VERSION 5.8 ;
BUSBITCHARS "[]" ;
DIVIDERCHAR "/" ;
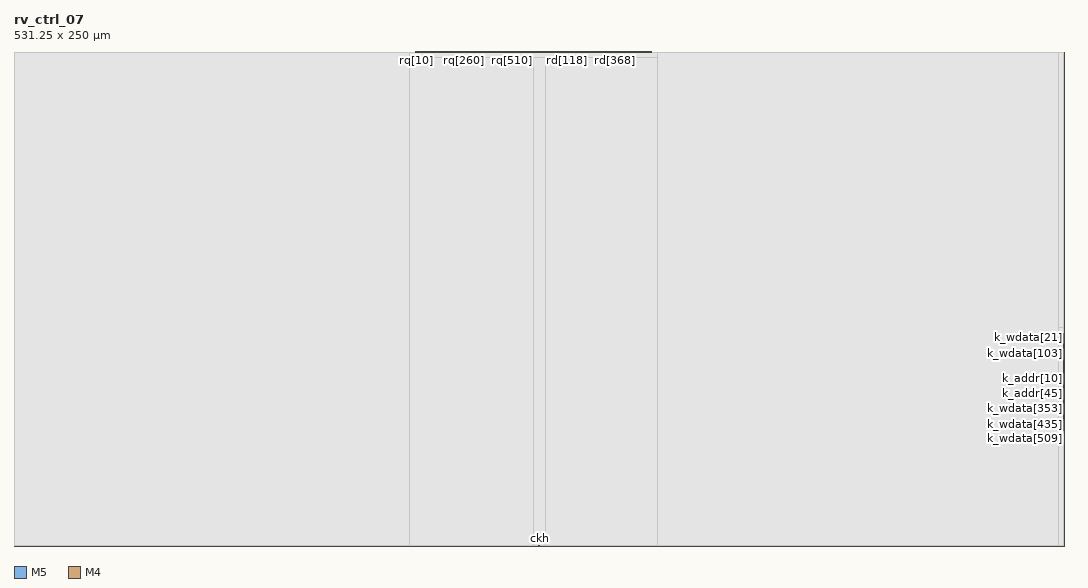
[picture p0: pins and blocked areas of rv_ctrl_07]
MACRO rv_ctrl_07
  CLASS BLOCK ;
  ORIGIN 0 0 ;
  SIZE 531.250 BY 250.000 ;
  SYMMETRY X Y ;
  PIN clk
    DIRECTION INPUT ;
    USE SIGNAL ;
    PORT
      LAYER M5 ;
        RECT 265.901 0.000 265.925 0.100 ;
    END
  END clk
  PIN ckh
    DIRECTION INPUT ;
    USE SIGNAL ;
    PORT
      LAYER M5 ;
        RECT 265.997 0.000 266.021 0.100 ;
    END
  END ckh
  PIN k_v[1]
    DIRECTION OUTPUT ;
    USE SIGNAL ;
    PORT
      LAYER M4 ;
        RECT 531.150 82.745 531.250 82.769 ;
    END
  END k_v[1]
  PIN k_v[0]
    DIRECTION OUTPUT ;
    USE SIGNAL ;
    PORT
      LAYER M4 ;
        RECT 531.150 82.841 531.250 82.865 ;
    END
  END k_v[0]
  PIN k_rdy[1]
    DIRECTION INPUT ;
    USE SIGNAL ;
    PORT
      LAYER M4 ;
        RECT 531.150 82.745 531.250 82.769 ;
    END
  END k_rdy[1]
  PIN k_rdy[0]
    DIRECTION INPUT ;
    USE SIGNAL ;
    PORT
      LAYER M4 ;
        RECT 531.150 82.841 531.250 82.865 ;
    END
  END k_rdy[0]
  PIN k_addr[59]
    DIRECTION OUTPUT ;
    USE SIGNAL ;
    PORT
      LAYER M4 ;
        RECT 531.150 79.961 531.250 79.985 ;
    END
  END k_addr[59]
  PIN k_addr[58]
    DIRECTION OUTPUT ;
    USE SIGNAL ;
    PORT
      LAYER M4 ;
        RECT 531.150 80.057 531.250 80.081 ;
    END
  END k_addr[58]
  PIN k_addr[57]
    DIRECTION OUTPUT ;
    USE SIGNAL ;
    PORT
      LAYER M4 ;
        RECT 531.150 80.153 531.250 80.177 ;
    END
  END k_addr[57]
  PIN k_addr[56]
    DIRECTION OUTPUT ;
    USE SIGNAL ;
    PORT
      LAYER M4 ;
        RECT 531.150 80.249 531.250 80.273 ;
    END
  END k_addr[56]
  PIN k_addr[55]
    DIRECTION OUTPUT ;
    USE SIGNAL ;
    PORT
      LAYER M4 ;
        RECT 531.150 80.345 531.250 80.369 ;
    END
  END k_addr[55]
  PIN k_addr[54]
    DIRECTION OUTPUT ;
    USE SIGNAL ;
    PORT
      LAYER M4 ;
        RECT 531.150 80.441 531.250 80.465 ;
    END
  END k_addr[54]
  PIN k_addr[53]
    DIRECTION OUTPUT ;
    USE SIGNAL ;
    PORT
      LAYER M4 ;
        RECT 531.150 80.537 531.250 80.561 ;
    END
  END k_addr[53]
  PIN k_addr[52]
    DIRECTION OUTPUT ;
    USE SIGNAL ;
    PORT
      LAYER M4 ;
        RECT 531.150 80.633 531.250 80.657 ;
    END
  END k_addr[52]
  PIN k_addr[51]
    DIRECTION OUTPUT ;
    USE SIGNAL ;
    PORT
      LAYER M4 ;
        RECT 531.150 80.729 531.250 80.753 ;
    END
  END k_addr[51]
  PIN k_addr[50]
    DIRECTION OUTPUT ;
    USE SIGNAL ;
    PORT
      LAYER M4 ;
        RECT 531.150 80.825 531.250 80.849 ;
    END
  END k_addr[50]
  PIN k_addr[49]
    DIRECTION OUTPUT ;
    USE SIGNAL ;
    PORT
      LAYER M4 ;
        RECT 531.150 80.921 531.250 80.945 ;
    END
  END k_addr[49]
  PIN k_addr[48]
    DIRECTION OUTPUT ;
    USE SIGNAL ;
    PORT
      LAYER M4 ;
        RECT 531.150 81.017 531.250 81.041 ;
    END
  END k_addr[48]
  PIN k_addr[47]
    DIRECTION OUTPUT ;
    USE SIGNAL ;
    PORT
      LAYER M4 ;
        RECT 531.150 81.113 531.250 81.137 ;
    END
  END k_addr[47]
  PIN k_addr[46]
    DIRECTION OUTPUT ;
    USE SIGNAL ;
    PORT
      LAYER M4 ;
        RECT 531.150 81.209 531.250 81.233 ;
    END
  END k_addr[46]
  PIN k_addr[45]
    DIRECTION OUTPUT ;
    USE SIGNAL ;
    PORT
      LAYER M4 ;
        RECT 531.150 81.305 531.250 81.329 ;
    END
  END k_addr[45]
  PIN k_addr[44]
    DIRECTION OUTPUT ;
    USE SIGNAL ;
    PORT
      LAYER M4 ;
        RECT 531.150 81.401 531.250 81.425 ;
    END
  END k_addr[44]
  PIN k_addr[43]
    DIRECTION OUTPUT ;
    USE SIGNAL ;
    PORT
      LAYER M4 ;
        RECT 531.150 81.497 531.250 81.521 ;
    END
  END k_addr[43]
  PIN k_addr[42]
    DIRECTION OUTPUT ;
    USE SIGNAL ;
    PORT
      LAYER M4 ;
        RECT 531.150 81.593 531.250 81.617 ;
    END
  END k_addr[42]
  PIN k_addr[41]
    DIRECTION OUTPUT ;
    USE SIGNAL ;
    PORT
      LAYER M4 ;
        RECT 531.150 81.689 531.250 81.713 ;
    END
  END k_addr[41]
  PIN k_addr[40]
    DIRECTION OUTPUT ;
    USE SIGNAL ;
    PORT
      LAYER M4 ;
        RECT 531.150 81.785 531.250 81.809 ;
    END
  END k_addr[40]
  PIN k_addr[39]
    DIRECTION OUTPUT ;
    USE SIGNAL ;
    PORT
      LAYER M4 ;
        RECT 531.150 81.881 531.250 81.905 ;
    END
  END k_addr[39]
  PIN k_addr[38]
    DIRECTION OUTPUT ;
    USE SIGNAL ;
    PORT
      LAYER M4 ;
        RECT 531.150 81.977 531.250 82.001 ;
    END
  END k_addr[38]
  PIN k_addr[37]
    DIRECTION OUTPUT ;
    USE SIGNAL ;
    PORT
      LAYER M4 ;
        RECT 531.150 82.073 531.250 82.097 ;
    END
  END k_addr[37]
  PIN k_addr[36]
    DIRECTION OUTPUT ;
    USE SIGNAL ;
    PORT
      LAYER M4 ;
        RECT 531.150 82.169 531.250 82.193 ;
    END
  END k_addr[36]
  PIN k_addr[35]
    DIRECTION OUTPUT ;
    USE SIGNAL ;
    PORT
      LAYER M4 ;
        RECT 531.150 82.265 531.250 82.289 ;
    END
  END k_addr[35]
  PIN k_addr[34]
    DIRECTION OUTPUT ;
    USE SIGNAL ;
    PORT
      LAYER M4 ;
        RECT 531.150 82.361 531.250 82.385 ;
    END
  END k_addr[34]
  PIN k_addr[33]
    DIRECTION OUTPUT ;
    USE SIGNAL ;
    PORT
      LAYER M4 ;
        RECT 531.150 82.457 531.250 82.481 ;
    END
  END k_addr[33]
  PIN k_addr[32]
    DIRECTION OUTPUT ;
    USE SIGNAL ;
    PORT
      LAYER M4 ;
        RECT 531.150 82.553 531.250 82.577 ;
    END
  END k_addr[32]
  PIN k_addr[31]
    DIRECTION OUTPUT ;
    USE SIGNAL ;
    PORT
      LAYER M4 ;
        RECT 531.150 82.649 531.250 82.673 ;
    END
  END k_addr[31]
  PIN k_addr[30]
    DIRECTION OUTPUT ;
    USE SIGNAL ;
    PORT
      LAYER M4 ;
        RECT 531.150 82.745 531.250 82.769 ;
    END
  END k_addr[30]
  PIN k_addr[29]
    DIRECTION OUTPUT ;
    USE SIGNAL ;
    PORT
      LAYER M4 ;
        RECT 531.150 82.841 531.250 82.865 ;
    END
  END k_addr[29]
  PIN k_addr[28]
    DIRECTION OUTPUT ;
    USE SIGNAL ;
    PORT
      LAYER M4 ;
        RECT 531.150 82.937 531.250 82.961 ;
    END
  END k_addr[28]
  PIN k_addr[27]
    DIRECTION OUTPUT ;
    USE SIGNAL ;
    PORT
      LAYER M4 ;
        RECT 531.150 83.033 531.250 83.057 ;
    END
  END k_addr[27]
  PIN k_addr[26]
    DIRECTION OUTPUT ;
    USE SIGNAL ;
    PORT
      LAYER M4 ;
        RECT 531.150 83.129 531.250 83.153 ;
    END
  END k_addr[26]
  PIN k_addr[25]
    DIRECTION OUTPUT ;
    USE SIGNAL ;
    PORT
      LAYER M4 ;
        RECT 531.150 83.225 531.250 83.249 ;
    END
  END k_addr[25]
  PIN k_addr[24]
    DIRECTION OUTPUT ;
    USE SIGNAL ;
    PORT
      LAYER M4 ;
        RECT 531.150 83.321 531.250 83.345 ;
    END
  END k_addr[24]
  PIN k_addr[23]
    DIRECTION OUTPUT ;
    USE SIGNAL ;
    PORT
      LAYER M4 ;
        RECT 531.150 83.417 531.250 83.441 ;
    END
  END k_addr[23]
  PIN k_addr[22]
    DIRECTION OUTPUT ;
    USE SIGNAL ;
    PORT
      LAYER M4 ;
        RECT 531.150 83.513 531.250 83.537 ;
    END
  END k_addr[22]
  PIN k_addr[21]
    DIRECTION OUTPUT ;
    USE SIGNAL ;
    PORT
      LAYER M4 ;
        RECT 531.150 83.609 531.250 83.633 ;
    END
  END k_addr[21]
  PIN k_addr[20]
    DIRECTION OUTPUT ;
    USE SIGNAL ;
    PORT
      LAYER M4 ;
        RECT 531.150 83.705 531.250 83.729 ;
    END
  END k_addr[20]
  PIN k_addr[19]
    DIRECTION OUTPUT ;
    USE SIGNAL ;
    PORT
      LAYER M4 ;
        RECT 531.150 83.801 531.250 83.825 ;
    END
  END k_addr[19]
  PIN k_addr[18]
    DIRECTION OUTPUT ;
    USE SIGNAL ;
    PORT
      LAYER M4 ;
        RECT 531.150 83.897 531.250 83.921 ;
    END
  END k_addr[18]
  PIN k_addr[17]
    DIRECTION OUTPUT ;
    USE SIGNAL ;
    PORT
      LAYER M4 ;
        RECT 531.150 83.993 531.250 84.017 ;
    END
  END k_addr[17]
  PIN k_addr[16]
    DIRECTION OUTPUT ;
    USE SIGNAL ;
    PORT
      LAYER M4 ;
        RECT 531.150 84.089 531.250 84.113 ;
    END
  END k_addr[16]
  PIN k_addr[15]
    DIRECTION OUTPUT ;
    USE SIGNAL ;
    PORT
      LAYER M4 ;
        RECT 531.150 84.185 531.250 84.209 ;
    END
  END k_addr[15]
  PIN k_addr[14]
    DIRECTION OUTPUT ;
    USE SIGNAL ;
    PORT
      LAYER M4 ;
        RECT 531.150 84.281 531.250 84.305 ;
    END
  END k_addr[14]
  PIN k_addr[13]
    DIRECTION OUTPUT ;
    USE SIGNAL ;
    PORT
      LAYER M4 ;
        RECT 531.150 84.377 531.250 84.401 ;
    END
  END k_addr[13]
  PIN k_addr[12]
    DIRECTION OUTPUT ;
    USE SIGNAL ;
    PORT
      LAYER M4 ;
        RECT 531.150 84.473 531.250 84.497 ;
    END
  END k_addr[12]
  PIN k_addr[11]
    DIRECTION OUTPUT ;
    USE SIGNAL ;
    PORT
      LAYER M4 ;
        RECT 531.150 84.569 531.250 84.593 ;
    END
  END k_addr[11]
  PIN k_addr[10]
    DIRECTION OUTPUT ;
    USE SIGNAL ;
    PORT
      LAYER M4 ;
        RECT 531.150 84.665 531.250 84.689 ;
    END
  END k_addr[10]
  PIN k_addr[9]
    DIRECTION OUTPUT ;
    USE SIGNAL ;
    PORT
      LAYER M4 ;
        RECT 531.150 84.761 531.250 84.785 ;
    END
  END k_addr[9]
  PIN k_addr[8]
    DIRECTION OUTPUT ;
    USE SIGNAL ;
    PORT
      LAYER M4 ;
        RECT 531.150 84.857 531.250 84.881 ;
    END
  END k_addr[8]
  PIN k_addr[7]
    DIRECTION OUTPUT ;
    USE SIGNAL ;
    PORT
      LAYER M4 ;
        RECT 531.150 84.953 531.250 84.977 ;
    END
  END k_addr[7]
  PIN k_addr[6]
    DIRECTION OUTPUT ;
    USE SIGNAL ;
    PORT
      LAYER M4 ;
        RECT 531.150 85.049 531.250 85.073 ;
    END
  END k_addr[6]
  PIN k_addr[5]
    DIRECTION OUTPUT ;
    USE SIGNAL ;
    PORT
      LAYER M4 ;
        RECT 531.150 85.145 531.250 85.169 ;
    END
  END k_addr[5]
  PIN k_addr[4]
    DIRECTION OUTPUT ;
    USE SIGNAL ;
    PORT
      LAYER M4 ;
        RECT 531.150 85.241 531.250 85.265 ;
    END
  END k_addr[4]
  PIN k_addr[3]
    DIRECTION OUTPUT ;
    USE SIGNAL ;
    PORT
      LAYER M4 ;
        RECT 531.150 85.337 531.250 85.361 ;
    END
  END k_addr[3]
  PIN k_addr[2]
    DIRECTION OUTPUT ;
    USE SIGNAL ;
    PORT
      LAYER M4 ;
        RECT 531.150 85.433 531.250 85.457 ;
    END
  END k_addr[2]
  PIN k_addr[1]
    DIRECTION OUTPUT ;
    USE SIGNAL ;
    PORT
      LAYER M4 ;
        RECT 531.150 85.529 531.250 85.553 ;
    END
  END k_addr[1]
  PIN k_addr[0]
    DIRECTION OUTPUT ;
    USE SIGNAL ;
    PORT
      LAYER M4 ;
        RECT 531.150 85.625 531.250 85.649 ;
    END
  END k_addr[0]
  PIN k_len[7]
    DIRECTION OUTPUT ;
    USE SIGNAL ;
    PORT
      LAYER M4 ;
        RECT 531.150 82.457 531.250 82.481 ;
    END
  END k_len[7]
  PIN k_len[6]
    DIRECTION OUTPUT ;
    USE SIGNAL ;
    PORT
      LAYER M4 ;
        RECT 531.150 82.553 531.250 82.577 ;
    END
  END k_len[6]
  PIN k_len[5]
    DIRECTION OUTPUT ;
    USE SIGNAL ;
    PORT
      LAYER M4 ;
        RECT 531.150 82.649 531.250 82.673 ;
    END
  END k_len[5]
  PIN k_len[4]
    DIRECTION OUTPUT ;
    USE SIGNAL ;
    PORT
      LAYER M4 ;
        RECT 531.150 82.745 531.250 82.769 ;
    END
  END k_len[4]
  PIN k_len[3]
    DIRECTION OUTPUT ;
    USE SIGNAL ;
    PORT
      LAYER M4 ;
        RECT 531.150 82.841 531.250 82.865 ;
    END
  END k_len[3]
  PIN k_len[2]
    DIRECTION OUTPUT ;
    USE SIGNAL ;
    PORT
      LAYER M4 ;
        RECT 531.150 82.937 531.250 82.961 ;
    END
  END k_len[2]
  PIN k_len[1]
    DIRECTION OUTPUT ;
    USE SIGNAL ;
    PORT
      LAYER M4 ;
        RECT 531.150 83.033 531.250 83.057 ;
    END
  END k_len[1]
  PIN k_len[0]
    DIRECTION OUTPUT ;
    USE SIGNAL ;
    PORT
      LAYER M4 ;
        RECT 531.150 83.129 531.250 83.153 ;
    END
  END k_len[0]
  PIN k_tag[33]
    DIRECTION OUTPUT ;
    USE SIGNAL ;
    PORT
      LAYER M4 ;
        RECT 531.150 81.209 531.250 81.233 ;
    END
  END k_tag[33]
  PIN k_tag[32]
    DIRECTION OUTPUT ;
    USE SIGNAL ;
    PORT
      LAYER M4 ;
        RECT 531.150 81.305 531.250 81.329 ;
    END
  END k_tag[32]
  PIN k_tag[31]
    DIRECTION OUTPUT ;
    USE SIGNAL ;
    PORT
      LAYER M4 ;
        RECT 531.150 81.401 531.250 81.425 ;
    END
  END k_tag[31]
  PIN k_tag[30]
    DIRECTION OUTPUT ;
    USE SIGNAL ;
    PORT
      LAYER M4 ;
        RECT 531.150 81.497 531.250 81.521 ;
    END
  END k_tag[30]
  PIN k_tag[29]
    DIRECTION OUTPUT ;
    USE SIGNAL ;
    PORT
      LAYER M4 ;
        RECT 531.150 81.593 531.250 81.617 ;
    END
  END k_tag[29]
  PIN k_tag[28]
    DIRECTION OUTPUT ;
    USE SIGNAL ;
    PORT
      LAYER M4 ;
        RECT 531.150 81.689 531.250 81.713 ;
    END
  END k_tag[28]
  PIN k_tag[27]
    DIRECTION OUTPUT ;
    USE SIGNAL ;
    PORT
      LAYER M4 ;
        RECT 531.150 81.785 531.250 81.809 ;
    END
  END k_tag[27]
  PIN k_tag[26]
    DIRECTION OUTPUT ;
    USE SIGNAL ;
    PORT
      LAYER M4 ;
        RECT 531.150 81.881 531.250 81.905 ;
    END
  END k_tag[26]
  PIN k_tag[25]
    DIRECTION OUTPUT ;
    USE SIGNAL ;
    PORT
      LAYER M4 ;
        RECT 531.150 81.977 531.250 82.001 ;
    END
  END k_tag[25]
  PIN k_tag[24]
    DIRECTION OUTPUT ;
    USE SIGNAL ;
    PORT
      LAYER M4 ;
        RECT 531.150 82.073 531.250 82.097 ;
    END
  END k_tag[24]
  PIN k_tag[23]
    DIRECTION OUTPUT ;
    USE SIGNAL ;
    PORT
      LAYER M4 ;
        RECT 531.150 82.169 531.250 82.193 ;
    END
  END k_tag[23]
  PIN k_tag[22]
    DIRECTION OUTPUT ;
    USE SIGNAL ;
    PORT
      LAYER M4 ;
        RECT 531.150 82.265 531.250 82.289 ;
    END
  END k_tag[22]
  PIN k_tag[21]
    DIRECTION OUTPUT ;
    USE SIGNAL ;
    PORT
      LAYER M4 ;
        RECT 531.150 82.361 531.250 82.385 ;
    END
  END k_tag[21]
  PIN k_tag[20]
    DIRECTION OUTPUT ;
    USE SIGNAL ;
    PORT
      LAYER M4 ;
        RECT 531.150 82.457 531.250 82.481 ;
    END
  END k_tag[20]
  PIN k_tag[19]
    DIRECTION OUTPUT ;
    USE SIGNAL ;
    PORT
      LAYER M4 ;
        RECT 531.150 82.553 531.250 82.577 ;
    END
  END k_tag[19]
  PIN k_tag[18]
    DIRECTION OUTPUT ;
    USE SIGNAL ;
    PORT
      LAYER M4 ;
        RECT 531.150 82.649 531.250 82.673 ;
    END
  END k_tag[18]
  PIN k_tag[17]
    DIRECTION OUTPUT ;
    USE SIGNAL ;
    PORT
      LAYER M4 ;
        RECT 531.150 82.745 531.250 82.769 ;
    END
  END k_tag[17]
  PIN k_tag[16]
    DIRECTION OUTPUT ;
    USE SIGNAL ;
    PORT
      LAYER M4 ;
        RECT 531.150 82.841 531.250 82.865 ;
    END
  END k_tag[16]
  PIN k_tag[15]
    DIRECTION OUTPUT ;
    USE SIGNAL ;
    PORT
      LAYER M4 ;
        RECT 531.150 82.937 531.250 82.961 ;
    END
  END k_tag[15]
  PIN k_tag[14]
    DIRECTION OUTPUT ;
    USE SIGNAL ;
    PORT
      LAYER M4 ;
        RECT 531.150 83.033 531.250 83.057 ;
    END
  END k_tag[14]
  PIN k_tag[13]
    DIRECTION OUTPUT ;
    USE SIGNAL ;
    PORT
      LAYER M4 ;
        RECT 531.150 83.129 531.250 83.153 ;
    END
  END k_tag[13]
  PIN k_tag[12]
    DIRECTION OUTPUT ;
    USE SIGNAL ;
    PORT
      LAYER M4 ;
        RECT 531.150 83.225 531.250 83.249 ;
    END
  END k_tag[12]
  PIN k_tag[11]
    DIRECTION OUTPUT ;
    USE SIGNAL ;
    PORT
      LAYER M4 ;
        RECT 531.150 83.321 531.250 83.345 ;
    END
  END k_tag[11]
  PIN k_tag[10]
    DIRECTION OUTPUT ;
    USE SIGNAL ;
    PORT
      LAYER M4 ;
        RECT 531.150 83.417 531.250 83.441 ;
    END
  END k_tag[10]
  PIN k_tag[9]
    DIRECTION OUTPUT ;
    USE SIGNAL ;
    PORT
      LAYER M4 ;
        RECT 531.150 83.513 531.250 83.537 ;
    END
  END k_tag[9]
  PIN k_tag[8]
    DIRECTION OUTPUT ;
    USE SIGNAL ;
    PORT
      LAYER M4 ;
        RECT 531.150 83.609 531.250 83.633 ;
    END
  END k_tag[8]
  PIN k_tag[7]
    DIRECTION OUTPUT ;
    USE SIGNAL ;
    PORT
      LAYER M4 ;
        RECT 531.150 83.705 531.250 83.729 ;
    END
  END k_tag[7]
  PIN k_tag[6]
    DIRECTION OUTPUT ;
    USE SIGNAL ;
    PORT
      LAYER M4 ;
        RECT 531.150 83.801 531.250 83.825 ;
    END
  END k_tag[6]
  PIN k_tag[5]
    DIRECTION OUTPUT ;
    USE SIGNAL ;
    PORT
      LAYER M4 ;
        RECT 531.150 83.897 531.250 83.921 ;
    END
  END k_tag[5]
  PIN k_tag[4]
    DIRECTION OUTPUT ;
    USE SIGNAL ;
    PORT
      LAYER M4 ;
        RECT 531.150 83.993 531.250 84.017 ;
    END
  END k_tag[4]
  PIN k_tag[3]
    DIRECTION OUTPUT ;
    USE SIGNAL ;
    PORT
      LAYER M4 ;
        RECT 531.150 84.089 531.250 84.113 ;
    END
  END k_tag[3]
  PIN k_tag[2]
    DIRECTION OUTPUT ;
    USE SIGNAL ;
    PORT
      LAYER M4 ;
        RECT 531.150 84.185 531.250 84.209 ;
    END
  END k_tag[2]
  PIN k_tag[1]
    DIRECTION OUTPUT ;
    USE SIGNAL ;
    PORT
      LAYER M4 ;
        RECT 531.150 84.281 531.250 84.305 ;
    END
  END k_tag[1]
  PIN k_tag[0]
    DIRECTION OUTPUT ;
    USE SIGNAL ;
    PORT
      LAYER M4 ;
        RECT 531.150 84.377 531.250 84.401 ;
    END
  END k_tag[0]
  PIN k_we[1]
    DIRECTION OUTPUT ;
    USE SIGNAL ;
    PORT
      LAYER M4 ;
        RECT 531.150 82.745 531.250 82.769 ;
    END
  END k_we[1]
  PIN k_we[0]
    DIRECTION OUTPUT ;
    USE SIGNAL ;
    PORT
      LAYER M4 ;
        RECT 531.150 82.841 531.250 82.865 ;
    END
  END k_we[0]
  PIN k_wdata[511]
    DIRECTION OUTPUT ;
    USE SIGNAL ;
    PORT
      LAYER M4 ;
        RECT 531.150 58.265 531.250 58.289 ;
    END
  END k_wdata[511]
  PIN k_wdata[510]
    DIRECTION OUTPUT ;
    USE SIGNAL ;
    PORT
      LAYER M4 ;
        RECT 531.150 58.361 531.250 58.385 ;
    END
  END k_wdata[510]
  PIN k_wdata[509]
    DIRECTION OUTPUT ;
    USE SIGNAL ;
    PORT
      LAYER M4 ;
        RECT 531.150 58.457 531.250 58.481 ;
    END
  END k_wdata[509]
  PIN k_wdata[508]
    DIRECTION OUTPUT ;
    USE SIGNAL ;
    PORT
      LAYER M4 ;
        RECT 531.150 58.553 531.250 58.577 ;
    END
  END k_wdata[508]
  PIN k_wdata[507]
    DIRECTION OUTPUT ;
    USE SIGNAL ;
    PORT
      LAYER M4 ;
        RECT 531.150 58.649 531.250 58.673 ;
    END
  END k_wdata[507]
  PIN k_wdata[506]
    DIRECTION OUTPUT ;
    USE SIGNAL ;
    PORT
      LAYER M4 ;
        RECT 531.150 58.745 531.250 58.769 ;
    END
  END k_wdata[506]
  PIN k_wdata[505]
    DIRECTION OUTPUT ;
    USE SIGNAL ;
    PORT
      LAYER M4 ;
        RECT 531.150 58.841 531.250 58.865 ;
    END
  END k_wdata[505]
  PIN k_wdata[504]
    DIRECTION OUTPUT ;
    USE SIGNAL ;
    PORT
      LAYER M4 ;
        RECT 531.150 58.937 531.250 58.961 ;
    END
  END k_wdata[504]
  PIN k_wdata[503]
    DIRECTION OUTPUT ;
    USE SIGNAL ;
    PORT
      LAYER M4 ;
        RECT 531.150 59.033 531.250 59.057 ;
    END
  END k_wdata[503]
  PIN k_wdata[502]
    DIRECTION OUTPUT ;
    USE SIGNAL ;
    PORT
      LAYER M4 ;
        RECT 531.150 59.129 531.250 59.153 ;
    END
  END k_wdata[502]
  PIN k_wdata[501]
    DIRECTION OUTPUT ;
    USE SIGNAL ;
    PORT
      LAYER M4 ;
        RECT 531.150 59.225 531.250 59.249 ;
    END
  END k_wdata[501]
  PIN k_wdata[500]
    DIRECTION OUTPUT ;
    USE SIGNAL ;
    PORT
      LAYER M4 ;
        RECT 531.150 59.321 531.250 59.345 ;
    END
  END k_wdata[500]
  PIN k_wdata[499]
    DIRECTION OUTPUT ;
    USE SIGNAL ;
    PORT
      LAYER M4 ;
        RECT 531.150 59.417 531.250 59.441 ;
    END
  END k_wdata[499]
  PIN k_wdata[498]
    DIRECTION OUTPUT ;
    USE SIGNAL ;
    PORT
      LAYER M4 ;
        RECT 531.150 59.513 531.250 59.537 ;
    END
  END k_wdata[498]
  PIN k_wdata[497]
    DIRECTION OUTPUT ;
    USE SIGNAL ;
    PORT
      LAYER M4 ;
        RECT 531.150 59.609 531.250 59.633 ;
    END
  END k_wdata[497]
  PIN k_wdata[496]
    DIRECTION OUTPUT ;
    USE SIGNAL ;
    PORT
      LAYER M4 ;
        RECT 531.150 59.705 531.250 59.729 ;
    END
  END k_wdata[496]
  PIN k_wdata[495]
    DIRECTION OUTPUT ;
    USE SIGNAL ;
    PORT
      LAYER M4 ;
        RECT 531.150 59.801 531.250 59.825 ;
    END
  END k_wdata[495]
  PIN k_wdata[494]
    DIRECTION OUTPUT ;
    USE SIGNAL ;
    PORT
      LAYER M4 ;
        RECT 531.150 59.897 531.250 59.921 ;
    END
  END k_wdata[494]
  PIN k_wdata[493]
    DIRECTION OUTPUT ;
    USE SIGNAL ;
    PORT
      LAYER M4 ;
        RECT 531.150 59.993 531.250 60.017 ;
    END
  END k_wdata[493]
  PIN k_wdata[492]
    DIRECTION OUTPUT ;
    USE SIGNAL ;
    PORT
      LAYER M4 ;
        RECT 531.150 60.089 531.250 60.113 ;
    END
  END k_wdata[492]
  PIN k_wdata[491]
    DIRECTION OUTPUT ;
    USE SIGNAL ;
    PORT
      LAYER M4 ;
        RECT 531.150 60.185 531.250 60.209 ;
    END
  END k_wdata[491]
  PIN k_wdata[490]
    DIRECTION OUTPUT ;
    USE SIGNAL ;
    PORT
      LAYER M4 ;
        RECT 531.150 60.281 531.250 60.305 ;
    END
  END k_wdata[490]
  PIN k_wdata[489]
    DIRECTION OUTPUT ;
    USE SIGNAL ;
    PORT
      LAYER M4 ;
        RECT 531.150 60.377 531.250 60.401 ;
    END
  END k_wdata[489]
  PIN k_wdata[488]
    DIRECTION OUTPUT ;
    USE SIGNAL ;
    PORT
      LAYER M4 ;
        RECT 531.150 60.473 531.250 60.497 ;
    END
  END k_wdata[488]
  PIN k_wdata[487]
    DIRECTION OUTPUT ;
    USE SIGNAL ;
    PORT
      LAYER M4 ;
        RECT 531.150 60.569 531.250 60.593 ;
    END
  END k_wdata[487]
  PIN k_wdata[486]
    DIRECTION OUTPUT ;
    USE SIGNAL ;
    PORT
      LAYER M4 ;
        RECT 531.150 60.665 531.250 60.689 ;
    END
  END k_wdata[486]
  PIN k_wdata[485]
    DIRECTION OUTPUT ;
    USE SIGNAL ;
    PORT
      LAYER M4 ;
        RECT 531.150 60.761 531.250 60.785 ;
    END
  END k_wdata[485]
  PIN k_wdata[484]
    DIRECTION OUTPUT ;
    USE SIGNAL ;
    PORT
      LAYER M4 ;
        RECT 531.150 60.857 531.250 60.881 ;
    END
  END k_wdata[484]
  PIN k_wdata[483]
    DIRECTION OUTPUT ;
    USE SIGNAL ;
    PORT
      LAYER M4 ;
        RECT 531.150 60.953 531.250 60.977 ;
    END
  END k_wdata[483]
  PIN k_wdata[482]
    DIRECTION OUTPUT ;
    USE SIGNAL ;
    PORT
      LAYER M4 ;
        RECT 531.150 61.049 531.250 61.073 ;
    END
  END k_wdata[482]
  PIN k_wdata[481]
    DIRECTION OUTPUT ;
    USE SIGNAL ;
    PORT
      LAYER M4 ;
        RECT 531.150 61.145 531.250 61.169 ;
    END
  END k_wdata[481]
  PIN k_wdata[480]
    DIRECTION OUTPUT ;
    USE SIGNAL ;
    PORT
      LAYER M4 ;
        RECT 531.150 61.241 531.250 61.265 ;
    END
  END k_wdata[480]
  PIN k_wdata[479]
    DIRECTION OUTPUT ;
    USE SIGNAL ;
    PORT
      LAYER M4 ;
        RECT 531.150 61.337 531.250 61.361 ;
    END
  END k_wdata[479]
  PIN k_wdata[478]
    DIRECTION OUTPUT ;
    USE SIGNAL ;
    PORT
      LAYER M4 ;
        RECT 531.150 61.433 531.250 61.457 ;
    END
  END k_wdata[478]
  PIN k_wdata[477]
    DIRECTION OUTPUT ;
    USE SIGNAL ;
    PORT
      LAYER M4 ;
        RECT 531.150 61.529 531.250 61.553 ;
    END
  END k_wdata[477]
  PIN k_wdata[476]
    DIRECTION OUTPUT ;
    USE SIGNAL ;
    PORT
      LAYER M4 ;
        RECT 531.150 61.625 531.250 61.649 ;
    END
  END k_wdata[476]
  PIN k_wdata[475]
    DIRECTION OUTPUT ;
    USE SIGNAL ;
    PORT
      LAYER M4 ;
        RECT 531.150 61.721 531.250 61.745 ;
    END
  END k_wdata[475]
  PIN k_wdata[474]
    DIRECTION OUTPUT ;
    USE SIGNAL ;
    PORT
      LAYER M4 ;
        RECT 531.150 61.817 531.250 61.841 ;
    END
  END k_wdata[474]
  PIN k_wdata[473]
    DIRECTION OUTPUT ;
    USE SIGNAL ;
    PORT
      LAYER M4 ;
        RECT 531.150 61.913 531.250 61.937 ;
    END
  END k_wdata[473]
  PIN k_wdata[472]
    DIRECTION OUTPUT ;
    USE SIGNAL ;
    PORT
      LAYER M4 ;
        RECT 531.150 62.009 531.250 62.033 ;
    END
  END k_wdata[472]
  PIN k_wdata[471]
    DIRECTION OUTPUT ;
    USE SIGNAL ;
    PORT
      LAYER M4 ;
        RECT 531.150 62.105 531.250 62.129 ;
    END
  END k_wdata[471]
  PIN k_wdata[470]
    DIRECTION OUTPUT ;
    USE SIGNAL ;
    PORT
      LAYER M4 ;
        RECT 531.150 62.201 531.250 62.225 ;
    END
  END k_wdata[470]
  PIN k_wdata[469]
    DIRECTION OUTPUT ;
    USE SIGNAL ;
    PORT
      LAYER M4 ;
        RECT 531.150 62.297 531.250 62.321 ;
    END
  END k_wdata[469]
  PIN k_wdata[468]
    DIRECTION OUTPUT ;
    USE SIGNAL ;
    PORT
      LAYER M4 ;
        RECT 531.150 62.393 531.250 62.417 ;
    END
  END k_wdata[468]
  PIN k_wdata[467]
    DIRECTION OUTPUT ;
    USE SIGNAL ;
    PORT
      LAYER M4 ;
        RECT 531.150 62.489 531.250 62.513 ;
    END
  END k_wdata[467]
  PIN k_wdata[466]
    DIRECTION OUTPUT ;
    USE SIGNAL ;
    PORT
      LAYER M4 ;
        RECT 531.150 62.585 531.250 62.609 ;
    END
  END k_wdata[466]
  PIN k_wdata[465]
    DIRECTION OUTPUT ;
    USE SIGNAL ;
    PORT
      LAYER M4 ;
        RECT 531.150 62.681 531.250 62.705 ;
    END
  END k_wdata[465]
  PIN k_wdata[464]
    DIRECTION OUTPUT ;
    USE SIGNAL ;
    PORT
      LAYER M4 ;
        RECT 531.150 62.777 531.250 62.801 ;
    END
  END k_wdata[464]
  PIN k_wdata[463]
    DIRECTION OUTPUT ;
    USE SIGNAL ;
    PORT
      LAYER M4 ;
        RECT 531.150 62.873 531.250 62.897 ;
    END
  END k_wdata[463]
  PIN k_wdata[462]
    DIRECTION OUTPUT ;
    USE SIGNAL ;
    PORT
      LAYER M4 ;
        RECT 531.150 62.969 531.250 62.993 ;
    END
  END k_wdata[462]
  PIN k_wdata[461]
    DIRECTION OUTPUT ;
    USE SIGNAL ;
    PORT
      LAYER M4 ;
        RECT 531.150 63.065 531.250 63.089 ;
    END
  END k_wdata[461]
  PIN k_wdata[460]
    DIRECTION OUTPUT ;
    USE SIGNAL ;
    PORT
      LAYER M4 ;
        RECT 531.150 63.161 531.250 63.185 ;
    END
  END k_wdata[460]
  PIN k_wdata[459]
    DIRECTION OUTPUT ;
    USE SIGNAL ;
    PORT
      LAYER M4 ;
        RECT 531.150 63.257 531.250 63.281 ;
    END
  END k_wdata[459]
  PIN k_wdata[458]
    DIRECTION OUTPUT ;
    USE SIGNAL ;
    PORT
      LAYER M4 ;
        RECT 531.150 63.353 531.250 63.377 ;
    END
  END k_wdata[458]
  PIN k_wdata[457]
    DIRECTION OUTPUT ;
    USE SIGNAL ;
    PORT
      LAYER M4 ;
        RECT 531.150 63.449 531.250 63.473 ;
    END
  END k_wdata[457]
  PIN k_wdata[456]
    DIRECTION OUTPUT ;
    USE SIGNAL ;
    PORT
      LAYER M4 ;
        RECT 531.150 63.545 531.250 63.569 ;
    END
  END k_wdata[456]
  PIN k_wdata[455]
    DIRECTION OUTPUT ;
    USE SIGNAL ;
    PORT
      LAYER M4 ;
        RECT 531.150 63.641 531.250 63.665 ;
    END
  END k_wdata[455]
  PIN k_wdata[454]
    DIRECTION OUTPUT ;
    USE SIGNAL ;
    PORT
      LAYER M4 ;
        RECT 531.150 63.737 531.250 63.761 ;
    END
  END k_wdata[454]
  PIN k_wdata[453]
    DIRECTION OUTPUT ;
    USE SIGNAL ;
    PORT
      LAYER M4 ;
        RECT 531.150 63.833 531.250 63.857 ;
    END
  END k_wdata[453]
  PIN k_wdata[452]
    DIRECTION OUTPUT ;
    USE SIGNAL ;
    PORT
      LAYER M4 ;
        RECT 531.150 63.929 531.250 63.953 ;
    END
  END k_wdata[452]
  PIN k_wdata[451]
    DIRECTION OUTPUT ;
    USE SIGNAL ;
    PORT
      LAYER M4 ;
        RECT 531.150 64.025 531.250 64.049 ;
    END
  END k_wdata[451]
  PIN k_wdata[450]
    DIRECTION OUTPUT ;
    USE SIGNAL ;
    PORT
      LAYER M4 ;
        RECT 531.150 64.121 531.250 64.145 ;
    END
  END k_wdata[450]
  PIN k_wdata[449]
    DIRECTION OUTPUT ;
    USE SIGNAL ;
    PORT
      LAYER M4 ;
        RECT 531.150 64.217 531.250 64.241 ;
    END
  END k_wdata[449]
  PIN k_wdata[448]
    DIRECTION OUTPUT ;
    USE SIGNAL ;
    PORT
      LAYER M4 ;
        RECT 531.150 64.313 531.250 64.337 ;
    END
  END k_wdata[448]
  PIN k_wdata[447]
    DIRECTION OUTPUT ;
    USE SIGNAL ;
    PORT
      LAYER M4 ;
        RECT 531.150 64.409 531.250 64.433 ;
    END
  END k_wdata[447]
  PIN k_wdata[446]
    DIRECTION OUTPUT ;
    USE SIGNAL ;
    PORT
      LAYER M4 ;
        RECT 531.150 64.505 531.250 64.529 ;
    END
  END k_wdata[446]
  PIN k_wdata[445]
    DIRECTION OUTPUT ;
    USE SIGNAL ;
    PORT
      LAYER M4 ;
        RECT 531.150 64.601 531.250 64.625 ;
    END
  END k_wdata[445]
  PIN k_wdata[444]
    DIRECTION OUTPUT ;
    USE SIGNAL ;
    PORT
      LAYER M4 ;
        RECT 531.150 64.697 531.250 64.721 ;
    END
  END k_wdata[444]
  PIN k_wdata[443]
    DIRECTION OUTPUT ;
    USE SIGNAL ;
    PORT
      LAYER M4 ;
        RECT 531.150 64.793 531.250 64.817 ;
    END
  END k_wdata[443]
  PIN k_wdata[442]
    DIRECTION OUTPUT ;
    USE SIGNAL ;
    PORT
      LAYER M4 ;
        RECT 531.150 64.889 531.250 64.913 ;
    END
  END k_wdata[442]
  PIN k_wdata[441]
    DIRECTION OUTPUT ;
    USE SIGNAL ;
    PORT
      LAYER M4 ;
        RECT 531.150 64.985 531.250 65.009 ;
    END
  END k_wdata[441]
  PIN k_wdata[440]
    DIRECTION OUTPUT ;
    USE SIGNAL ;
    PORT
      LAYER M4 ;
        RECT 531.150 65.081 531.250 65.105 ;
    END
  END k_wdata[440]
  PIN k_wdata[439]
    DIRECTION OUTPUT ;
    USE SIGNAL ;
    PORT
      LAYER M4 ;
        RECT 531.150 65.177 531.250 65.201 ;
    END
  END k_wdata[439]
  PIN k_wdata[438]
    DIRECTION OUTPUT ;
    USE SIGNAL ;
    PORT
      LAYER M4 ;
        RECT 531.150 65.273 531.250 65.297 ;
    END
  END k_wdata[438]
  PIN k_wdata[437]
    DIRECTION OUTPUT ;
    USE SIGNAL ;
    PORT
      LAYER M4 ;
        RECT 531.150 65.369 531.250 65.393 ;
    END
  END k_wdata[437]
  PIN k_wdata[436]
    DIRECTION OUTPUT ;
    USE SIGNAL ;
    PORT
      LAYER M4 ;
        RECT 531.150 65.465 531.250 65.489 ;
    END
  END k_wdata[436]
  PIN k_wdata[435]
    DIRECTION OUTPUT ;
    USE SIGNAL ;
    PORT
      LAYER M4 ;
        RECT 531.150 65.561 531.250 65.585 ;
    END
  END k_wdata[435]
  PIN k_wdata[434]
    DIRECTION OUTPUT ;
    USE SIGNAL ;
    PORT
      LAYER M4 ;
        RECT 531.150 65.657 531.250 65.681 ;
    END
  END k_wdata[434]
  PIN k_wdata[433]
    DIRECTION OUTPUT ;
    USE SIGNAL ;
    PORT
      LAYER M4 ;
        RECT 531.150 65.753 531.250 65.777 ;
    END
  END k_wdata[433]
  PIN k_wdata[432]
    DIRECTION OUTPUT ;
    USE SIGNAL ;
    PORT
      LAYER M4 ;
        RECT 531.150 65.849 531.250 65.873 ;
    END
  END k_wdata[432]
  PIN k_wdata[431]
    DIRECTION OUTPUT ;
    USE SIGNAL ;
    PORT
      LAYER M4 ;
        RECT 531.150 65.945 531.250 65.969 ;
    END
  END k_wdata[431]
  PIN k_wdata[430]
    DIRECTION OUTPUT ;
    USE SIGNAL ;
    PORT
      LAYER M4 ;
        RECT 531.150 66.041 531.250 66.065 ;
    END
  END k_wdata[430]
  PIN k_wdata[429]
    DIRECTION OUTPUT ;
    USE SIGNAL ;
    PORT
      LAYER M4 ;
        RECT 531.150 66.137 531.250 66.161 ;
    END
  END k_wdata[429]
  PIN k_wdata[428]
    DIRECTION OUTPUT ;
    USE SIGNAL ;
    PORT
      LAYER M4 ;
        RECT 531.150 66.233 531.250 66.257 ;
    END
  END k_wdata[428]
  PIN k_wdata[427]
    DIRECTION OUTPUT ;
    USE SIGNAL ;
    PORT
      LAYER M4 ;
        RECT 531.150 66.329 531.250 66.353 ;
    END
  END k_wdata[427]
  PIN k_wdata[426]
    DIRECTION OUTPUT ;
    USE SIGNAL ;
    PORT
      LAYER M4 ;
        RECT 531.150 66.425 531.250 66.449 ;
    END
  END k_wdata[426]
  PIN k_wdata[425]
    DIRECTION OUTPUT ;
    USE SIGNAL ;
    PORT
      LAYER M4 ;
        RECT 531.150 66.521 531.250 66.545 ;
    END
  END k_wdata[425]
  PIN k_wdata[424]
    DIRECTION OUTPUT ;
    USE SIGNAL ;
    PORT
      LAYER M4 ;
        RECT 531.150 66.617 531.250 66.641 ;
    END
  END k_wdata[424]
  PIN k_wdata[423]
    DIRECTION OUTPUT ;
    USE SIGNAL ;
    PORT
      LAYER M4 ;
        RECT 531.150 66.713 531.250 66.737 ;
    END
  END k_wdata[423]
  PIN k_wdata[422]
    DIRECTION OUTPUT ;
    USE SIGNAL ;
    PORT
      LAYER M4 ;
        RECT 531.150 66.809 531.250 66.833 ;
    END
  END k_wdata[422]
  PIN k_wdata[421]
    DIRECTION OUTPUT ;
    USE SIGNAL ;
    PORT
      LAYER M4 ;
        RECT 531.150 66.905 531.250 66.929 ;
    END
  END k_wdata[421]
  PIN k_wdata[420]
    DIRECTION OUTPUT ;
    USE SIGNAL ;
    PORT
      LAYER M4 ;
        RECT 531.150 67.001 531.250 67.025 ;
    END
  END k_wdata[420]
  PIN k_wdata[419]
    DIRECTION OUTPUT ;
    USE SIGNAL ;
    PORT
      LAYER M4 ;
        RECT 531.150 67.097 531.250 67.121 ;
    END
  END k_wdata[419]
  PIN k_wdata[418]
    DIRECTION OUTPUT ;
    USE SIGNAL ;
    PORT
      LAYER M4 ;
        RECT 531.150 67.193 531.250 67.217 ;
    END
  END k_wdata[418]
  PIN k_wdata[417]
    DIRECTION OUTPUT ;
    USE SIGNAL ;
    PORT
      LAYER M4 ;
        RECT 531.150 67.289 531.250 67.313 ;
    END
  END k_wdata[417]
  PIN k_wdata[416]
    DIRECTION OUTPUT ;
    USE SIGNAL ;
    PORT
      LAYER M4 ;
        RECT 531.150 67.385 531.250 67.409 ;
    END
  END k_wdata[416]
  PIN k_wdata[415]
    DIRECTION OUTPUT ;
    USE SIGNAL ;
    PORT
      LAYER M4 ;
        RECT 531.150 67.481 531.250 67.505 ;
    END
  END k_wdata[415]
  PIN k_wdata[414]
    DIRECTION OUTPUT ;
    USE SIGNAL ;
    PORT
      LAYER M4 ;
        RECT 531.150 67.577 531.250 67.601 ;
    END
  END k_wdata[414]
  PIN k_wdata[413]
    DIRECTION OUTPUT ;
    USE SIGNAL ;
    PORT
      LAYER M4 ;
        RECT 531.150 67.673 531.250 67.697 ;
    END
  END k_wdata[413]
  PIN k_wdata[412]
    DIRECTION OUTPUT ;
    USE SIGNAL ;
    PORT
      LAYER M4 ;
        RECT 531.150 67.769 531.250 67.793 ;
    END
  END k_wdata[412]
  PIN k_wdata[411]
    DIRECTION OUTPUT ;
    USE SIGNAL ;
    PORT
      LAYER M4 ;
        RECT 531.150 67.865 531.250 67.889 ;
    END
  END k_wdata[411]
  PIN k_wdata[410]
    DIRECTION OUTPUT ;
    USE SIGNAL ;
    PORT
      LAYER M4 ;
        RECT 531.150 67.961 531.250 67.985 ;
    END
  END k_wdata[410]
  PIN k_wdata[409]
    DIRECTION OUTPUT ;
    USE SIGNAL ;
    PORT
      LAYER M4 ;
        RECT 531.150 68.057 531.250 68.081 ;
    END
  END k_wdata[409]
  PIN k_wdata[408]
    DIRECTION OUTPUT ;
    USE SIGNAL ;
    PORT
      LAYER M4 ;
        RECT 531.150 68.153 531.250 68.177 ;
    END
  END k_wdata[408]
  PIN k_wdata[407]
    DIRECTION OUTPUT ;
    USE SIGNAL ;
    PORT
      LAYER M4 ;
        RECT 531.150 68.249 531.250 68.273 ;
    END
  END k_wdata[407]
  PIN k_wdata[406]
    DIRECTION OUTPUT ;
    USE SIGNAL ;
    PORT
      LAYER M4 ;
        RECT 531.150 68.345 531.250 68.369 ;
    END
  END k_wdata[406]
  PIN k_wdata[405]
    DIRECTION OUTPUT ;
    USE SIGNAL ;
    PORT
      LAYER M4 ;
        RECT 531.150 68.441 531.250 68.465 ;
    END
  END k_wdata[405]
  PIN k_wdata[404]
    DIRECTION OUTPUT ;
    USE SIGNAL ;
    PORT
      LAYER M4 ;
        RECT 531.150 68.537 531.250 68.561 ;
    END
  END k_wdata[404]
  PIN k_wdata[403]
    DIRECTION OUTPUT ;
    USE SIGNAL ;
    PORT
      LAYER M4 ;
        RECT 531.150 68.633 531.250 68.657 ;
    END
  END k_wdata[403]
  PIN k_wdata[402]
    DIRECTION OUTPUT ;
    USE SIGNAL ;
    PORT
      LAYER M4 ;
        RECT 531.150 68.729 531.250 68.753 ;
    END
  END k_wdata[402]
  PIN k_wdata[401]
    DIRECTION OUTPUT ;
    USE SIGNAL ;
    PORT
      LAYER M4 ;
        RECT 531.150 68.825 531.250 68.849 ;
    END
  END k_wdata[401]
  PIN k_wdata[400]
    DIRECTION OUTPUT ;
    USE SIGNAL ;
    PORT
      LAYER M4 ;
        RECT 531.150 68.921 531.250 68.945 ;
    END
  END k_wdata[400]
  PIN k_wdata[399]
    DIRECTION OUTPUT ;
    USE SIGNAL ;
    PORT
      LAYER M4 ;
        RECT 531.150 69.017 531.250 69.041 ;
    END
  END k_wdata[399]
  PIN k_wdata[398]
    DIRECTION OUTPUT ;
    USE SIGNAL ;
    PORT
      LAYER M4 ;
        RECT 531.150 69.113 531.250 69.137 ;
    END
  END k_wdata[398]
  PIN k_wdata[397]
    DIRECTION OUTPUT ;
    USE SIGNAL ;
    PORT
      LAYER M4 ;
        RECT 531.150 69.209 531.250 69.233 ;
    END
  END k_wdata[397]
  PIN k_wdata[396]
    DIRECTION OUTPUT ;
    USE SIGNAL ;
    PORT
      LAYER M4 ;
        RECT 531.150 69.305 531.250 69.329 ;
    END
  END k_wdata[396]
  PIN k_wdata[395]
    DIRECTION OUTPUT ;
    USE SIGNAL ;
    PORT
      LAYER M4 ;
        RECT 531.150 69.401 531.250 69.425 ;
    END
  END k_wdata[395]
  PIN k_wdata[394]
    DIRECTION OUTPUT ;
    USE SIGNAL ;
    PORT
      LAYER M4 ;
        RECT 531.150 69.497 531.250 69.521 ;
    END
  END k_wdata[394]
  PIN k_wdata[393]
    DIRECTION OUTPUT ;
    USE SIGNAL ;
    PORT
      LAYER M4 ;
        RECT 531.150 69.593 531.250 69.617 ;
    END
  END k_wdata[393]
  PIN k_wdata[392]
    DIRECTION OUTPUT ;
    USE SIGNAL ;
    PORT
      LAYER M4 ;
        RECT 531.150 69.689 531.250 69.713 ;
    END
  END k_wdata[392]
  PIN k_wdata[391]
    DIRECTION OUTPUT ;
    USE SIGNAL ;
    PORT
      LAYER M4 ;
        RECT 531.150 69.785 531.250 69.809 ;
    END
  END k_wdata[391]
  PIN k_wdata[390]
    DIRECTION OUTPUT ;
    USE SIGNAL ;
    PORT
      LAYER M4 ;
        RECT 531.150 69.881 531.250 69.905 ;
    END
  END k_wdata[390]
  PIN k_wdata[389]
    DIRECTION OUTPUT ;
    USE SIGNAL ;
    PORT
      LAYER M4 ;
        RECT 531.150 69.977 531.250 70.001 ;
    END
  END k_wdata[389]
  PIN k_wdata[388]
    DIRECTION OUTPUT ;
    USE SIGNAL ;
    PORT
      LAYER M4 ;
        RECT 531.150 70.073 531.250 70.097 ;
    END
  END k_wdata[388]
  PIN k_wdata[387]
    DIRECTION OUTPUT ;
    USE SIGNAL ;
    PORT
      LAYER M4 ;
        RECT 531.150 70.169 531.250 70.193 ;
    END
  END k_wdata[387]
  PIN k_wdata[386]
    DIRECTION OUTPUT ;
    USE SIGNAL ;
    PORT
      LAYER M4 ;
        RECT 531.150 70.265 531.250 70.289 ;
    END
  END k_wdata[386]
  PIN k_wdata[385]
    DIRECTION OUTPUT ;
    USE SIGNAL ;
    PORT
      LAYER M4 ;
        RECT 531.150 70.361 531.250 70.385 ;
    END
  END k_wdata[385]
  PIN k_wdata[384]
    DIRECTION OUTPUT ;
    USE SIGNAL ;
    PORT
      LAYER M4 ;
        RECT 531.150 70.457 531.250 70.481 ;
    END
  END k_wdata[384]
  PIN k_wdata[383]
    DIRECTION OUTPUT ;
    USE SIGNAL ;
    PORT
      LAYER M4 ;
        RECT 531.150 70.553 531.250 70.577 ;
    END
  END k_wdata[383]
  PIN k_wdata[382]
    DIRECTION OUTPUT ;
    USE SIGNAL ;
    PORT
      LAYER M4 ;
        RECT 531.150 70.649 531.250 70.673 ;
    END
  END k_wdata[382]
  PIN k_wdata[381]
    DIRECTION OUTPUT ;
    USE SIGNAL ;
    PORT
      LAYER M4 ;
        RECT 531.150 70.745 531.250 70.769 ;
    END
  END k_wdata[381]
  PIN k_wdata[380]
    DIRECTION OUTPUT ;
    USE SIGNAL ;
    PORT
      LAYER M4 ;
        RECT 531.150 70.841 531.250 70.865 ;
    END
  END k_wdata[380]
  PIN k_wdata[379]
    DIRECTION OUTPUT ;
    USE SIGNAL ;
    PORT
      LAYER M4 ;
        RECT 531.150 70.937 531.250 70.961 ;
    END
  END k_wdata[379]
  PIN k_wdata[378]
    DIRECTION OUTPUT ;
    USE SIGNAL ;
    PORT
      LAYER M4 ;
        RECT 531.150 71.033 531.250 71.057 ;
    END
  END k_wdata[378]
  PIN k_wdata[377]
    DIRECTION OUTPUT ;
    USE SIGNAL ;
    PORT
      LAYER M4 ;
        RECT 531.150 71.129 531.250 71.153 ;
    END
  END k_wdata[377]
  PIN k_wdata[376]
    DIRECTION OUTPUT ;
    USE SIGNAL ;
    PORT
      LAYER M4 ;
        RECT 531.150 71.225 531.250 71.249 ;
    END
  END k_wdata[376]
  PIN k_wdata[375]
    DIRECTION OUTPUT ;
    USE SIGNAL ;
    PORT
      LAYER M4 ;
        RECT 531.150 71.321 531.250 71.345 ;
    END
  END k_wdata[375]
  PIN k_wdata[374]
    DIRECTION OUTPUT ;
    USE SIGNAL ;
    PORT
      LAYER M4 ;
        RECT 531.150 71.417 531.250 71.441 ;
    END
  END k_wdata[374]
  PIN k_wdata[373]
    DIRECTION OUTPUT ;
    USE SIGNAL ;
    PORT
      LAYER M4 ;
        RECT 531.150 71.513 531.250 71.537 ;
    END
  END k_wdata[373]
  PIN k_wdata[372]
    DIRECTION OUTPUT ;
    USE SIGNAL ;
    PORT
      LAYER M4 ;
        RECT 531.150 71.609 531.250 71.633 ;
    END
  END k_wdata[372]
  PIN k_wdata[371]
    DIRECTION OUTPUT ;
    USE SIGNAL ;
    PORT
      LAYER M4 ;
        RECT 531.150 71.705 531.250 71.729 ;
    END
  END k_wdata[371]
  PIN k_wdata[370]
    DIRECTION OUTPUT ;
    USE SIGNAL ;
    PORT
      LAYER M4 ;
        RECT 531.150 71.801 531.250 71.825 ;
    END
  END k_wdata[370]
  PIN k_wdata[369]
    DIRECTION OUTPUT ;
    USE SIGNAL ;
    PORT
      LAYER M4 ;
        RECT 531.150 71.897 531.250 71.921 ;
    END
  END k_wdata[369]
  PIN k_wdata[368]
    DIRECTION OUTPUT ;
    USE SIGNAL ;
    PORT
      LAYER M4 ;
        RECT 531.150 71.993 531.250 72.017 ;
    END
  END k_wdata[368]
  PIN k_wdata[367]
    DIRECTION OUTPUT ;
    USE SIGNAL ;
    PORT
      LAYER M4 ;
        RECT 531.150 72.089 531.250 72.113 ;
    END
  END k_wdata[367]
  PIN k_wdata[366]
    DIRECTION OUTPUT ;
    USE SIGNAL ;
    PORT
      LAYER M4 ;
        RECT 531.150 72.185 531.250 72.209 ;
    END
  END k_wdata[366]
  PIN k_wdata[365]
    DIRECTION OUTPUT ;
    USE SIGNAL ;
    PORT
      LAYER M4 ;
        RECT 531.150 72.281 531.250 72.305 ;
    END
  END k_wdata[365]
  PIN k_wdata[364]
    DIRECTION OUTPUT ;
    USE SIGNAL ;
    PORT
      LAYER M4 ;
        RECT 531.150 72.377 531.250 72.401 ;
    END
  END k_wdata[364]
  PIN k_wdata[363]
    DIRECTION OUTPUT ;
    USE SIGNAL ;
    PORT
      LAYER M4 ;
        RECT 531.150 72.473 531.250 72.497 ;
    END
  END k_wdata[363]
  PIN k_wdata[362]
    DIRECTION OUTPUT ;
    USE SIGNAL ;
    PORT
      LAYER M4 ;
        RECT 531.150 72.569 531.250 72.593 ;
    END
  END k_wdata[362]
  PIN k_wdata[361]
    DIRECTION OUTPUT ;
    USE SIGNAL ;
    PORT
      LAYER M4 ;
        RECT 531.150 72.665 531.250 72.689 ;
    END
  END k_wdata[361]
  PIN k_wdata[360]
    DIRECTION OUTPUT ;
    USE SIGNAL ;
    PORT
      LAYER M4 ;
        RECT 531.150 72.761 531.250 72.785 ;
    END
  END k_wdata[360]
  PIN k_wdata[359]
    DIRECTION OUTPUT ;
    USE SIGNAL ;
    PORT
      LAYER M4 ;
        RECT 531.150 72.857 531.250 72.881 ;
    END
  END k_wdata[359]
  PIN k_wdata[358]
    DIRECTION OUTPUT ;
    USE SIGNAL ;
    PORT
      LAYER M4 ;
        RECT 531.150 72.953 531.250 72.977 ;
    END
  END k_wdata[358]
  PIN k_wdata[357]
    DIRECTION OUTPUT ;
    USE SIGNAL ;
    PORT
      LAYER M4 ;
        RECT 531.150 73.049 531.250 73.073 ;
    END
  END k_wdata[357]
  PIN k_wdata[356]
    DIRECTION OUTPUT ;
    USE SIGNAL ;
    PORT
      LAYER M4 ;
        RECT 531.150 73.145 531.250 73.169 ;
    END
  END k_wdata[356]
  PIN k_wdata[355]
    DIRECTION OUTPUT ;
    USE SIGNAL ;
    PORT
      LAYER M4 ;
        RECT 531.150 73.241 531.250 73.265 ;
    END
  END k_wdata[355]
  PIN k_wdata[354]
    DIRECTION OUTPUT ;
    USE SIGNAL ;
    PORT
      LAYER M4 ;
        RECT 531.150 73.337 531.250 73.361 ;
    END
  END k_wdata[354]
  PIN k_wdata[353]
    DIRECTION OUTPUT ;
    USE SIGNAL ;
    PORT
      LAYER M4 ;
        RECT 531.150 73.433 531.250 73.457 ;
    END
  END k_wdata[353]
  PIN k_wdata[352]
    DIRECTION OUTPUT ;
    USE SIGNAL ;
    PORT
      LAYER M4 ;
        RECT 531.150 73.529 531.250 73.553 ;
    END
  END k_wdata[352]
  PIN k_wdata[351]
    DIRECTION OUTPUT ;
    USE SIGNAL ;
    PORT
      LAYER M4 ;
        RECT 531.150 73.625 531.250 73.649 ;
    END
  END k_wdata[351]
  PIN k_wdata[350]
    DIRECTION OUTPUT ;
    USE SIGNAL ;
    PORT
      LAYER M4 ;
        RECT 531.150 73.721 531.250 73.745 ;
    END
  END k_wdata[350]
  PIN k_wdata[349]
    DIRECTION OUTPUT ;
    USE SIGNAL ;
    PORT
      LAYER M4 ;
        RECT 531.150 73.817 531.250 73.841 ;
    END
  END k_wdata[349]
  PIN k_wdata[348]
    DIRECTION OUTPUT ;
    USE SIGNAL ;
    PORT
      LAYER M4 ;
        RECT 531.150 73.913 531.250 73.937 ;
    END
  END k_wdata[348]
  PIN k_wdata[347]
    DIRECTION OUTPUT ;
    USE SIGNAL ;
    PORT
      LAYER M4 ;
        RECT 531.150 74.009 531.250 74.033 ;
    END
  END k_wdata[347]
  PIN k_wdata[346]
    DIRECTION OUTPUT ;
    USE SIGNAL ;
    PORT
      LAYER M4 ;
        RECT 531.150 74.105 531.250 74.129 ;
    END
  END k_wdata[346]
  PIN k_wdata[345]
    DIRECTION OUTPUT ;
    USE SIGNAL ;
    PORT
      LAYER M4 ;
        RECT 531.150 74.201 531.250 74.225 ;
    END
  END k_wdata[345]
  PIN k_wdata[344]
    DIRECTION OUTPUT ;
    USE SIGNAL ;
    PORT
      LAYER M4 ;
        RECT 531.150 74.297 531.250 74.321 ;
    END
  END k_wdata[344]
  PIN k_wdata[343]
    DIRECTION OUTPUT ;
    USE SIGNAL ;
    PORT
      LAYER M4 ;
        RECT 531.150 74.393 531.250 74.417 ;
    END
  END k_wdata[343]
  PIN k_wdata[342]
    DIRECTION OUTPUT ;
    USE SIGNAL ;
    PORT
      LAYER M4 ;
        RECT 531.150 74.489 531.250 74.513 ;
    END
  END k_wdata[342]
  PIN k_wdata[341]
    DIRECTION OUTPUT ;
    USE SIGNAL ;
    PORT
      LAYER M4 ;
        RECT 531.150 74.585 531.250 74.609 ;
    END
  END k_wdata[341]
  PIN k_wdata[340]
    DIRECTION OUTPUT ;
    USE SIGNAL ;
    PORT
      LAYER M4 ;
        RECT 531.150 74.681 531.250 74.705 ;
    END
  END k_wdata[340]
  PIN k_wdata[339]
    DIRECTION OUTPUT ;
    USE SIGNAL ;
    PORT
      LAYER M4 ;
        RECT 531.150 74.777 531.250 74.801 ;
    END
  END k_wdata[339]
  PIN k_wdata[338]
    DIRECTION OUTPUT ;
    USE SIGNAL ;
    PORT
      LAYER M4 ;
        RECT 531.150 74.873 531.250 74.897 ;
    END
  END k_wdata[338]
  PIN k_wdata[337]
    DIRECTION OUTPUT ;
    USE SIGNAL ;
    PORT
      LAYER M4 ;
        RECT 531.150 74.969 531.250 74.993 ;
    END
  END k_wdata[337]
  PIN k_wdata[336]
    DIRECTION OUTPUT ;
    USE SIGNAL ;
    PORT
      LAYER M4 ;
        RECT 531.150 75.065 531.250 75.089 ;
    END
  END k_wdata[336]
  PIN k_wdata[335]
    DIRECTION OUTPUT ;
    USE SIGNAL ;
    PORT
      LAYER M4 ;
        RECT 531.150 75.161 531.250 75.185 ;
    END
  END k_wdata[335]
  PIN k_wdata[334]
    DIRECTION OUTPUT ;
    USE SIGNAL ;
    PORT
      LAYER M4 ;
        RECT 531.150 75.257 531.250 75.281 ;
    END
  END k_wdata[334]
  PIN k_wdata[333]
    DIRECTION OUTPUT ;
    USE SIGNAL ;
    PORT
      LAYER M4 ;
        RECT 531.150 75.353 531.250 75.377 ;
    END
  END k_wdata[333]
  PIN k_wdata[332]
    DIRECTION OUTPUT ;
    USE SIGNAL ;
    PORT
      LAYER M4 ;
        RECT 531.150 75.449 531.250 75.473 ;
    END
  END k_wdata[332]
  PIN k_wdata[331]
    DIRECTION OUTPUT ;
    USE SIGNAL ;
    PORT
      LAYER M4 ;
        RECT 531.150 75.545 531.250 75.569 ;
    END
  END k_wdata[331]
  PIN k_wdata[330]
    DIRECTION OUTPUT ;
    USE SIGNAL ;
    PORT
      LAYER M4 ;
        RECT 531.150 75.641 531.250 75.665 ;
    END
  END k_wdata[330]
  PIN k_wdata[329]
    DIRECTION OUTPUT ;
    USE SIGNAL ;
    PORT
      LAYER M4 ;
        RECT 531.150 75.737 531.250 75.761 ;
    END
  END k_wdata[329]
  PIN k_wdata[328]
    DIRECTION OUTPUT ;
    USE SIGNAL ;
    PORT
      LAYER M4 ;
        RECT 531.150 75.833 531.250 75.857 ;
    END
  END k_wdata[328]
  PIN k_wdata[327]
    DIRECTION OUTPUT ;
    USE SIGNAL ;
    PORT
      LAYER M4 ;
        RECT 531.150 75.929 531.250 75.953 ;
    END
  END k_wdata[327]
  PIN k_wdata[326]
    DIRECTION OUTPUT ;
    USE SIGNAL ;
    PORT
      LAYER M4 ;
        RECT 531.150 76.025 531.250 76.049 ;
    END
  END k_wdata[326]
  PIN k_wdata[325]
    DIRECTION OUTPUT ;
    USE SIGNAL ;
    PORT
      LAYER M4 ;
        RECT 531.150 76.121 531.250 76.145 ;
    END
  END k_wdata[325]
  PIN k_wdata[324]
    DIRECTION OUTPUT ;
    USE SIGNAL ;
    PORT
      LAYER M4 ;
        RECT 531.150 76.217 531.250 76.241 ;
    END
  END k_wdata[324]
  PIN k_wdata[323]
    DIRECTION OUTPUT ;
    USE SIGNAL ;
    PORT
      LAYER M4 ;
        RECT 531.150 76.313 531.250 76.337 ;
    END
  END k_wdata[323]
  PIN k_wdata[322]
    DIRECTION OUTPUT ;
    USE SIGNAL ;
    PORT
      LAYER M4 ;
        RECT 531.150 76.409 531.250 76.433 ;
    END
  END k_wdata[322]
  PIN k_wdata[321]
    DIRECTION OUTPUT ;
    USE SIGNAL ;
    PORT
      LAYER M4 ;
        RECT 531.150 76.505 531.250 76.529 ;
    END
  END k_wdata[321]
  PIN k_wdata[320]
    DIRECTION OUTPUT ;
    USE SIGNAL ;
    PORT
      LAYER M4 ;
        RECT 531.150 76.601 531.250 76.625 ;
    END
  END k_wdata[320]
  PIN k_wdata[319]
    DIRECTION OUTPUT ;
    USE SIGNAL ;
    PORT
      LAYER M4 ;
        RECT 531.150 76.697 531.250 76.721 ;
    END
  END k_wdata[319]
  PIN k_wdata[318]
    DIRECTION OUTPUT ;
    USE SIGNAL ;
    PORT
      LAYER M4 ;
        RECT 531.150 76.793 531.250 76.817 ;
    END
  END k_wdata[318]
  PIN k_wdata[317]
    DIRECTION OUTPUT ;
    USE SIGNAL ;
    PORT
      LAYER M4 ;
        RECT 531.150 76.889 531.250 76.913 ;
    END
  END k_wdata[317]
  PIN k_wdata[316]
    DIRECTION OUTPUT ;
    USE SIGNAL ;
    PORT
      LAYER M4 ;
        RECT 531.150 76.985 531.250 77.009 ;
    END
  END k_wdata[316]
  PIN k_wdata[315]
    DIRECTION OUTPUT ;
    USE SIGNAL ;
    PORT
      LAYER M4 ;
        RECT 531.150 77.081 531.250 77.105 ;
    END
  END k_wdata[315]
  PIN k_wdata[314]
    DIRECTION OUTPUT ;
    USE SIGNAL ;
    PORT
      LAYER M4 ;
        RECT 531.150 77.177 531.250 77.201 ;
    END
  END k_wdata[314]
  PIN k_wdata[313]
    DIRECTION OUTPUT ;
    USE SIGNAL ;
    PORT
      LAYER M4 ;
        RECT 531.150 77.273 531.250 77.297 ;
    END
  END k_wdata[313]
  PIN k_wdata[312]
    DIRECTION OUTPUT ;
    USE SIGNAL ;
    PORT
      LAYER M4 ;
        RECT 531.150 77.369 531.250 77.393 ;
    END
  END k_wdata[312]
  PIN k_wdata[311]
    DIRECTION OUTPUT ;
    USE SIGNAL ;
    PORT
      LAYER M4 ;
        RECT 531.150 77.465 531.250 77.489 ;
    END
  END k_wdata[311]
  PIN k_wdata[310]
    DIRECTION OUTPUT ;
    USE SIGNAL ;
    PORT
      LAYER M4 ;
        RECT 531.150 77.561 531.250 77.585 ;
    END
  END k_wdata[310]
  PIN k_wdata[309]
    DIRECTION OUTPUT ;
    USE SIGNAL ;
    PORT
      LAYER M4 ;
        RECT 531.150 77.657 531.250 77.681 ;
    END
  END k_wdata[309]
  PIN k_wdata[308]
    DIRECTION OUTPUT ;
    USE SIGNAL ;
    PORT
      LAYER M4 ;
        RECT 531.150 77.753 531.250 77.777 ;
    END
  END k_wdata[308]
  PIN k_wdata[307]
    DIRECTION OUTPUT ;
    USE SIGNAL ;
    PORT
      LAYER M4 ;
        RECT 531.150 77.849 531.250 77.873 ;
    END
  END k_wdata[307]
  PIN k_wdata[306]
    DIRECTION OUTPUT ;
    USE SIGNAL ;
    PORT
      LAYER M4 ;
        RECT 531.150 77.945 531.250 77.969 ;
    END
  END k_wdata[306]
  PIN k_wdata[305]
    DIRECTION OUTPUT ;
    USE SIGNAL ;
    PORT
      LAYER M4 ;
        RECT 531.150 78.041 531.250 78.065 ;
    END
  END k_wdata[305]
  PIN k_wdata[304]
    DIRECTION OUTPUT ;
    USE SIGNAL ;
    PORT
      LAYER M4 ;
        RECT 531.150 78.137 531.250 78.161 ;
    END
  END k_wdata[304]
  PIN k_wdata[303]
    DIRECTION OUTPUT ;
    USE SIGNAL ;
    PORT
      LAYER M4 ;
        RECT 531.150 78.233 531.250 78.257 ;
    END
  END k_wdata[303]
  PIN k_wdata[302]
    DIRECTION OUTPUT ;
    USE SIGNAL ;
    PORT
      LAYER M4 ;
        RECT 531.150 78.329 531.250 78.353 ;
    END
  END k_wdata[302]
  PIN k_wdata[301]
    DIRECTION OUTPUT ;
    USE SIGNAL ;
    PORT
      LAYER M4 ;
        RECT 531.150 78.425 531.250 78.449 ;
    END
  END k_wdata[301]
  PIN k_wdata[300]
    DIRECTION OUTPUT ;
    USE SIGNAL ;
    PORT
      LAYER M4 ;
        RECT 531.150 78.521 531.250 78.545 ;
    END
  END k_wdata[300]
  PIN k_wdata[299]
    DIRECTION OUTPUT ;
    USE SIGNAL ;
    PORT
      LAYER M4 ;
        RECT 531.150 78.617 531.250 78.641 ;
    END
  END k_wdata[299]
  PIN k_wdata[298]
    DIRECTION OUTPUT ;
    USE SIGNAL ;
    PORT
      LAYER M4 ;
        RECT 531.150 78.713 531.250 78.737 ;
    END
  END k_wdata[298]
  PIN k_wdata[297]
    DIRECTION OUTPUT ;
    USE SIGNAL ;
    PORT
      LAYER M4 ;
        RECT 531.150 78.809 531.250 78.833 ;
    END
  END k_wdata[297]
  PIN k_wdata[296]
    DIRECTION OUTPUT ;
    USE SIGNAL ;
    PORT
      LAYER M4 ;
        RECT 531.150 78.905 531.250 78.929 ;
    END
  END k_wdata[296]
  PIN k_wdata[295]
    DIRECTION OUTPUT ;
    USE SIGNAL ;
    PORT
      LAYER M4 ;
        RECT 531.150 79.001 531.250 79.025 ;
    END
  END k_wdata[295]
  PIN k_wdata[294]
    DIRECTION OUTPUT ;
    USE SIGNAL ;
    PORT
      LAYER M4 ;
        RECT 531.150 79.097 531.250 79.121 ;
    END
  END k_wdata[294]
  PIN k_wdata[293]
    DIRECTION OUTPUT ;
    USE SIGNAL ;
    PORT
      LAYER M4 ;
        RECT 531.150 79.193 531.250 79.217 ;
    END
  END k_wdata[293]
  PIN k_wdata[292]
    DIRECTION OUTPUT ;
    USE SIGNAL ;
    PORT
      LAYER M4 ;
        RECT 531.150 79.289 531.250 79.313 ;
    END
  END k_wdata[292]
  PIN k_wdata[291]
    DIRECTION OUTPUT ;
    USE SIGNAL ;
    PORT
      LAYER M4 ;
        RECT 531.150 79.385 531.250 79.409 ;
    END
  END k_wdata[291]
  PIN k_wdata[290]
    DIRECTION OUTPUT ;
    USE SIGNAL ;
    PORT
      LAYER M4 ;
        RECT 531.150 79.481 531.250 79.505 ;
    END
  END k_wdata[290]
  PIN k_wdata[289]
    DIRECTION OUTPUT ;
    USE SIGNAL ;
    PORT
      LAYER M4 ;
        RECT 531.150 79.577 531.250 79.601 ;
    END
  END k_wdata[289]
  PIN k_wdata[288]
    DIRECTION OUTPUT ;
    USE SIGNAL ;
    PORT
      LAYER M4 ;
        RECT 531.150 79.673 531.250 79.697 ;
    END
  END k_wdata[288]
  PIN k_wdata[287]
    DIRECTION OUTPUT ;
    USE SIGNAL ;
    PORT
      LAYER M4 ;
        RECT 531.150 79.769 531.250 79.793 ;
    END
  END k_wdata[287]
  PIN k_wdata[286]
    DIRECTION OUTPUT ;
    USE SIGNAL ;
    PORT
      LAYER M4 ;
        RECT 531.150 79.865 531.250 79.889 ;
    END
  END k_wdata[286]
  PIN k_wdata[285]
    DIRECTION OUTPUT ;
    USE SIGNAL ;
    PORT
      LAYER M4 ;
        RECT 531.150 79.961 531.250 79.985 ;
    END
  END k_wdata[285]
  PIN k_wdata[284]
    DIRECTION OUTPUT ;
    USE SIGNAL ;
    PORT
      LAYER M4 ;
        RECT 531.150 80.057 531.250 80.081 ;
    END
  END k_wdata[284]
  PIN k_wdata[283]
    DIRECTION OUTPUT ;
    USE SIGNAL ;
    PORT
      LAYER M4 ;
        RECT 531.150 80.153 531.250 80.177 ;
    END
  END k_wdata[283]
  PIN k_wdata[282]
    DIRECTION OUTPUT ;
    USE SIGNAL ;
    PORT
      LAYER M4 ;
        RECT 531.150 80.249 531.250 80.273 ;
    END
  END k_wdata[282]
  PIN k_wdata[281]
    DIRECTION OUTPUT ;
    USE SIGNAL ;
    PORT
      LAYER M4 ;
        RECT 531.150 80.345 531.250 80.369 ;
    END
  END k_wdata[281]
  PIN k_wdata[280]
    DIRECTION OUTPUT ;
    USE SIGNAL ;
    PORT
      LAYER M4 ;
        RECT 531.150 80.441 531.250 80.465 ;
    END
  END k_wdata[280]
  PIN k_wdata[279]
    DIRECTION OUTPUT ;
    USE SIGNAL ;
    PORT
      LAYER M4 ;
        RECT 531.150 80.537 531.250 80.561 ;
    END
  END k_wdata[279]
  PIN k_wdata[278]
    DIRECTION OUTPUT ;
    USE SIGNAL ;
    PORT
      LAYER M4 ;
        RECT 531.150 80.633 531.250 80.657 ;
    END
  END k_wdata[278]
  PIN k_wdata[277]
    DIRECTION OUTPUT ;
    USE SIGNAL ;
    PORT
      LAYER M4 ;
        RECT 531.150 80.729 531.250 80.753 ;
    END
  END k_wdata[277]
  PIN k_wdata[276]
    DIRECTION OUTPUT ;
    USE SIGNAL ;
    PORT
      LAYER M4 ;
        RECT 531.150 80.825 531.250 80.849 ;
    END
  END k_wdata[276]
  PIN k_wdata[275]
    DIRECTION OUTPUT ;
    USE SIGNAL ;
    PORT
      LAYER M4 ;
        RECT 531.150 80.921 531.250 80.945 ;
    END
  END k_wdata[275]
  PIN k_wdata[274]
    DIRECTION OUTPUT ;
    USE SIGNAL ;
    PORT
      LAYER M4 ;
        RECT 531.150 81.017 531.250 81.041 ;
    END
  END k_wdata[274]
  PIN k_wdata[273]
    DIRECTION OUTPUT ;
    USE SIGNAL ;
    PORT
      LAYER M4 ;
        RECT 531.150 81.113 531.250 81.137 ;
    END
  END k_wdata[273]
  PIN k_wdata[272]
    DIRECTION OUTPUT ;
    USE SIGNAL ;
    PORT
      LAYER M4 ;
        RECT 531.150 81.209 531.250 81.233 ;
    END
  END k_wdata[272]
  PIN k_wdata[271]
    DIRECTION OUTPUT ;
    USE SIGNAL ;
    PORT
      LAYER M4 ;
        RECT 531.150 81.305 531.250 81.329 ;
    END
  END k_wdata[271]
  PIN k_wdata[270]
    DIRECTION OUTPUT ;
    USE SIGNAL ;
    PORT
      LAYER M4 ;
        RECT 531.150 81.401 531.250 81.425 ;
    END
  END k_wdata[270]
  PIN k_wdata[269]
    DIRECTION OUTPUT ;
    USE SIGNAL ;
    PORT
      LAYER M4 ;
        RECT 531.150 81.497 531.250 81.521 ;
    END
  END k_wdata[269]
  PIN k_wdata[268]
    DIRECTION OUTPUT ;
    USE SIGNAL ;
    PORT
      LAYER M4 ;
        RECT 531.150 81.593 531.250 81.617 ;
    END
  END k_wdata[268]
  PIN k_wdata[267]
    DIRECTION OUTPUT ;
    USE SIGNAL ;
    PORT
      LAYER M4 ;
        RECT 531.150 81.689 531.250 81.713 ;
    END
  END k_wdata[267]
  PIN k_wdata[266]
    DIRECTION OUTPUT ;
    USE SIGNAL ;
    PORT
      LAYER M4 ;
        RECT 531.150 81.785 531.250 81.809 ;
    END
  END k_wdata[266]
  PIN k_wdata[265]
    DIRECTION OUTPUT ;
    USE SIGNAL ;
    PORT
      LAYER M4 ;
        RECT 531.150 81.881 531.250 81.905 ;
    END
  END k_wdata[265]
  PIN k_wdata[264]
    DIRECTION OUTPUT ;
    USE SIGNAL ;
    PORT
      LAYER M4 ;
        RECT 531.150 81.977 531.250 82.001 ;
    END
  END k_wdata[264]
  PIN k_wdata[263]
    DIRECTION OUTPUT ;
    USE SIGNAL ;
    PORT
      LAYER M4 ;
        RECT 531.150 82.073 531.250 82.097 ;
    END
  END k_wdata[263]
  PIN k_wdata[262]
    DIRECTION OUTPUT ;
    USE SIGNAL ;
    PORT
      LAYER M4 ;
        RECT 531.150 82.169 531.250 82.193 ;
    END
  END k_wdata[262]
  PIN k_wdata[261]
    DIRECTION OUTPUT ;
    USE SIGNAL ;
    PORT
      LAYER M4 ;
        RECT 531.150 82.265 531.250 82.289 ;
    END
  END k_wdata[261]
  PIN k_wdata[260]
    DIRECTION OUTPUT ;
    USE SIGNAL ;
    PORT
      LAYER M4 ;
        RECT 531.150 82.361 531.250 82.385 ;
    END
  END k_wdata[260]
  PIN k_wdata[259]
    DIRECTION OUTPUT ;
    USE SIGNAL ;
    PORT
      LAYER M4 ;
        RECT 531.150 82.457 531.250 82.481 ;
    END
  END k_wdata[259]
  PIN k_wdata[258]
    DIRECTION OUTPUT ;
    USE SIGNAL ;
    PORT
      LAYER M4 ;
        RECT 531.150 82.553 531.250 82.577 ;
    END
  END k_wdata[258]
  PIN k_wdata[257]
    DIRECTION OUTPUT ;
    USE SIGNAL ;
    PORT
      LAYER M4 ;
        RECT 531.150 82.649 531.250 82.673 ;
    END
  END k_wdata[257]
  PIN k_wdata[256]
    DIRECTION OUTPUT ;
    USE SIGNAL ;
    PORT
      LAYER M4 ;
        RECT 531.150 82.745 531.250 82.769 ;
    END
  END k_wdata[256]
  PIN k_wdata[255]
    DIRECTION OUTPUT ;
    USE SIGNAL ;
    PORT
      LAYER M4 ;
        RECT 531.150 82.841 531.250 82.865 ;
    END
  END k_wdata[255]
  PIN k_wdata[254]
    DIRECTION OUTPUT ;
    USE SIGNAL ;
    PORT
      LAYER M4 ;
        RECT 531.150 82.937 531.250 82.961 ;
    END
  END k_wdata[254]
  PIN k_wdata[253]
    DIRECTION OUTPUT ;
    USE SIGNAL ;
    PORT
      LAYER M4 ;
        RECT 531.150 83.033 531.250 83.057 ;
    END
  END k_wdata[253]
  PIN k_wdata[252]
    DIRECTION OUTPUT ;
    USE SIGNAL ;
    PORT
      LAYER M4 ;
        RECT 531.150 83.129 531.250 83.153 ;
    END
  END k_wdata[252]
  PIN k_wdata[251]
    DIRECTION OUTPUT ;
    USE SIGNAL ;
    PORT
      LAYER M4 ;
        RECT 531.150 83.225 531.250 83.249 ;
    END
  END k_wdata[251]
  PIN k_wdata[250]
    DIRECTION OUTPUT ;
    USE SIGNAL ;
    PORT
      LAYER M4 ;
        RECT 531.150 83.321 531.250 83.345 ;
    END
  END k_wdata[250]
  PIN k_wdata[249]
    DIRECTION OUTPUT ;
    USE SIGNAL ;
    PORT
      LAYER M4 ;
        RECT 531.150 83.417 531.250 83.441 ;
    END
  END k_wdata[249]
  PIN k_wdata[248]
    DIRECTION OUTPUT ;
    USE SIGNAL ;
    PORT
      LAYER M4 ;
        RECT 531.150 83.513 531.250 83.537 ;
    END
  END k_wdata[248]
  PIN k_wdata[247]
    DIRECTION OUTPUT ;
    USE SIGNAL ;
    PORT
      LAYER M4 ;
        RECT 531.150 83.609 531.250 83.633 ;
    END
  END k_wdata[247]
  PIN k_wdata[246]
    DIRECTION OUTPUT ;
    USE SIGNAL ;
    PORT
      LAYER M4 ;
        RECT 531.150 83.705 531.250 83.729 ;
    END
  END k_wdata[246]
  PIN k_wdata[245]
    DIRECTION OUTPUT ;
    USE SIGNAL ;
    PORT
      LAYER M4 ;
        RECT 531.150 83.801 531.250 83.825 ;
    END
  END k_wdata[245]
  PIN k_wdata[244]
    DIRECTION OUTPUT ;
    USE SIGNAL ;
    PORT
      LAYER M4 ;
        RECT 531.150 83.897 531.250 83.921 ;
    END
  END k_wdata[244]
  PIN k_wdata[243]
    DIRECTION OUTPUT ;
    USE SIGNAL ;
    PORT
      LAYER M4 ;
        RECT 531.150 83.993 531.250 84.017 ;
    END
  END k_wdata[243]
  PIN k_wdata[242]
    DIRECTION OUTPUT ;
    USE SIGNAL ;
    PORT
      LAYER M4 ;
        RECT 531.150 84.089 531.250 84.113 ;
    END
  END k_wdata[242]
  PIN k_wdata[241]
    DIRECTION OUTPUT ;
    USE SIGNAL ;
    PORT
      LAYER M4 ;
        RECT 531.150 84.185 531.250 84.209 ;
    END
  END k_wdata[241]
  PIN k_wdata[240]
    DIRECTION OUTPUT ;
    USE SIGNAL ;
    PORT
      LAYER M4 ;
        RECT 531.150 84.281 531.250 84.305 ;
    END
  END k_wdata[240]
  PIN k_wdata[239]
    DIRECTION OUTPUT ;
    USE SIGNAL ;
    PORT
      LAYER M4 ;
        RECT 531.150 84.377 531.250 84.401 ;
    END
  END k_wdata[239]
  PIN k_wdata[238]
    DIRECTION OUTPUT ;
    USE SIGNAL ;
    PORT
      LAYER M4 ;
        RECT 531.150 84.473 531.250 84.497 ;
    END
  END k_wdata[238]
  PIN k_wdata[237]
    DIRECTION OUTPUT ;
    USE SIGNAL ;
    PORT
      LAYER M4 ;
        RECT 531.150 84.569 531.250 84.593 ;
    END
  END k_wdata[237]
  PIN k_wdata[236]
    DIRECTION OUTPUT ;
    USE SIGNAL ;
    PORT
      LAYER M4 ;
        RECT 531.150 84.665 531.250 84.689 ;
    END
  END k_wdata[236]
  PIN k_wdata[235]
    DIRECTION OUTPUT ;
    USE SIGNAL ;
    PORT
      LAYER M4 ;
        RECT 531.150 84.761 531.250 84.785 ;
    END
  END k_wdata[235]
  PIN k_wdata[234]
    DIRECTION OUTPUT ;
    USE SIGNAL ;
    PORT
      LAYER M4 ;
        RECT 531.150 84.857 531.250 84.881 ;
    END
  END k_wdata[234]
  PIN k_wdata[233]
    DIRECTION OUTPUT ;
    USE SIGNAL ;
    PORT
      LAYER M4 ;
        RECT 531.150 84.953 531.250 84.977 ;
    END
  END k_wdata[233]
  PIN k_wdata[232]
    DIRECTION OUTPUT ;
    USE SIGNAL ;
    PORT
      LAYER M4 ;
        RECT 531.150 85.049 531.250 85.073 ;
    END
  END k_wdata[232]
  PIN k_wdata[231]
    DIRECTION OUTPUT ;
    USE SIGNAL ;
    PORT
      LAYER M4 ;
        RECT 531.150 85.145 531.250 85.169 ;
    END
  END k_wdata[231]
  PIN k_wdata[230]
    DIRECTION OUTPUT ;
    USE SIGNAL ;
    PORT
      LAYER M4 ;
        RECT 531.150 85.241 531.250 85.265 ;
    END
  END k_wdata[230]
  PIN k_wdata[229]
    DIRECTION OUTPUT ;
    USE SIGNAL ;
    PORT
      LAYER M4 ;
        RECT 531.150 85.337 531.250 85.361 ;
    END
  END k_wdata[229]
  PIN k_wdata[228]
    DIRECTION OUTPUT ;
    USE SIGNAL ;
    PORT
      LAYER M4 ;
        RECT 531.150 85.433 531.250 85.457 ;
    END
  END k_wdata[228]
  PIN k_wdata[227]
    DIRECTION OUTPUT ;
    USE SIGNAL ;
    PORT
      LAYER M4 ;
        RECT 531.150 85.529 531.250 85.553 ;
    END
  END k_wdata[227]
  PIN k_wdata[226]
    DIRECTION OUTPUT ;
    USE SIGNAL ;
    PORT
      LAYER M4 ;
        RECT 531.150 85.625 531.250 85.649 ;
    END
  END k_wdata[226]
  PIN k_wdata[225]
    DIRECTION OUTPUT ;
    USE SIGNAL ;
    PORT
      LAYER M4 ;
        RECT 531.150 85.721 531.250 85.745 ;
    END
  END k_wdata[225]
  PIN k_wdata[224]
    DIRECTION OUTPUT ;
    USE SIGNAL ;
    PORT
      LAYER M4 ;
        RECT 531.150 85.817 531.250 85.841 ;
    END
  END k_wdata[224]
  PIN k_wdata[223]
    DIRECTION OUTPUT ;
    USE SIGNAL ;
    PORT
      LAYER M4 ;
        RECT 531.150 85.913 531.250 85.937 ;
    END
  END k_wdata[223]
  PIN k_wdata[222]
    DIRECTION OUTPUT ;
    USE SIGNAL ;
    PORT
      LAYER M4 ;
        RECT 531.150 86.009 531.250 86.033 ;
    END
  END k_wdata[222]
  PIN k_wdata[221]
    DIRECTION OUTPUT ;
    USE SIGNAL ;
    PORT
      LAYER M4 ;
        RECT 531.150 86.105 531.250 86.129 ;
    END
  END k_wdata[221]
  PIN k_wdata[220]
    DIRECTION OUTPUT ;
    USE SIGNAL ;
    PORT
      LAYER M4 ;
        RECT 531.150 86.201 531.250 86.225 ;
    END
  END k_wdata[220]
  PIN k_wdata[219]
    DIRECTION OUTPUT ;
    USE SIGNAL ;
    PORT
      LAYER M4 ;
        RECT 531.150 86.297 531.250 86.321 ;
    END
  END k_wdata[219]
  PIN k_wdata[218]
    DIRECTION OUTPUT ;
    USE SIGNAL ;
    PORT
      LAYER M4 ;
        RECT 531.150 86.393 531.250 86.417 ;
    END
  END k_wdata[218]
  PIN k_wdata[217]
    DIRECTION OUTPUT ;
    USE SIGNAL ;
    PORT
      LAYER M4 ;
        RECT 531.150 86.489 531.250 86.513 ;
    END
  END k_wdata[217]
  PIN k_wdata[216]
    DIRECTION OUTPUT ;
    USE SIGNAL ;
    PORT
      LAYER M4 ;
        RECT 531.150 86.585 531.250 86.609 ;
    END
  END k_wdata[216]
  PIN k_wdata[215]
    DIRECTION OUTPUT ;
    USE SIGNAL ;
    PORT
      LAYER M4 ;
        RECT 531.150 86.681 531.250 86.705 ;
    END
  END k_wdata[215]
  PIN k_wdata[214]
    DIRECTION OUTPUT ;
    USE SIGNAL ;
    PORT
      LAYER M4 ;
        RECT 531.150 86.777 531.250 86.801 ;
    END
  END k_wdata[214]
  PIN k_wdata[213]
    DIRECTION OUTPUT ;
    USE SIGNAL ;
    PORT
      LAYER M4 ;
        RECT 531.150 86.873 531.250 86.897 ;
    END
  END k_wdata[213]
  PIN k_wdata[212]
    DIRECTION OUTPUT ;
    USE SIGNAL ;
    PORT
      LAYER M4 ;
        RECT 531.150 86.969 531.250 86.993 ;
    END
  END k_wdata[212]
  PIN k_wdata[211]
    DIRECTION OUTPUT ;
    USE SIGNAL ;
    PORT
      LAYER M4 ;
        RECT 531.150 87.065 531.250 87.089 ;
    END
  END k_wdata[211]
  PIN k_wdata[210]
    DIRECTION OUTPUT ;
    USE SIGNAL ;
    PORT
      LAYER M4 ;
        RECT 531.150 87.161 531.250 87.185 ;
    END
  END k_wdata[210]
  PIN k_wdata[209]
    DIRECTION OUTPUT ;
    USE SIGNAL ;
    PORT
      LAYER M4 ;
        RECT 531.150 87.257 531.250 87.281 ;
    END
  END k_wdata[209]
  PIN k_wdata[208]
    DIRECTION OUTPUT ;
    USE SIGNAL ;
    PORT
      LAYER M4 ;
        RECT 531.150 87.353 531.250 87.377 ;
    END
  END k_wdata[208]
  PIN k_wdata[207]
    DIRECTION OUTPUT ;
    USE SIGNAL ;
    PORT
      LAYER M4 ;
        RECT 531.150 87.449 531.250 87.473 ;
    END
  END k_wdata[207]
  PIN k_wdata[206]
    DIRECTION OUTPUT ;
    USE SIGNAL ;
    PORT
      LAYER M4 ;
        RECT 531.150 87.545 531.250 87.569 ;
    END
  END k_wdata[206]
  PIN k_wdata[205]
    DIRECTION OUTPUT ;
    USE SIGNAL ;
    PORT
      LAYER M4 ;
        RECT 531.150 87.641 531.250 87.665 ;
    END
  END k_wdata[205]
  PIN k_wdata[204]
    DIRECTION OUTPUT ;
    USE SIGNAL ;
    PORT
      LAYER M4 ;
        RECT 531.150 87.737 531.250 87.761 ;
    END
  END k_wdata[204]
  PIN k_wdata[203]
    DIRECTION OUTPUT ;
    USE SIGNAL ;
    PORT
      LAYER M4 ;
        RECT 531.150 87.833 531.250 87.857 ;
    END
  END k_wdata[203]
  PIN k_wdata[202]
    DIRECTION OUTPUT ;
    USE SIGNAL ;
    PORT
      LAYER M4 ;
        RECT 531.150 87.929 531.250 87.953 ;
    END
  END k_wdata[202]
  PIN k_wdata[201]
    DIRECTION OUTPUT ;
    USE SIGNAL ;
    PORT
      LAYER M4 ;
        RECT 531.150 88.025 531.250 88.049 ;
    END
  END k_wdata[201]
  PIN k_wdata[200]
    DIRECTION OUTPUT ;
    USE SIGNAL ;
    PORT
      LAYER M4 ;
        RECT 531.150 88.121 531.250 88.145 ;
    END
  END k_wdata[200]
  PIN k_wdata[199]
    DIRECTION OUTPUT ;
    USE SIGNAL ;
    PORT
      LAYER M4 ;
        RECT 531.150 88.217 531.250 88.241 ;
    END
  END k_wdata[199]
  PIN k_wdata[198]
    DIRECTION OUTPUT ;
    USE SIGNAL ;
    PORT
      LAYER M4 ;
        RECT 531.150 88.313 531.250 88.337 ;
    END
  END k_wdata[198]
  PIN k_wdata[197]
    DIRECTION OUTPUT ;
    USE SIGNAL ;
    PORT
      LAYER M4 ;
        RECT 531.150 88.409 531.250 88.433 ;
    END
  END k_wdata[197]
  PIN k_wdata[196]
    DIRECTION OUTPUT ;
    USE SIGNAL ;
    PORT
      LAYER M4 ;
        RECT 531.150 88.505 531.250 88.529 ;
    END
  END k_wdata[196]
  PIN k_wdata[195]
    DIRECTION OUTPUT ;
    USE SIGNAL ;
    PORT
      LAYER M4 ;
        RECT 531.150 88.601 531.250 88.625 ;
    END
  END k_wdata[195]
  PIN k_wdata[194]
    DIRECTION OUTPUT ;
    USE SIGNAL ;
    PORT
      LAYER M4 ;
        RECT 531.150 88.697 531.250 88.721 ;
    END
  END k_wdata[194]
  PIN k_wdata[193]
    DIRECTION OUTPUT ;
    USE SIGNAL ;
    PORT
      LAYER M4 ;
        RECT 531.150 88.793 531.250 88.817 ;
    END
  END k_wdata[193]
  PIN k_wdata[192]
    DIRECTION OUTPUT ;
    USE SIGNAL ;
    PORT
      LAYER M4 ;
        RECT 531.150 88.889 531.250 88.913 ;
    END
  END k_wdata[192]
  PIN k_wdata[191]
    DIRECTION OUTPUT ;
    USE SIGNAL ;
    PORT
      LAYER M4 ;
        RECT 531.150 88.985 531.250 89.009 ;
    END
  END k_wdata[191]
  PIN k_wdata[190]
    DIRECTION OUTPUT ;
    USE SIGNAL ;
    PORT
      LAYER M4 ;
        RECT 531.150 89.081 531.250 89.105 ;
    END
  END k_wdata[190]
  PIN k_wdata[189]
    DIRECTION OUTPUT ;
    USE SIGNAL ;
    PORT
      LAYER M4 ;
        RECT 531.150 89.177 531.250 89.201 ;
    END
  END k_wdata[189]
  PIN k_wdata[188]
    DIRECTION OUTPUT ;
    USE SIGNAL ;
    PORT
      LAYER M4 ;
        RECT 531.150 89.273 531.250 89.297 ;
    END
  END k_wdata[188]
  PIN k_wdata[187]
    DIRECTION OUTPUT ;
    USE SIGNAL ;
    PORT
      LAYER M4 ;
        RECT 531.150 89.369 531.250 89.393 ;
    END
  END k_wdata[187]
  PIN k_wdata[186]
    DIRECTION OUTPUT ;
    USE SIGNAL ;
    PORT
      LAYER M4 ;
        RECT 531.150 89.465 531.250 89.489 ;
    END
  END k_wdata[186]
  PIN k_wdata[185]
    DIRECTION OUTPUT ;
    USE SIGNAL ;
    PORT
      LAYER M4 ;
        RECT 531.150 89.561 531.250 89.585 ;
    END
  END k_wdata[185]
  PIN k_wdata[184]
    DIRECTION OUTPUT ;
    USE SIGNAL ;
    PORT
      LAYER M4 ;
        RECT 531.150 89.657 531.250 89.681 ;
    END
  END k_wdata[184]
  PIN k_wdata[183]
    DIRECTION OUTPUT ;
    USE SIGNAL ;
    PORT
      LAYER M4 ;
        RECT 531.150 89.753 531.250 89.777 ;
    END
  END k_wdata[183]
  PIN k_wdata[182]
    DIRECTION OUTPUT ;
    USE SIGNAL ;
    PORT
      LAYER M4 ;
        RECT 531.150 89.849 531.250 89.873 ;
    END
  END k_wdata[182]
  PIN k_wdata[181]
    DIRECTION OUTPUT ;
    USE SIGNAL ;
    PORT
      LAYER M4 ;
        RECT 531.150 89.945 531.250 89.969 ;
    END
  END k_wdata[181]
  PIN k_wdata[180]
    DIRECTION OUTPUT ;
    USE SIGNAL ;
    PORT
      LAYER M4 ;
        RECT 531.150 90.041 531.250 90.065 ;
    END
  END k_wdata[180]
  PIN k_wdata[179]
    DIRECTION OUTPUT ;
    USE SIGNAL ;
    PORT
      LAYER M4 ;
        RECT 531.150 90.137 531.250 90.161 ;
    END
  END k_wdata[179]
  PIN k_wdata[178]
    DIRECTION OUTPUT ;
    USE SIGNAL ;
    PORT
      LAYER M4 ;
        RECT 531.150 90.233 531.250 90.257 ;
    END
  END k_wdata[178]
  PIN k_wdata[177]
    DIRECTION OUTPUT ;
    USE SIGNAL ;
    PORT
      LAYER M4 ;
        RECT 531.150 90.329 531.250 90.353 ;
    END
  END k_wdata[177]
  PIN k_wdata[176]
    DIRECTION OUTPUT ;
    USE SIGNAL ;
    PORT
      LAYER M4 ;
        RECT 531.150 90.425 531.250 90.449 ;
    END
  END k_wdata[176]
  PIN k_wdata[175]
    DIRECTION OUTPUT ;
    USE SIGNAL ;
    PORT
      LAYER M4 ;
        RECT 531.150 90.521 531.250 90.545 ;
    END
  END k_wdata[175]
  PIN k_wdata[174]
    DIRECTION OUTPUT ;
    USE SIGNAL ;
    PORT
      LAYER M4 ;
        RECT 531.150 90.617 531.250 90.641 ;
    END
  END k_wdata[174]
  PIN k_wdata[173]
    DIRECTION OUTPUT ;
    USE SIGNAL ;
    PORT
      LAYER M4 ;
        RECT 531.150 90.713 531.250 90.737 ;
    END
  END k_wdata[173]
  PIN k_wdata[172]
    DIRECTION OUTPUT ;
    USE SIGNAL ;
    PORT
      LAYER M4 ;
        RECT 531.150 90.809 531.250 90.833 ;
    END
  END k_wdata[172]
  PIN k_wdata[171]
    DIRECTION OUTPUT ;
    USE SIGNAL ;
    PORT
      LAYER M4 ;
        RECT 531.150 90.905 531.250 90.929 ;
    END
  END k_wdata[171]
  PIN k_wdata[170]
    DIRECTION OUTPUT ;
    USE SIGNAL ;
    PORT
      LAYER M4 ;
        RECT 531.150 91.001 531.250 91.025 ;
    END
  END k_wdata[170]
  PIN k_wdata[169]
    DIRECTION OUTPUT ;
    USE SIGNAL ;
    PORT
      LAYER M4 ;
        RECT 531.150 91.097 531.250 91.121 ;
    END
  END k_wdata[169]
  PIN k_wdata[168]
    DIRECTION OUTPUT ;
    USE SIGNAL ;
    PORT
      LAYER M4 ;
        RECT 531.150 91.193 531.250 91.217 ;
    END
  END k_wdata[168]
  PIN k_wdata[167]
    DIRECTION OUTPUT ;
    USE SIGNAL ;
    PORT
      LAYER M4 ;
        RECT 531.150 91.289 531.250 91.313 ;
    END
  END k_wdata[167]
  PIN k_wdata[166]
    DIRECTION OUTPUT ;
    USE SIGNAL ;
    PORT
      LAYER M4 ;
        RECT 531.150 91.385 531.250 91.409 ;
    END
  END k_wdata[166]
  PIN k_wdata[165]
    DIRECTION OUTPUT ;
    USE SIGNAL ;
    PORT
      LAYER M4 ;
        RECT 531.150 91.481 531.250 91.505 ;
    END
  END k_wdata[165]
  PIN k_wdata[164]
    DIRECTION OUTPUT ;
    USE SIGNAL ;
    PORT
      LAYER M4 ;
        RECT 531.150 91.577 531.250 91.601 ;
    END
  END k_wdata[164]
  PIN k_wdata[163]
    DIRECTION OUTPUT ;
    USE SIGNAL ;
    PORT
      LAYER M4 ;
        RECT 531.150 91.673 531.250 91.697 ;
    END
  END k_wdata[163]
  PIN k_wdata[162]
    DIRECTION OUTPUT ;
    USE SIGNAL ;
    PORT
      LAYER M4 ;
        RECT 531.150 91.769 531.250 91.793 ;
    END
  END k_wdata[162]
  PIN k_wdata[161]
    DIRECTION OUTPUT ;
    USE SIGNAL ;
    PORT
      LAYER M4 ;
        RECT 531.150 91.865 531.250 91.889 ;
    END
  END k_wdata[161]
  PIN k_wdata[160]
    DIRECTION OUTPUT ;
    USE SIGNAL ;
    PORT
      LAYER M4 ;
        RECT 531.150 91.961 531.250 91.985 ;
    END
  END k_wdata[160]
  PIN k_wdata[159]
    DIRECTION OUTPUT ;
    USE SIGNAL ;
    PORT
      LAYER M4 ;
        RECT 531.150 92.057 531.250 92.081 ;
    END
  END k_wdata[159]
  PIN k_wdata[158]
    DIRECTION OUTPUT ;
    USE SIGNAL ;
    PORT
      LAYER M4 ;
        RECT 531.150 92.153 531.250 92.177 ;
    END
  END k_wdata[158]
  PIN k_wdata[157]
    DIRECTION OUTPUT ;
    USE SIGNAL ;
    PORT
      LAYER M4 ;
        RECT 531.150 92.249 531.250 92.273 ;
    END
  END k_wdata[157]
  PIN k_wdata[156]
    DIRECTION OUTPUT ;
    USE SIGNAL ;
    PORT
      LAYER M4 ;
        RECT 531.150 92.345 531.250 92.369 ;
    END
  END k_wdata[156]
  PIN k_wdata[155]
    DIRECTION OUTPUT ;
    USE SIGNAL ;
    PORT
      LAYER M4 ;
        RECT 531.150 92.441 531.250 92.465 ;
    END
  END k_wdata[155]
  PIN k_wdata[154]
    DIRECTION OUTPUT ;
    USE SIGNAL ;
    PORT
      LAYER M4 ;
        RECT 531.150 92.537 531.250 92.561 ;
    END
  END k_wdata[154]
  PIN k_wdata[153]
    DIRECTION OUTPUT ;
    USE SIGNAL ;
    PORT
      LAYER M4 ;
        RECT 531.150 92.633 531.250 92.657 ;
    END
  END k_wdata[153]
  PIN k_wdata[152]
    DIRECTION OUTPUT ;
    USE SIGNAL ;
    PORT
      LAYER M4 ;
        RECT 531.150 92.729 531.250 92.753 ;
    END
  END k_wdata[152]
  PIN k_wdata[151]
    DIRECTION OUTPUT ;
    USE SIGNAL ;
    PORT
      LAYER M4 ;
        RECT 531.150 92.825 531.250 92.849 ;
    END
  END k_wdata[151]
  PIN k_wdata[150]
    DIRECTION OUTPUT ;
    USE SIGNAL ;
    PORT
      LAYER M4 ;
        RECT 531.150 92.921 531.250 92.945 ;
    END
  END k_wdata[150]
  PIN k_wdata[149]
    DIRECTION OUTPUT ;
    USE SIGNAL ;
    PORT
      LAYER M4 ;
        RECT 531.150 93.017 531.250 93.041 ;
    END
  END k_wdata[149]
  PIN k_wdata[148]
    DIRECTION OUTPUT ;
    USE SIGNAL ;
    PORT
      LAYER M4 ;
        RECT 531.150 93.113 531.250 93.137 ;
    END
  END k_wdata[148]
  PIN k_wdata[147]
    DIRECTION OUTPUT ;
    USE SIGNAL ;
    PORT
      LAYER M4 ;
        RECT 531.150 93.209 531.250 93.233 ;
    END
  END k_wdata[147]
  PIN k_wdata[146]
    DIRECTION OUTPUT ;
    USE SIGNAL ;
    PORT
      LAYER M4 ;
        RECT 531.150 93.305 531.250 93.329 ;
    END
  END k_wdata[146]
  PIN k_wdata[145]
    DIRECTION OUTPUT ;
    USE SIGNAL ;
    PORT
      LAYER M4 ;
        RECT 531.150 93.401 531.250 93.425 ;
    END
  END k_wdata[145]
  PIN k_wdata[144]
    DIRECTION OUTPUT ;
    USE SIGNAL ;
    PORT
      LAYER M4 ;
        RECT 531.150 93.497 531.250 93.521 ;
    END
  END k_wdata[144]
  PIN k_wdata[143]
    DIRECTION OUTPUT ;
    USE SIGNAL ;
    PORT
      LAYER M4 ;
        RECT 531.150 93.593 531.250 93.617 ;
    END
  END k_wdata[143]
  PIN k_wdata[142]
    DIRECTION OUTPUT ;
    USE SIGNAL ;
    PORT
      LAYER M4 ;
        RECT 531.150 93.689 531.250 93.713 ;
    END
  END k_wdata[142]
  PIN k_wdata[141]
    DIRECTION OUTPUT ;
    USE SIGNAL ;
    PORT
      LAYER M4 ;
        RECT 531.150 93.785 531.250 93.809 ;
    END
  END k_wdata[141]
  PIN k_wdata[140]
    DIRECTION OUTPUT ;
    USE SIGNAL ;
    PORT
      LAYER M4 ;
        RECT 531.150 93.881 531.250 93.905 ;
    END
  END k_wdata[140]
  PIN k_wdata[139]
    DIRECTION OUTPUT ;
    USE SIGNAL ;
    PORT
      LAYER M4 ;
        RECT 531.150 93.977 531.250 94.001 ;
    END
  END k_wdata[139]
  PIN k_wdata[138]
    DIRECTION OUTPUT ;
    USE SIGNAL ;
    PORT
      LAYER M4 ;
        RECT 531.150 94.073 531.250 94.097 ;
    END
  END k_wdata[138]
  PIN k_wdata[137]
    DIRECTION OUTPUT ;
    USE SIGNAL ;
    PORT
      LAYER M4 ;
        RECT 531.150 94.169 531.250 94.193 ;
    END
  END k_wdata[137]
  PIN k_wdata[136]
    DIRECTION OUTPUT ;
    USE SIGNAL ;
    PORT
      LAYER M4 ;
        RECT 531.150 94.265 531.250 94.289 ;
    END
  END k_wdata[136]
  PIN k_wdata[135]
    DIRECTION OUTPUT ;
    USE SIGNAL ;
    PORT
      LAYER M4 ;
        RECT 531.150 94.361 531.250 94.385 ;
    END
  END k_wdata[135]
  PIN k_wdata[134]
    DIRECTION OUTPUT ;
    USE SIGNAL ;
    PORT
      LAYER M4 ;
        RECT 531.150 94.457 531.250 94.481 ;
    END
  END k_wdata[134]
  PIN k_wdata[133]
    DIRECTION OUTPUT ;
    USE SIGNAL ;
    PORT
      LAYER M4 ;
        RECT 531.150 94.553 531.250 94.577 ;
    END
  END k_wdata[133]
  PIN k_wdata[132]
    DIRECTION OUTPUT ;
    USE SIGNAL ;
    PORT
      LAYER M4 ;
        RECT 531.150 94.649 531.250 94.673 ;
    END
  END k_wdata[132]
  PIN k_wdata[131]
    DIRECTION OUTPUT ;
    USE SIGNAL ;
    PORT
      LAYER M4 ;
        RECT 531.150 94.745 531.250 94.769 ;
    END
  END k_wdata[131]
  PIN k_wdata[130]
    DIRECTION OUTPUT ;
    USE SIGNAL ;
    PORT
      LAYER M4 ;
        RECT 531.150 94.841 531.250 94.865 ;
    END
  END k_wdata[130]
  PIN k_wdata[129]
    DIRECTION OUTPUT ;
    USE SIGNAL ;
    PORT
      LAYER M4 ;
        RECT 531.150 94.937 531.250 94.961 ;
    END
  END k_wdata[129]
  PIN k_wdata[128]
    DIRECTION OUTPUT ;
    USE SIGNAL ;
    PORT
      LAYER M4 ;
        RECT 531.150 95.033 531.250 95.057 ;
    END
  END k_wdata[128]
  PIN k_wdata[127]
    DIRECTION OUTPUT ;
    USE SIGNAL ;
    PORT
      LAYER M4 ;
        RECT 531.150 95.129 531.250 95.153 ;
    END
  END k_wdata[127]
  PIN k_wdata[126]
    DIRECTION OUTPUT ;
    USE SIGNAL ;
    PORT
      LAYER M4 ;
        RECT 531.150 95.225 531.250 95.249 ;
    END
  END k_wdata[126]
  PIN k_wdata[125]
    DIRECTION OUTPUT ;
    USE SIGNAL ;
    PORT
      LAYER M4 ;
        RECT 531.150 95.321 531.250 95.345 ;
    END
  END k_wdata[125]
  PIN k_wdata[124]
    DIRECTION OUTPUT ;
    USE SIGNAL ;
    PORT
      LAYER M4 ;
        RECT 531.150 95.417 531.250 95.441 ;
    END
  END k_wdata[124]
  PIN k_wdata[123]
    DIRECTION OUTPUT ;
    USE SIGNAL ;
    PORT
      LAYER M4 ;
        RECT 531.150 95.513 531.250 95.537 ;
    END
  END k_wdata[123]
  PIN k_wdata[122]
    DIRECTION OUTPUT ;
    USE SIGNAL ;
    PORT
      LAYER M4 ;
        RECT 531.150 95.609 531.250 95.633 ;
    END
  END k_wdata[122]
  PIN k_wdata[121]
    DIRECTION OUTPUT ;
    USE SIGNAL ;
    PORT
      LAYER M4 ;
        RECT 531.150 95.705 531.250 95.729 ;
    END
  END k_wdata[121]
  PIN k_wdata[120]
    DIRECTION OUTPUT ;
    USE SIGNAL ;
    PORT
      LAYER M4 ;
        RECT 531.150 95.801 531.250 95.825 ;
    END
  END k_wdata[120]
  PIN k_wdata[119]
    DIRECTION OUTPUT ;
    USE SIGNAL ;
    PORT
      LAYER M4 ;
        RECT 531.150 95.897 531.250 95.921 ;
    END
  END k_wdata[119]
  PIN k_wdata[118]
    DIRECTION OUTPUT ;
    USE SIGNAL ;
    PORT
      LAYER M4 ;
        RECT 531.150 95.993 531.250 96.017 ;
    END
  END k_wdata[118]
  PIN k_wdata[117]
    DIRECTION OUTPUT ;
    USE SIGNAL ;
    PORT
      LAYER M4 ;
        RECT 531.150 96.089 531.250 96.113 ;
    END
  END k_wdata[117]
  PIN k_wdata[116]
    DIRECTION OUTPUT ;
    USE SIGNAL ;
    PORT
      LAYER M4 ;
        RECT 531.150 96.185 531.250 96.209 ;
    END
  END k_wdata[116]
  PIN k_wdata[115]
    DIRECTION OUTPUT ;
    USE SIGNAL ;
    PORT
      LAYER M4 ;
        RECT 531.150 96.281 531.250 96.305 ;
    END
  END k_wdata[115]
  PIN k_wdata[114]
    DIRECTION OUTPUT ;
    USE SIGNAL ;
    PORT
      LAYER M4 ;
        RECT 531.150 96.377 531.250 96.401 ;
    END
  END k_wdata[114]
  PIN k_wdata[113]
    DIRECTION OUTPUT ;
    USE SIGNAL ;
    PORT
      LAYER M4 ;
        RECT 531.150 96.473 531.250 96.497 ;
    END
  END k_wdata[113]
  PIN k_wdata[112]
    DIRECTION OUTPUT ;
    USE SIGNAL ;
    PORT
      LAYER M4 ;
        RECT 531.150 96.569 531.250 96.593 ;
    END
  END k_wdata[112]
  PIN k_wdata[111]
    DIRECTION OUTPUT ;
    USE SIGNAL ;
    PORT
      LAYER M4 ;
        RECT 531.150 96.665 531.250 96.689 ;
    END
  END k_wdata[111]
  PIN k_wdata[110]
    DIRECTION OUTPUT ;
    USE SIGNAL ;
    PORT
      LAYER M4 ;
        RECT 531.150 96.761 531.250 96.785 ;
    END
  END k_wdata[110]
  PIN k_wdata[109]
    DIRECTION OUTPUT ;
    USE SIGNAL ;
    PORT
      LAYER M4 ;
        RECT 531.150 96.857 531.250 96.881 ;
    END
  END k_wdata[109]
  PIN k_wdata[108]
    DIRECTION OUTPUT ;
    USE SIGNAL ;
    PORT
      LAYER M4 ;
        RECT 531.150 96.953 531.250 96.977 ;
    END
  END k_wdata[108]
  PIN k_wdata[107]
    DIRECTION OUTPUT ;
    USE SIGNAL ;
    PORT
      LAYER M4 ;
        RECT 531.150 97.049 531.250 97.073 ;
    END
  END k_wdata[107]
  PIN k_wdata[106]
    DIRECTION OUTPUT ;
    USE SIGNAL ;
    PORT
      LAYER M4 ;
        RECT 531.150 97.145 531.250 97.169 ;
    END
  END k_wdata[106]
  PIN k_wdata[105]
    DIRECTION OUTPUT ;
    USE SIGNAL ;
    PORT
      LAYER M4 ;
        RECT 531.150 97.241 531.250 97.265 ;
    END
  END k_wdata[105]
  PIN k_wdata[104]
    DIRECTION OUTPUT ;
    USE SIGNAL ;
    PORT
      LAYER M4 ;
        RECT 531.150 97.337 531.250 97.361 ;
    END
  END k_wdata[104]
  PIN k_wdata[103]
    DIRECTION OUTPUT ;
    USE SIGNAL ;
    PORT
      LAYER M4 ;
        RECT 531.150 97.433 531.250 97.457 ;
    END
  END k_wdata[103]
  PIN k_wdata[102]
    DIRECTION OUTPUT ;
    USE SIGNAL ;
    PORT
      LAYER M4 ;
        RECT 531.150 97.529 531.250 97.553 ;
    END
  END k_wdata[102]
  PIN k_wdata[101]
    DIRECTION OUTPUT ;
    USE SIGNAL ;
    PORT
      LAYER M4 ;
        RECT 531.150 97.625 531.250 97.649 ;
    END
  END k_wdata[101]
  PIN k_wdata[100]
    DIRECTION OUTPUT ;
    USE SIGNAL ;
    PORT
      LAYER M4 ;
        RECT 531.150 97.721 531.250 97.745 ;
    END
  END k_wdata[100]
  PIN k_wdata[99]
    DIRECTION OUTPUT ;
    USE SIGNAL ;
    PORT
      LAYER M4 ;
        RECT 531.150 97.817 531.250 97.841 ;
    END
  END k_wdata[99]
  PIN k_wdata[98]
    DIRECTION OUTPUT ;
    USE SIGNAL ;
    PORT
      LAYER M4 ;
        RECT 531.150 97.913 531.250 97.937 ;
    END
  END k_wdata[98]
  PIN k_wdata[97]
    DIRECTION OUTPUT ;
    USE SIGNAL ;
    PORT
      LAYER M4 ;
        RECT 531.150 98.009 531.250 98.033 ;
    END
  END k_wdata[97]
  PIN k_wdata[96]
    DIRECTION OUTPUT ;
    USE SIGNAL ;
    PORT
      LAYER M4 ;
        RECT 531.150 98.105 531.250 98.129 ;
    END
  END k_wdata[96]
  PIN k_wdata[95]
    DIRECTION OUTPUT ;
    USE SIGNAL ;
    PORT
      LAYER M4 ;
        RECT 531.150 98.201 531.250 98.225 ;
    END
  END k_wdata[95]
  PIN k_wdata[94]
    DIRECTION OUTPUT ;
    USE SIGNAL ;
    PORT
      LAYER M4 ;
        RECT 531.150 98.297 531.250 98.321 ;
    END
  END k_wdata[94]
  PIN k_wdata[93]
    DIRECTION OUTPUT ;
    USE SIGNAL ;
    PORT
      LAYER M4 ;
        RECT 531.150 98.393 531.250 98.417 ;
    END
  END k_wdata[93]
  PIN k_wdata[92]
    DIRECTION OUTPUT ;
    USE SIGNAL ;
    PORT
      LAYER M4 ;
        RECT 531.150 98.489 531.250 98.513 ;
    END
  END k_wdata[92]
  PIN k_wdata[91]
    DIRECTION OUTPUT ;
    USE SIGNAL ;
    PORT
      LAYER M4 ;
        RECT 531.150 98.585 531.250 98.609 ;
    END
  END k_wdata[91]
  PIN k_wdata[90]
    DIRECTION OUTPUT ;
    USE SIGNAL ;
    PORT
      LAYER M4 ;
        RECT 531.150 98.681 531.250 98.705 ;
    END
  END k_wdata[90]
  PIN k_wdata[89]
    DIRECTION OUTPUT ;
    USE SIGNAL ;
    PORT
      LAYER M4 ;
        RECT 531.150 98.777 531.250 98.801 ;
    END
  END k_wdata[89]
  PIN k_wdata[88]
    DIRECTION OUTPUT ;
    USE SIGNAL ;
    PORT
      LAYER M4 ;
        RECT 531.150 98.873 531.250 98.897 ;
    END
  END k_wdata[88]
  PIN k_wdata[87]
    DIRECTION OUTPUT ;
    USE SIGNAL ;
    PORT
      LAYER M4 ;
        RECT 531.150 98.969 531.250 98.993 ;
    END
  END k_wdata[87]
  PIN k_wdata[86]
    DIRECTION OUTPUT ;
    USE SIGNAL ;
    PORT
      LAYER M4 ;
        RECT 531.150 99.065 531.250 99.089 ;
    END
  END k_wdata[86]
  PIN k_wdata[85]
    DIRECTION OUTPUT ;
    USE SIGNAL ;
    PORT
      LAYER M4 ;
        RECT 531.150 99.161 531.250 99.185 ;
    END
  END k_wdata[85]
  PIN k_wdata[84]
    DIRECTION OUTPUT ;
    USE SIGNAL ;
    PORT
      LAYER M4 ;
        RECT 531.150 99.257 531.250 99.281 ;
    END
  END k_wdata[84]
  PIN k_wdata[83]
    DIRECTION OUTPUT ;
    USE SIGNAL ;
    PORT
      LAYER M4 ;
        RECT 531.150 99.353 531.250 99.377 ;
    END
  END k_wdata[83]
  PIN k_wdata[82]
    DIRECTION OUTPUT ;
    USE SIGNAL ;
    PORT
      LAYER M4 ;
        RECT 531.150 99.449 531.250 99.473 ;
    END
  END k_wdata[82]
  PIN k_wdata[81]
    DIRECTION OUTPUT ;
    USE SIGNAL ;
    PORT
      LAYER M4 ;
        RECT 531.150 99.545 531.250 99.569 ;
    END
  END k_wdata[81]
  PIN k_wdata[80]
    DIRECTION OUTPUT ;
    USE SIGNAL ;
    PORT
      LAYER M4 ;
        RECT 531.150 99.641 531.250 99.665 ;
    END
  END k_wdata[80]
  PIN k_wdata[79]
    DIRECTION OUTPUT ;
    USE SIGNAL ;
    PORT
      LAYER M4 ;
        RECT 531.150 99.737 531.250 99.761 ;
    END
  END k_wdata[79]
  PIN k_wdata[78]
    DIRECTION OUTPUT ;
    USE SIGNAL ;
    PORT
      LAYER M4 ;
        RECT 531.150 99.833 531.250 99.857 ;
    END
  END k_wdata[78]
  PIN k_wdata[77]
    DIRECTION OUTPUT ;
    USE SIGNAL ;
    PORT
      LAYER M4 ;
        RECT 531.150 99.929 531.250 99.953 ;
    END
  END k_wdata[77]
  PIN k_wdata[76]
    DIRECTION OUTPUT ;
    USE SIGNAL ;
    PORT
      LAYER M4 ;
        RECT 531.150 100.025 531.250 100.049 ;
    END
  END k_wdata[76]
  PIN k_wdata[75]
    DIRECTION OUTPUT ;
    USE SIGNAL ;
    PORT
      LAYER M4 ;
        RECT 531.150 100.121 531.250 100.145 ;
    END
  END k_wdata[75]
  PIN k_wdata[74]
    DIRECTION OUTPUT ;
    USE SIGNAL ;
    PORT
      LAYER M4 ;
        RECT 531.150 100.217 531.250 100.241 ;
    END
  END k_wdata[74]
  PIN k_wdata[73]
    DIRECTION OUTPUT ;
    USE SIGNAL ;
    PORT
      LAYER M4 ;
        RECT 531.150 100.313 531.250 100.337 ;
    END
  END k_wdata[73]
  PIN k_wdata[72]
    DIRECTION OUTPUT ;
    USE SIGNAL ;
    PORT
      LAYER M4 ;
        RECT 531.150 100.409 531.250 100.433 ;
    END
  END k_wdata[72]
  PIN k_wdata[71]
    DIRECTION OUTPUT ;
    USE SIGNAL ;
    PORT
      LAYER M4 ;
        RECT 531.150 100.505 531.250 100.529 ;
    END
  END k_wdata[71]
  PIN k_wdata[70]
    DIRECTION OUTPUT ;
    USE SIGNAL ;
    PORT
      LAYER M4 ;
        RECT 531.150 100.601 531.250 100.625 ;
    END
  END k_wdata[70]
  PIN k_wdata[69]
    DIRECTION OUTPUT ;
    USE SIGNAL ;
    PORT
      LAYER M4 ;
        RECT 531.150 100.697 531.250 100.721 ;
    END
  END k_wdata[69]
  PIN k_wdata[68]
    DIRECTION OUTPUT ;
    USE SIGNAL ;
    PORT
      LAYER M4 ;
        RECT 531.150 100.793 531.250 100.817 ;
    END
  END k_wdata[68]
  PIN k_wdata[67]
    DIRECTION OUTPUT ;
    USE SIGNAL ;
    PORT
      LAYER M4 ;
        RECT 531.150 100.889 531.250 100.913 ;
    END
  END k_wdata[67]
  PIN k_wdata[66]
    DIRECTION OUTPUT ;
    USE SIGNAL ;
    PORT
      LAYER M4 ;
        RECT 531.150 100.985 531.250 101.009 ;
    END
  END k_wdata[66]
  PIN k_wdata[65]
    DIRECTION OUTPUT ;
    USE SIGNAL ;
    PORT
      LAYER M4 ;
        RECT 531.150 101.081 531.250 101.105 ;
    END
  END k_wdata[65]
  PIN k_wdata[64]
    DIRECTION OUTPUT ;
    USE SIGNAL ;
    PORT
      LAYER M4 ;
        RECT 531.150 101.177 531.250 101.201 ;
    END
  END k_wdata[64]
  PIN k_wdata[63]
    DIRECTION OUTPUT ;
    USE SIGNAL ;
    PORT
      LAYER M4 ;
        RECT 531.150 101.273 531.250 101.297 ;
    END
  END k_wdata[63]
  PIN k_wdata[62]
    DIRECTION OUTPUT ;
    USE SIGNAL ;
    PORT
      LAYER M4 ;
        RECT 531.150 101.369 531.250 101.393 ;
    END
  END k_wdata[62]
  PIN k_wdata[61]
    DIRECTION OUTPUT ;
    USE SIGNAL ;
    PORT
      LAYER M4 ;
        RECT 531.150 101.465 531.250 101.489 ;
    END
  END k_wdata[61]
  PIN k_wdata[60]
    DIRECTION OUTPUT ;
    USE SIGNAL ;
    PORT
      LAYER M4 ;
        RECT 531.150 101.561 531.250 101.585 ;
    END
  END k_wdata[60]
  PIN k_wdata[59]
    DIRECTION OUTPUT ;
    USE SIGNAL ;
    PORT
      LAYER M4 ;
        RECT 531.150 101.657 531.250 101.681 ;
    END
  END k_wdata[59]
  PIN k_wdata[58]
    DIRECTION OUTPUT ;
    USE SIGNAL ;
    PORT
      LAYER M4 ;
        RECT 531.150 101.753 531.250 101.777 ;
    END
  END k_wdata[58]
  PIN k_wdata[57]
    DIRECTION OUTPUT ;
    USE SIGNAL ;
    PORT
      LAYER M4 ;
        RECT 531.150 101.849 531.250 101.873 ;
    END
  END k_wdata[57]
  PIN k_wdata[56]
    DIRECTION OUTPUT ;
    USE SIGNAL ;
    PORT
      LAYER M4 ;
        RECT 531.150 101.945 531.250 101.969 ;
    END
  END k_wdata[56]
  PIN k_wdata[55]
    DIRECTION OUTPUT ;
    USE SIGNAL ;
    PORT
      LAYER M4 ;
        RECT 531.150 102.041 531.250 102.065 ;
    END
  END k_wdata[55]
  PIN k_wdata[54]
    DIRECTION OUTPUT ;
    USE SIGNAL ;
    PORT
      LAYER M4 ;
        RECT 531.150 102.137 531.250 102.161 ;
    END
  END k_wdata[54]
  PIN k_wdata[53]
    DIRECTION OUTPUT ;
    USE SIGNAL ;
    PORT
      LAYER M4 ;
        RECT 531.150 102.233 531.250 102.257 ;
    END
  END k_wdata[53]
  PIN k_wdata[52]
    DIRECTION OUTPUT ;
    USE SIGNAL ;
    PORT
      LAYER M4 ;
        RECT 531.150 102.329 531.250 102.353 ;
    END
  END k_wdata[52]
  PIN k_wdata[51]
    DIRECTION OUTPUT ;
    USE SIGNAL ;
    PORT
      LAYER M4 ;
        RECT 531.150 102.425 531.250 102.449 ;
    END
  END k_wdata[51]
  PIN k_wdata[50]
    DIRECTION OUTPUT ;
    USE SIGNAL ;
    PORT
      LAYER M4 ;
        RECT 531.150 102.521 531.250 102.545 ;
    END
  END k_wdata[50]
  PIN k_wdata[49]
    DIRECTION OUTPUT ;
    USE SIGNAL ;
    PORT
      LAYER M4 ;
        RECT 531.150 102.617 531.250 102.641 ;
    END
  END k_wdata[49]
  PIN k_wdata[48]
    DIRECTION OUTPUT ;
    USE SIGNAL ;
    PORT
      LAYER M4 ;
        RECT 531.150 102.713 531.250 102.737 ;
    END
  END k_wdata[48]
  PIN k_wdata[47]
    DIRECTION OUTPUT ;
    USE SIGNAL ;
    PORT
      LAYER M4 ;
        RECT 531.150 102.809 531.250 102.833 ;
    END
  END k_wdata[47]
  PIN k_wdata[46]
    DIRECTION OUTPUT ;
    USE SIGNAL ;
    PORT
      LAYER M4 ;
        RECT 531.150 102.905 531.250 102.929 ;
    END
  END k_wdata[46]
  PIN k_wdata[45]
    DIRECTION OUTPUT ;
    USE SIGNAL ;
    PORT
      LAYER M4 ;
        RECT 531.150 103.001 531.250 103.025 ;
    END
  END k_wdata[45]
  PIN k_wdata[44]
    DIRECTION OUTPUT ;
    USE SIGNAL ;
    PORT
      LAYER M4 ;
        RECT 531.150 103.097 531.250 103.121 ;
    END
  END k_wdata[44]
  PIN k_wdata[43]
    DIRECTION OUTPUT ;
    USE SIGNAL ;
    PORT
      LAYER M4 ;
        RECT 531.150 103.193 531.250 103.217 ;
    END
  END k_wdata[43]
  PIN k_wdata[42]
    DIRECTION OUTPUT ;
    USE SIGNAL ;
    PORT
      LAYER M4 ;
        RECT 531.150 103.289 531.250 103.313 ;
    END
  END k_wdata[42]
  PIN k_wdata[41]
    DIRECTION OUTPUT ;
    USE SIGNAL ;
    PORT
      LAYER M4 ;
        RECT 531.150 103.385 531.250 103.409 ;
    END
  END k_wdata[41]
  PIN k_wdata[40]
    DIRECTION OUTPUT ;
    USE SIGNAL ;
    PORT
      LAYER M4 ;
        RECT 531.150 103.481 531.250 103.505 ;
    END
  END k_wdata[40]
  PIN k_wdata[39]
    DIRECTION OUTPUT ;
    USE SIGNAL ;
    PORT
      LAYER M4 ;
        RECT 531.150 103.577 531.250 103.601 ;
    END
  END k_wdata[39]
  PIN k_wdata[38]
    DIRECTION OUTPUT ;
    USE SIGNAL ;
    PORT
      LAYER M4 ;
        RECT 531.150 103.673 531.250 103.697 ;
    END
  END k_wdata[38]
  PIN k_wdata[37]
    DIRECTION OUTPUT ;
    USE SIGNAL ;
    PORT
      LAYER M4 ;
        RECT 531.150 103.769 531.250 103.793 ;
    END
  END k_wdata[37]
  PIN k_wdata[36]
    DIRECTION OUTPUT ;
    USE SIGNAL ;
    PORT
      LAYER M4 ;
        RECT 531.150 103.865 531.250 103.889 ;
    END
  END k_wdata[36]
  PIN k_wdata[35]
    DIRECTION OUTPUT ;
    USE SIGNAL ;
    PORT
      LAYER M4 ;
        RECT 531.150 103.961 531.250 103.985 ;
    END
  END k_wdata[35]
  PIN k_wdata[34]
    DIRECTION OUTPUT ;
    USE SIGNAL ;
    PORT
      LAYER M4 ;
        RECT 531.150 104.057 531.250 104.081 ;
    END
  END k_wdata[34]
  PIN k_wdata[33]
    DIRECTION OUTPUT ;
    USE SIGNAL ;
    PORT
      LAYER M4 ;
        RECT 531.150 104.153 531.250 104.177 ;
    END
  END k_wdata[33]
  PIN k_wdata[32]
    DIRECTION OUTPUT ;
    USE SIGNAL ;
    PORT
      LAYER M4 ;
        RECT 531.150 104.249 531.250 104.273 ;
    END
  END k_wdata[32]
  PIN k_wdata[31]
    DIRECTION OUTPUT ;
    USE SIGNAL ;
    PORT
      LAYER M4 ;
        RECT 531.150 104.345 531.250 104.369 ;
    END
  END k_wdata[31]
  PIN k_wdata[30]
    DIRECTION OUTPUT ;
    USE SIGNAL ;
    PORT
      LAYER M4 ;
        RECT 531.150 104.441 531.250 104.465 ;
    END
  END k_wdata[30]
  PIN k_wdata[29]
    DIRECTION OUTPUT ;
    USE SIGNAL ;
    PORT
      LAYER M4 ;
        RECT 531.150 104.537 531.250 104.561 ;
    END
  END k_wdata[29]
  PIN k_wdata[28]
    DIRECTION OUTPUT ;
    USE SIGNAL ;
    PORT
      LAYER M4 ;
        RECT 531.150 104.633 531.250 104.657 ;
    END
  END k_wdata[28]
  PIN k_wdata[27]
    DIRECTION OUTPUT ;
    USE SIGNAL ;
    PORT
      LAYER M4 ;
        RECT 531.150 104.729 531.250 104.753 ;
    END
  END k_wdata[27]
  PIN k_wdata[26]
    DIRECTION OUTPUT ;
    USE SIGNAL ;
    PORT
      LAYER M4 ;
        RECT 531.150 104.825 531.250 104.849 ;
    END
  END k_wdata[26]
  PIN k_wdata[25]
    DIRECTION OUTPUT ;
    USE SIGNAL ;
    PORT
      LAYER M4 ;
        RECT 531.150 104.921 531.250 104.945 ;
    END
  END k_wdata[25]
  PIN k_wdata[24]
    DIRECTION OUTPUT ;
    USE SIGNAL ;
    PORT
      LAYER M4 ;
        RECT 531.150 105.017 531.250 105.041 ;
    END
  END k_wdata[24]
  PIN k_wdata[23]
    DIRECTION OUTPUT ;
    USE SIGNAL ;
    PORT
      LAYER M4 ;
        RECT 531.150 105.113 531.250 105.137 ;
    END
  END k_wdata[23]
  PIN k_wdata[22]
    DIRECTION OUTPUT ;
    USE SIGNAL ;
    PORT
      LAYER M4 ;
        RECT 531.150 105.209 531.250 105.233 ;
    END
  END k_wdata[22]
  PIN k_wdata[21]
    DIRECTION OUTPUT ;
    USE SIGNAL ;
    PORT
      LAYER M4 ;
        RECT 531.150 105.305 531.250 105.329 ;
    END
  END k_wdata[21]
  PIN k_wdata[20]
    DIRECTION OUTPUT ;
    USE SIGNAL ;
    PORT
      LAYER M4 ;
        RECT 531.150 105.401 531.250 105.425 ;
    END
  END k_wdata[20]
  PIN k_wdata[19]
    DIRECTION OUTPUT ;
    USE SIGNAL ;
    PORT
      LAYER M4 ;
        RECT 531.150 105.497 531.250 105.521 ;
    END
  END k_wdata[19]
  PIN k_wdata[18]
    DIRECTION OUTPUT ;
    USE SIGNAL ;
    PORT
      LAYER M4 ;
        RECT 531.150 105.593 531.250 105.617 ;
    END
  END k_wdata[18]
  PIN k_wdata[17]
    DIRECTION OUTPUT ;
    USE SIGNAL ;
    PORT
      LAYER M4 ;
        RECT 531.150 105.689 531.250 105.713 ;
    END
  END k_wdata[17]
  PIN k_wdata[16]
    DIRECTION OUTPUT ;
    USE SIGNAL ;
    PORT
      LAYER M4 ;
        RECT 531.150 105.785 531.250 105.809 ;
    END
  END k_wdata[16]
  PIN k_wdata[15]
    DIRECTION OUTPUT ;
    USE SIGNAL ;
    PORT
      LAYER M4 ;
        RECT 531.150 105.881 531.250 105.905 ;
    END
  END k_wdata[15]
  PIN k_wdata[14]
    DIRECTION OUTPUT ;
    USE SIGNAL ;
    PORT
      LAYER M4 ;
        RECT 531.150 105.977 531.250 106.001 ;
    END
  END k_wdata[14]
  PIN k_wdata[13]
    DIRECTION OUTPUT ;
    USE SIGNAL ;
    PORT
      LAYER M4 ;
        RECT 531.150 106.073 531.250 106.097 ;
    END
  END k_wdata[13]
  PIN k_wdata[12]
    DIRECTION OUTPUT ;
    USE SIGNAL ;
    PORT
      LAYER M4 ;
        RECT 531.150 106.169 531.250 106.193 ;
    END
  END k_wdata[12]
  PIN k_wdata[11]
    DIRECTION OUTPUT ;
    USE SIGNAL ;
    PORT
      LAYER M4 ;
        RECT 531.150 106.265 531.250 106.289 ;
    END
  END k_wdata[11]
  PIN k_wdata[10]
    DIRECTION OUTPUT ;
    USE SIGNAL ;
    PORT
      LAYER M4 ;
        RECT 531.150 106.361 531.250 106.385 ;
    END
  END k_wdata[10]
  PIN k_wdata[9]
    DIRECTION OUTPUT ;
    USE SIGNAL ;
    PORT
      LAYER M4 ;
        RECT 531.150 106.457 531.250 106.481 ;
    END
  END k_wdata[9]
  PIN k_wdata[8]
    DIRECTION OUTPUT ;
    USE SIGNAL ;
    PORT
      LAYER M4 ;
        RECT 531.150 106.553 531.250 106.577 ;
    END
  END k_wdata[8]
  PIN k_wdata[7]
    DIRECTION OUTPUT ;
    USE SIGNAL ;
    PORT
      LAYER M4 ;
        RECT 531.150 106.649 531.250 106.673 ;
    END
  END k_wdata[7]
  PIN k_wdata[6]
    DIRECTION OUTPUT ;
    USE SIGNAL ;
    PORT
      LAYER M4 ;
        RECT 531.150 106.745 531.250 106.769 ;
    END
  END k_wdata[6]
  PIN k_wdata[5]
    DIRECTION OUTPUT ;
    USE SIGNAL ;
    PORT
      LAYER M4 ;
        RECT 531.150 106.841 531.250 106.865 ;
    END
  END k_wdata[5]
  PIN k_wdata[4]
    DIRECTION OUTPUT ;
    USE SIGNAL ;
    PORT
      LAYER M4 ;
        RECT 531.150 106.937 531.250 106.961 ;
    END
  END k_wdata[4]
  PIN k_wdata[3]
    DIRECTION OUTPUT ;
    USE SIGNAL ;
    PORT
      LAYER M4 ;
        RECT 531.150 107.033 531.250 107.057 ;
    END
  END k_wdata[3]
  PIN k_wdata[2]
    DIRECTION OUTPUT ;
    USE SIGNAL ;
    PORT
      LAYER M4 ;
        RECT 531.150 107.129 531.250 107.153 ;
    END
  END k_wdata[2]
  PIN k_wdata[1]
    DIRECTION OUTPUT ;
    USE SIGNAL ;
    PORT
      LAYER M4 ;
        RECT 531.150 107.225 531.250 107.249 ;
    END
  END k_wdata[1]
  PIN k_wdata[0]
    DIRECTION OUTPUT ;
    USE SIGNAL ;
    PORT
      LAYER M4 ;
        RECT 531.150 107.321 531.250 107.345 ;
    END
  END k_wdata[0]
  PIN k_wstrb[63]
    DIRECTION OUTPUT ;
    USE SIGNAL ;
    PORT
      LAYER M4 ;
        RECT 531.150 79.769 531.250 79.793 ;
    END
  END k_wstrb[63]
  PIN k_wstrb[62]
    DIRECTION OUTPUT ;
    USE SIGNAL ;
    PORT
      LAYER M4 ;
        RECT 531.150 79.865 531.250 79.889 ;
    END
  END k_wstrb[62]
  PIN k_wstrb[61]
    DIRECTION OUTPUT ;
    USE SIGNAL ;
    PORT
      LAYER M4 ;
        RECT 531.150 79.961 531.250 79.985 ;
    END
  END k_wstrb[61]
  PIN k_wstrb[60]
    DIRECTION OUTPUT ;
    USE SIGNAL ;
    PORT
      LAYER M4 ;
        RECT 531.150 80.057 531.250 80.081 ;
    END
  END k_wstrb[60]
  PIN k_wstrb[59]
    DIRECTION OUTPUT ;
    USE SIGNAL ;
    PORT
      LAYER M4 ;
        RECT 531.150 80.153 531.250 80.177 ;
    END
  END k_wstrb[59]
  PIN k_wstrb[58]
    DIRECTION OUTPUT ;
    USE SIGNAL ;
    PORT
      LAYER M4 ;
        RECT 531.150 80.249 531.250 80.273 ;
    END
  END k_wstrb[58]
  PIN k_wstrb[57]
    DIRECTION OUTPUT ;
    USE SIGNAL ;
    PORT
      LAYER M4 ;
        RECT 531.150 80.345 531.250 80.369 ;
    END
  END k_wstrb[57]
  PIN k_wstrb[56]
    DIRECTION OUTPUT ;
    USE SIGNAL ;
    PORT
      LAYER M4 ;
        RECT 531.150 80.441 531.250 80.465 ;
    END
  END k_wstrb[56]
  PIN k_wstrb[55]
    DIRECTION OUTPUT ;
    USE SIGNAL ;
    PORT
      LAYER M4 ;
        RECT 531.150 80.537 531.250 80.561 ;
    END
  END k_wstrb[55]
  PIN k_wstrb[54]
    DIRECTION OUTPUT ;
    USE SIGNAL ;
    PORT
      LAYER M4 ;
        RECT 531.150 80.633 531.250 80.657 ;
    END
  END k_wstrb[54]
  PIN k_wstrb[53]
    DIRECTION OUTPUT ;
    USE SIGNAL ;
    PORT
      LAYER M4 ;
        RECT 531.150 80.729 531.250 80.753 ;
    END
  END k_wstrb[53]
  PIN k_wstrb[52]
    DIRECTION OUTPUT ;
    USE SIGNAL ;
    PORT
      LAYER M4 ;
        RECT 531.150 80.825 531.250 80.849 ;
    END
  END k_wstrb[52]
  PIN k_wstrb[51]
    DIRECTION OUTPUT ;
    USE SIGNAL ;
    PORT
      LAYER M4 ;
        RECT 531.150 80.921 531.250 80.945 ;
    END
  END k_wstrb[51]
  PIN k_wstrb[50]
    DIRECTION OUTPUT ;
    USE SIGNAL ;
    PORT
      LAYER M4 ;
        RECT 531.150 81.017 531.250 81.041 ;
    END
  END k_wstrb[50]
  PIN k_wstrb[49]
    DIRECTION OUTPUT ;
    USE SIGNAL ;
    PORT
      LAYER M4 ;
        RECT 531.150 81.113 531.250 81.137 ;
    END
  END k_wstrb[49]
  PIN k_wstrb[48]
    DIRECTION OUTPUT ;
    USE SIGNAL ;
    PORT
      LAYER M4 ;
        RECT 531.150 81.209 531.250 81.233 ;
    END
  END k_wstrb[48]
  PIN k_wstrb[47]
    DIRECTION OUTPUT ;
    USE SIGNAL ;
    PORT
      LAYER M4 ;
        RECT 531.150 81.305 531.250 81.329 ;
    END
  END k_wstrb[47]
  PIN k_wstrb[46]
    DIRECTION OUTPUT ;
    USE SIGNAL ;
    PORT
      LAYER M4 ;
        RECT 531.150 81.401 531.250 81.425 ;
    END
  END k_wstrb[46]
  PIN k_wstrb[45]
    DIRECTION OUTPUT ;
    USE SIGNAL ;
    PORT
      LAYER M4 ;
        RECT 531.150 81.497 531.250 81.521 ;
    END
  END k_wstrb[45]
  PIN k_wstrb[44]
    DIRECTION OUTPUT ;
    USE SIGNAL ;
    PORT
      LAYER M4 ;
        RECT 531.150 81.593 531.250 81.617 ;
    END
  END k_wstrb[44]
  PIN k_wstrb[43]
    DIRECTION OUTPUT ;
    USE SIGNAL ;
    PORT
      LAYER M4 ;
        RECT 531.150 81.689 531.250 81.713 ;
    END
  END k_wstrb[43]
  PIN k_wstrb[42]
    DIRECTION OUTPUT ;
    USE SIGNAL ;
    PORT
      LAYER M4 ;
        RECT 531.150 81.785 531.250 81.809 ;
    END
  END k_wstrb[42]
  PIN k_wstrb[41]
    DIRECTION OUTPUT ;
    USE SIGNAL ;
    PORT
      LAYER M4 ;
        RECT 531.150 81.881 531.250 81.905 ;
    END
  END k_wstrb[41]
  PIN k_wstrb[40]
    DIRECTION OUTPUT ;
    USE SIGNAL ;
    PORT
      LAYER M4 ;
        RECT 531.150 81.977 531.250 82.001 ;
    END
  END k_wstrb[40]
  PIN k_wstrb[39]
    DIRECTION OUTPUT ;
    USE SIGNAL ;
    PORT
      LAYER M4 ;
        RECT 531.150 82.073 531.250 82.097 ;
    END
  END k_wstrb[39]
  PIN k_wstrb[38]
    DIRECTION OUTPUT ;
    USE SIGNAL ;
    PORT
      LAYER M4 ;
        RECT 531.150 82.169 531.250 82.193 ;
    END
  END k_wstrb[38]
  PIN k_wstrb[37]
    DIRECTION OUTPUT ;
    USE SIGNAL ;
    PORT
      LAYER M4 ;
        RECT 531.150 82.265 531.250 82.289 ;
    END
  END k_wstrb[37]
  PIN k_wstrb[36]
    DIRECTION OUTPUT ;
    USE SIGNAL ;
    PORT
      LAYER M4 ;
        RECT 531.150 82.361 531.250 82.385 ;
    END
  END k_wstrb[36]
  PIN k_wstrb[35]
    DIRECTION OUTPUT ;
    USE SIGNAL ;
    PORT
      LAYER M4 ;
        RECT 531.150 82.457 531.250 82.481 ;
    END
  END k_wstrb[35]
  PIN k_wstrb[34]
    DIRECTION OUTPUT ;
    USE SIGNAL ;
    PORT
      LAYER M4 ;
        RECT 531.150 82.553 531.250 82.577 ;
    END
  END k_wstrb[34]
  PIN k_wstrb[33]
    DIRECTION OUTPUT ;
    USE SIGNAL ;
    PORT
      LAYER M4 ;
        RECT 531.150 82.649 531.250 82.673 ;
    END
  END k_wstrb[33]
  PIN k_wstrb[32]
    DIRECTION OUTPUT ;
    USE SIGNAL ;
    PORT
      LAYER M4 ;
        RECT 531.150 82.745 531.250 82.769 ;
    END
  END k_wstrb[32]
  PIN k_wstrb[31]
    DIRECTION OUTPUT ;
    USE SIGNAL ;
    PORT
      LAYER M4 ;
        RECT 531.150 82.841 531.250 82.865 ;
    END
  END k_wstrb[31]
  PIN k_wstrb[30]
    DIRECTION OUTPUT ;
    USE SIGNAL ;
    PORT
      LAYER M4 ;
        RECT 531.150 82.937 531.250 82.961 ;
    END
  END k_wstrb[30]
  PIN k_wstrb[29]
    DIRECTION OUTPUT ;
    USE SIGNAL ;
    PORT
      LAYER M4 ;
        RECT 531.150 83.033 531.250 83.057 ;
    END
  END k_wstrb[29]
  PIN k_wstrb[28]
    DIRECTION OUTPUT ;
    USE SIGNAL ;
    PORT
      LAYER M4 ;
        RECT 531.150 83.129 531.250 83.153 ;
    END
  END k_wstrb[28]
  PIN k_wstrb[27]
    DIRECTION OUTPUT ;
    USE SIGNAL ;
    PORT
      LAYER M4 ;
        RECT 531.150 83.225 531.250 83.249 ;
    END
  END k_wstrb[27]
  PIN k_wstrb[26]
    DIRECTION OUTPUT ;
    USE SIGNAL ;
    PORT
      LAYER M4 ;
        RECT 531.150 83.321 531.250 83.345 ;
    END
  END k_wstrb[26]
  PIN k_wstrb[25]
    DIRECTION OUTPUT ;
    USE SIGNAL ;
    PORT
      LAYER M4 ;
        RECT 531.150 83.417 531.250 83.441 ;
    END
  END k_wstrb[25]
  PIN k_wstrb[24]
    DIRECTION OUTPUT ;
    USE SIGNAL ;
    PORT
      LAYER M4 ;
        RECT 531.150 83.513 531.250 83.537 ;
    END
  END k_wstrb[24]
  PIN k_wstrb[23]
    DIRECTION OUTPUT ;
    USE SIGNAL ;
    PORT
      LAYER M4 ;
        RECT 531.150 83.609 531.250 83.633 ;
    END
  END k_wstrb[23]
  PIN k_wstrb[22]
    DIRECTION OUTPUT ;
    USE SIGNAL ;
    PORT
      LAYER M4 ;
        RECT 531.150 83.705 531.250 83.729 ;
    END
  END k_wstrb[22]
  PIN k_wstrb[21]
    DIRECTION OUTPUT ;
    USE SIGNAL ;
    PORT
      LAYER M4 ;
        RECT 531.150 83.801 531.250 83.825 ;
    END
  END k_wstrb[21]
  PIN k_wstrb[20]
    DIRECTION OUTPUT ;
    USE SIGNAL ;
    PORT
      LAYER M4 ;
        RECT 531.150 83.897 531.250 83.921 ;
    END
  END k_wstrb[20]
  PIN k_wstrb[19]
    DIRECTION OUTPUT ;
    USE SIGNAL ;
    PORT
      LAYER M4 ;
        RECT 531.150 83.993 531.250 84.017 ;
    END
  END k_wstrb[19]
  PIN k_wstrb[18]
    DIRECTION OUTPUT ;
    USE SIGNAL ;
    PORT
      LAYER M4 ;
        RECT 531.150 84.089 531.250 84.113 ;
    END
  END k_wstrb[18]
  PIN k_wstrb[17]
    DIRECTION OUTPUT ;
    USE SIGNAL ;
    PORT
      LAYER M4 ;
        RECT 531.150 84.185 531.250 84.209 ;
    END
  END k_wstrb[17]
  PIN k_wstrb[16]
    DIRECTION OUTPUT ;
    USE SIGNAL ;
    PORT
      LAYER M4 ;
        RECT 531.150 84.281 531.250 84.305 ;
    END
  END k_wstrb[16]
  PIN k_wstrb[15]
    DIRECTION OUTPUT ;
    USE SIGNAL ;
    PORT
      LAYER M4 ;
        RECT 531.150 84.377 531.250 84.401 ;
    END
  END k_wstrb[15]
  PIN k_wstrb[14]
    DIRECTION OUTPUT ;
    USE SIGNAL ;
    PORT
      LAYER M4 ;
        RECT 531.150 84.473 531.250 84.497 ;
    END
  END k_wstrb[14]
  PIN k_wstrb[13]
    DIRECTION OUTPUT ;
    USE SIGNAL ;
    PORT
      LAYER M4 ;
        RECT 531.150 84.569 531.250 84.593 ;
    END
  END k_wstrb[13]
  PIN k_wstrb[12]
    DIRECTION OUTPUT ;
    USE SIGNAL ;
    PORT
      LAYER M4 ;
        RECT 531.150 84.665 531.250 84.689 ;
    END
  END k_wstrb[12]
  PIN k_wstrb[11]
    DIRECTION OUTPUT ;
    USE SIGNAL ;
    PORT
      LAYER M4 ;
        RECT 531.150 84.761 531.250 84.785 ;
    END
  END k_wstrb[11]
  PIN k_wstrb[10]
    DIRECTION OUTPUT ;
    USE SIGNAL ;
    PORT
      LAYER M4 ;
        RECT 531.150 84.857 531.250 84.881 ;
    END
  END k_wstrb[10]
  PIN k_wstrb[9]
    DIRECTION OUTPUT ;
    USE SIGNAL ;
    PORT
      LAYER M4 ;
        RECT 531.150 84.953 531.250 84.977 ;
    END
  END k_wstrb[9]
  PIN k_wstrb[8]
    DIRECTION OUTPUT ;
    USE SIGNAL ;
    PORT
      LAYER M4 ;
        RECT 531.150 85.049 531.250 85.073 ;
    END
  END k_wstrb[8]
  PIN k_wstrb[7]
    DIRECTION OUTPUT ;
    USE SIGNAL ;
    PORT
      LAYER M4 ;
        RECT 531.150 85.145 531.250 85.169 ;
    END
  END k_wstrb[7]
  PIN k_wstrb[6]
    DIRECTION OUTPUT ;
    USE SIGNAL ;
    PORT
      LAYER M4 ;
        RECT 531.150 85.241 531.250 85.265 ;
    END
  END k_wstrb[6]
  PIN k_wstrb[5]
    DIRECTION OUTPUT ;
    USE SIGNAL ;
    PORT
      LAYER M4 ;
        RECT 531.150 85.337 531.250 85.361 ;
    END
  END k_wstrb[5]
  PIN k_wstrb[4]
    DIRECTION OUTPUT ;
    USE SIGNAL ;
    PORT
      LAYER M4 ;
        RECT 531.150 85.433 531.250 85.457 ;
    END
  END k_wstrb[4]
  PIN k_wstrb[3]
    DIRECTION OUTPUT ;
    USE SIGNAL ;
    PORT
      LAYER M4 ;
        RECT 531.150 85.529 531.250 85.553 ;
    END
  END k_wstrb[3]
  PIN k_wstrb[2]
    DIRECTION OUTPUT ;
    USE SIGNAL ;
    PORT
      LAYER M4 ;
        RECT 531.150 85.625 531.250 85.649 ;
    END
  END k_wstrb[2]
  PIN k_wstrb[1]
    DIRECTION OUTPUT ;
    USE SIGNAL ;
    PORT
      LAYER M4 ;
        RECT 531.150 85.721 531.250 85.745 ;
    END
  END k_wstrb[1]
  PIN k_wstrb[0]
    DIRECTION OUTPUT ;
    USE SIGNAL ;
    PORT
      LAYER M4 ;
        RECT 531.150 85.817 531.250 85.841 ;
    END
  END k_wstrb[0]
  PIN k_wr_done[1]
    DIRECTION INPUT ;
    USE SIGNAL ;
    PORT
      LAYER M4 ;
        RECT 531.150 82.745 531.250 82.769 ;
    END
  END k_wr_done[1]
  PIN k_wr_done[0]
    DIRECTION INPUT ;
    USE SIGNAL ;
    PORT
      LAYER M4 ;
        RECT 531.150 82.841 531.250 82.865 ;
    END
  END k_wr_done[0]
  PIN kr_v[1]
    DIRECTION INPUT ;
    USE SIGNAL ;
    PORT
      LAYER M4 ;
        RECT 531.150 82.745 531.250 82.769 ;
    END
  END kr_v[1]
  PIN kr_v[0]
    DIRECTION INPUT ;
    USE SIGNAL ;
    PORT
      LAYER M4 ;
        RECT 531.150 82.841 531.250 82.865 ;
    END
  END kr_v[0]
  PIN kr_rdy[1]
    DIRECTION OUTPUT ;
    USE SIGNAL ;
    PORT
      LAYER M4 ;
        RECT 531.150 82.745 531.250 82.769 ;
    END
  END kr_rdy[1]
  PIN kr_rdy[0]
    DIRECTION OUTPUT ;
    USE SIGNAL ;
    PORT
      LAYER M4 ;
        RECT 531.150 82.841 531.250 82.865 ;
    END
  END kr_rdy[0]
  PIN kr_tag[33]
    DIRECTION INPUT ;
    USE SIGNAL ;
    PORT
      LAYER M4 ;
        RECT 531.150 81.209 531.250 81.233 ;
    END
  END kr_tag[33]
  PIN kr_tag[32]
    DIRECTION INPUT ;
    USE SIGNAL ;
    PORT
      LAYER M4 ;
        RECT 531.150 81.305 531.250 81.329 ;
    END
  END kr_tag[32]
  PIN kr_tag[31]
    DIRECTION INPUT ;
    USE SIGNAL ;
    PORT
      LAYER M4 ;
        RECT 531.150 81.401 531.250 81.425 ;
    END
  END kr_tag[31]
  PIN kr_tag[30]
    DIRECTION INPUT ;
    USE SIGNAL ;
    PORT
      LAYER M4 ;
        RECT 531.150 81.497 531.250 81.521 ;
    END
  END kr_tag[30]
  PIN kr_tag[29]
    DIRECTION INPUT ;
    USE SIGNAL ;
    PORT
      LAYER M4 ;
        RECT 531.150 81.593 531.250 81.617 ;
    END
  END kr_tag[29]
  PIN kr_tag[28]
    DIRECTION INPUT ;
    USE SIGNAL ;
    PORT
      LAYER M4 ;
        RECT 531.150 81.689 531.250 81.713 ;
    END
  END kr_tag[28]
  PIN kr_tag[27]
    DIRECTION INPUT ;
    USE SIGNAL ;
    PORT
      LAYER M4 ;
        RECT 531.150 81.785 531.250 81.809 ;
    END
  END kr_tag[27]
  PIN kr_tag[26]
    DIRECTION INPUT ;
    USE SIGNAL ;
    PORT
      LAYER M4 ;
        RECT 531.150 81.881 531.250 81.905 ;
    END
  END kr_tag[26]
  PIN kr_tag[25]
    DIRECTION INPUT ;
    USE SIGNAL ;
    PORT
      LAYER M4 ;
        RECT 531.150 81.977 531.250 82.001 ;
    END
  END kr_tag[25]
  PIN kr_tag[24]
    DIRECTION INPUT ;
    USE SIGNAL ;
    PORT
      LAYER M4 ;
        RECT 531.150 82.073 531.250 82.097 ;
    END
  END kr_tag[24]
  PIN kr_tag[23]
    DIRECTION INPUT ;
    USE SIGNAL ;
    PORT
      LAYER M4 ;
        RECT 531.150 82.169 531.250 82.193 ;
    END
  END kr_tag[23]
  PIN kr_tag[22]
    DIRECTION INPUT ;
    USE SIGNAL ;
    PORT
      LAYER M4 ;
        RECT 531.150 82.265 531.250 82.289 ;
    END
  END kr_tag[22]
  PIN kr_tag[21]
    DIRECTION INPUT ;
    USE SIGNAL ;
    PORT
      LAYER M4 ;
        RECT 531.150 82.361 531.250 82.385 ;
    END
  END kr_tag[21]
  PIN kr_tag[20]
    DIRECTION INPUT ;
    USE SIGNAL ;
    PORT
      LAYER M4 ;
        RECT 531.150 82.457 531.250 82.481 ;
    END
  END kr_tag[20]
  PIN kr_tag[19]
    DIRECTION INPUT ;
    USE SIGNAL ;
    PORT
      LAYER M4 ;
        RECT 531.150 82.553 531.250 82.577 ;
    END
  END kr_tag[19]
  PIN kr_tag[18]
    DIRECTION INPUT ;
    USE SIGNAL ;
    PORT
      LAYER M4 ;
        RECT 531.150 82.649 531.250 82.673 ;
    END
  END kr_tag[18]
  PIN kr_tag[17]
    DIRECTION INPUT ;
    USE SIGNAL ;
    PORT
      LAYER M4 ;
        RECT 531.150 82.745 531.250 82.769 ;
    END
  END kr_tag[17]
  PIN kr_tag[16]
    DIRECTION INPUT ;
    USE SIGNAL ;
    PORT
      LAYER M4 ;
        RECT 531.150 82.841 531.250 82.865 ;
    END
  END kr_tag[16]
  PIN kr_tag[15]
    DIRECTION INPUT ;
    USE SIGNAL ;
    PORT
      LAYER M4 ;
        RECT 531.150 82.937 531.250 82.961 ;
    END
  END kr_tag[15]
  PIN kr_tag[14]
    DIRECTION INPUT ;
    USE SIGNAL ;
    PORT
      LAYER M4 ;
        RECT 531.150 83.033 531.250 83.057 ;
    END
  END kr_tag[14]
  PIN kr_tag[13]
    DIRECTION INPUT ;
    USE SIGNAL ;
    PORT
      LAYER M4 ;
        RECT 531.150 83.129 531.250 83.153 ;
    END
  END kr_tag[13]
  PIN kr_tag[12]
    DIRECTION INPUT ;
    USE SIGNAL ;
    PORT
      LAYER M4 ;
        RECT 531.150 83.225 531.250 83.249 ;
    END
  END kr_tag[12]
  PIN kr_tag[11]
    DIRECTION INPUT ;
    USE SIGNAL ;
    PORT
      LAYER M4 ;
        RECT 531.150 83.321 531.250 83.345 ;
    END
  END kr_tag[11]
  PIN kr_tag[10]
    DIRECTION INPUT ;
    USE SIGNAL ;
    PORT
      LAYER M4 ;
        RECT 531.150 83.417 531.250 83.441 ;
    END
  END kr_tag[10]
  PIN kr_tag[9]
    DIRECTION INPUT ;
    USE SIGNAL ;
    PORT
      LAYER M4 ;
        RECT 531.150 83.513 531.250 83.537 ;
    END
  END kr_tag[9]
  PIN kr_tag[8]
    DIRECTION INPUT ;
    USE SIGNAL ;
    PORT
      LAYER M4 ;
        RECT 531.150 83.609 531.250 83.633 ;
    END
  END kr_tag[8]
  PIN kr_tag[7]
    DIRECTION INPUT ;
    USE SIGNAL ;
    PORT
      LAYER M4 ;
        RECT 531.150 83.705 531.250 83.729 ;
    END
  END kr_tag[7]
  PIN kr_tag[6]
    DIRECTION INPUT ;
    USE SIGNAL ;
    PORT
      LAYER M4 ;
        RECT 531.150 83.801 531.250 83.825 ;
    END
  END kr_tag[6]
  PIN kr_tag[5]
    DIRECTION INPUT ;
    USE SIGNAL ;
    PORT
      LAYER M4 ;
        RECT 531.150 83.897 531.250 83.921 ;
    END
  END kr_tag[5]
  PIN kr_tag[4]
    DIRECTION INPUT ;
    USE SIGNAL ;
    PORT
      LAYER M4 ;
        RECT 531.150 83.993 531.250 84.017 ;
    END
  END kr_tag[4]
  PIN kr_tag[3]
    DIRECTION INPUT ;
    USE SIGNAL ;
    PORT
      LAYER M4 ;
        RECT 531.150 84.089 531.250 84.113 ;
    END
  END kr_tag[3]
  PIN kr_tag[2]
    DIRECTION INPUT ;
    USE SIGNAL ;
    PORT
      LAYER M4 ;
        RECT 531.150 84.185 531.250 84.209 ;
    END
  END kr_tag[2]
  PIN kr_tag[1]
    DIRECTION INPUT ;
    USE SIGNAL ;
    PORT
      LAYER M4 ;
        RECT 531.150 84.281 531.250 84.305 ;
    END
  END kr_tag[1]
  PIN kr_tag[0]
    DIRECTION INPUT ;
    USE SIGNAL ;
    PORT
      LAYER M4 ;
        RECT 531.150 84.377 531.250 84.401 ;
    END
  END kr_tag[0]
  PIN kr_beat[7]
    DIRECTION INPUT ;
    USE SIGNAL ;
    PORT
      LAYER M4 ;
        RECT 531.150 82.457 531.250 82.481 ;
    END
  END kr_beat[7]
  PIN kr_beat[6]
    DIRECTION INPUT ;
    USE SIGNAL ;
    PORT
      LAYER M4 ;
        RECT 531.150 82.553 531.250 82.577 ;
    END
  END kr_beat[6]
  PIN kr_beat[5]
    DIRECTION INPUT ;
    USE SIGNAL ;
    PORT
      LAYER M4 ;
        RECT 531.150 82.649 531.250 82.673 ;
    END
  END kr_beat[5]
  PIN kr_beat[4]
    DIRECTION INPUT ;
    USE SIGNAL ;
    PORT
      LAYER M4 ;
        RECT 531.150 82.745 531.250 82.769 ;
    END
  END kr_beat[4]
  PIN kr_beat[3]
    DIRECTION INPUT ;
    USE SIGNAL ;
    PORT
      LAYER M4 ;
        RECT 531.150 82.841 531.250 82.865 ;
    END
  END kr_beat[3]
  PIN kr_beat[2]
    DIRECTION INPUT ;
    USE SIGNAL ;
    PORT
      LAYER M4 ;
        RECT 531.150 82.937 531.250 82.961 ;
    END
  END kr_beat[2]
  PIN kr_beat[1]
    DIRECTION INPUT ;
    USE SIGNAL ;
    PORT
      LAYER M4 ;
        RECT 531.150 83.033 531.250 83.057 ;
    END
  END kr_beat[1]
  PIN kr_beat[0]
    DIRECTION INPUT ;
    USE SIGNAL ;
    PORT
      LAYER M4 ;
        RECT 531.150 83.129 531.250 83.153 ;
    END
  END kr_beat[0]
  PIN kr_data[511]
    DIRECTION INPUT ;
    USE SIGNAL ;
    PORT
      LAYER M4 ;
        RECT 531.150 58.265 531.250 58.289 ;
    END
  END kr_data[511]
  PIN kr_data[510]
    DIRECTION INPUT ;
    USE SIGNAL ;
    PORT
      LAYER M4 ;
        RECT 531.150 58.361 531.250 58.385 ;
    END
  END kr_data[510]
  PIN kr_data[509]
    DIRECTION INPUT ;
    USE SIGNAL ;
    PORT
      LAYER M4 ;
        RECT 531.150 58.457 531.250 58.481 ;
    END
  END kr_data[509]
  PIN kr_data[508]
    DIRECTION INPUT ;
    USE SIGNAL ;
    PORT
      LAYER M4 ;
        RECT 531.150 58.553 531.250 58.577 ;
    END
  END kr_data[508]
  PIN kr_data[507]
    DIRECTION INPUT ;
    USE SIGNAL ;
    PORT
      LAYER M4 ;
        RECT 531.150 58.649 531.250 58.673 ;
    END
  END kr_data[507]
  PIN kr_data[506]
    DIRECTION INPUT ;
    USE SIGNAL ;
    PORT
      LAYER M4 ;
        RECT 531.150 58.745 531.250 58.769 ;
    END
  END kr_data[506]
  PIN kr_data[505]
    DIRECTION INPUT ;
    USE SIGNAL ;
    PORT
      LAYER M4 ;
        RECT 531.150 58.841 531.250 58.865 ;
    END
  END kr_data[505]
  PIN kr_data[504]
    DIRECTION INPUT ;
    USE SIGNAL ;
    PORT
      LAYER M4 ;
        RECT 531.150 58.937 531.250 58.961 ;
    END
  END kr_data[504]
  PIN kr_data[503]
    DIRECTION INPUT ;
    USE SIGNAL ;
    PORT
      LAYER M4 ;
        RECT 531.150 59.033 531.250 59.057 ;
    END
  END kr_data[503]
  PIN kr_data[502]
    DIRECTION INPUT ;
    USE SIGNAL ;
    PORT
      LAYER M4 ;
        RECT 531.150 59.129 531.250 59.153 ;
    END
  END kr_data[502]
  PIN kr_data[501]
    DIRECTION INPUT ;
    USE SIGNAL ;
    PORT
      LAYER M4 ;
        RECT 531.150 59.225 531.250 59.249 ;
    END
  END kr_data[501]
  PIN kr_data[500]
    DIRECTION INPUT ;
    USE SIGNAL ;
    PORT
      LAYER M4 ;
        RECT 531.150 59.321 531.250 59.345 ;
    END
  END kr_data[500]
  PIN kr_data[499]
    DIRECTION INPUT ;
    USE SIGNAL ;
    PORT
      LAYER M4 ;
        RECT 531.150 59.417 531.250 59.441 ;
    END
  END kr_data[499]
  PIN kr_data[498]
    DIRECTION INPUT ;
    USE SIGNAL ;
    PORT
      LAYER M4 ;
        RECT 531.150 59.513 531.250 59.537 ;
    END
  END kr_data[498]
  PIN kr_data[497]
    DIRECTION INPUT ;
    USE SIGNAL ;
    PORT
      LAYER M4 ;
        RECT 531.150 59.609 531.250 59.633 ;
    END
  END kr_data[497]
  PIN kr_data[496]
    DIRECTION INPUT ;
    USE SIGNAL ;
    PORT
      LAYER M4 ;
        RECT 531.150 59.705 531.250 59.729 ;
    END
  END kr_data[496]
  PIN kr_data[495]
    DIRECTION INPUT ;
    USE SIGNAL ;
    PORT
      LAYER M4 ;
        RECT 531.150 59.801 531.250 59.825 ;
    END
  END kr_data[495]
  PIN kr_data[494]
    DIRECTION INPUT ;
    USE SIGNAL ;
    PORT
      LAYER M4 ;
        RECT 531.150 59.897 531.250 59.921 ;
    END
  END kr_data[494]
  PIN kr_data[493]
    DIRECTION INPUT ;
    USE SIGNAL ;
    PORT
      LAYER M4 ;
        RECT 531.150 59.993 531.250 60.017 ;
    END
  END kr_data[493]
  PIN kr_data[492]
    DIRECTION INPUT ;
    USE SIGNAL ;
    PORT
      LAYER M4 ;
        RECT 531.150 60.089 531.250 60.113 ;
    END
  END kr_data[492]
  PIN kr_data[491]
    DIRECTION INPUT ;
    USE SIGNAL ;
    PORT
      LAYER M4 ;
        RECT 531.150 60.185 531.250 60.209 ;
    END
  END kr_data[491]
  PIN kr_data[490]
    DIRECTION INPUT ;
    USE SIGNAL ;
    PORT
      LAYER M4 ;
        RECT 531.150 60.281 531.250 60.305 ;
    END
  END kr_data[490]
  PIN kr_data[489]
    DIRECTION INPUT ;
    USE SIGNAL ;
    PORT
      LAYER M4 ;
        RECT 531.150 60.377 531.250 60.401 ;
    END
  END kr_data[489]
  PIN kr_data[488]
    DIRECTION INPUT ;
    USE SIGNAL ;
    PORT
      LAYER M4 ;
        RECT 531.150 60.473 531.250 60.497 ;
    END
  END kr_data[488]
  PIN kr_data[487]
    DIRECTION INPUT ;
    USE SIGNAL ;
    PORT
      LAYER M4 ;
        RECT 531.150 60.569 531.250 60.593 ;
    END
  END kr_data[487]
  PIN kr_data[486]
    DIRECTION INPUT ;
    USE SIGNAL ;
    PORT
      LAYER M4 ;
        RECT 531.150 60.665 531.250 60.689 ;
    END
  END kr_data[486]
  PIN kr_data[485]
    DIRECTION INPUT ;
    USE SIGNAL ;
    PORT
      LAYER M4 ;
        RECT 531.150 60.761 531.250 60.785 ;
    END
  END kr_data[485]
  PIN kr_data[484]
    DIRECTION INPUT ;
    USE SIGNAL ;
    PORT
      LAYER M4 ;
        RECT 531.150 60.857 531.250 60.881 ;
    END
  END kr_data[484]
  PIN kr_data[483]
    DIRECTION INPUT ;
    USE SIGNAL ;
    PORT
      LAYER M4 ;
        RECT 531.150 60.953 531.250 60.977 ;
    END
  END kr_data[483]
  PIN kr_data[482]
    DIRECTION INPUT ;
    USE SIGNAL ;
    PORT
      LAYER M4 ;
        RECT 531.150 61.049 531.250 61.073 ;
    END
  END kr_data[482]
  PIN kr_data[481]
    DIRECTION INPUT ;
    USE SIGNAL ;
    PORT
      LAYER M4 ;
        RECT 531.150 61.145 531.250 61.169 ;
    END
  END kr_data[481]
  PIN kr_data[480]
    DIRECTION INPUT ;
    USE SIGNAL ;
    PORT
      LAYER M4 ;
        RECT 531.150 61.241 531.250 61.265 ;
    END
  END kr_data[480]
  PIN kr_data[479]
    DIRECTION INPUT ;
    USE SIGNAL ;
    PORT
      LAYER M4 ;
        RECT 531.150 61.337 531.250 61.361 ;
    END
  END kr_data[479]
  PIN kr_data[478]
    DIRECTION INPUT ;
    USE SIGNAL ;
    PORT
      LAYER M4 ;
        RECT 531.150 61.433 531.250 61.457 ;
    END
  END kr_data[478]
  PIN kr_data[477]
    DIRECTION INPUT ;
    USE SIGNAL ;
    PORT
      LAYER M4 ;
        RECT 531.150 61.529 531.250 61.553 ;
    END
  END kr_data[477]
  PIN kr_data[476]
    DIRECTION INPUT ;
    USE SIGNAL ;
    PORT
      LAYER M4 ;
        RECT 531.150 61.625 531.250 61.649 ;
    END
  END kr_data[476]
  PIN kr_data[475]
    DIRECTION INPUT ;
    USE SIGNAL ;
    PORT
      LAYER M4 ;
        RECT 531.150 61.721 531.250 61.745 ;
    END
  END kr_data[475]
  PIN kr_data[474]
    DIRECTION INPUT ;
    USE SIGNAL ;
    PORT
      LAYER M4 ;
        RECT 531.150 61.817 531.250 61.841 ;
    END
  END kr_data[474]
  PIN kr_data[473]
    DIRECTION INPUT ;
    USE SIGNAL ;
    PORT
      LAYER M4 ;
        RECT 531.150 61.913 531.250 61.937 ;
    END
  END kr_data[473]
  PIN kr_data[472]
    DIRECTION INPUT ;
    USE SIGNAL ;
    PORT
      LAYER M4 ;
        RECT 531.150 62.009 531.250 62.033 ;
    END
  END kr_data[472]
  PIN kr_data[471]
    DIRECTION INPUT ;
    USE SIGNAL ;
    PORT
      LAYER M4 ;
        RECT 531.150 62.105 531.250 62.129 ;
    END
  END kr_data[471]
  PIN kr_data[470]
    DIRECTION INPUT ;
    USE SIGNAL ;
    PORT
      LAYER M4 ;
        RECT 531.150 62.201 531.250 62.225 ;
    END
  END kr_data[470]
  PIN kr_data[469]
    DIRECTION INPUT ;
    USE SIGNAL ;
    PORT
      LAYER M4 ;
        RECT 531.150 62.297 531.250 62.321 ;
    END
  END kr_data[469]
  PIN kr_data[468]
    DIRECTION INPUT ;
    USE SIGNAL ;
    PORT
      LAYER M4 ;
        RECT 531.150 62.393 531.250 62.417 ;
    END
  END kr_data[468]
  PIN kr_data[467]
    DIRECTION INPUT ;
    USE SIGNAL ;
    PORT
      LAYER M4 ;
        RECT 531.150 62.489 531.250 62.513 ;
    END
  END kr_data[467]
  PIN kr_data[466]
    DIRECTION INPUT ;
    USE SIGNAL ;
    PORT
      LAYER M4 ;
        RECT 531.150 62.585 531.250 62.609 ;
    END
  END kr_data[466]
  PIN kr_data[465]
    DIRECTION INPUT ;
    USE SIGNAL ;
    PORT
      LAYER M4 ;
        RECT 531.150 62.681 531.250 62.705 ;
    END
  END kr_data[465]
  PIN kr_data[464]
    DIRECTION INPUT ;
    USE SIGNAL ;
    PORT
      LAYER M4 ;
        RECT 531.150 62.777 531.250 62.801 ;
    END
  END kr_data[464]
  PIN kr_data[463]
    DIRECTION INPUT ;
    USE SIGNAL ;
    PORT
      LAYER M4 ;
        RECT 531.150 62.873 531.250 62.897 ;
    END
  END kr_data[463]
  PIN kr_data[462]
    DIRECTION INPUT ;
    USE SIGNAL ;
    PORT
      LAYER M4 ;
        RECT 531.150 62.969 531.250 62.993 ;
    END
  END kr_data[462]
  PIN kr_data[461]
    DIRECTION INPUT ;
    USE SIGNAL ;
    PORT
      LAYER M4 ;
        RECT 531.150 63.065 531.250 63.089 ;
    END
  END kr_data[461]
  PIN kr_data[460]
    DIRECTION INPUT ;
    USE SIGNAL ;
    PORT
      LAYER M4 ;
        RECT 531.150 63.161 531.250 63.185 ;
    END
  END kr_data[460]
  PIN kr_data[459]
    DIRECTION INPUT ;
    USE SIGNAL ;
    PORT
      LAYER M4 ;
        RECT 531.150 63.257 531.250 63.281 ;
    END
  END kr_data[459]
  PIN kr_data[458]
    DIRECTION INPUT ;
    USE SIGNAL ;
    PORT
      LAYER M4 ;
        RECT 531.150 63.353 531.250 63.377 ;
    END
  END kr_data[458]
  PIN kr_data[457]
    DIRECTION INPUT ;
    USE SIGNAL ;
    PORT
      LAYER M4 ;
        RECT 531.150 63.449 531.250 63.473 ;
    END
  END kr_data[457]
  PIN kr_data[456]
    DIRECTION INPUT ;
    USE SIGNAL ;
    PORT
      LAYER M4 ;
        RECT 531.150 63.545 531.250 63.569 ;
    END
  END kr_data[456]
  PIN kr_data[455]
    DIRECTION INPUT ;
    USE SIGNAL ;
    PORT
      LAYER M4 ;
        RECT 531.150 63.641 531.250 63.665 ;
    END
  END kr_data[455]
  PIN kr_data[454]
    DIRECTION INPUT ;
    USE SIGNAL ;
    PORT
      LAYER M4 ;
        RECT 531.150 63.737 531.250 63.761 ;
    END
  END kr_data[454]
  PIN kr_data[453]
    DIRECTION INPUT ;
    USE SIGNAL ;
    PORT
      LAYER M4 ;
        RECT 531.150 63.833 531.250 63.857 ;
    END
  END kr_data[453]
  PIN kr_data[452]
    DIRECTION INPUT ;
    USE SIGNAL ;
    PORT
      LAYER M4 ;
        RECT 531.150 63.929 531.250 63.953 ;
    END
  END kr_data[452]
  PIN kr_data[451]
    DIRECTION INPUT ;
    USE SIGNAL ;
    PORT
      LAYER M4 ;
        RECT 531.150 64.025 531.250 64.049 ;
    END
  END kr_data[451]
  PIN kr_data[450]
    DIRECTION INPUT ;
    USE SIGNAL ;
    PORT
      LAYER M4 ;
        RECT 531.150 64.121 531.250 64.145 ;
    END
  END kr_data[450]
  PIN kr_data[449]
    DIRECTION INPUT ;
    USE SIGNAL ;
    PORT
      LAYER M4 ;
        RECT 531.150 64.217 531.250 64.241 ;
    END
  END kr_data[449]
  PIN kr_data[448]
    DIRECTION INPUT ;
    USE SIGNAL ;
    PORT
      LAYER M4 ;
        RECT 531.150 64.313 531.250 64.337 ;
    END
  END kr_data[448]
  PIN kr_data[447]
    DIRECTION INPUT ;
    USE SIGNAL ;
    PORT
      LAYER M4 ;
        RECT 531.150 64.409 531.250 64.433 ;
    END
  END kr_data[447]
  PIN kr_data[446]
    DIRECTION INPUT ;
    USE SIGNAL ;
    PORT
      LAYER M4 ;
        RECT 531.150 64.505 531.250 64.529 ;
    END
  END kr_data[446]
  PIN kr_data[445]
    DIRECTION INPUT ;
    USE SIGNAL ;
    PORT
      LAYER M4 ;
        RECT 531.150 64.601 531.250 64.625 ;
    END
  END kr_data[445]
  PIN kr_data[444]
    DIRECTION INPUT ;
    USE SIGNAL ;
    PORT
      LAYER M4 ;
        RECT 531.150 64.697 531.250 64.721 ;
    END
  END kr_data[444]
  PIN kr_data[443]
    DIRECTION INPUT ;
    USE SIGNAL ;
    PORT
      LAYER M4 ;
        RECT 531.150 64.793 531.250 64.817 ;
    END
  END kr_data[443]
  PIN kr_data[442]
    DIRECTION INPUT ;
    USE SIGNAL ;
    PORT
      LAYER M4 ;
        RECT 531.150 64.889 531.250 64.913 ;
    END
  END kr_data[442]
  PIN kr_data[441]
    DIRECTION INPUT ;
    USE SIGNAL ;
    PORT
      LAYER M4 ;
        RECT 531.150 64.985 531.250 65.009 ;
    END
  END kr_data[441]
  PIN kr_data[440]
    DIRECTION INPUT ;
    USE SIGNAL ;
    PORT
      LAYER M4 ;
        RECT 531.150 65.081 531.250 65.105 ;
    END
  END kr_data[440]
  PIN kr_data[439]
    DIRECTION INPUT ;
    USE SIGNAL ;
    PORT
      LAYER M4 ;
        RECT 531.150 65.177 531.250 65.201 ;
    END
  END kr_data[439]
  PIN kr_data[438]
    DIRECTION INPUT ;
    USE SIGNAL ;
    PORT
      LAYER M4 ;
        RECT 531.150 65.273 531.250 65.297 ;
    END
  END kr_data[438]
  PIN kr_data[437]
    DIRECTION INPUT ;
    USE SIGNAL ;
    PORT
      LAYER M4 ;
        RECT 531.150 65.369 531.250 65.393 ;
    END
  END kr_data[437]
  PIN kr_data[436]
    DIRECTION INPUT ;
    USE SIGNAL ;
    PORT
      LAYER M4 ;
        RECT 531.150 65.465 531.250 65.489 ;
    END
  END kr_data[436]
  PIN kr_data[435]
    DIRECTION INPUT ;
    USE SIGNAL ;
    PORT
      LAYER M4 ;
        RECT 531.150 65.561 531.250 65.585 ;
    END
  END kr_data[435]
  PIN kr_data[434]
    DIRECTION INPUT ;
    USE SIGNAL ;
    PORT
      LAYER M4 ;
        RECT 531.150 65.657 531.250 65.681 ;
    END
  END kr_data[434]
  PIN kr_data[433]
    DIRECTION INPUT ;
    USE SIGNAL ;
    PORT
      LAYER M4 ;
        RECT 531.150 65.753 531.250 65.777 ;
    END
  END kr_data[433]
  PIN kr_data[432]
    DIRECTION INPUT ;
    USE SIGNAL ;
    PORT
      LAYER M4 ;
        RECT 531.150 65.849 531.250 65.873 ;
    END
  END kr_data[432]
  PIN kr_data[431]
    DIRECTION INPUT ;
    USE SIGNAL ;
    PORT
      LAYER M4 ;
        RECT 531.150 65.945 531.250 65.969 ;
    END
  END kr_data[431]
  PIN kr_data[430]
    DIRECTION INPUT ;
    USE SIGNAL ;
    PORT
      LAYER M4 ;
        RECT 531.150 66.041 531.250 66.065 ;
    END
  END kr_data[430]
  PIN kr_data[429]
    DIRECTION INPUT ;
    USE SIGNAL ;
    PORT
      LAYER M4 ;
        RECT 531.150 66.137 531.250 66.161 ;
    END
  END kr_data[429]
  PIN kr_data[428]
    DIRECTION INPUT ;
    USE SIGNAL ;
    PORT
      LAYER M4 ;
        RECT 531.150 66.233 531.250 66.257 ;
    END
  END kr_data[428]
  PIN kr_data[427]
    DIRECTION INPUT ;
    USE SIGNAL ;
    PORT
      LAYER M4 ;
        RECT 531.150 66.329 531.250 66.353 ;
    END
  END kr_data[427]
  PIN kr_data[426]
    DIRECTION INPUT ;
    USE SIGNAL ;
    PORT
      LAYER M4 ;
        RECT 531.150 66.425 531.250 66.449 ;
    END
  END kr_data[426]
  PIN kr_data[425]
    DIRECTION INPUT ;
    USE SIGNAL ;
    PORT
      LAYER M4 ;
        RECT 531.150 66.521 531.250 66.545 ;
    END
  END kr_data[425]
  PIN kr_data[424]
    DIRECTION INPUT ;
    USE SIGNAL ;
    PORT
      LAYER M4 ;
        RECT 531.150 66.617 531.250 66.641 ;
    END
  END kr_data[424]
  PIN kr_data[423]
    DIRECTION INPUT ;
    USE SIGNAL ;
    PORT
      LAYER M4 ;
        RECT 531.150 66.713 531.250 66.737 ;
    END
  END kr_data[423]
  PIN kr_data[422]
    DIRECTION INPUT ;
    USE SIGNAL ;
    PORT
      LAYER M4 ;
        RECT 531.150 66.809 531.250 66.833 ;
    END
  END kr_data[422]
  PIN kr_data[421]
    DIRECTION INPUT ;
    USE SIGNAL ;
    PORT
      LAYER M4 ;
        RECT 531.150 66.905 531.250 66.929 ;
    END
  END kr_data[421]
  PIN kr_data[420]
    DIRECTION INPUT ;
    USE SIGNAL ;
    PORT
      LAYER M4 ;
        RECT 531.150 67.001 531.250 67.025 ;
    END
  END kr_data[420]
  PIN kr_data[419]
    DIRECTION INPUT ;
    USE SIGNAL ;
    PORT
      LAYER M4 ;
        RECT 531.150 67.097 531.250 67.121 ;
    END
  END kr_data[419]
  PIN kr_data[418]
    DIRECTION INPUT ;
    USE SIGNAL ;
    PORT
      LAYER M4 ;
        RECT 531.150 67.193 531.250 67.217 ;
    END
  END kr_data[418]
  PIN kr_data[417]
    DIRECTION INPUT ;
    USE SIGNAL ;
    PORT
      LAYER M4 ;
        RECT 531.150 67.289 531.250 67.313 ;
    END
  END kr_data[417]
  PIN kr_data[416]
    DIRECTION INPUT ;
    USE SIGNAL ;
    PORT
      LAYER M4 ;
        RECT 531.150 67.385 531.250 67.409 ;
    END
  END kr_data[416]
  PIN kr_data[415]
    DIRECTION INPUT ;
    USE SIGNAL ;
    PORT
      LAYER M4 ;
        RECT 531.150 67.481 531.250 67.505 ;
    END
  END kr_data[415]
  PIN kr_data[414]
    DIRECTION INPUT ;
    USE SIGNAL ;
    PORT
      LAYER M4 ;
        RECT 531.150 67.577 531.250 67.601 ;
    END
  END kr_data[414]
  PIN kr_data[413]
    DIRECTION INPUT ;
    USE SIGNAL ;
    PORT
      LAYER M4 ;
        RECT 531.150 67.673 531.250 67.697 ;
    END
  END kr_data[413]
  PIN kr_data[412]
    DIRECTION INPUT ;
    USE SIGNAL ;
    PORT
      LAYER M4 ;
        RECT 531.150 67.769 531.250 67.793 ;
    END
  END kr_data[412]
  PIN kr_data[411]
    DIRECTION INPUT ;
    USE SIGNAL ;
    PORT
      LAYER M4 ;
        RECT 531.150 67.865 531.250 67.889 ;
    END
  END kr_data[411]
  PIN kr_data[410]
    DIRECTION INPUT ;
    USE SIGNAL ;
    PORT
      LAYER M4 ;
        RECT 531.150 67.961 531.250 67.985 ;
    END
  END kr_data[410]
  PIN kr_data[409]
    DIRECTION INPUT ;
    USE SIGNAL ;
    PORT
      LAYER M4 ;
        RECT 531.150 68.057 531.250 68.081 ;
    END
  END kr_data[409]
  PIN kr_data[408]
    DIRECTION INPUT ;
    USE SIGNAL ;
    PORT
      LAYER M4 ;
        RECT 531.150 68.153 531.250 68.177 ;
    END
  END kr_data[408]
  PIN kr_data[407]
    DIRECTION INPUT ;
    USE SIGNAL ;
    PORT
      LAYER M4 ;
        RECT 531.150 68.249 531.250 68.273 ;
    END
  END kr_data[407]
  PIN kr_data[406]
    DIRECTION INPUT ;
    USE SIGNAL ;
    PORT
      LAYER M4 ;
        RECT 531.150 68.345 531.250 68.369 ;
    END
  END kr_data[406]
  PIN kr_data[405]
    DIRECTION INPUT ;
    USE SIGNAL ;
    PORT
      LAYER M4 ;
        RECT 531.150 68.441 531.250 68.465 ;
    END
  END kr_data[405]
  PIN kr_data[404]
    DIRECTION INPUT ;
    USE SIGNAL ;
    PORT
      LAYER M4 ;
        RECT 531.150 68.537 531.250 68.561 ;
    END
  END kr_data[404]
  PIN kr_data[403]
    DIRECTION INPUT ;
    USE SIGNAL ;
    PORT
      LAYER M4 ;
        RECT 531.150 68.633 531.250 68.657 ;
    END
  END kr_data[403]
  PIN kr_data[402]
    DIRECTION INPUT ;
    USE SIGNAL ;
    PORT
      LAYER M4 ;
        RECT 531.150 68.729 531.250 68.753 ;
    END
  END kr_data[402]
  PIN kr_data[401]
    DIRECTION INPUT ;
    USE SIGNAL ;
    PORT
      LAYER M4 ;
        RECT 531.150 68.825 531.250 68.849 ;
    END
  END kr_data[401]
  PIN kr_data[400]
    DIRECTION INPUT ;
    USE SIGNAL ;
    PORT
      LAYER M4 ;
        RECT 531.150 68.921 531.250 68.945 ;
    END
  END kr_data[400]
  PIN kr_data[399]
    DIRECTION INPUT ;
    USE SIGNAL ;
    PORT
      LAYER M4 ;
        RECT 531.150 69.017 531.250 69.041 ;
    END
  END kr_data[399]
  PIN kr_data[398]
    DIRECTION INPUT ;
    USE SIGNAL ;
    PORT
      LAYER M4 ;
        RECT 531.150 69.113 531.250 69.137 ;
    END
  END kr_data[398]
  PIN kr_data[397]
    DIRECTION INPUT ;
    USE SIGNAL ;
    PORT
      LAYER M4 ;
        RECT 531.150 69.209 531.250 69.233 ;
    END
  END kr_data[397]
  PIN kr_data[396]
    DIRECTION INPUT ;
    USE SIGNAL ;
    PORT
      LAYER M4 ;
        RECT 531.150 69.305 531.250 69.329 ;
    END
  END kr_data[396]
  PIN kr_data[395]
    DIRECTION INPUT ;
    USE SIGNAL ;
    PORT
      LAYER M4 ;
        RECT 531.150 69.401 531.250 69.425 ;
    END
  END kr_data[395]
  PIN kr_data[394]
    DIRECTION INPUT ;
    USE SIGNAL ;
    PORT
      LAYER M4 ;
        RECT 531.150 69.497 531.250 69.521 ;
    END
  END kr_data[394]
  PIN kr_data[393]
    DIRECTION INPUT ;
    USE SIGNAL ;
    PORT
      LAYER M4 ;
        RECT 531.150 69.593 531.250 69.617 ;
    END
  END kr_data[393]
  PIN kr_data[392]
    DIRECTION INPUT ;
    USE SIGNAL ;
    PORT
      LAYER M4 ;
        RECT 531.150 69.689 531.250 69.713 ;
    END
  END kr_data[392]
  PIN kr_data[391]
    DIRECTION INPUT ;
    USE SIGNAL ;
    PORT
      LAYER M4 ;
        RECT 531.150 69.785 531.250 69.809 ;
    END
  END kr_data[391]
  PIN kr_data[390]
    DIRECTION INPUT ;
    USE SIGNAL ;
    PORT
      LAYER M4 ;
        RECT 531.150 69.881 531.250 69.905 ;
    END
  END kr_data[390]
  PIN kr_data[389]
    DIRECTION INPUT ;
    USE SIGNAL ;
    PORT
      LAYER M4 ;
        RECT 531.150 69.977 531.250 70.001 ;
    END
  END kr_data[389]
  PIN kr_data[388]
    DIRECTION INPUT ;
    USE SIGNAL ;
    PORT
      LAYER M4 ;
        RECT 531.150 70.073 531.250 70.097 ;
    END
  END kr_data[388]
  PIN kr_data[387]
    DIRECTION INPUT ;
    USE SIGNAL ;
    PORT
      LAYER M4 ;
        RECT 531.150 70.169 531.250 70.193 ;
    END
  END kr_data[387]
  PIN kr_data[386]
    DIRECTION INPUT ;
    USE SIGNAL ;
    PORT
      LAYER M4 ;
        RECT 531.150 70.265 531.250 70.289 ;
    END
  END kr_data[386]
  PIN kr_data[385]
    DIRECTION INPUT ;
    USE SIGNAL ;
    PORT
      LAYER M4 ;
        RECT 531.150 70.361 531.250 70.385 ;
    END
  END kr_data[385]
  PIN kr_data[384]
    DIRECTION INPUT ;
    USE SIGNAL ;
    PORT
      LAYER M4 ;
        RECT 531.150 70.457 531.250 70.481 ;
    END
  END kr_data[384]
  PIN kr_data[383]
    DIRECTION INPUT ;
    USE SIGNAL ;
    PORT
      LAYER M4 ;
        RECT 531.150 70.553 531.250 70.577 ;
    END
  END kr_data[383]
  PIN kr_data[382]
    DIRECTION INPUT ;
    USE SIGNAL ;
    PORT
      LAYER M4 ;
        RECT 531.150 70.649 531.250 70.673 ;
    END
  END kr_data[382]
  PIN kr_data[381]
    DIRECTION INPUT ;
    USE SIGNAL ;
    PORT
      LAYER M4 ;
        RECT 531.150 70.745 531.250 70.769 ;
    END
  END kr_data[381]
  PIN kr_data[380]
    DIRECTION INPUT ;
    USE SIGNAL ;
    PORT
      LAYER M4 ;
        RECT 531.150 70.841 531.250 70.865 ;
    END
  END kr_data[380]
  PIN kr_data[379]
    DIRECTION INPUT ;
    USE SIGNAL ;
    PORT
      LAYER M4 ;
        RECT 531.150 70.937 531.250 70.961 ;
    END
  END kr_data[379]
  PIN kr_data[378]
    DIRECTION INPUT ;
    USE SIGNAL ;
    PORT
      LAYER M4 ;
        RECT 531.150 71.033 531.250 71.057 ;
    END
  END kr_data[378]
  PIN kr_data[377]
    DIRECTION INPUT ;
    USE SIGNAL ;
    PORT
      LAYER M4 ;
        RECT 531.150 71.129 531.250 71.153 ;
    END
  END kr_data[377]
  PIN kr_data[376]
    DIRECTION INPUT ;
    USE SIGNAL ;
    PORT
      LAYER M4 ;
        RECT 531.150 71.225 531.250 71.249 ;
    END
  END kr_data[376]
  PIN kr_data[375]
    DIRECTION INPUT ;
    USE SIGNAL ;
    PORT
      LAYER M4 ;
        RECT 531.150 71.321 531.250 71.345 ;
    END
  END kr_data[375]
  PIN kr_data[374]
    DIRECTION INPUT ;
    USE SIGNAL ;
    PORT
      LAYER M4 ;
        RECT 531.150 71.417 531.250 71.441 ;
    END
  END kr_data[374]
  PIN kr_data[373]
    DIRECTION INPUT ;
    USE SIGNAL ;
    PORT
      LAYER M4 ;
        RECT 531.150 71.513 531.250 71.537 ;
    END
  END kr_data[373]
  PIN kr_data[372]
    DIRECTION INPUT ;
    USE SIGNAL ;
    PORT
      LAYER M4 ;
        RECT 531.150 71.609 531.250 71.633 ;
    END
  END kr_data[372]
  PIN kr_data[371]
    DIRECTION INPUT ;
    USE SIGNAL ;
    PORT
      LAYER M4 ;
        RECT 531.150 71.705 531.250 71.729 ;
    END
  END kr_data[371]
  PIN kr_data[370]
    DIRECTION INPUT ;
    USE SIGNAL ;
    PORT
      LAYER M4 ;
        RECT 531.150 71.801 531.250 71.825 ;
    END
  END kr_data[370]
  PIN kr_data[369]
    DIRECTION INPUT ;
    USE SIGNAL ;
    PORT
      LAYER M4 ;
        RECT 531.150 71.897 531.250 71.921 ;
    END
  END kr_data[369]
  PIN kr_data[368]
    DIRECTION INPUT ;
    USE SIGNAL ;
    PORT
      LAYER M4 ;
        RECT 531.150 71.993 531.250 72.017 ;
    END
  END kr_data[368]
  PIN kr_data[367]
    DIRECTION INPUT ;
    USE SIGNAL ;
    PORT
      LAYER M4 ;
        RECT 531.150 72.089 531.250 72.113 ;
    END
  END kr_data[367]
  PIN kr_data[366]
    DIRECTION INPUT ;
    USE SIGNAL ;
    PORT
      LAYER M4 ;
        RECT 531.150 72.185 531.250 72.209 ;
    END
  END kr_data[366]
  PIN kr_data[365]
    DIRECTION INPUT ;
    USE SIGNAL ;
    PORT
      LAYER M4 ;
        RECT 531.150 72.281 531.250 72.305 ;
    END
  END kr_data[365]
  PIN kr_data[364]
    DIRECTION INPUT ;
    USE SIGNAL ;
    PORT
      LAYER M4 ;
        RECT 531.150 72.377 531.250 72.401 ;
    END
  END kr_data[364]
  PIN kr_data[363]
    DIRECTION INPUT ;
    USE SIGNAL ;
    PORT
      LAYER M4 ;
        RECT 531.150 72.473 531.250 72.497 ;
    END
  END kr_data[363]
  PIN kr_data[362]
    DIRECTION INPUT ;
    USE SIGNAL ;
    PORT
      LAYER M4 ;
        RECT 531.150 72.569 531.250 72.593 ;
    END
  END kr_data[362]
  PIN kr_data[361]
    DIRECTION INPUT ;
    USE SIGNAL ;
    PORT
      LAYER M4 ;
        RECT 531.150 72.665 531.250 72.689 ;
    END
  END kr_data[361]
  PIN kr_data[360]
    DIRECTION INPUT ;
    USE SIGNAL ;
    PORT
      LAYER M4 ;
        RECT 531.150 72.761 531.250 72.785 ;
    END
  END kr_data[360]
  PIN kr_data[359]
    DIRECTION INPUT ;
    USE SIGNAL ;
    PORT
      LAYER M4 ;
        RECT 531.150 72.857 531.250 72.881 ;
    END
  END kr_data[359]
  PIN kr_data[358]
    DIRECTION INPUT ;
    USE SIGNAL ;
    PORT
      LAYER M4 ;
        RECT 531.150 72.953 531.250 72.977 ;
    END
  END kr_data[358]
  PIN kr_data[357]
    DIRECTION INPUT ;
    USE SIGNAL ;
    PORT
      LAYER M4 ;
        RECT 531.150 73.049 531.250 73.073 ;
    END
  END kr_data[357]
  PIN kr_data[356]
    DIRECTION INPUT ;
    USE SIGNAL ;
    PORT
      LAYER M4 ;
        RECT 531.150 73.145 531.250 73.169 ;
    END
  END kr_data[356]
  PIN kr_data[355]
    DIRECTION INPUT ;
    USE SIGNAL ;
    PORT
      LAYER M4 ;
        RECT 531.150 73.241 531.250 73.265 ;
    END
  END kr_data[355]
  PIN kr_data[354]
    DIRECTION INPUT ;
    USE SIGNAL ;
    PORT
      LAYER M4 ;
        RECT 531.150 73.337 531.250 73.361 ;
    END
  END kr_data[354]
  PIN kr_data[353]
    DIRECTION INPUT ;
    USE SIGNAL ;
    PORT
      LAYER M4 ;
        RECT 531.150 73.433 531.250 73.457 ;
    END
  END kr_data[353]
  PIN kr_data[352]
    DIRECTION INPUT ;
    USE SIGNAL ;
    PORT
      LAYER M4 ;
        RECT 531.150 73.529 531.250 73.553 ;
    END
  END kr_data[352]
  PIN kr_data[351]
    DIRECTION INPUT ;
    USE SIGNAL ;
    PORT
      LAYER M4 ;
        RECT 531.150 73.625 531.250 73.649 ;
    END
  END kr_data[351]
  PIN kr_data[350]
    DIRECTION INPUT ;
    USE SIGNAL ;
    PORT
      LAYER M4 ;
        RECT 531.150 73.721 531.250 73.745 ;
    END
  END kr_data[350]
  PIN kr_data[349]
    DIRECTION INPUT ;
    USE SIGNAL ;
    PORT
      LAYER M4 ;
        RECT 531.150 73.817 531.250 73.841 ;
    END
  END kr_data[349]
  PIN kr_data[348]
    DIRECTION INPUT ;
    USE SIGNAL ;
    PORT
      LAYER M4 ;
        RECT 531.150 73.913 531.250 73.937 ;
    END
  END kr_data[348]
  PIN kr_data[347]
    DIRECTION INPUT ;
    USE SIGNAL ;
    PORT
      LAYER M4 ;
        RECT 531.150 74.009 531.250 74.033 ;
    END
  END kr_data[347]
  PIN kr_data[346]
    DIRECTION INPUT ;
    USE SIGNAL ;
    PORT
      LAYER M4 ;
        RECT 531.150 74.105 531.250 74.129 ;
    END
  END kr_data[346]
  PIN kr_data[345]
    DIRECTION INPUT ;
    USE SIGNAL ;
    PORT
      LAYER M4 ;
        RECT 531.150 74.201 531.250 74.225 ;
    END
  END kr_data[345]
  PIN kr_data[344]
    DIRECTION INPUT ;
    USE SIGNAL ;
    PORT
      LAYER M4 ;
        RECT 531.150 74.297 531.250 74.321 ;
    END
  END kr_data[344]
  PIN kr_data[343]
    DIRECTION INPUT ;
    USE SIGNAL ;
    PORT
      LAYER M4 ;
        RECT 531.150 74.393 531.250 74.417 ;
    END
  END kr_data[343]
  PIN kr_data[342]
    DIRECTION INPUT ;
    USE SIGNAL ;
    PORT
      LAYER M4 ;
        RECT 531.150 74.489 531.250 74.513 ;
    END
  END kr_data[342]
  PIN kr_data[341]
    DIRECTION INPUT ;
    USE SIGNAL ;
    PORT
      LAYER M4 ;
        RECT 531.150 74.585 531.250 74.609 ;
    END
  END kr_data[341]
  PIN kr_data[340]
    DIRECTION INPUT ;
    USE SIGNAL ;
    PORT
      LAYER M4 ;
        RECT 531.150 74.681 531.250 74.705 ;
    END
  END kr_data[340]
  PIN kr_data[339]
    DIRECTION INPUT ;
    USE SIGNAL ;
    PORT
      LAYER M4 ;
        RECT 531.150 74.777 531.250 74.801 ;
    END
  END kr_data[339]
  PIN kr_data[338]
    DIRECTION INPUT ;
    USE SIGNAL ;
    PORT
      LAYER M4 ;
        RECT 531.150 74.873 531.250 74.897 ;
    END
  END kr_data[338]
  PIN kr_data[337]
    DIRECTION INPUT ;
    USE SIGNAL ;
    PORT
      LAYER M4 ;
        RECT 531.150 74.969 531.250 74.993 ;
    END
  END kr_data[337]
  PIN kr_data[336]
    DIRECTION INPUT ;
    USE SIGNAL ;
    PORT
      LAYER M4 ;
        RECT 531.150 75.065 531.250 75.089 ;
    END
  END kr_data[336]
  PIN kr_data[335]
    DIRECTION INPUT ;
    USE SIGNAL ;
    PORT
      LAYER M4 ;
        RECT 531.150 75.161 531.250 75.185 ;
    END
  END kr_data[335]
  PIN kr_data[334]
    DIRECTION INPUT ;
    USE SIGNAL ;
    PORT
      LAYER M4 ;
        RECT 531.150 75.257 531.250 75.281 ;
    END
  END kr_data[334]
  PIN kr_data[333]
    DIRECTION INPUT ;
    USE SIGNAL ;
    PORT
      LAYER M4 ;
        RECT 531.150 75.353 531.250 75.377 ;
    END
  END kr_data[333]
  PIN kr_data[332]
    DIRECTION INPUT ;
    USE SIGNAL ;
    PORT
      LAYER M4 ;
        RECT 531.150 75.449 531.250 75.473 ;
    END
  END kr_data[332]
  PIN kr_data[331]
    DIRECTION INPUT ;
    USE SIGNAL ;
    PORT
      LAYER M4 ;
        RECT 531.150 75.545 531.250 75.569 ;
    END
  END kr_data[331]
  PIN kr_data[330]
    DIRECTION INPUT ;
    USE SIGNAL ;
    PORT
      LAYER M4 ;
        RECT 531.150 75.641 531.250 75.665 ;
    END
  END kr_data[330]
  PIN kr_data[329]
    DIRECTION INPUT ;
    USE SIGNAL ;
    PORT
      LAYER M4 ;
        RECT 531.150 75.737 531.250 75.761 ;
    END
  END kr_data[329]
  PIN kr_data[328]
    DIRECTION INPUT ;
    USE SIGNAL ;
    PORT
      LAYER M4 ;
        RECT 531.150 75.833 531.250 75.857 ;
    END
  END kr_data[328]
  PIN kr_data[327]
    DIRECTION INPUT ;
    USE SIGNAL ;
    PORT
      LAYER M4 ;
        RECT 531.150 75.929 531.250 75.953 ;
    END
  END kr_data[327]
  PIN kr_data[326]
    DIRECTION INPUT ;
    USE SIGNAL ;
    PORT
      LAYER M4 ;
        RECT 531.150 76.025 531.250 76.049 ;
    END
  END kr_data[326]
  PIN kr_data[325]
    DIRECTION INPUT ;
    USE SIGNAL ;
    PORT
      LAYER M4 ;
        RECT 531.150 76.121 531.250 76.145 ;
    END
  END kr_data[325]
  PIN kr_data[324]
    DIRECTION INPUT ;
    USE SIGNAL ;
    PORT
      LAYER M4 ;
        RECT 531.150 76.217 531.250 76.241 ;
    END
  END kr_data[324]
  PIN kr_data[323]
    DIRECTION INPUT ;
    USE SIGNAL ;
    PORT
      LAYER M4 ;
        RECT 531.150 76.313 531.250 76.337 ;
    END
  END kr_data[323]
  PIN kr_data[322]
    DIRECTION INPUT ;
    USE SIGNAL ;
    PORT
      LAYER M4 ;
        RECT 531.150 76.409 531.250 76.433 ;
    END
  END kr_data[322]
  PIN kr_data[321]
    DIRECTION INPUT ;
    USE SIGNAL ;
    PORT
      LAYER M4 ;
        RECT 531.150 76.505 531.250 76.529 ;
    END
  END kr_data[321]
  PIN kr_data[320]
    DIRECTION INPUT ;
    USE SIGNAL ;
    PORT
      LAYER M4 ;
        RECT 531.150 76.601 531.250 76.625 ;
    END
  END kr_data[320]
  PIN kr_data[319]
    DIRECTION INPUT ;
    USE SIGNAL ;
    PORT
      LAYER M4 ;
        RECT 531.150 76.697 531.250 76.721 ;
    END
  END kr_data[319]
  PIN kr_data[318]
    DIRECTION INPUT ;
    USE SIGNAL ;
    PORT
      LAYER M4 ;
        RECT 531.150 76.793 531.250 76.817 ;
    END
  END kr_data[318]
  PIN kr_data[317]
    DIRECTION INPUT ;
    USE SIGNAL ;
    PORT
      LAYER M4 ;
        RECT 531.150 76.889 531.250 76.913 ;
    END
  END kr_data[317]
  PIN kr_data[316]
    DIRECTION INPUT ;
    USE SIGNAL ;
    PORT
      LAYER M4 ;
        RECT 531.150 76.985 531.250 77.009 ;
    END
  END kr_data[316]
  PIN kr_data[315]
    DIRECTION INPUT ;
    USE SIGNAL ;
    PORT
      LAYER M4 ;
        RECT 531.150 77.081 531.250 77.105 ;
    END
  END kr_data[315]
  PIN kr_data[314]
    DIRECTION INPUT ;
    USE SIGNAL ;
    PORT
      LAYER M4 ;
        RECT 531.150 77.177 531.250 77.201 ;
    END
  END kr_data[314]
  PIN kr_data[313]
    DIRECTION INPUT ;
    USE SIGNAL ;
    PORT
      LAYER M4 ;
        RECT 531.150 77.273 531.250 77.297 ;
    END
  END kr_data[313]
  PIN kr_data[312]
    DIRECTION INPUT ;
    USE SIGNAL ;
    PORT
      LAYER M4 ;
        RECT 531.150 77.369 531.250 77.393 ;
    END
  END kr_data[312]
  PIN kr_data[311]
    DIRECTION INPUT ;
    USE SIGNAL ;
    PORT
      LAYER M4 ;
        RECT 531.150 77.465 531.250 77.489 ;
    END
  END kr_data[311]
  PIN kr_data[310]
    DIRECTION INPUT ;
    USE SIGNAL ;
    PORT
      LAYER M4 ;
        RECT 531.150 77.561 531.250 77.585 ;
    END
  END kr_data[310]
  PIN kr_data[309]
    DIRECTION INPUT ;
    USE SIGNAL ;
    PORT
      LAYER M4 ;
        RECT 531.150 77.657 531.250 77.681 ;
    END
  END kr_data[309]
  PIN kr_data[308]
    DIRECTION INPUT ;
    USE SIGNAL ;
    PORT
      LAYER M4 ;
        RECT 531.150 77.753 531.250 77.777 ;
    END
  END kr_data[308]
  PIN kr_data[307]
    DIRECTION INPUT ;
    USE SIGNAL ;
    PORT
      LAYER M4 ;
        RECT 531.150 77.849 531.250 77.873 ;
    END
  END kr_data[307]
  PIN kr_data[306]
    DIRECTION INPUT ;
    USE SIGNAL ;
    PORT
      LAYER M4 ;
        RECT 531.150 77.945 531.250 77.969 ;
    END
  END kr_data[306]
  PIN kr_data[305]
    DIRECTION INPUT ;
    USE SIGNAL ;
    PORT
      LAYER M4 ;
        RECT 531.150 78.041 531.250 78.065 ;
    END
  END kr_data[305]
  PIN kr_data[304]
    DIRECTION INPUT ;
    USE SIGNAL ;
    PORT
      LAYER M4 ;
        RECT 531.150 78.137 531.250 78.161 ;
    END
  END kr_data[304]
  PIN kr_data[303]
    DIRECTION INPUT ;
    USE SIGNAL ;
    PORT
      LAYER M4 ;
        RECT 531.150 78.233 531.250 78.257 ;
    END
  END kr_data[303]
  PIN kr_data[302]
    DIRECTION INPUT ;
    USE SIGNAL ;
    PORT
      LAYER M4 ;
        RECT 531.150 78.329 531.250 78.353 ;
    END
  END kr_data[302]
  PIN kr_data[301]
    DIRECTION INPUT ;
    USE SIGNAL ;
    PORT
      LAYER M4 ;
        RECT 531.150 78.425 531.250 78.449 ;
    END
  END kr_data[301]
  PIN kr_data[300]
    DIRECTION INPUT ;
    USE SIGNAL ;
    PORT
      LAYER M4 ;
        RECT 531.150 78.521 531.250 78.545 ;
    END
  END kr_data[300]
  PIN kr_data[299]
    DIRECTION INPUT ;
    USE SIGNAL ;
    PORT
      LAYER M4 ;
        RECT 531.150 78.617 531.250 78.641 ;
    END
  END kr_data[299]
  PIN kr_data[298]
    DIRECTION INPUT ;
    USE SIGNAL ;
    PORT
      LAYER M4 ;
        RECT 531.150 78.713 531.250 78.737 ;
    END
  END kr_data[298]
  PIN kr_data[297]
    DIRECTION INPUT ;
    USE SIGNAL ;
    PORT
      LAYER M4 ;
        RECT 531.150 78.809 531.250 78.833 ;
    END
  END kr_data[297]
  PIN kr_data[296]
    DIRECTION INPUT ;
    USE SIGNAL ;
    PORT
      LAYER M4 ;
        RECT 531.150 78.905 531.250 78.929 ;
    END
  END kr_data[296]
  PIN kr_data[295]
    DIRECTION INPUT ;
    USE SIGNAL ;
    PORT
      LAYER M4 ;
        RECT 531.150 79.001 531.250 79.025 ;
    END
  END kr_data[295]
  PIN kr_data[294]
    DIRECTION INPUT ;
    USE SIGNAL ;
    PORT
      LAYER M4 ;
        RECT 531.150 79.097 531.250 79.121 ;
    END
  END kr_data[294]
  PIN kr_data[293]
    DIRECTION INPUT ;
    USE SIGNAL ;
    PORT
      LAYER M4 ;
        RECT 531.150 79.193 531.250 79.217 ;
    END
  END kr_data[293]
  PIN kr_data[292]
    DIRECTION INPUT ;
    USE SIGNAL ;
    PORT
      LAYER M4 ;
        RECT 531.150 79.289 531.250 79.313 ;
    END
  END kr_data[292]
  PIN kr_data[291]
    DIRECTION INPUT ;
    USE SIGNAL ;
    PORT
      LAYER M4 ;
        RECT 531.150 79.385 531.250 79.409 ;
    END
  END kr_data[291]
  PIN kr_data[290]
    DIRECTION INPUT ;
    USE SIGNAL ;
    PORT
      LAYER M4 ;
        RECT 531.150 79.481 531.250 79.505 ;
    END
  END kr_data[290]
  PIN kr_data[289]
    DIRECTION INPUT ;
    USE SIGNAL ;
    PORT
      LAYER M4 ;
        RECT 531.150 79.577 531.250 79.601 ;
    END
  END kr_data[289]
  PIN kr_data[288]
    DIRECTION INPUT ;
    USE SIGNAL ;
    PORT
      LAYER M4 ;
        RECT 531.150 79.673 531.250 79.697 ;
    END
  END kr_data[288]
  PIN kr_data[287]
    DIRECTION INPUT ;
    USE SIGNAL ;
    PORT
      LAYER M4 ;
        RECT 531.150 79.769 531.250 79.793 ;
    END
  END kr_data[287]
  PIN kr_data[286]
    DIRECTION INPUT ;
    USE SIGNAL ;
    PORT
      LAYER M4 ;
        RECT 531.150 79.865 531.250 79.889 ;
    END
  END kr_data[286]
  PIN kr_data[285]
    DIRECTION INPUT ;
    USE SIGNAL ;
    PORT
      LAYER M4 ;
        RECT 531.150 79.961 531.250 79.985 ;
    END
  END kr_data[285]
  PIN kr_data[284]
    DIRECTION INPUT ;
    USE SIGNAL ;
    PORT
      LAYER M4 ;
        RECT 531.150 80.057 531.250 80.081 ;
    END
  END kr_data[284]
  PIN kr_data[283]
    DIRECTION INPUT ;
    USE SIGNAL ;
    PORT
      LAYER M4 ;
        RECT 531.150 80.153 531.250 80.177 ;
    END
  END kr_data[283]
  PIN kr_data[282]
    DIRECTION INPUT ;
    USE SIGNAL ;
    PORT
      LAYER M4 ;
        RECT 531.150 80.249 531.250 80.273 ;
    END
  END kr_data[282]
  PIN kr_data[281]
    DIRECTION INPUT ;
    USE SIGNAL ;
    PORT
      LAYER M4 ;
        RECT 531.150 80.345 531.250 80.369 ;
    END
  END kr_data[281]
  PIN kr_data[280]
    DIRECTION INPUT ;
    USE SIGNAL ;
    PORT
      LAYER M4 ;
        RECT 531.150 80.441 531.250 80.465 ;
    END
  END kr_data[280]
  PIN kr_data[279]
    DIRECTION INPUT ;
    USE SIGNAL ;
    PORT
      LAYER M4 ;
        RECT 531.150 80.537 531.250 80.561 ;
    END
  END kr_data[279]
  PIN kr_data[278]
    DIRECTION INPUT ;
    USE SIGNAL ;
    PORT
      LAYER M4 ;
        RECT 531.150 80.633 531.250 80.657 ;
    END
  END kr_data[278]
  PIN kr_data[277]
    DIRECTION INPUT ;
    USE SIGNAL ;
    PORT
      LAYER M4 ;
        RECT 531.150 80.729 531.250 80.753 ;
    END
  END kr_data[277]
  PIN kr_data[276]
    DIRECTION INPUT ;
    USE SIGNAL ;
    PORT
      LAYER M4 ;
        RECT 531.150 80.825 531.250 80.849 ;
    END
  END kr_data[276]
  PIN kr_data[275]
    DIRECTION INPUT ;
    USE SIGNAL ;
    PORT
      LAYER M4 ;
        RECT 531.150 80.921 531.250 80.945 ;
    END
  END kr_data[275]
  PIN kr_data[274]
    DIRECTION INPUT ;
    USE SIGNAL ;
    PORT
      LAYER M4 ;
        RECT 531.150 81.017 531.250 81.041 ;
    END
  END kr_data[274]
  PIN kr_data[273]
    DIRECTION INPUT ;
    USE SIGNAL ;
    PORT
      LAYER M4 ;
        RECT 531.150 81.113 531.250 81.137 ;
    END
  END kr_data[273]
  PIN kr_data[272]
    DIRECTION INPUT ;
    USE SIGNAL ;
    PORT
      LAYER M4 ;
        RECT 531.150 81.209 531.250 81.233 ;
    END
  END kr_data[272]
  PIN kr_data[271]
    DIRECTION INPUT ;
    USE SIGNAL ;
    PORT
      LAYER M4 ;
        RECT 531.150 81.305 531.250 81.329 ;
    END
  END kr_data[271]
  PIN kr_data[270]
    DIRECTION INPUT ;
    USE SIGNAL ;
    PORT
      LAYER M4 ;
        RECT 531.150 81.401 531.250 81.425 ;
    END
  END kr_data[270]
  PIN kr_data[269]
    DIRECTION INPUT ;
    USE SIGNAL ;
    PORT
      LAYER M4 ;
        RECT 531.150 81.497 531.250 81.521 ;
    END
  END kr_data[269]
  PIN kr_data[268]
    DIRECTION INPUT ;
    USE SIGNAL ;
    PORT
      LAYER M4 ;
        RECT 531.150 81.593 531.250 81.617 ;
    END
  END kr_data[268]
  PIN kr_data[267]
    DIRECTION INPUT ;
    USE SIGNAL ;
    PORT
      LAYER M4 ;
        RECT 531.150 81.689 531.250 81.713 ;
    END
  END kr_data[267]
  PIN kr_data[266]
    DIRECTION INPUT ;
    USE SIGNAL ;
    PORT
      LAYER M4 ;
        RECT 531.150 81.785 531.250 81.809 ;
    END
  END kr_data[266]
  PIN kr_data[265]
    DIRECTION INPUT ;
    USE SIGNAL ;
    PORT
      LAYER M4 ;
        RECT 531.150 81.881 531.250 81.905 ;
    END
  END kr_data[265]
  PIN kr_data[264]
    DIRECTION INPUT ;
    USE SIGNAL ;
    PORT
      LAYER M4 ;
        RECT 531.150 81.977 531.250 82.001 ;
    END
  END kr_data[264]
  PIN kr_data[263]
    DIRECTION INPUT ;
    USE SIGNAL ;
    PORT
      LAYER M4 ;
        RECT 531.150 82.073 531.250 82.097 ;
    END
  END kr_data[263]
  PIN kr_data[262]
    DIRECTION INPUT ;
    USE SIGNAL ;
    PORT
      LAYER M4 ;
        RECT 531.150 82.169 531.250 82.193 ;
    END
  END kr_data[262]
  PIN kr_data[261]
    DIRECTION INPUT ;
    USE SIGNAL ;
    PORT
      LAYER M4 ;
        RECT 531.150 82.265 531.250 82.289 ;
    END
  END kr_data[261]
  PIN kr_data[260]
    DIRECTION INPUT ;
    USE SIGNAL ;
    PORT
      LAYER M4 ;
        RECT 531.150 82.361 531.250 82.385 ;
    END
  END kr_data[260]
  PIN kr_data[259]
    DIRECTION INPUT ;
    USE SIGNAL ;
    PORT
      LAYER M4 ;
        RECT 531.150 82.457 531.250 82.481 ;
    END
  END kr_data[259]
  PIN kr_data[258]
    DIRECTION INPUT ;
    USE SIGNAL ;
    PORT
      LAYER M4 ;
        RECT 531.150 82.553 531.250 82.577 ;
    END
  END kr_data[258]
  PIN kr_data[257]
    DIRECTION INPUT ;
    USE SIGNAL ;
    PORT
      LAYER M4 ;
        RECT 531.150 82.649 531.250 82.673 ;
    END
  END kr_data[257]
  PIN kr_data[256]
    DIRECTION INPUT ;
    USE SIGNAL ;
    PORT
      LAYER M4 ;
        RECT 531.150 82.745 531.250 82.769 ;
    END
  END kr_data[256]
  PIN kr_data[255]
    DIRECTION INPUT ;
    USE SIGNAL ;
    PORT
      LAYER M4 ;
        RECT 531.150 82.841 531.250 82.865 ;
    END
  END kr_data[255]
  PIN kr_data[254]
    DIRECTION INPUT ;
    USE SIGNAL ;
    PORT
      LAYER M4 ;
        RECT 531.150 82.937 531.250 82.961 ;
    END
  END kr_data[254]
  PIN kr_data[253]
    DIRECTION INPUT ;
    USE SIGNAL ;
    PORT
      LAYER M4 ;
        RECT 531.150 83.033 531.250 83.057 ;
    END
  END kr_data[253]
  PIN kr_data[252]
    DIRECTION INPUT ;
    USE SIGNAL ;
    PORT
      LAYER M4 ;
        RECT 531.150 83.129 531.250 83.153 ;
    END
  END kr_data[252]
  PIN kr_data[251]
    DIRECTION INPUT ;
    USE SIGNAL ;
    PORT
      LAYER M4 ;
        RECT 531.150 83.225 531.250 83.249 ;
    END
  END kr_data[251]
  PIN kr_data[250]
    DIRECTION INPUT ;
    USE SIGNAL ;
    PORT
      LAYER M4 ;
        RECT 531.150 83.321 531.250 83.345 ;
    END
  END kr_data[250]
  PIN kr_data[249]
    DIRECTION INPUT ;
    USE SIGNAL ;
    PORT
      LAYER M4 ;
        RECT 531.150 83.417 531.250 83.441 ;
    END
  END kr_data[249]
  PIN kr_data[248]
    DIRECTION INPUT ;
    USE SIGNAL ;
    PORT
      LAYER M4 ;
        RECT 531.150 83.513 531.250 83.537 ;
    END
  END kr_data[248]
  PIN kr_data[247]
    DIRECTION INPUT ;
    USE SIGNAL ;
    PORT
      LAYER M4 ;
        RECT 531.150 83.609 531.250 83.633 ;
    END
  END kr_data[247]
  PIN kr_data[246]
    DIRECTION INPUT ;
    USE SIGNAL ;
    PORT
      LAYER M4 ;
        RECT 531.150 83.705 531.250 83.729 ;
    END
  END kr_data[246]
  PIN kr_data[245]
    DIRECTION INPUT ;
    USE SIGNAL ;
    PORT
      LAYER M4 ;
        RECT 531.150 83.801 531.250 83.825 ;
    END
  END kr_data[245]
  PIN kr_data[244]
    DIRECTION INPUT ;
    USE SIGNAL ;
    PORT
      LAYER M4 ;
        RECT 531.150 83.897 531.250 83.921 ;
    END
  END kr_data[244]
  PIN kr_data[243]
    DIRECTION INPUT ;
    USE SIGNAL ;
    PORT
      LAYER M4 ;
        RECT 531.150 83.993 531.250 84.017 ;
    END
  END kr_data[243]
  PIN kr_data[242]
    DIRECTION INPUT ;
    USE SIGNAL ;
    PORT
      LAYER M4 ;
        RECT 531.150 84.089 531.250 84.113 ;
    END
  END kr_data[242]
  PIN kr_data[241]
    DIRECTION INPUT ;
    USE SIGNAL ;
    PORT
      LAYER M4 ;
        RECT 531.150 84.185 531.250 84.209 ;
    END
  END kr_data[241]
  PIN kr_data[240]
    DIRECTION INPUT ;
    USE SIGNAL ;
    PORT
      LAYER M4 ;
        RECT 531.150 84.281 531.250 84.305 ;
    END
  END kr_data[240]
  PIN kr_data[239]
    DIRECTION INPUT ;
    USE SIGNAL ;
    PORT
      LAYER M4 ;
        RECT 531.150 84.377 531.250 84.401 ;
    END
  END kr_data[239]
  PIN kr_data[238]
    DIRECTION INPUT ;
    USE SIGNAL ;
    PORT
      LAYER M4 ;
        RECT 531.150 84.473 531.250 84.497 ;
    END
  END kr_data[238]
  PIN kr_data[237]
    DIRECTION INPUT ;
    USE SIGNAL ;
    PORT
      LAYER M4 ;
        RECT 531.150 84.569 531.250 84.593 ;
    END
  END kr_data[237]
  PIN kr_data[236]
    DIRECTION INPUT ;
    USE SIGNAL ;
    PORT
      LAYER M4 ;
        RECT 531.150 84.665 531.250 84.689 ;
    END
  END kr_data[236]
  PIN kr_data[235]
    DIRECTION INPUT ;
    USE SIGNAL ;
    PORT
      LAYER M4 ;
        RECT 531.150 84.761 531.250 84.785 ;
    END
  END kr_data[235]
  PIN kr_data[234]
    DIRECTION INPUT ;
    USE SIGNAL ;
    PORT
      LAYER M4 ;
        RECT 531.150 84.857 531.250 84.881 ;
    END
  END kr_data[234]
  PIN kr_data[233]
    DIRECTION INPUT ;
    USE SIGNAL ;
    PORT
      LAYER M4 ;
        RECT 531.150 84.953 531.250 84.977 ;
    END
  END kr_data[233]
  PIN kr_data[232]
    DIRECTION INPUT ;
    USE SIGNAL ;
    PORT
      LAYER M4 ;
        RECT 531.150 85.049 531.250 85.073 ;
    END
  END kr_data[232]
  PIN kr_data[231]
    DIRECTION INPUT ;
    USE SIGNAL ;
    PORT
      LAYER M4 ;
        RECT 531.150 85.145 531.250 85.169 ;
    END
  END kr_data[231]
  PIN kr_data[230]
    DIRECTION INPUT ;
    USE SIGNAL ;
    PORT
      LAYER M4 ;
        RECT 531.150 85.241 531.250 85.265 ;
    END
  END kr_data[230]
  PIN kr_data[229]
    DIRECTION INPUT ;
    USE SIGNAL ;
    PORT
      LAYER M4 ;
        RECT 531.150 85.337 531.250 85.361 ;
    END
  END kr_data[229]
  PIN kr_data[228]
    DIRECTION INPUT ;
    USE SIGNAL ;
    PORT
      LAYER M4 ;
        RECT 531.150 85.433 531.250 85.457 ;
    END
  END kr_data[228]
  PIN kr_data[227]
    DIRECTION INPUT ;
    USE SIGNAL ;
    PORT
      LAYER M4 ;
        RECT 531.150 85.529 531.250 85.553 ;
    END
  END kr_data[227]
  PIN kr_data[226]
    DIRECTION INPUT ;
    USE SIGNAL ;
    PORT
      LAYER M4 ;
        RECT 531.150 85.625 531.250 85.649 ;
    END
  END kr_data[226]
  PIN kr_data[225]
    DIRECTION INPUT ;
    USE SIGNAL ;
    PORT
      LAYER M4 ;
        RECT 531.150 85.721 531.250 85.745 ;
    END
  END kr_data[225]
  PIN kr_data[224]
    DIRECTION INPUT ;
    USE SIGNAL ;
    PORT
      LAYER M4 ;
        RECT 531.150 85.817 531.250 85.841 ;
    END
  END kr_data[224]
  PIN kr_data[223]
    DIRECTION INPUT ;
    USE SIGNAL ;
    PORT
      LAYER M4 ;
        RECT 531.150 85.913 531.250 85.937 ;
    END
  END kr_data[223]
  PIN kr_data[222]
    DIRECTION INPUT ;
    USE SIGNAL ;
    PORT
      LAYER M4 ;
        RECT 531.150 86.009 531.250 86.033 ;
    END
  END kr_data[222]
  PIN kr_data[221]
    DIRECTION INPUT ;
    USE SIGNAL ;
    PORT
      LAYER M4 ;
        RECT 531.150 86.105 531.250 86.129 ;
    END
  END kr_data[221]
  PIN kr_data[220]
    DIRECTION INPUT ;
    USE SIGNAL ;
    PORT
      LAYER M4 ;
        RECT 531.150 86.201 531.250 86.225 ;
    END
  END kr_data[220]
  PIN kr_data[219]
    DIRECTION INPUT ;
    USE SIGNAL ;
    PORT
      LAYER M4 ;
        RECT 531.150 86.297 531.250 86.321 ;
    END
  END kr_data[219]
  PIN kr_data[218]
    DIRECTION INPUT ;
    USE SIGNAL ;
    PORT
      LAYER M4 ;
        RECT 531.150 86.393 531.250 86.417 ;
    END
  END kr_data[218]
  PIN kr_data[217]
    DIRECTION INPUT ;
    USE SIGNAL ;
    PORT
      LAYER M4 ;
        RECT 531.150 86.489 531.250 86.513 ;
    END
  END kr_data[217]
  PIN kr_data[216]
    DIRECTION INPUT ;
    USE SIGNAL ;
    PORT
      LAYER M4 ;
        RECT 531.150 86.585 531.250 86.609 ;
    END
  END kr_data[216]
  PIN kr_data[215]
    DIRECTION INPUT ;
    USE SIGNAL ;
    PORT
      LAYER M4 ;
        RECT 531.150 86.681 531.250 86.705 ;
    END
  END kr_data[215]
  PIN kr_data[214]
    DIRECTION INPUT ;
    USE SIGNAL ;
    PORT
      LAYER M4 ;
        RECT 531.150 86.777 531.250 86.801 ;
    END
  END kr_data[214]
  PIN kr_data[213]
    DIRECTION INPUT ;
    USE SIGNAL ;
    PORT
      LAYER M4 ;
        RECT 531.150 86.873 531.250 86.897 ;
    END
  END kr_data[213]
  PIN kr_data[212]
    DIRECTION INPUT ;
    USE SIGNAL ;
    PORT
      LAYER M4 ;
        RECT 531.150 86.969 531.250 86.993 ;
    END
  END kr_data[212]
  PIN kr_data[211]
    DIRECTION INPUT ;
    USE SIGNAL ;
    PORT
      LAYER M4 ;
        RECT 531.150 87.065 531.250 87.089 ;
    END
  END kr_data[211]
  PIN kr_data[210]
    DIRECTION INPUT ;
    USE SIGNAL ;
    PORT
      LAYER M4 ;
        RECT 531.150 87.161 531.250 87.185 ;
    END
  END kr_data[210]
  PIN kr_data[209]
    DIRECTION INPUT ;
    USE SIGNAL ;
    PORT
      LAYER M4 ;
        RECT 531.150 87.257 531.250 87.281 ;
    END
  END kr_data[209]
  PIN kr_data[208]
    DIRECTION INPUT ;
    USE SIGNAL ;
    PORT
      LAYER M4 ;
        RECT 531.150 87.353 531.250 87.377 ;
    END
  END kr_data[208]
  PIN kr_data[207]
    DIRECTION INPUT ;
    USE SIGNAL ;
    PORT
      LAYER M4 ;
        RECT 531.150 87.449 531.250 87.473 ;
    END
  END kr_data[207]
  PIN kr_data[206]
    DIRECTION INPUT ;
    USE SIGNAL ;
    PORT
      LAYER M4 ;
        RECT 531.150 87.545 531.250 87.569 ;
    END
  END kr_data[206]
  PIN kr_data[205]
    DIRECTION INPUT ;
    USE SIGNAL ;
    PORT
      LAYER M4 ;
        RECT 531.150 87.641 531.250 87.665 ;
    END
  END kr_data[205]
  PIN kr_data[204]
    DIRECTION INPUT ;
    USE SIGNAL ;
    PORT
      LAYER M4 ;
        RECT 531.150 87.737 531.250 87.761 ;
    END
  END kr_data[204]
  PIN kr_data[203]
    DIRECTION INPUT ;
    USE SIGNAL ;
    PORT
      LAYER M4 ;
        RECT 531.150 87.833 531.250 87.857 ;
    END
  END kr_data[203]
  PIN kr_data[202]
    DIRECTION INPUT ;
    USE SIGNAL ;
    PORT
      LAYER M4 ;
        RECT 531.150 87.929 531.250 87.953 ;
    END
  END kr_data[202]
  PIN kr_data[201]
    DIRECTION INPUT ;
    USE SIGNAL ;
    PORT
      LAYER M4 ;
        RECT 531.150 88.025 531.250 88.049 ;
    END
  END kr_data[201]
  PIN kr_data[200]
    DIRECTION INPUT ;
    USE SIGNAL ;
    PORT
      LAYER M4 ;
        RECT 531.150 88.121 531.250 88.145 ;
    END
  END kr_data[200]
  PIN kr_data[199]
    DIRECTION INPUT ;
    USE SIGNAL ;
    PORT
      LAYER M4 ;
        RECT 531.150 88.217 531.250 88.241 ;
    END
  END kr_data[199]
  PIN kr_data[198]
    DIRECTION INPUT ;
    USE SIGNAL ;
    PORT
      LAYER M4 ;
        RECT 531.150 88.313 531.250 88.337 ;
    END
  END kr_data[198]
  PIN kr_data[197]
    DIRECTION INPUT ;
    USE SIGNAL ;
    PORT
      LAYER M4 ;
        RECT 531.150 88.409 531.250 88.433 ;
    END
  END kr_data[197]
  PIN kr_data[196]
    DIRECTION INPUT ;
    USE SIGNAL ;
    PORT
      LAYER M4 ;
        RECT 531.150 88.505 531.250 88.529 ;
    END
  END kr_data[196]
  PIN kr_data[195]
    DIRECTION INPUT ;
    USE SIGNAL ;
    PORT
      LAYER M4 ;
        RECT 531.150 88.601 531.250 88.625 ;
    END
  END kr_data[195]
  PIN kr_data[194]
    DIRECTION INPUT ;
    USE SIGNAL ;
    PORT
      LAYER M4 ;
        RECT 531.150 88.697 531.250 88.721 ;
    END
  END kr_data[194]
  PIN kr_data[193]
    DIRECTION INPUT ;
    USE SIGNAL ;
    PORT
      LAYER M4 ;
        RECT 531.150 88.793 531.250 88.817 ;
    END
  END kr_data[193]
  PIN kr_data[192]
    DIRECTION INPUT ;
    USE SIGNAL ;
    PORT
      LAYER M4 ;
        RECT 531.150 88.889 531.250 88.913 ;
    END
  END kr_data[192]
  PIN kr_data[191]
    DIRECTION INPUT ;
    USE SIGNAL ;
    PORT
      LAYER M4 ;
        RECT 531.150 88.985 531.250 89.009 ;
    END
  END kr_data[191]
  PIN kr_data[190]
    DIRECTION INPUT ;
    USE SIGNAL ;
    PORT
      LAYER M4 ;
        RECT 531.150 89.081 531.250 89.105 ;
    END
  END kr_data[190]
  PIN kr_data[189]
    DIRECTION INPUT ;
    USE SIGNAL ;
    PORT
      LAYER M4 ;
        RECT 531.150 89.177 531.250 89.201 ;
    END
  END kr_data[189]
  PIN kr_data[188]
    DIRECTION INPUT ;
    USE SIGNAL ;
    PORT
      LAYER M4 ;
        RECT 531.150 89.273 531.250 89.297 ;
    END
  END kr_data[188]
  PIN kr_data[187]
    DIRECTION INPUT ;
    USE SIGNAL ;
    PORT
      LAYER M4 ;
        RECT 531.150 89.369 531.250 89.393 ;
    END
  END kr_data[187]
  PIN kr_data[186]
    DIRECTION INPUT ;
    USE SIGNAL ;
    PORT
      LAYER M4 ;
        RECT 531.150 89.465 531.250 89.489 ;
    END
  END kr_data[186]
  PIN kr_data[185]
    DIRECTION INPUT ;
    USE SIGNAL ;
    PORT
      LAYER M4 ;
        RECT 531.150 89.561 531.250 89.585 ;
    END
  END kr_data[185]
  PIN kr_data[184]
    DIRECTION INPUT ;
    USE SIGNAL ;
    PORT
      LAYER M4 ;
        RECT 531.150 89.657 531.250 89.681 ;
    END
  END kr_data[184]
  PIN kr_data[183]
    DIRECTION INPUT ;
    USE SIGNAL ;
    PORT
      LAYER M4 ;
        RECT 531.150 89.753 531.250 89.777 ;
    END
  END kr_data[183]
  PIN kr_data[182]
    DIRECTION INPUT ;
    USE SIGNAL ;
    PORT
      LAYER M4 ;
        RECT 531.150 89.849 531.250 89.873 ;
    END
  END kr_data[182]
  PIN kr_data[181]
    DIRECTION INPUT ;
    USE SIGNAL ;
    PORT
      LAYER M4 ;
        RECT 531.150 89.945 531.250 89.969 ;
    END
  END kr_data[181]
  PIN kr_data[180]
    DIRECTION INPUT ;
    USE SIGNAL ;
    PORT
      LAYER M4 ;
        RECT 531.150 90.041 531.250 90.065 ;
    END
  END kr_data[180]
  PIN kr_data[179]
    DIRECTION INPUT ;
    USE SIGNAL ;
    PORT
      LAYER M4 ;
        RECT 531.150 90.137 531.250 90.161 ;
    END
  END kr_data[179]
  PIN kr_data[178]
    DIRECTION INPUT ;
    USE SIGNAL ;
    PORT
      LAYER M4 ;
        RECT 531.150 90.233 531.250 90.257 ;
    END
  END kr_data[178]
  PIN kr_data[177]
    DIRECTION INPUT ;
    USE SIGNAL ;
    PORT
      LAYER M4 ;
        RECT 531.150 90.329 531.250 90.353 ;
    END
  END kr_data[177]
  PIN kr_data[176]
    DIRECTION INPUT ;
    USE SIGNAL ;
    PORT
      LAYER M4 ;
        RECT 531.150 90.425 531.250 90.449 ;
    END
  END kr_data[176]
  PIN kr_data[175]
    DIRECTION INPUT ;
    USE SIGNAL ;
    PORT
      LAYER M4 ;
        RECT 531.150 90.521 531.250 90.545 ;
    END
  END kr_data[175]
  PIN kr_data[174]
    DIRECTION INPUT ;
    USE SIGNAL ;
    PORT
      LAYER M4 ;
        RECT 531.150 90.617 531.250 90.641 ;
    END
  END kr_data[174]
  PIN kr_data[173]
    DIRECTION INPUT ;
    USE SIGNAL ;
    PORT
      LAYER M4 ;
        RECT 531.150 90.713 531.250 90.737 ;
    END
  END kr_data[173]
  PIN kr_data[172]
    DIRECTION INPUT ;
    USE SIGNAL ;
    PORT
      LAYER M4 ;
        RECT 531.150 90.809 531.250 90.833 ;
    END
  END kr_data[172]
  PIN kr_data[171]
    DIRECTION INPUT ;
    USE SIGNAL ;
    PORT
      LAYER M4 ;
        RECT 531.150 90.905 531.250 90.929 ;
    END
  END kr_data[171]
  PIN kr_data[170]
    DIRECTION INPUT ;
    USE SIGNAL ;
    PORT
      LAYER M4 ;
        RECT 531.150 91.001 531.250 91.025 ;
    END
  END kr_data[170]
  PIN kr_data[169]
    DIRECTION INPUT ;
    USE SIGNAL ;
    PORT
      LAYER M4 ;
        RECT 531.150 91.097 531.250 91.121 ;
    END
  END kr_data[169]
  PIN kr_data[168]
    DIRECTION INPUT ;
    USE SIGNAL ;
    PORT
      LAYER M4 ;
        RECT 531.150 91.193 531.250 91.217 ;
    END
  END kr_data[168]
  PIN kr_data[167]
    DIRECTION INPUT ;
    USE SIGNAL ;
    PORT
      LAYER M4 ;
        RECT 531.150 91.289 531.250 91.313 ;
    END
  END kr_data[167]
  PIN kr_data[166]
    DIRECTION INPUT ;
    USE SIGNAL ;
    PORT
      LAYER M4 ;
        RECT 531.150 91.385 531.250 91.409 ;
    END
  END kr_data[166]
  PIN kr_data[165]
    DIRECTION INPUT ;
    USE SIGNAL ;
    PORT
      LAYER M4 ;
        RECT 531.150 91.481 531.250 91.505 ;
    END
  END kr_data[165]
  PIN kr_data[164]
    DIRECTION INPUT ;
    USE SIGNAL ;
    PORT
      LAYER M4 ;
        RECT 531.150 91.577 531.250 91.601 ;
    END
  END kr_data[164]
  PIN kr_data[163]
    DIRECTION INPUT ;
    USE SIGNAL ;
    PORT
      LAYER M4 ;
        RECT 531.150 91.673 531.250 91.697 ;
    END
  END kr_data[163]
  PIN kr_data[162]
    DIRECTION INPUT ;
    USE SIGNAL ;
    PORT
      LAYER M4 ;
        RECT 531.150 91.769 531.250 91.793 ;
    END
  END kr_data[162]
  PIN kr_data[161]
    DIRECTION INPUT ;
    USE SIGNAL ;
    PORT
      LAYER M4 ;
        RECT 531.150 91.865 531.250 91.889 ;
    END
  END kr_data[161]
  PIN kr_data[160]
    DIRECTION INPUT ;
    USE SIGNAL ;
    PORT
      LAYER M4 ;
        RECT 531.150 91.961 531.250 91.985 ;
    END
  END kr_data[160]
  PIN kr_data[159]
    DIRECTION INPUT ;
    USE SIGNAL ;
    PORT
      LAYER M4 ;
        RECT 531.150 92.057 531.250 92.081 ;
    END
  END kr_data[159]
  PIN kr_data[158]
    DIRECTION INPUT ;
    USE SIGNAL ;
    PORT
      LAYER M4 ;
        RECT 531.150 92.153 531.250 92.177 ;
    END
  END kr_data[158]
  PIN kr_data[157]
    DIRECTION INPUT ;
    USE SIGNAL ;
    PORT
      LAYER M4 ;
        RECT 531.150 92.249 531.250 92.273 ;
    END
  END kr_data[157]
  PIN kr_data[156]
    DIRECTION INPUT ;
    USE SIGNAL ;
    PORT
      LAYER M4 ;
        RECT 531.150 92.345 531.250 92.369 ;
    END
  END kr_data[156]
  PIN kr_data[155]
    DIRECTION INPUT ;
    USE SIGNAL ;
    PORT
      LAYER M4 ;
        RECT 531.150 92.441 531.250 92.465 ;
    END
  END kr_data[155]
  PIN kr_data[154]
    DIRECTION INPUT ;
    USE SIGNAL ;
    PORT
      LAYER M4 ;
        RECT 531.150 92.537 531.250 92.561 ;
    END
  END kr_data[154]
  PIN kr_data[153]
    DIRECTION INPUT ;
    USE SIGNAL ;
    PORT
      LAYER M4 ;
        RECT 531.150 92.633 531.250 92.657 ;
    END
  END kr_data[153]
  PIN kr_data[152]
    DIRECTION INPUT ;
    USE SIGNAL ;
    PORT
      LAYER M4 ;
        RECT 531.150 92.729 531.250 92.753 ;
    END
  END kr_data[152]
  PIN kr_data[151]
    DIRECTION INPUT ;
    USE SIGNAL ;
    PORT
      LAYER M4 ;
        RECT 531.150 92.825 531.250 92.849 ;
    END
  END kr_data[151]
  PIN kr_data[150]
    DIRECTION INPUT ;
    USE SIGNAL ;
    PORT
      LAYER M4 ;
        RECT 531.150 92.921 531.250 92.945 ;
    END
  END kr_data[150]
  PIN kr_data[149]
    DIRECTION INPUT ;
    USE SIGNAL ;
    PORT
      LAYER M4 ;
        RECT 531.150 93.017 531.250 93.041 ;
    END
  END kr_data[149]
  PIN kr_data[148]
    DIRECTION INPUT ;
    USE SIGNAL ;
    PORT
      LAYER M4 ;
        RECT 531.150 93.113 531.250 93.137 ;
    END
  END kr_data[148]
  PIN kr_data[147]
    DIRECTION INPUT ;
    USE SIGNAL ;
    PORT
      LAYER M4 ;
        RECT 531.150 93.209 531.250 93.233 ;
    END
  END kr_data[147]
  PIN kr_data[146]
    DIRECTION INPUT ;
    USE SIGNAL ;
    PORT
      LAYER M4 ;
        RECT 531.150 93.305 531.250 93.329 ;
    END
  END kr_data[146]
  PIN kr_data[145]
    DIRECTION INPUT ;
    USE SIGNAL ;
    PORT
      LAYER M4 ;
        RECT 531.150 93.401 531.250 93.425 ;
    END
  END kr_data[145]
  PIN kr_data[144]
    DIRECTION INPUT ;
    USE SIGNAL ;
    PORT
      LAYER M4 ;
        RECT 531.150 93.497 531.250 93.521 ;
    END
  END kr_data[144]
  PIN kr_data[143]
    DIRECTION INPUT ;
    USE SIGNAL ;
    PORT
      LAYER M4 ;
        RECT 531.150 93.593 531.250 93.617 ;
    END
  END kr_data[143]
  PIN kr_data[142]
    DIRECTION INPUT ;
    USE SIGNAL ;
    PORT
      LAYER M4 ;
        RECT 531.150 93.689 531.250 93.713 ;
    END
  END kr_data[142]
  PIN kr_data[141]
    DIRECTION INPUT ;
    USE SIGNAL ;
    PORT
      LAYER M4 ;
        RECT 531.150 93.785 531.250 93.809 ;
    END
  END kr_data[141]
  PIN kr_data[140]
    DIRECTION INPUT ;
    USE SIGNAL ;
    PORT
      LAYER M4 ;
        RECT 531.150 93.881 531.250 93.905 ;
    END
  END kr_data[140]
  PIN kr_data[139]
    DIRECTION INPUT ;
    USE SIGNAL ;
    PORT
      LAYER M4 ;
        RECT 531.150 93.977 531.250 94.001 ;
    END
  END kr_data[139]
  PIN kr_data[138]
    DIRECTION INPUT ;
    USE SIGNAL ;
    PORT
      LAYER M4 ;
        RECT 531.150 94.073 531.250 94.097 ;
    END
  END kr_data[138]
  PIN kr_data[137]
    DIRECTION INPUT ;
    USE SIGNAL ;
    PORT
      LAYER M4 ;
        RECT 531.150 94.169 531.250 94.193 ;
    END
  END kr_data[137]
  PIN kr_data[136]
    DIRECTION INPUT ;
    USE SIGNAL ;
    PORT
      LAYER M4 ;
        RECT 531.150 94.265 531.250 94.289 ;
    END
  END kr_data[136]
  PIN kr_data[135]
    DIRECTION INPUT ;
    USE SIGNAL ;
    PORT
      LAYER M4 ;
        RECT 531.150 94.361 531.250 94.385 ;
    END
  END kr_data[135]
  PIN kr_data[134]
    DIRECTION INPUT ;
    USE SIGNAL ;
    PORT
      LAYER M4 ;
        RECT 531.150 94.457 531.250 94.481 ;
    END
  END kr_data[134]
  PIN kr_data[133]
    DIRECTION INPUT ;
    USE SIGNAL ;
    PORT
      LAYER M4 ;
        RECT 531.150 94.553 531.250 94.577 ;
    END
  END kr_data[133]
  PIN kr_data[132]
    DIRECTION INPUT ;
    USE SIGNAL ;
    PORT
      LAYER M4 ;
        RECT 531.150 94.649 531.250 94.673 ;
    END
  END kr_data[132]
  PIN kr_data[131]
    DIRECTION INPUT ;
    USE SIGNAL ;
    PORT
      LAYER M4 ;
        RECT 531.150 94.745 531.250 94.769 ;
    END
  END kr_data[131]
  PIN kr_data[130]
    DIRECTION INPUT ;
    USE SIGNAL ;
    PORT
      LAYER M4 ;
        RECT 531.150 94.841 531.250 94.865 ;
    END
  END kr_data[130]
  PIN kr_data[129]
    DIRECTION INPUT ;
    USE SIGNAL ;
    PORT
      LAYER M4 ;
        RECT 531.150 94.937 531.250 94.961 ;
    END
  END kr_data[129]
  PIN kr_data[128]
    DIRECTION INPUT ;
    USE SIGNAL ;
    PORT
      LAYER M4 ;
        RECT 531.150 95.033 531.250 95.057 ;
    END
  END kr_data[128]
  PIN kr_data[127]
    DIRECTION INPUT ;
    USE SIGNAL ;
    PORT
      LAYER M4 ;
        RECT 531.150 95.129 531.250 95.153 ;
    END
  END kr_data[127]
  PIN kr_data[126]
    DIRECTION INPUT ;
    USE SIGNAL ;
    PORT
      LAYER M4 ;
        RECT 531.150 95.225 531.250 95.249 ;
    END
  END kr_data[126]
  PIN kr_data[125]
    DIRECTION INPUT ;
    USE SIGNAL ;
    PORT
      LAYER M4 ;
        RECT 531.150 95.321 531.250 95.345 ;
    END
  END kr_data[125]
  PIN kr_data[124]
    DIRECTION INPUT ;
    USE SIGNAL ;
    PORT
      LAYER M4 ;
        RECT 531.150 95.417 531.250 95.441 ;
    END
  END kr_data[124]
  PIN kr_data[123]
    DIRECTION INPUT ;
    USE SIGNAL ;
    PORT
      LAYER M4 ;
        RECT 531.150 95.513 531.250 95.537 ;
    END
  END kr_data[123]
  PIN kr_data[122]
    DIRECTION INPUT ;
    USE SIGNAL ;
    PORT
      LAYER M4 ;
        RECT 531.150 95.609 531.250 95.633 ;
    END
  END kr_data[122]
  PIN kr_data[121]
    DIRECTION INPUT ;
    USE SIGNAL ;
    PORT
      LAYER M4 ;
        RECT 531.150 95.705 531.250 95.729 ;
    END
  END kr_data[121]
  PIN kr_data[120]
    DIRECTION INPUT ;
    USE SIGNAL ;
    PORT
      LAYER M4 ;
        RECT 531.150 95.801 531.250 95.825 ;
    END
  END kr_data[120]
  PIN kr_data[119]
    DIRECTION INPUT ;
    USE SIGNAL ;
    PORT
      LAYER M4 ;
        RECT 531.150 95.897 531.250 95.921 ;
    END
  END kr_data[119]
  PIN kr_data[118]
    DIRECTION INPUT ;
    USE SIGNAL ;
    PORT
      LAYER M4 ;
        RECT 531.150 95.993 531.250 96.017 ;
    END
  END kr_data[118]
  PIN kr_data[117]
    DIRECTION INPUT ;
    USE SIGNAL ;
    PORT
      LAYER M4 ;
        RECT 531.150 96.089 531.250 96.113 ;
    END
  END kr_data[117]
  PIN kr_data[116]
    DIRECTION INPUT ;
    USE SIGNAL ;
    PORT
      LAYER M4 ;
        RECT 531.150 96.185 531.250 96.209 ;
    END
  END kr_data[116]
  PIN kr_data[115]
    DIRECTION INPUT ;
    USE SIGNAL ;
    PORT
      LAYER M4 ;
        RECT 531.150 96.281 531.250 96.305 ;
    END
  END kr_data[115]
  PIN kr_data[114]
    DIRECTION INPUT ;
    USE SIGNAL ;
    PORT
      LAYER M4 ;
        RECT 531.150 96.377 531.250 96.401 ;
    END
  END kr_data[114]
  PIN kr_data[113]
    DIRECTION INPUT ;
    USE SIGNAL ;
    PORT
      LAYER M4 ;
        RECT 531.150 96.473 531.250 96.497 ;
    END
  END kr_data[113]
  PIN kr_data[112]
    DIRECTION INPUT ;
    USE SIGNAL ;
    PORT
      LAYER M4 ;
        RECT 531.150 96.569 531.250 96.593 ;
    END
  END kr_data[112]
  PIN kr_data[111]
    DIRECTION INPUT ;
    USE SIGNAL ;
    PORT
      LAYER M4 ;
        RECT 531.150 96.665 531.250 96.689 ;
    END
  END kr_data[111]
  PIN kr_data[110]
    DIRECTION INPUT ;
    USE SIGNAL ;
    PORT
      LAYER M4 ;
        RECT 531.150 96.761 531.250 96.785 ;
    END
  END kr_data[110]
  PIN kr_data[109]
    DIRECTION INPUT ;
    USE SIGNAL ;
    PORT
      LAYER M4 ;
        RECT 531.150 96.857 531.250 96.881 ;
    END
  END kr_data[109]
  PIN kr_data[108]
    DIRECTION INPUT ;
    USE SIGNAL ;
    PORT
      LAYER M4 ;
        RECT 531.150 96.953 531.250 96.977 ;
    END
  END kr_data[108]
  PIN kr_data[107]
    DIRECTION INPUT ;
    USE SIGNAL ;
    PORT
      LAYER M4 ;
        RECT 531.150 97.049 531.250 97.073 ;
    END
  END kr_data[107]
  PIN kr_data[106]
    DIRECTION INPUT ;
    USE SIGNAL ;
    PORT
      LAYER M4 ;
        RECT 531.150 97.145 531.250 97.169 ;
    END
  END kr_data[106]
  PIN kr_data[105]
    DIRECTION INPUT ;
    USE SIGNAL ;
    PORT
      LAYER M4 ;
        RECT 531.150 97.241 531.250 97.265 ;
    END
  END kr_data[105]
  PIN kr_data[104]
    DIRECTION INPUT ;
    USE SIGNAL ;
    PORT
      LAYER M4 ;
        RECT 531.150 97.337 531.250 97.361 ;
    END
  END kr_data[104]
  PIN kr_data[103]
    DIRECTION INPUT ;
    USE SIGNAL ;
    PORT
      LAYER M4 ;
        RECT 531.150 97.433 531.250 97.457 ;
    END
  END kr_data[103]
  PIN kr_data[102]
    DIRECTION INPUT ;
    USE SIGNAL ;
    PORT
      LAYER M4 ;
        RECT 531.150 97.529 531.250 97.553 ;
    END
  END kr_data[102]
  PIN kr_data[101]
    DIRECTION INPUT ;
    USE SIGNAL ;
    PORT
      LAYER M4 ;
        RECT 531.150 97.625 531.250 97.649 ;
    END
  END kr_data[101]
  PIN kr_data[100]
    DIRECTION INPUT ;
    USE SIGNAL ;
    PORT
      LAYER M4 ;
        RECT 531.150 97.721 531.250 97.745 ;
    END
  END kr_data[100]
  PIN kr_data[99]
    DIRECTION INPUT ;
    USE SIGNAL ;
    PORT
      LAYER M4 ;
        RECT 531.150 97.817 531.250 97.841 ;
    END
  END kr_data[99]
  PIN kr_data[98]
    DIRECTION INPUT ;
    USE SIGNAL ;
    PORT
      LAYER M4 ;
        RECT 531.150 97.913 531.250 97.937 ;
    END
  END kr_data[98]
  PIN kr_data[97]
    DIRECTION INPUT ;
    USE SIGNAL ;
    PORT
      LAYER M4 ;
        RECT 531.150 98.009 531.250 98.033 ;
    END
  END kr_data[97]
  PIN kr_data[96]
    DIRECTION INPUT ;
    USE SIGNAL ;
    PORT
      LAYER M4 ;
        RECT 531.150 98.105 531.250 98.129 ;
    END
  END kr_data[96]
  PIN kr_data[95]
    DIRECTION INPUT ;
    USE SIGNAL ;
    PORT
      LAYER M4 ;
        RECT 531.150 98.201 531.250 98.225 ;
    END
  END kr_data[95]
  PIN kr_data[94]
    DIRECTION INPUT ;
    USE SIGNAL ;
    PORT
      LAYER M4 ;
        RECT 531.150 98.297 531.250 98.321 ;
    END
  END kr_data[94]
  PIN kr_data[93]
    DIRECTION INPUT ;
    USE SIGNAL ;
    PORT
      LAYER M4 ;
        RECT 531.150 98.393 531.250 98.417 ;
    END
  END kr_data[93]
  PIN kr_data[92]
    DIRECTION INPUT ;
    USE SIGNAL ;
    PORT
      LAYER M4 ;
        RECT 531.150 98.489 531.250 98.513 ;
    END
  END kr_data[92]
  PIN kr_data[91]
    DIRECTION INPUT ;
    USE SIGNAL ;
    PORT
      LAYER M4 ;
        RECT 531.150 98.585 531.250 98.609 ;
    END
  END kr_data[91]
  PIN kr_data[90]
    DIRECTION INPUT ;
    USE SIGNAL ;
    PORT
      LAYER M4 ;
        RECT 531.150 98.681 531.250 98.705 ;
    END
  END kr_data[90]
  PIN kr_data[89]
    DIRECTION INPUT ;
    USE SIGNAL ;
    PORT
      LAYER M4 ;
        RECT 531.150 98.777 531.250 98.801 ;
    END
  END kr_data[89]
  PIN kr_data[88]
    DIRECTION INPUT ;
    USE SIGNAL ;
    PORT
      LAYER M4 ;
        RECT 531.150 98.873 531.250 98.897 ;
    END
  END kr_data[88]
  PIN kr_data[87]
    DIRECTION INPUT ;
    USE SIGNAL ;
    PORT
      LAYER M4 ;
        RECT 531.150 98.969 531.250 98.993 ;
    END
  END kr_data[87]
  PIN kr_data[86]
    DIRECTION INPUT ;
    USE SIGNAL ;
    PORT
      LAYER M4 ;
        RECT 531.150 99.065 531.250 99.089 ;
    END
  END kr_data[86]
  PIN kr_data[85]
    DIRECTION INPUT ;
    USE SIGNAL ;
    PORT
      LAYER M4 ;
        RECT 531.150 99.161 531.250 99.185 ;
    END
  END kr_data[85]
  PIN kr_data[84]
    DIRECTION INPUT ;
    USE SIGNAL ;
    PORT
      LAYER M4 ;
        RECT 531.150 99.257 531.250 99.281 ;
    END
  END kr_data[84]
  PIN kr_data[83]
    DIRECTION INPUT ;
    USE SIGNAL ;
    PORT
      LAYER M4 ;
        RECT 531.150 99.353 531.250 99.377 ;
    END
  END kr_data[83]
  PIN kr_data[82]
    DIRECTION INPUT ;
    USE SIGNAL ;
    PORT
      LAYER M4 ;
        RECT 531.150 99.449 531.250 99.473 ;
    END
  END kr_data[82]
  PIN kr_data[81]
    DIRECTION INPUT ;
    USE SIGNAL ;
    PORT
      LAYER M4 ;
        RECT 531.150 99.545 531.250 99.569 ;
    END
  END kr_data[81]
  PIN kr_data[80]
    DIRECTION INPUT ;
    USE SIGNAL ;
    PORT
      LAYER M4 ;
        RECT 531.150 99.641 531.250 99.665 ;
    END
  END kr_data[80]
  PIN kr_data[79]
    DIRECTION INPUT ;
    USE SIGNAL ;
    PORT
      LAYER M4 ;
        RECT 531.150 99.737 531.250 99.761 ;
    END
  END kr_data[79]
  PIN kr_data[78]
    DIRECTION INPUT ;
    USE SIGNAL ;
    PORT
      LAYER M4 ;
        RECT 531.150 99.833 531.250 99.857 ;
    END
  END kr_data[78]
  PIN kr_data[77]
    DIRECTION INPUT ;
    USE SIGNAL ;
    PORT
      LAYER M4 ;
        RECT 531.150 99.929 531.250 99.953 ;
    END
  END kr_data[77]
  PIN kr_data[76]
    DIRECTION INPUT ;
    USE SIGNAL ;
    PORT
      LAYER M4 ;
        RECT 531.150 100.025 531.250 100.049 ;
    END
  END kr_data[76]
  PIN kr_data[75]
    DIRECTION INPUT ;
    USE SIGNAL ;
    PORT
      LAYER M4 ;
        RECT 531.150 100.121 531.250 100.145 ;
    END
  END kr_data[75]
  PIN kr_data[74]
    DIRECTION INPUT ;
    USE SIGNAL ;
    PORT
      LAYER M4 ;
        RECT 531.150 100.217 531.250 100.241 ;
    END
  END kr_data[74]
  PIN kr_data[73]
    DIRECTION INPUT ;
    USE SIGNAL ;
    PORT
      LAYER M4 ;
        RECT 531.150 100.313 531.250 100.337 ;
    END
  END kr_data[73]
  PIN kr_data[72]
    DIRECTION INPUT ;
    USE SIGNAL ;
    PORT
      LAYER M4 ;
        RECT 531.150 100.409 531.250 100.433 ;
    END
  END kr_data[72]
  PIN kr_data[71]
    DIRECTION INPUT ;
    USE SIGNAL ;
    PORT
      LAYER M4 ;
        RECT 531.150 100.505 531.250 100.529 ;
    END
  END kr_data[71]
  PIN kr_data[70]
    DIRECTION INPUT ;
    USE SIGNAL ;
    PORT
      LAYER M4 ;
        RECT 531.150 100.601 531.250 100.625 ;
    END
  END kr_data[70]
  PIN kr_data[69]
    DIRECTION INPUT ;
    USE SIGNAL ;
    PORT
      LAYER M4 ;
        RECT 531.150 100.697 531.250 100.721 ;
    END
  END kr_data[69]
  PIN kr_data[68]
    DIRECTION INPUT ;
    USE SIGNAL ;
    PORT
      LAYER M4 ;
        RECT 531.150 100.793 531.250 100.817 ;
    END
  END kr_data[68]
  PIN kr_data[67]
    DIRECTION INPUT ;
    USE SIGNAL ;
    PORT
      LAYER M4 ;
        RECT 531.150 100.889 531.250 100.913 ;
    END
  END kr_data[67]
  PIN kr_data[66]
    DIRECTION INPUT ;
    USE SIGNAL ;
    PORT
      LAYER M4 ;
        RECT 531.150 100.985 531.250 101.009 ;
    END
  END kr_data[66]
  PIN kr_data[65]
    DIRECTION INPUT ;
    USE SIGNAL ;
    PORT
      LAYER M4 ;
        RECT 531.150 101.081 531.250 101.105 ;
    END
  END kr_data[65]
  PIN kr_data[64]
    DIRECTION INPUT ;
    USE SIGNAL ;
    PORT
      LAYER M4 ;
        RECT 531.150 101.177 531.250 101.201 ;
    END
  END kr_data[64]
  PIN kr_data[63]
    DIRECTION INPUT ;
    USE SIGNAL ;
    PORT
      LAYER M4 ;
        RECT 531.150 101.273 531.250 101.297 ;
    END
  END kr_data[63]
  PIN kr_data[62]
    DIRECTION INPUT ;
    USE SIGNAL ;
    PORT
      LAYER M4 ;
        RECT 531.150 101.369 531.250 101.393 ;
    END
  END kr_data[62]
  PIN kr_data[61]
    DIRECTION INPUT ;
    USE SIGNAL ;
    PORT
      LAYER M4 ;
        RECT 531.150 101.465 531.250 101.489 ;
    END
  END kr_data[61]
  PIN kr_data[60]
    DIRECTION INPUT ;
    USE SIGNAL ;
    PORT
      LAYER M4 ;
        RECT 531.150 101.561 531.250 101.585 ;
    END
  END kr_data[60]
  PIN kr_data[59]
    DIRECTION INPUT ;
    USE SIGNAL ;
    PORT
      LAYER M4 ;
        RECT 531.150 101.657 531.250 101.681 ;
    END
  END kr_data[59]
  PIN kr_data[58]
    DIRECTION INPUT ;
    USE SIGNAL ;
    PORT
      LAYER M4 ;
        RECT 531.150 101.753 531.250 101.777 ;
    END
  END kr_data[58]
  PIN kr_data[57]
    DIRECTION INPUT ;
    USE SIGNAL ;
    PORT
      LAYER M4 ;
        RECT 531.150 101.849 531.250 101.873 ;
    END
  END kr_data[57]
  PIN kr_data[56]
    DIRECTION INPUT ;
    USE SIGNAL ;
    PORT
      LAYER M4 ;
        RECT 531.150 101.945 531.250 101.969 ;
    END
  END kr_data[56]
  PIN kr_data[55]
    DIRECTION INPUT ;
    USE SIGNAL ;
    PORT
      LAYER M4 ;
        RECT 531.150 102.041 531.250 102.065 ;
    END
  END kr_data[55]
  PIN kr_data[54]
    DIRECTION INPUT ;
    USE SIGNAL ;
    PORT
      LAYER M4 ;
        RECT 531.150 102.137 531.250 102.161 ;
    END
  END kr_data[54]
  PIN kr_data[53]
    DIRECTION INPUT ;
    USE SIGNAL ;
    PORT
      LAYER M4 ;
        RECT 531.150 102.233 531.250 102.257 ;
    END
  END kr_data[53]
  PIN kr_data[52]
    DIRECTION INPUT ;
    USE SIGNAL ;
    PORT
      LAYER M4 ;
        RECT 531.150 102.329 531.250 102.353 ;
    END
  END kr_data[52]
  PIN kr_data[51]
    DIRECTION INPUT ;
    USE SIGNAL ;
    PORT
      LAYER M4 ;
        RECT 531.150 102.425 531.250 102.449 ;
    END
  END kr_data[51]
  PIN kr_data[50]
    DIRECTION INPUT ;
    USE SIGNAL ;
    PORT
      LAYER M4 ;
        RECT 531.150 102.521 531.250 102.545 ;
    END
  END kr_data[50]
  PIN kr_data[49]
    DIRECTION INPUT ;
    USE SIGNAL ;
    PORT
      LAYER M4 ;
        RECT 531.150 102.617 531.250 102.641 ;
    END
  END kr_data[49]
  PIN kr_data[48]
    DIRECTION INPUT ;
    USE SIGNAL ;
    PORT
      LAYER M4 ;
        RECT 531.150 102.713 531.250 102.737 ;
    END
  END kr_data[48]
  PIN kr_data[47]
    DIRECTION INPUT ;
    USE SIGNAL ;
    PORT
      LAYER M4 ;
        RECT 531.150 102.809 531.250 102.833 ;
    END
  END kr_data[47]
  PIN kr_data[46]
    DIRECTION INPUT ;
    USE SIGNAL ;
    PORT
      LAYER M4 ;
        RECT 531.150 102.905 531.250 102.929 ;
    END
  END kr_data[46]
  PIN kr_data[45]
    DIRECTION INPUT ;
    USE SIGNAL ;
    PORT
      LAYER M4 ;
        RECT 531.150 103.001 531.250 103.025 ;
    END
  END kr_data[45]
  PIN kr_data[44]
    DIRECTION INPUT ;
    USE SIGNAL ;
    PORT
      LAYER M4 ;
        RECT 531.150 103.097 531.250 103.121 ;
    END
  END kr_data[44]
  PIN kr_data[43]
    DIRECTION INPUT ;
    USE SIGNAL ;
    PORT
      LAYER M4 ;
        RECT 531.150 103.193 531.250 103.217 ;
    END
  END kr_data[43]
  PIN kr_data[42]
    DIRECTION INPUT ;
    USE SIGNAL ;
    PORT
      LAYER M4 ;
        RECT 531.150 103.289 531.250 103.313 ;
    END
  END kr_data[42]
  PIN kr_data[41]
    DIRECTION INPUT ;
    USE SIGNAL ;
    PORT
      LAYER M4 ;
        RECT 531.150 103.385 531.250 103.409 ;
    END
  END kr_data[41]
  PIN kr_data[40]
    DIRECTION INPUT ;
    USE SIGNAL ;
    PORT
      LAYER M4 ;
        RECT 531.150 103.481 531.250 103.505 ;
    END
  END kr_data[40]
  PIN kr_data[39]
    DIRECTION INPUT ;
    USE SIGNAL ;
    PORT
      LAYER M4 ;
        RECT 531.150 103.577 531.250 103.601 ;
    END
  END kr_data[39]
  PIN kr_data[38]
    DIRECTION INPUT ;
    USE SIGNAL ;
    PORT
      LAYER M4 ;
        RECT 531.150 103.673 531.250 103.697 ;
    END
  END kr_data[38]
  PIN kr_data[37]
    DIRECTION INPUT ;
    USE SIGNAL ;
    PORT
      LAYER M4 ;
        RECT 531.150 103.769 531.250 103.793 ;
    END
  END kr_data[37]
  PIN kr_data[36]
    DIRECTION INPUT ;
    USE SIGNAL ;
    PORT
      LAYER M4 ;
        RECT 531.150 103.865 531.250 103.889 ;
    END
  END kr_data[36]
  PIN kr_data[35]
    DIRECTION INPUT ;
    USE SIGNAL ;
    PORT
      LAYER M4 ;
        RECT 531.150 103.961 531.250 103.985 ;
    END
  END kr_data[35]
  PIN kr_data[34]
    DIRECTION INPUT ;
    USE SIGNAL ;
    PORT
      LAYER M4 ;
        RECT 531.150 104.057 531.250 104.081 ;
    END
  END kr_data[34]
  PIN kr_data[33]
    DIRECTION INPUT ;
    USE SIGNAL ;
    PORT
      LAYER M4 ;
        RECT 531.150 104.153 531.250 104.177 ;
    END
  END kr_data[33]
  PIN kr_data[32]
    DIRECTION INPUT ;
    USE SIGNAL ;
    PORT
      LAYER M4 ;
        RECT 531.150 104.249 531.250 104.273 ;
    END
  END kr_data[32]
  PIN kr_data[31]
    DIRECTION INPUT ;
    USE SIGNAL ;
    PORT
      LAYER M4 ;
        RECT 531.150 104.345 531.250 104.369 ;
    END
  END kr_data[31]
  PIN kr_data[30]
    DIRECTION INPUT ;
    USE SIGNAL ;
    PORT
      LAYER M4 ;
        RECT 531.150 104.441 531.250 104.465 ;
    END
  END kr_data[30]
  PIN kr_data[29]
    DIRECTION INPUT ;
    USE SIGNAL ;
    PORT
      LAYER M4 ;
        RECT 531.150 104.537 531.250 104.561 ;
    END
  END kr_data[29]
  PIN kr_data[28]
    DIRECTION INPUT ;
    USE SIGNAL ;
    PORT
      LAYER M4 ;
        RECT 531.150 104.633 531.250 104.657 ;
    END
  END kr_data[28]
  PIN kr_data[27]
    DIRECTION INPUT ;
    USE SIGNAL ;
    PORT
      LAYER M4 ;
        RECT 531.150 104.729 531.250 104.753 ;
    END
  END kr_data[27]
  PIN kr_data[26]
    DIRECTION INPUT ;
    USE SIGNAL ;
    PORT
      LAYER M4 ;
        RECT 531.150 104.825 531.250 104.849 ;
    END
  END kr_data[26]
  PIN kr_data[25]
    DIRECTION INPUT ;
    USE SIGNAL ;
    PORT
      LAYER M4 ;
        RECT 531.150 104.921 531.250 104.945 ;
    END
  END kr_data[25]
  PIN kr_data[24]
    DIRECTION INPUT ;
    USE SIGNAL ;
    PORT
      LAYER M4 ;
        RECT 531.150 105.017 531.250 105.041 ;
    END
  END kr_data[24]
  PIN kr_data[23]
    DIRECTION INPUT ;
    USE SIGNAL ;
    PORT
      LAYER M4 ;
        RECT 531.150 105.113 531.250 105.137 ;
    END
  END kr_data[23]
  PIN kr_data[22]
    DIRECTION INPUT ;
    USE SIGNAL ;
    PORT
      LAYER M4 ;
        RECT 531.150 105.209 531.250 105.233 ;
    END
  END kr_data[22]
  PIN kr_data[21]
    DIRECTION INPUT ;
    USE SIGNAL ;
    PORT
      LAYER M4 ;
        RECT 531.150 105.305 531.250 105.329 ;
    END
  END kr_data[21]
  PIN kr_data[20]
    DIRECTION INPUT ;
    USE SIGNAL ;
    PORT
      LAYER M4 ;
        RECT 531.150 105.401 531.250 105.425 ;
    END
  END kr_data[20]
  PIN kr_data[19]
    DIRECTION INPUT ;
    USE SIGNAL ;
    PORT
      LAYER M4 ;
        RECT 531.150 105.497 531.250 105.521 ;
    END
  END kr_data[19]
  PIN kr_data[18]
    DIRECTION INPUT ;
    USE SIGNAL ;
    PORT
      LAYER M4 ;
        RECT 531.150 105.593 531.250 105.617 ;
    END
  END kr_data[18]
  PIN kr_data[17]
    DIRECTION INPUT ;
    USE SIGNAL ;
    PORT
      LAYER M4 ;
        RECT 531.150 105.689 531.250 105.713 ;
    END
  END kr_data[17]
  PIN kr_data[16]
    DIRECTION INPUT ;
    USE SIGNAL ;
    PORT
      LAYER M4 ;
        RECT 531.150 105.785 531.250 105.809 ;
    END
  END kr_data[16]
  PIN kr_data[15]
    DIRECTION INPUT ;
    USE SIGNAL ;
    PORT
      LAYER M4 ;
        RECT 531.150 105.881 531.250 105.905 ;
    END
  END kr_data[15]
  PIN kr_data[14]
    DIRECTION INPUT ;
    USE SIGNAL ;
    PORT
      LAYER M4 ;
        RECT 531.150 105.977 531.250 106.001 ;
    END
  END kr_data[14]
  PIN kr_data[13]
    DIRECTION INPUT ;
    USE SIGNAL ;
    PORT
      LAYER M4 ;
        RECT 531.150 106.073 531.250 106.097 ;
    END
  END kr_data[13]
  PIN kr_data[12]
    DIRECTION INPUT ;
    USE SIGNAL ;
    PORT
      LAYER M4 ;
        RECT 531.150 106.169 531.250 106.193 ;
    END
  END kr_data[12]
  PIN kr_data[11]
    DIRECTION INPUT ;
    USE SIGNAL ;
    PORT
      LAYER M4 ;
        RECT 531.150 106.265 531.250 106.289 ;
    END
  END kr_data[11]
  PIN kr_data[10]
    DIRECTION INPUT ;
    USE SIGNAL ;
    PORT
      LAYER M4 ;
        RECT 531.150 106.361 531.250 106.385 ;
    END
  END kr_data[10]
  PIN kr_data[9]
    DIRECTION INPUT ;
    USE SIGNAL ;
    PORT
      LAYER M4 ;
        RECT 531.150 106.457 531.250 106.481 ;
    END
  END kr_data[9]
  PIN kr_data[8]
    DIRECTION INPUT ;
    USE SIGNAL ;
    PORT
      LAYER M4 ;
        RECT 531.150 106.553 531.250 106.577 ;
    END
  END kr_data[8]
  PIN kr_data[7]
    DIRECTION INPUT ;
    USE SIGNAL ;
    PORT
      LAYER M4 ;
        RECT 531.150 106.649 531.250 106.673 ;
    END
  END kr_data[7]
  PIN kr_data[6]
    DIRECTION INPUT ;
    USE SIGNAL ;
    PORT
      LAYER M4 ;
        RECT 531.150 106.745 531.250 106.769 ;
    END
  END kr_data[6]
  PIN kr_data[5]
    DIRECTION INPUT ;
    USE SIGNAL ;
    PORT
      LAYER M4 ;
        RECT 531.150 106.841 531.250 106.865 ;
    END
  END kr_data[5]
  PIN kr_data[4]
    DIRECTION INPUT ;
    USE SIGNAL ;
    PORT
      LAYER M4 ;
        RECT 531.150 106.937 531.250 106.961 ;
    END
  END kr_data[4]
  PIN kr_data[3]
    DIRECTION INPUT ;
    USE SIGNAL ;
    PORT
      LAYER M4 ;
        RECT 531.150 107.033 531.250 107.057 ;
    END
  END kr_data[3]
  PIN kr_data[2]
    DIRECTION INPUT ;
    USE SIGNAL ;
    PORT
      LAYER M4 ;
        RECT 531.150 107.129 531.250 107.153 ;
    END
  END kr_data[2]
  PIN kr_data[1]
    DIRECTION INPUT ;
    USE SIGNAL ;
    PORT
      LAYER M4 ;
        RECT 531.150 107.225 531.250 107.249 ;
    END
  END kr_data[1]
  PIN kr_data[0]
    DIRECTION INPUT ;
    USE SIGNAL ;
    PORT
      LAYER M4 ;
        RECT 531.150 107.321 531.250 107.345 ;
    END
  END kr_data[0]
  PIN rst_n
    DIRECTION INPUT ;
    USE SIGNAL ;
    PORT
      LAYER M5 ;
        RECT 265.613 0.000 265.637 0.100 ;
    END
  END rst_n
  PIN rq[681]
    DIRECTION INPUT ;
    USE SIGNAL ;
    PORT
      LAYER M5 ;
        RECT 268.270 249.900 268.294 250.000 ;
    END
  END rq[681]
  PIN rq[680]
    DIRECTION INPUT ;
    USE SIGNAL ;
    PORT
      LAYER M5 ;
        RECT 268.174 249.900 268.198 250.000 ;
    END
  END rq[680]
  PIN rq[679]
    DIRECTION INPUT ;
    USE SIGNAL ;
    PORT
      LAYER M5 ;
        RECT 268.078 249.900 268.102 250.000 ;
    END
  END rq[679]
  PIN rq[678]
    DIRECTION INPUT ;
    USE SIGNAL ;
    PORT
      LAYER M5 ;
        RECT 267.982 249.900 268.006 250.000 ;
    END
  END rq[678]
  PIN rq[677]
    DIRECTION INPUT ;
    USE SIGNAL ;
    PORT
      LAYER M5 ;
        RECT 267.886 249.900 267.910 250.000 ;
    END
  END rq[677]
  PIN rq[676]
    DIRECTION INPUT ;
    USE SIGNAL ;
    PORT
      LAYER M5 ;
        RECT 267.790 249.900 267.814 250.000 ;
    END
  END rq[676]
  PIN rq[675]
    DIRECTION INPUT ;
    USE SIGNAL ;
    PORT
      LAYER M5 ;
        RECT 267.694 249.900 267.718 250.000 ;
    END
  END rq[675]
  PIN rq[674]
    DIRECTION INPUT ;
    USE SIGNAL ;
    PORT
      LAYER M5 ;
        RECT 267.598 249.900 267.622 250.000 ;
    END
  END rq[674]
  PIN rq[673]
    DIRECTION INPUT ;
    USE SIGNAL ;
    PORT
      LAYER M5 ;
        RECT 267.502 249.900 267.526 250.000 ;
    END
  END rq[673]
  PIN rq[672]
    DIRECTION INPUT ;
    USE SIGNAL ;
    PORT
      LAYER M5 ;
        RECT 267.406 249.900 267.430 250.000 ;
    END
  END rq[672]
  PIN rq[671]
    DIRECTION INPUT ;
    USE SIGNAL ;
    PORT
      LAYER M5 ;
        RECT 267.310 249.900 267.334 250.000 ;
    END
  END rq[671]
  PIN rq[670]
    DIRECTION INPUT ;
    USE SIGNAL ;
    PORT
      LAYER M5 ;
        RECT 267.214 249.900 267.238 250.000 ;
    END
  END rq[670]
  PIN rq[669]
    DIRECTION INPUT ;
    USE SIGNAL ;
    PORT
      LAYER M5 ;
        RECT 267.118 249.900 267.142 250.000 ;
    END
  END rq[669]
  PIN rq[668]
    DIRECTION INPUT ;
    USE SIGNAL ;
    PORT
      LAYER M5 ;
        RECT 267.022 249.900 267.046 250.000 ;
    END
  END rq[668]
  PIN rq[667]
    DIRECTION INPUT ;
    USE SIGNAL ;
    PORT
      LAYER M5 ;
        RECT 266.926 249.900 266.950 250.000 ;
    END
  END rq[667]
  PIN rq[666]
    DIRECTION INPUT ;
    USE SIGNAL ;
    PORT
      LAYER M5 ;
        RECT 266.830 249.900 266.854 250.000 ;
    END
  END rq[666]
  PIN rq[665]
    DIRECTION INPUT ;
    USE SIGNAL ;
    PORT
      LAYER M5 ;
        RECT 266.734 249.900 266.758 250.000 ;
    END
  END rq[665]
  PIN rq[664]
    DIRECTION INPUT ;
    USE SIGNAL ;
    PORT
      LAYER M5 ;
        RECT 266.638 249.900 266.662 250.000 ;
    END
  END rq[664]
  PIN rq[663]
    DIRECTION INPUT ;
    USE SIGNAL ;
    PORT
      LAYER M5 ;
        RECT 266.542 249.900 266.566 250.000 ;
    END
  END rq[663]
  PIN rq[662]
    DIRECTION INPUT ;
    USE SIGNAL ;
    PORT
      LAYER M5 ;
        RECT 266.446 249.900 266.470 250.000 ;
    END
  END rq[662]
  PIN rq[661]
    DIRECTION INPUT ;
    USE SIGNAL ;
    PORT
      LAYER M5 ;
        RECT 266.350 249.900 266.374 250.000 ;
    END
  END rq[661]
  PIN rq[660]
    DIRECTION INPUT ;
    USE SIGNAL ;
    PORT
      LAYER M5 ;
        RECT 266.254 249.900 266.278 250.000 ;
    END
  END rq[660]
  PIN rq[659]
    DIRECTION INPUT ;
    USE SIGNAL ;
    PORT
      LAYER M5 ;
        RECT 266.158 249.900 266.182 250.000 ;
    END
  END rq[659]
  PIN rq[658]
    DIRECTION INPUT ;
    USE SIGNAL ;
    PORT
      LAYER M5 ;
        RECT 266.062 249.900 266.086 250.000 ;
    END
  END rq[658]
  PIN rq[657]
    DIRECTION INPUT ;
    USE SIGNAL ;
    PORT
      LAYER M5 ;
        RECT 265.966 249.900 265.990 250.000 ;
    END
  END rq[657]
  PIN rq[656]
    DIRECTION INPUT ;
    USE SIGNAL ;
    PORT
      LAYER M5 ;
        RECT 265.870 249.900 265.894 250.000 ;
    END
  END rq[656]
  PIN rq[655]
    DIRECTION INPUT ;
    USE SIGNAL ;
    PORT
      LAYER M5 ;
        RECT 265.774 249.900 265.798 250.000 ;
    END
  END rq[655]
  PIN rq[654]
    DIRECTION INPUT ;
    USE SIGNAL ;
    PORT
      LAYER M5 ;
        RECT 265.678 249.900 265.702 250.000 ;
    END
  END rq[654]
  PIN rq[653]
    DIRECTION INPUT ;
    USE SIGNAL ;
    PORT
      LAYER M5 ;
        RECT 265.582 249.900 265.606 250.000 ;
    END
  END rq[653]
  PIN rq[652]
    DIRECTION INPUT ;
    USE SIGNAL ;
    PORT
      LAYER M5 ;
        RECT 265.486 249.900 265.510 250.000 ;
    END
  END rq[652]
  PIN rq[651]
    DIRECTION INPUT ;
    USE SIGNAL ;
    PORT
      LAYER M5 ;
        RECT 265.390 249.900 265.414 250.000 ;
    END
  END rq[651]
  PIN rq[650]
    DIRECTION INPUT ;
    USE SIGNAL ;
    PORT
      LAYER M5 ;
        RECT 265.294 249.900 265.318 250.000 ;
    END
  END rq[650]
  PIN rq[649]
    DIRECTION INPUT ;
    USE SIGNAL ;
    PORT
      LAYER M5 ;
        RECT 265.198 249.900 265.222 250.000 ;
    END
  END rq[649]
  PIN rq[648]
    DIRECTION INPUT ;
    USE SIGNAL ;
    PORT
      LAYER M5 ;
        RECT 265.102 249.900 265.126 250.000 ;
    END
  END rq[648]
  PIN rq[647]
    DIRECTION INPUT ;
    USE SIGNAL ;
    PORT
      LAYER M5 ;
        RECT 265.006 249.900 265.030 250.000 ;
    END
  END rq[647]
  PIN rq[646]
    DIRECTION INPUT ;
    USE SIGNAL ;
    PORT
      LAYER M5 ;
        RECT 264.910 249.900 264.934 250.000 ;
    END
  END rq[646]
  PIN rq[645]
    DIRECTION INPUT ;
    USE SIGNAL ;
    PORT
      LAYER M5 ;
        RECT 264.814 249.900 264.838 250.000 ;
    END
  END rq[645]
  PIN rq[644]
    DIRECTION INPUT ;
    USE SIGNAL ;
    PORT
      LAYER M5 ;
        RECT 264.718 249.900 264.742 250.000 ;
    END
  END rq[644]
  PIN rq[643]
    DIRECTION INPUT ;
    USE SIGNAL ;
    PORT
      LAYER M5 ;
        RECT 264.622 249.900 264.646 250.000 ;
    END
  END rq[643]
  PIN rq[642]
    DIRECTION INPUT ;
    USE SIGNAL ;
    PORT
      LAYER M5 ;
        RECT 264.526 249.900 264.550 250.000 ;
    END
  END rq[642]
  PIN rq[641]
    DIRECTION INPUT ;
    USE SIGNAL ;
    PORT
      LAYER M5 ;
        RECT 264.430 249.900 264.454 250.000 ;
    END
  END rq[641]
  PIN rq[640]
    DIRECTION INPUT ;
    USE SIGNAL ;
    PORT
      LAYER M5 ;
        RECT 264.334 249.900 264.358 250.000 ;
    END
  END rq[640]
  PIN rq[639]
    DIRECTION INPUT ;
    USE SIGNAL ;
    PORT
      LAYER M5 ;
        RECT 264.238 249.900 264.262 250.000 ;
    END
  END rq[639]
  PIN rq[638]
    DIRECTION INPUT ;
    USE SIGNAL ;
    PORT
      LAYER M5 ;
        RECT 264.142 249.900 264.166 250.000 ;
    END
  END rq[638]
  PIN rq[637]
    DIRECTION INPUT ;
    USE SIGNAL ;
    PORT
      LAYER M5 ;
        RECT 264.046 249.900 264.070 250.000 ;
    END
  END rq[637]
  PIN rq[636]
    DIRECTION INPUT ;
    USE SIGNAL ;
    PORT
      LAYER M5 ;
        RECT 263.950 249.900 263.974 250.000 ;
    END
  END rq[636]
  PIN rq[635]
    DIRECTION INPUT ;
    USE SIGNAL ;
    PORT
      LAYER M5 ;
        RECT 263.854 249.900 263.878 250.000 ;
    END
  END rq[635]
  PIN rq[634]
    DIRECTION INPUT ;
    USE SIGNAL ;
    PORT
      LAYER M5 ;
        RECT 263.758 249.900 263.782 250.000 ;
    END
  END rq[634]
  PIN rq[633]
    DIRECTION INPUT ;
    USE SIGNAL ;
    PORT
      LAYER M5 ;
        RECT 263.662 249.900 263.686 250.000 ;
    END
  END rq[633]
  PIN rq[632]
    DIRECTION INPUT ;
    USE SIGNAL ;
    PORT
      LAYER M5 ;
        RECT 263.566 249.900 263.590 250.000 ;
    END
  END rq[632]
  PIN rq[631]
    DIRECTION INPUT ;
    USE SIGNAL ;
    PORT
      LAYER M5 ;
        RECT 263.470 249.900 263.494 250.000 ;
    END
  END rq[631]
  PIN rq[630]
    DIRECTION INPUT ;
    USE SIGNAL ;
    PORT
      LAYER M5 ;
        RECT 263.374 249.900 263.398 250.000 ;
    END
  END rq[630]
  PIN rq[629]
    DIRECTION INPUT ;
    USE SIGNAL ;
    PORT
      LAYER M5 ;
        RECT 263.278 249.900 263.302 250.000 ;
    END
  END rq[629]
  PIN rq[628]
    DIRECTION INPUT ;
    USE SIGNAL ;
    PORT
      LAYER M5 ;
        RECT 263.182 249.900 263.206 250.000 ;
    END
  END rq[628]
  PIN rq[627]
    DIRECTION INPUT ;
    USE SIGNAL ;
    PORT
      LAYER M5 ;
        RECT 263.086 249.900 263.110 250.000 ;
    END
  END rq[627]
  PIN rq[626]
    DIRECTION INPUT ;
    USE SIGNAL ;
    PORT
      LAYER M5 ;
        RECT 262.990 249.900 263.014 250.000 ;
    END
  END rq[626]
  PIN rq[625]
    DIRECTION INPUT ;
    USE SIGNAL ;
    PORT
      LAYER M5 ;
        RECT 262.894 249.900 262.918 250.000 ;
    END
  END rq[625]
  PIN rq[624]
    DIRECTION INPUT ;
    USE SIGNAL ;
    PORT
      LAYER M5 ;
        RECT 262.798 249.900 262.822 250.000 ;
    END
  END rq[624]
  PIN rq[623]
    DIRECTION INPUT ;
    USE SIGNAL ;
    PORT
      LAYER M5 ;
        RECT 262.702 249.900 262.726 250.000 ;
    END
  END rq[623]
  PIN rq[622]
    DIRECTION INPUT ;
    USE SIGNAL ;
    PORT
      LAYER M5 ;
        RECT 262.606 249.900 262.630 250.000 ;
    END
  END rq[622]
  PIN rq[621]
    DIRECTION INPUT ;
    USE SIGNAL ;
    PORT
      LAYER M5 ;
        RECT 262.510 249.900 262.534 250.000 ;
    END
  END rq[621]
  PIN rq[620]
    DIRECTION INPUT ;
    USE SIGNAL ;
    PORT
      LAYER M5 ;
        RECT 262.414 249.900 262.438 250.000 ;
    END
  END rq[620]
  PIN rq[619]
    DIRECTION INPUT ;
    USE SIGNAL ;
    PORT
      LAYER M5 ;
        RECT 262.318 249.900 262.342 250.000 ;
    END
  END rq[619]
  PIN rq[618]
    DIRECTION INPUT ;
    USE SIGNAL ;
    PORT
      LAYER M5 ;
        RECT 262.222 249.900 262.246 250.000 ;
    END
  END rq[618]
  PIN rq[617]
    DIRECTION INPUT ;
    USE SIGNAL ;
    PORT
      LAYER M5 ;
        RECT 262.126 249.900 262.150 250.000 ;
    END
  END rq[617]
  PIN rq[616]
    DIRECTION INPUT ;
    USE SIGNAL ;
    PORT
      LAYER M5 ;
        RECT 262.030 249.900 262.054 250.000 ;
    END
  END rq[616]
  PIN rq[615]
    DIRECTION INPUT ;
    USE SIGNAL ;
    PORT
      LAYER M5 ;
        RECT 261.934 249.900 261.958 250.000 ;
    END
  END rq[615]
  PIN rq[614]
    DIRECTION INPUT ;
    USE SIGNAL ;
    PORT
      LAYER M5 ;
        RECT 261.838 249.900 261.862 250.000 ;
    END
  END rq[614]
  PIN rq[613]
    DIRECTION INPUT ;
    USE SIGNAL ;
    PORT
      LAYER M5 ;
        RECT 261.742 249.900 261.766 250.000 ;
    END
  END rq[613]
  PIN rq[612]
    DIRECTION INPUT ;
    USE SIGNAL ;
    PORT
      LAYER M5 ;
        RECT 261.646 249.900 261.670 250.000 ;
    END
  END rq[612]
  PIN rq[611]
    DIRECTION INPUT ;
    USE SIGNAL ;
    PORT
      LAYER M5 ;
        RECT 261.550 249.900 261.574 250.000 ;
    END
  END rq[611]
  PIN rq[610]
    DIRECTION INPUT ;
    USE SIGNAL ;
    PORT
      LAYER M5 ;
        RECT 261.454 249.900 261.478 250.000 ;
    END
  END rq[610]
  PIN rq[609]
    DIRECTION INPUT ;
    USE SIGNAL ;
    PORT
      LAYER M5 ;
        RECT 261.358 249.900 261.382 250.000 ;
    END
  END rq[609]
  PIN rq[608]
    DIRECTION INPUT ;
    USE SIGNAL ;
    PORT
      LAYER M5 ;
        RECT 261.262 249.900 261.286 250.000 ;
    END
  END rq[608]
  PIN rq[607]
    DIRECTION INPUT ;
    USE SIGNAL ;
    PORT
      LAYER M5 ;
        RECT 261.166 249.900 261.190 250.000 ;
    END
  END rq[607]
  PIN rq[606]
    DIRECTION INPUT ;
    USE SIGNAL ;
    PORT
      LAYER M5 ;
        RECT 261.070 249.900 261.094 250.000 ;
    END
  END rq[606]
  PIN rq[605]
    DIRECTION INPUT ;
    USE SIGNAL ;
    PORT
      LAYER M5 ;
        RECT 260.974 249.900 260.998 250.000 ;
    END
  END rq[605]
  PIN rq[604]
    DIRECTION INPUT ;
    USE SIGNAL ;
    PORT
      LAYER M5 ;
        RECT 260.878 249.900 260.902 250.000 ;
    END
  END rq[604]
  PIN rq[603]
    DIRECTION INPUT ;
    USE SIGNAL ;
    PORT
      LAYER M5 ;
        RECT 260.782 249.900 260.806 250.000 ;
    END
  END rq[603]
  PIN rq[602]
    DIRECTION INPUT ;
    USE SIGNAL ;
    PORT
      LAYER M5 ;
        RECT 260.686 249.900 260.710 250.000 ;
    END
  END rq[602]
  PIN rq[601]
    DIRECTION INPUT ;
    USE SIGNAL ;
    PORT
      LAYER M5 ;
        RECT 260.590 249.900 260.614 250.000 ;
    END
  END rq[601]
  PIN rq[600]
    DIRECTION INPUT ;
    USE SIGNAL ;
    PORT
      LAYER M5 ;
        RECT 260.494 249.900 260.518 250.000 ;
    END
  END rq[600]
  PIN rq[599]
    DIRECTION INPUT ;
    USE SIGNAL ;
    PORT
      LAYER M5 ;
        RECT 260.398 249.900 260.422 250.000 ;
    END
  END rq[599]
  PIN rq[598]
    DIRECTION INPUT ;
    USE SIGNAL ;
    PORT
      LAYER M5 ;
        RECT 260.302 249.900 260.326 250.000 ;
    END
  END rq[598]
  PIN rq[597]
    DIRECTION INPUT ;
    USE SIGNAL ;
    PORT
      LAYER M5 ;
        RECT 260.206 249.900 260.230 250.000 ;
    END
  END rq[597]
  PIN rq[596]
    DIRECTION INPUT ;
    USE SIGNAL ;
    PORT
      LAYER M5 ;
        RECT 260.110 249.900 260.134 250.000 ;
    END
  END rq[596]
  PIN rq[595]
    DIRECTION INPUT ;
    USE SIGNAL ;
    PORT
      LAYER M5 ;
        RECT 260.014 249.900 260.038 250.000 ;
    END
  END rq[595]
  PIN rq[594]
    DIRECTION INPUT ;
    USE SIGNAL ;
    PORT
      LAYER M5 ;
        RECT 259.918 249.900 259.942 250.000 ;
    END
  END rq[594]
  PIN rq[593]
    DIRECTION INPUT ;
    USE SIGNAL ;
    PORT
      LAYER M5 ;
        RECT 259.822 249.900 259.846 250.000 ;
    END
  END rq[593]
  PIN rq[592]
    DIRECTION INPUT ;
    USE SIGNAL ;
    PORT
      LAYER M5 ;
        RECT 259.726 249.900 259.750 250.000 ;
    END
  END rq[592]
  PIN rq[591]
    DIRECTION INPUT ;
    USE SIGNAL ;
    PORT
      LAYER M5 ;
        RECT 259.630 249.900 259.654 250.000 ;
    END
  END rq[591]
  PIN rq[590]
    DIRECTION INPUT ;
    USE SIGNAL ;
    PORT
      LAYER M5 ;
        RECT 259.534 249.900 259.558 250.000 ;
    END
  END rq[590]
  PIN rq[589]
    DIRECTION INPUT ;
    USE SIGNAL ;
    PORT
      LAYER M5 ;
        RECT 259.438 249.900 259.462 250.000 ;
    END
  END rq[589]
  PIN rq[588]
    DIRECTION INPUT ;
    USE SIGNAL ;
    PORT
      LAYER M5 ;
        RECT 259.342 249.900 259.366 250.000 ;
    END
  END rq[588]
  PIN rq[587]
    DIRECTION INPUT ;
    USE SIGNAL ;
    PORT
      LAYER M5 ;
        RECT 259.246 249.900 259.270 250.000 ;
    END
  END rq[587]
  PIN rq[586]
    DIRECTION INPUT ;
    USE SIGNAL ;
    PORT
      LAYER M5 ;
        RECT 259.150 249.900 259.174 250.000 ;
    END
  END rq[586]
  PIN rq[585]
    DIRECTION INPUT ;
    USE SIGNAL ;
    PORT
      LAYER M5 ;
        RECT 259.054 249.900 259.078 250.000 ;
    END
  END rq[585]
  PIN rq[584]
    DIRECTION INPUT ;
    USE SIGNAL ;
    PORT
      LAYER M5 ;
        RECT 258.958 249.900 258.982 250.000 ;
    END
  END rq[584]
  PIN rq[583]
    DIRECTION INPUT ;
    USE SIGNAL ;
    PORT
      LAYER M5 ;
        RECT 258.862 249.900 258.886 250.000 ;
    END
  END rq[583]
  PIN rq[582]
    DIRECTION INPUT ;
    USE SIGNAL ;
    PORT
      LAYER M5 ;
        RECT 258.766 249.900 258.790 250.000 ;
    END
  END rq[582]
  PIN rq[581]
    DIRECTION INPUT ;
    USE SIGNAL ;
    PORT
      LAYER M5 ;
        RECT 258.670 249.900 258.694 250.000 ;
    END
  END rq[581]
  PIN rq[580]
    DIRECTION INPUT ;
    USE SIGNAL ;
    PORT
      LAYER M5 ;
        RECT 258.574 249.900 258.598 250.000 ;
    END
  END rq[580]
  PIN rq[579]
    DIRECTION INPUT ;
    USE SIGNAL ;
    PORT
      LAYER M5 ;
        RECT 258.478 249.900 258.502 250.000 ;
    END
  END rq[579]
  PIN rq[578]
    DIRECTION INPUT ;
    USE SIGNAL ;
    PORT
      LAYER M5 ;
        RECT 258.382 249.900 258.406 250.000 ;
    END
  END rq[578]
  PIN rq[577]
    DIRECTION INPUT ;
    USE SIGNAL ;
    PORT
      LAYER M5 ;
        RECT 258.286 249.900 258.310 250.000 ;
    END
  END rq[577]
  PIN rq[576]
    DIRECTION INPUT ;
    USE SIGNAL ;
    PORT
      LAYER M5 ;
        RECT 258.190 249.900 258.214 250.000 ;
    END
  END rq[576]
  PIN rq[575]
    DIRECTION INPUT ;
    USE SIGNAL ;
    PORT
      LAYER M5 ;
        RECT 258.094 249.900 258.118 250.000 ;
    END
  END rq[575]
  PIN rq[574]
    DIRECTION INPUT ;
    USE SIGNAL ;
    PORT
      LAYER M5 ;
        RECT 257.998 249.900 258.022 250.000 ;
    END
  END rq[574]
  PIN rq[573]
    DIRECTION INPUT ;
    USE SIGNAL ;
    PORT
      LAYER M5 ;
        RECT 257.902 249.900 257.926 250.000 ;
    END
  END rq[573]
  PIN rq[572]
    DIRECTION INPUT ;
    USE SIGNAL ;
    PORT
      LAYER M5 ;
        RECT 257.806 249.900 257.830 250.000 ;
    END
  END rq[572]
  PIN rq[571]
    DIRECTION INPUT ;
    USE SIGNAL ;
    PORT
      LAYER M5 ;
        RECT 257.710 249.900 257.734 250.000 ;
    END
  END rq[571]
  PIN rq[570]
    DIRECTION INPUT ;
    USE SIGNAL ;
    PORT
      LAYER M5 ;
        RECT 257.614 249.900 257.638 250.000 ;
    END
  END rq[570]
  PIN rq[569]
    DIRECTION INPUT ;
    USE SIGNAL ;
    PORT
      LAYER M5 ;
        RECT 257.518 249.900 257.542 250.000 ;
    END
  END rq[569]
  PIN rq[568]
    DIRECTION INPUT ;
    USE SIGNAL ;
    PORT
      LAYER M5 ;
        RECT 257.422 249.900 257.446 250.000 ;
    END
  END rq[568]
  PIN rq[567]
    DIRECTION INPUT ;
    USE SIGNAL ;
    PORT
      LAYER M5 ;
        RECT 257.326 249.900 257.350 250.000 ;
    END
  END rq[567]
  PIN rq[566]
    DIRECTION INPUT ;
    USE SIGNAL ;
    PORT
      LAYER M5 ;
        RECT 257.230 249.900 257.254 250.000 ;
    END
  END rq[566]
  PIN rq[565]
    DIRECTION INPUT ;
    USE SIGNAL ;
    PORT
      LAYER M5 ;
        RECT 257.134 249.900 257.158 250.000 ;
    END
  END rq[565]
  PIN rq[564]
    DIRECTION INPUT ;
    USE SIGNAL ;
    PORT
      LAYER M5 ;
        RECT 257.038 249.900 257.062 250.000 ;
    END
  END rq[564]
  PIN rq[563]
    DIRECTION INPUT ;
    USE SIGNAL ;
    PORT
      LAYER M5 ;
        RECT 256.942 249.900 256.966 250.000 ;
    END
  END rq[563]
  PIN rq[562]
    DIRECTION INPUT ;
    USE SIGNAL ;
    PORT
      LAYER M5 ;
        RECT 256.846 249.900 256.870 250.000 ;
    END
  END rq[562]
  PIN rq[561]
    DIRECTION INPUT ;
    USE SIGNAL ;
    PORT
      LAYER M5 ;
        RECT 256.750 249.900 256.774 250.000 ;
    END
  END rq[561]
  PIN rq[560]
    DIRECTION INPUT ;
    USE SIGNAL ;
    PORT
      LAYER M5 ;
        RECT 256.654 249.900 256.678 250.000 ;
    END
  END rq[560]
  PIN rq[559]
    DIRECTION INPUT ;
    USE SIGNAL ;
    PORT
      LAYER M5 ;
        RECT 256.558 249.900 256.582 250.000 ;
    END
  END rq[559]
  PIN rq[558]
    DIRECTION INPUT ;
    USE SIGNAL ;
    PORT
      LAYER M5 ;
        RECT 256.462 249.900 256.486 250.000 ;
    END
  END rq[558]
  PIN rq[557]
    DIRECTION INPUT ;
    USE SIGNAL ;
    PORT
      LAYER M5 ;
        RECT 256.366 249.900 256.390 250.000 ;
    END
  END rq[557]
  PIN rq[556]
    DIRECTION INPUT ;
    USE SIGNAL ;
    PORT
      LAYER M5 ;
        RECT 256.270 249.900 256.294 250.000 ;
    END
  END rq[556]
  PIN rq[555]
    DIRECTION INPUT ;
    USE SIGNAL ;
    PORT
      LAYER M5 ;
        RECT 256.174 249.900 256.198 250.000 ;
    END
  END rq[555]
  PIN rq[554]
    DIRECTION INPUT ;
    USE SIGNAL ;
    PORT
      LAYER M5 ;
        RECT 256.078 249.900 256.102 250.000 ;
    END
  END rq[554]
  PIN rq[553]
    DIRECTION INPUT ;
    USE SIGNAL ;
    PORT
      LAYER M5 ;
        RECT 255.982 249.900 256.006 250.000 ;
    END
  END rq[553]
  PIN rq[552]
    DIRECTION INPUT ;
    USE SIGNAL ;
    PORT
      LAYER M5 ;
        RECT 255.886 249.900 255.910 250.000 ;
    END
  END rq[552]
  PIN rq[551]
    DIRECTION INPUT ;
    USE SIGNAL ;
    PORT
      LAYER M5 ;
        RECT 255.790 249.900 255.814 250.000 ;
    END
  END rq[551]
  PIN rq[550]
    DIRECTION INPUT ;
    USE SIGNAL ;
    PORT
      LAYER M5 ;
        RECT 255.694 249.900 255.718 250.000 ;
    END
  END rq[550]
  PIN rq[549]
    DIRECTION INPUT ;
    USE SIGNAL ;
    PORT
      LAYER M5 ;
        RECT 255.598 249.900 255.622 250.000 ;
    END
  END rq[549]
  PIN rq[548]
    DIRECTION INPUT ;
    USE SIGNAL ;
    PORT
      LAYER M5 ;
        RECT 255.502 249.900 255.526 250.000 ;
    END
  END rq[548]
  PIN rq[547]
    DIRECTION INPUT ;
    USE SIGNAL ;
    PORT
      LAYER M5 ;
        RECT 255.406 249.900 255.430 250.000 ;
    END
  END rq[547]
  PIN rq[546]
    DIRECTION INPUT ;
    USE SIGNAL ;
    PORT
      LAYER M5 ;
        RECT 255.310 249.900 255.334 250.000 ;
    END
  END rq[546]
  PIN rq[545]
    DIRECTION INPUT ;
    USE SIGNAL ;
    PORT
      LAYER M5 ;
        RECT 255.214 249.900 255.238 250.000 ;
    END
  END rq[545]
  PIN rq[544]
    DIRECTION INPUT ;
    USE SIGNAL ;
    PORT
      LAYER M5 ;
        RECT 255.118 249.900 255.142 250.000 ;
    END
  END rq[544]
  PIN rq[543]
    DIRECTION INPUT ;
    USE SIGNAL ;
    PORT
      LAYER M5 ;
        RECT 255.022 249.900 255.046 250.000 ;
    END
  END rq[543]
  PIN rq[542]
    DIRECTION INPUT ;
    USE SIGNAL ;
    PORT
      LAYER M5 ;
        RECT 254.926 249.900 254.950 250.000 ;
    END
  END rq[542]
  PIN rq[541]
    DIRECTION INPUT ;
    USE SIGNAL ;
    PORT
      LAYER M5 ;
        RECT 254.830 249.900 254.854 250.000 ;
    END
  END rq[541]
  PIN rq[540]
    DIRECTION INPUT ;
    USE SIGNAL ;
    PORT
      LAYER M5 ;
        RECT 254.734 249.900 254.758 250.000 ;
    END
  END rq[540]
  PIN rq[539]
    DIRECTION INPUT ;
    USE SIGNAL ;
    PORT
      LAYER M5 ;
        RECT 254.638 249.900 254.662 250.000 ;
    END
  END rq[539]
  PIN rq[538]
    DIRECTION INPUT ;
    USE SIGNAL ;
    PORT
      LAYER M5 ;
        RECT 254.542 249.900 254.566 250.000 ;
    END
  END rq[538]
  PIN rq[537]
    DIRECTION INPUT ;
    USE SIGNAL ;
    PORT
      LAYER M5 ;
        RECT 254.446 249.900 254.470 250.000 ;
    END
  END rq[537]
  PIN rq[536]
    DIRECTION INPUT ;
    USE SIGNAL ;
    PORT
      LAYER M5 ;
        RECT 254.350 249.900 254.374 250.000 ;
    END
  END rq[536]
  PIN rq[535]
    DIRECTION INPUT ;
    USE SIGNAL ;
    PORT
      LAYER M5 ;
        RECT 254.254 249.900 254.278 250.000 ;
    END
  END rq[535]
  PIN rq[534]
    DIRECTION INPUT ;
    USE SIGNAL ;
    PORT
      LAYER M5 ;
        RECT 254.158 249.900 254.182 250.000 ;
    END
  END rq[534]
  PIN rq[533]
    DIRECTION INPUT ;
    USE SIGNAL ;
    PORT
      LAYER M5 ;
        RECT 254.062 249.900 254.086 250.000 ;
    END
  END rq[533]
  PIN rq[532]
    DIRECTION INPUT ;
    USE SIGNAL ;
    PORT
      LAYER M5 ;
        RECT 253.966 249.900 253.990 250.000 ;
    END
  END rq[532]
  PIN rq[531]
    DIRECTION INPUT ;
    USE SIGNAL ;
    PORT
      LAYER M5 ;
        RECT 253.870 249.900 253.894 250.000 ;
    END
  END rq[531]
  PIN rq[530]
    DIRECTION INPUT ;
    USE SIGNAL ;
    PORT
      LAYER M5 ;
        RECT 253.774 249.900 253.798 250.000 ;
    END
  END rq[530]
  PIN rq[529]
    DIRECTION INPUT ;
    USE SIGNAL ;
    PORT
      LAYER M5 ;
        RECT 253.678 249.900 253.702 250.000 ;
    END
  END rq[529]
  PIN rq[528]
    DIRECTION INPUT ;
    USE SIGNAL ;
    PORT
      LAYER M5 ;
        RECT 253.582 249.900 253.606 250.000 ;
    END
  END rq[528]
  PIN rq[527]
    DIRECTION INPUT ;
    USE SIGNAL ;
    PORT
      LAYER M5 ;
        RECT 253.486 249.900 253.510 250.000 ;
    END
  END rq[527]
  PIN rq[526]
    DIRECTION INPUT ;
    USE SIGNAL ;
    PORT
      LAYER M5 ;
        RECT 253.390 249.900 253.414 250.000 ;
    END
  END rq[526]
  PIN rq[525]
    DIRECTION INPUT ;
    USE SIGNAL ;
    PORT
      LAYER M5 ;
        RECT 253.294 249.900 253.318 250.000 ;
    END
  END rq[525]
  PIN rq[524]
    DIRECTION INPUT ;
    USE SIGNAL ;
    PORT
      LAYER M5 ;
        RECT 253.198 249.900 253.222 250.000 ;
    END
  END rq[524]
  PIN rq[523]
    DIRECTION INPUT ;
    USE SIGNAL ;
    PORT
      LAYER M5 ;
        RECT 253.102 249.900 253.126 250.000 ;
    END
  END rq[523]
  PIN rq[522]
    DIRECTION INPUT ;
    USE SIGNAL ;
    PORT
      LAYER M5 ;
        RECT 253.006 249.900 253.030 250.000 ;
    END
  END rq[522]
  PIN rq[521]
    DIRECTION INPUT ;
    USE SIGNAL ;
    PORT
      LAYER M5 ;
        RECT 252.910 249.900 252.934 250.000 ;
    END
  END rq[521]
  PIN rq[520]
    DIRECTION INPUT ;
    USE SIGNAL ;
    PORT
      LAYER M5 ;
        RECT 252.814 249.900 252.838 250.000 ;
    END
  END rq[520]
  PIN rq[519]
    DIRECTION INPUT ;
    USE SIGNAL ;
    PORT
      LAYER M5 ;
        RECT 252.718 249.900 252.742 250.000 ;
    END
  END rq[519]
  PIN rq[518]
    DIRECTION INPUT ;
    USE SIGNAL ;
    PORT
      LAYER M5 ;
        RECT 252.622 249.900 252.646 250.000 ;
    END
  END rq[518]
  PIN rq[517]
    DIRECTION INPUT ;
    USE SIGNAL ;
    PORT
      LAYER M5 ;
        RECT 252.526 249.900 252.550 250.000 ;
    END
  END rq[517]
  PIN rq[516]
    DIRECTION INPUT ;
    USE SIGNAL ;
    PORT
      LAYER M5 ;
        RECT 252.430 249.900 252.454 250.000 ;
    END
  END rq[516]
  PIN rq[515]
    DIRECTION INPUT ;
    USE SIGNAL ;
    PORT
      LAYER M5 ;
        RECT 252.334 249.900 252.358 250.000 ;
    END
  END rq[515]
  PIN rq[514]
    DIRECTION INPUT ;
    USE SIGNAL ;
    PORT
      LAYER M5 ;
        RECT 252.238 249.900 252.262 250.000 ;
    END
  END rq[514]
  PIN rq[513]
    DIRECTION INPUT ;
    USE SIGNAL ;
    PORT
      LAYER M5 ;
        RECT 252.142 249.900 252.166 250.000 ;
    END
  END rq[513]
  PIN rq[512]
    DIRECTION INPUT ;
    USE SIGNAL ;
    PORT
      LAYER M5 ;
        RECT 252.046 249.900 252.070 250.000 ;
    END
  END rq[512]
  PIN rq[511]
    DIRECTION INPUT ;
    USE SIGNAL ;
    PORT
      LAYER M5 ;
        RECT 251.950 249.900 251.974 250.000 ;
    END
  END rq[511]
  PIN rq[510]
    DIRECTION INPUT ;
    USE SIGNAL ;
    PORT
      LAYER M5 ;
        RECT 251.854 249.900 251.878 250.000 ;
    END
  END rq[510]
  PIN rq[509]
    DIRECTION INPUT ;
    USE SIGNAL ;
    PORT
      LAYER M5 ;
        RECT 251.758 249.900 251.782 250.000 ;
    END
  END rq[509]
  PIN rq[508]
    DIRECTION INPUT ;
    USE SIGNAL ;
    PORT
      LAYER M5 ;
        RECT 251.662 249.900 251.686 250.000 ;
    END
  END rq[508]
  PIN rq[507]
    DIRECTION INPUT ;
    USE SIGNAL ;
    PORT
      LAYER M5 ;
        RECT 251.566 249.900 251.590 250.000 ;
    END
  END rq[507]
  PIN rq[506]
    DIRECTION INPUT ;
    USE SIGNAL ;
    PORT
      LAYER M5 ;
        RECT 251.470 249.900 251.494 250.000 ;
    END
  END rq[506]
  PIN rq[505]
    DIRECTION INPUT ;
    USE SIGNAL ;
    PORT
      LAYER M5 ;
        RECT 251.374 249.900 251.398 250.000 ;
    END
  END rq[505]
  PIN rq[504]
    DIRECTION INPUT ;
    USE SIGNAL ;
    PORT
      LAYER M5 ;
        RECT 251.278 249.900 251.302 250.000 ;
    END
  END rq[504]
  PIN rq[503]
    DIRECTION INPUT ;
    USE SIGNAL ;
    PORT
      LAYER M5 ;
        RECT 251.182 249.900 251.206 250.000 ;
    END
  END rq[503]
  PIN rq[502]
    DIRECTION INPUT ;
    USE SIGNAL ;
    PORT
      LAYER M5 ;
        RECT 251.086 249.900 251.110 250.000 ;
    END
  END rq[502]
  PIN rq[501]
    DIRECTION INPUT ;
    USE SIGNAL ;
    PORT
      LAYER M5 ;
        RECT 250.990 249.900 251.014 250.000 ;
    END
  END rq[501]
  PIN rq[500]
    DIRECTION INPUT ;
    USE SIGNAL ;
    PORT
      LAYER M5 ;
        RECT 250.894 249.900 250.918 250.000 ;
    END
  END rq[500]
  PIN rq[499]
    DIRECTION INPUT ;
    USE SIGNAL ;
    PORT
      LAYER M5 ;
        RECT 250.798 249.900 250.822 250.000 ;
    END
  END rq[499]
  PIN rq[498]
    DIRECTION INPUT ;
    USE SIGNAL ;
    PORT
      LAYER M5 ;
        RECT 250.702 249.900 250.726 250.000 ;
    END
  END rq[498]
  PIN rq[497]
    DIRECTION INPUT ;
    USE SIGNAL ;
    PORT
      LAYER M5 ;
        RECT 250.606 249.900 250.630 250.000 ;
    END
  END rq[497]
  PIN rq[496]
    DIRECTION INPUT ;
    USE SIGNAL ;
    PORT
      LAYER M5 ;
        RECT 250.510 249.900 250.534 250.000 ;
    END
  END rq[496]
  PIN rq[495]
    DIRECTION INPUT ;
    USE SIGNAL ;
    PORT
      LAYER M5 ;
        RECT 250.414 249.900 250.438 250.000 ;
    END
  END rq[495]
  PIN rq[494]
    DIRECTION INPUT ;
    USE SIGNAL ;
    PORT
      LAYER M5 ;
        RECT 250.318 249.900 250.342 250.000 ;
    END
  END rq[494]
  PIN rq[493]
    DIRECTION INPUT ;
    USE SIGNAL ;
    PORT
      LAYER M5 ;
        RECT 250.222 249.900 250.246 250.000 ;
    END
  END rq[493]
  PIN rq[492]
    DIRECTION INPUT ;
    USE SIGNAL ;
    PORT
      LAYER M5 ;
        RECT 250.126 249.900 250.150 250.000 ;
    END
  END rq[492]
  PIN rq[491]
    DIRECTION INPUT ;
    USE SIGNAL ;
    PORT
      LAYER M5 ;
        RECT 250.030 249.900 250.054 250.000 ;
    END
  END rq[491]
  PIN rq[490]
    DIRECTION INPUT ;
    USE SIGNAL ;
    PORT
      LAYER M5 ;
        RECT 249.934 249.900 249.958 250.000 ;
    END
  END rq[490]
  PIN rq[489]
    DIRECTION INPUT ;
    USE SIGNAL ;
    PORT
      LAYER M5 ;
        RECT 249.838 249.900 249.862 250.000 ;
    END
  END rq[489]
  PIN rq[488]
    DIRECTION INPUT ;
    USE SIGNAL ;
    PORT
      LAYER M5 ;
        RECT 249.742 249.900 249.766 250.000 ;
    END
  END rq[488]
  PIN rq[487]
    DIRECTION INPUT ;
    USE SIGNAL ;
    PORT
      LAYER M5 ;
        RECT 249.646 249.900 249.670 250.000 ;
    END
  END rq[487]
  PIN rq[486]
    DIRECTION INPUT ;
    USE SIGNAL ;
    PORT
      LAYER M5 ;
        RECT 249.550 249.900 249.574 250.000 ;
    END
  END rq[486]
  PIN rq[485]
    DIRECTION INPUT ;
    USE SIGNAL ;
    PORT
      LAYER M5 ;
        RECT 249.454 249.900 249.478 250.000 ;
    END
  END rq[485]
  PIN rq[484]
    DIRECTION INPUT ;
    USE SIGNAL ;
    PORT
      LAYER M5 ;
        RECT 249.358 249.900 249.382 250.000 ;
    END
  END rq[484]
  PIN rq[483]
    DIRECTION INPUT ;
    USE SIGNAL ;
    PORT
      LAYER M5 ;
        RECT 249.262 249.900 249.286 250.000 ;
    END
  END rq[483]
  PIN rq[482]
    DIRECTION INPUT ;
    USE SIGNAL ;
    PORT
      LAYER M5 ;
        RECT 249.166 249.900 249.190 250.000 ;
    END
  END rq[482]
  PIN rq[481]
    DIRECTION INPUT ;
    USE SIGNAL ;
    PORT
      LAYER M5 ;
        RECT 249.070 249.900 249.094 250.000 ;
    END
  END rq[481]
  PIN rq[480]
    DIRECTION INPUT ;
    USE SIGNAL ;
    PORT
      LAYER M5 ;
        RECT 248.974 249.900 248.998 250.000 ;
    END
  END rq[480]
  PIN rq[479]
    DIRECTION INPUT ;
    USE SIGNAL ;
    PORT
      LAYER M5 ;
        RECT 248.878 249.900 248.902 250.000 ;
    END
  END rq[479]
  PIN rq[478]
    DIRECTION INPUT ;
    USE SIGNAL ;
    PORT
      LAYER M5 ;
        RECT 248.782 249.900 248.806 250.000 ;
    END
  END rq[478]
  PIN rq[477]
    DIRECTION INPUT ;
    USE SIGNAL ;
    PORT
      LAYER M5 ;
        RECT 248.686 249.900 248.710 250.000 ;
    END
  END rq[477]
  PIN rq[476]
    DIRECTION INPUT ;
    USE SIGNAL ;
    PORT
      LAYER M5 ;
        RECT 248.590 249.900 248.614 250.000 ;
    END
  END rq[476]
  PIN rq[475]
    DIRECTION INPUT ;
    USE SIGNAL ;
    PORT
      LAYER M5 ;
        RECT 248.494 249.900 248.518 250.000 ;
    END
  END rq[475]
  PIN rq[474]
    DIRECTION INPUT ;
    USE SIGNAL ;
    PORT
      LAYER M5 ;
        RECT 248.398 249.900 248.422 250.000 ;
    END
  END rq[474]
  PIN rq[473]
    DIRECTION INPUT ;
    USE SIGNAL ;
    PORT
      LAYER M5 ;
        RECT 248.302 249.900 248.326 250.000 ;
    END
  END rq[473]
  PIN rq[472]
    DIRECTION INPUT ;
    USE SIGNAL ;
    PORT
      LAYER M5 ;
        RECT 248.206 249.900 248.230 250.000 ;
    END
  END rq[472]
  PIN rq[471]
    DIRECTION INPUT ;
    USE SIGNAL ;
    PORT
      LAYER M5 ;
        RECT 248.110 249.900 248.134 250.000 ;
    END
  END rq[471]
  PIN rq[470]
    DIRECTION INPUT ;
    USE SIGNAL ;
    PORT
      LAYER M5 ;
        RECT 248.014 249.900 248.038 250.000 ;
    END
  END rq[470]
  PIN rq[469]
    DIRECTION INPUT ;
    USE SIGNAL ;
    PORT
      LAYER M5 ;
        RECT 247.918 249.900 247.942 250.000 ;
    END
  END rq[469]
  PIN rq[468]
    DIRECTION INPUT ;
    USE SIGNAL ;
    PORT
      LAYER M5 ;
        RECT 247.822 249.900 247.846 250.000 ;
    END
  END rq[468]
  PIN rq[467]
    DIRECTION INPUT ;
    USE SIGNAL ;
    PORT
      LAYER M5 ;
        RECT 247.726 249.900 247.750 250.000 ;
    END
  END rq[467]
  PIN rq[466]
    DIRECTION INPUT ;
    USE SIGNAL ;
    PORT
      LAYER M5 ;
        RECT 247.630 249.900 247.654 250.000 ;
    END
  END rq[466]
  PIN rq[465]
    DIRECTION INPUT ;
    USE SIGNAL ;
    PORT
      LAYER M5 ;
        RECT 247.534 249.900 247.558 250.000 ;
    END
  END rq[465]
  PIN rq[464]
    DIRECTION INPUT ;
    USE SIGNAL ;
    PORT
      LAYER M5 ;
        RECT 247.438 249.900 247.462 250.000 ;
    END
  END rq[464]
  PIN rq[463]
    DIRECTION INPUT ;
    USE SIGNAL ;
    PORT
      LAYER M5 ;
        RECT 247.342 249.900 247.366 250.000 ;
    END
  END rq[463]
  PIN rq[462]
    DIRECTION INPUT ;
    USE SIGNAL ;
    PORT
      LAYER M5 ;
        RECT 247.246 249.900 247.270 250.000 ;
    END
  END rq[462]
  PIN rq[461]
    DIRECTION INPUT ;
    USE SIGNAL ;
    PORT
      LAYER M5 ;
        RECT 247.150 249.900 247.174 250.000 ;
    END
  END rq[461]
  PIN rq[460]
    DIRECTION INPUT ;
    USE SIGNAL ;
    PORT
      LAYER M5 ;
        RECT 247.054 249.900 247.078 250.000 ;
    END
  END rq[460]
  PIN rq[459]
    DIRECTION INPUT ;
    USE SIGNAL ;
    PORT
      LAYER M5 ;
        RECT 246.958 249.900 246.982 250.000 ;
    END
  END rq[459]
  PIN rq[458]
    DIRECTION INPUT ;
    USE SIGNAL ;
    PORT
      LAYER M5 ;
        RECT 246.862 249.900 246.886 250.000 ;
    END
  END rq[458]
  PIN rq[457]
    DIRECTION INPUT ;
    USE SIGNAL ;
    PORT
      LAYER M5 ;
        RECT 246.766 249.900 246.790 250.000 ;
    END
  END rq[457]
  PIN rq[456]
    DIRECTION INPUT ;
    USE SIGNAL ;
    PORT
      LAYER M5 ;
        RECT 246.670 249.900 246.694 250.000 ;
    END
  END rq[456]
  PIN rq[455]
    DIRECTION INPUT ;
    USE SIGNAL ;
    PORT
      LAYER M5 ;
        RECT 246.574 249.900 246.598 250.000 ;
    END
  END rq[455]
  PIN rq[454]
    DIRECTION INPUT ;
    USE SIGNAL ;
    PORT
      LAYER M5 ;
        RECT 246.478 249.900 246.502 250.000 ;
    END
  END rq[454]
  PIN rq[453]
    DIRECTION INPUT ;
    USE SIGNAL ;
    PORT
      LAYER M5 ;
        RECT 246.382 249.900 246.406 250.000 ;
    END
  END rq[453]
  PIN rq[452]
    DIRECTION INPUT ;
    USE SIGNAL ;
    PORT
      LAYER M5 ;
        RECT 246.286 249.900 246.310 250.000 ;
    END
  END rq[452]
  PIN rq[451]
    DIRECTION INPUT ;
    USE SIGNAL ;
    PORT
      LAYER M5 ;
        RECT 246.190 249.900 246.214 250.000 ;
    END
  END rq[451]
  PIN rq[450]
    DIRECTION INPUT ;
    USE SIGNAL ;
    PORT
      LAYER M5 ;
        RECT 246.094 249.900 246.118 250.000 ;
    END
  END rq[450]
  PIN rq[449]
    DIRECTION INPUT ;
    USE SIGNAL ;
    PORT
      LAYER M5 ;
        RECT 245.998 249.900 246.022 250.000 ;
    END
  END rq[449]
  PIN rq[448]
    DIRECTION INPUT ;
    USE SIGNAL ;
    PORT
      LAYER M5 ;
        RECT 245.902 249.900 245.926 250.000 ;
    END
  END rq[448]
  PIN rq[447]
    DIRECTION INPUT ;
    USE SIGNAL ;
    PORT
      LAYER M5 ;
        RECT 245.806 249.900 245.830 250.000 ;
    END
  END rq[447]
  PIN rq[446]
    DIRECTION INPUT ;
    USE SIGNAL ;
    PORT
      LAYER M5 ;
        RECT 245.710 249.900 245.734 250.000 ;
    END
  END rq[446]
  PIN rq[445]
    DIRECTION INPUT ;
    USE SIGNAL ;
    PORT
      LAYER M5 ;
        RECT 245.614 249.900 245.638 250.000 ;
    END
  END rq[445]
  PIN rq[444]
    DIRECTION INPUT ;
    USE SIGNAL ;
    PORT
      LAYER M5 ;
        RECT 245.518 249.900 245.542 250.000 ;
    END
  END rq[444]
  PIN rq[443]
    DIRECTION INPUT ;
    USE SIGNAL ;
    PORT
      LAYER M5 ;
        RECT 245.422 249.900 245.446 250.000 ;
    END
  END rq[443]
  PIN rq[442]
    DIRECTION INPUT ;
    USE SIGNAL ;
    PORT
      LAYER M5 ;
        RECT 245.326 249.900 245.350 250.000 ;
    END
  END rq[442]
  PIN rq[441]
    DIRECTION INPUT ;
    USE SIGNAL ;
    PORT
      LAYER M5 ;
        RECT 245.230 249.900 245.254 250.000 ;
    END
  END rq[441]
  PIN rq[440]
    DIRECTION INPUT ;
    USE SIGNAL ;
    PORT
      LAYER M5 ;
        RECT 245.134 249.900 245.158 250.000 ;
    END
  END rq[440]
  PIN rq[439]
    DIRECTION INPUT ;
    USE SIGNAL ;
    PORT
      LAYER M5 ;
        RECT 245.038 249.900 245.062 250.000 ;
    END
  END rq[439]
  PIN rq[438]
    DIRECTION INPUT ;
    USE SIGNAL ;
    PORT
      LAYER M5 ;
        RECT 244.942 249.900 244.966 250.000 ;
    END
  END rq[438]
  PIN rq[437]
    DIRECTION INPUT ;
    USE SIGNAL ;
    PORT
      LAYER M5 ;
        RECT 244.846 249.900 244.870 250.000 ;
    END
  END rq[437]
  PIN rq[436]
    DIRECTION INPUT ;
    USE SIGNAL ;
    PORT
      LAYER M5 ;
        RECT 244.750 249.900 244.774 250.000 ;
    END
  END rq[436]
  PIN rq[435]
    DIRECTION INPUT ;
    USE SIGNAL ;
    PORT
      LAYER M5 ;
        RECT 244.654 249.900 244.678 250.000 ;
    END
  END rq[435]
  PIN rq[434]
    DIRECTION INPUT ;
    USE SIGNAL ;
    PORT
      LAYER M5 ;
        RECT 244.558 249.900 244.582 250.000 ;
    END
  END rq[434]
  PIN rq[433]
    DIRECTION INPUT ;
    USE SIGNAL ;
    PORT
      LAYER M5 ;
        RECT 244.462 249.900 244.486 250.000 ;
    END
  END rq[433]
  PIN rq[432]
    DIRECTION INPUT ;
    USE SIGNAL ;
    PORT
      LAYER M5 ;
        RECT 244.366 249.900 244.390 250.000 ;
    END
  END rq[432]
  PIN rq[431]
    DIRECTION INPUT ;
    USE SIGNAL ;
    PORT
      LAYER M5 ;
        RECT 244.270 249.900 244.294 250.000 ;
    END
  END rq[431]
  PIN rq[430]
    DIRECTION INPUT ;
    USE SIGNAL ;
    PORT
      LAYER M5 ;
        RECT 244.174 249.900 244.198 250.000 ;
    END
  END rq[430]
  PIN rq[429]
    DIRECTION INPUT ;
    USE SIGNAL ;
    PORT
      LAYER M5 ;
        RECT 244.078 249.900 244.102 250.000 ;
    END
  END rq[429]
  PIN rq[428]
    DIRECTION INPUT ;
    USE SIGNAL ;
    PORT
      LAYER M5 ;
        RECT 243.982 249.900 244.006 250.000 ;
    END
  END rq[428]
  PIN rq[427]
    DIRECTION INPUT ;
    USE SIGNAL ;
    PORT
      LAYER M5 ;
        RECT 243.886 249.900 243.910 250.000 ;
    END
  END rq[427]
  PIN rq[426]
    DIRECTION INPUT ;
    USE SIGNAL ;
    PORT
      LAYER M5 ;
        RECT 243.790 249.900 243.814 250.000 ;
    END
  END rq[426]
  PIN rq[425]
    DIRECTION INPUT ;
    USE SIGNAL ;
    PORT
      LAYER M5 ;
        RECT 243.694 249.900 243.718 250.000 ;
    END
  END rq[425]
  PIN rq[424]
    DIRECTION INPUT ;
    USE SIGNAL ;
    PORT
      LAYER M5 ;
        RECT 243.598 249.900 243.622 250.000 ;
    END
  END rq[424]
  PIN rq[423]
    DIRECTION INPUT ;
    USE SIGNAL ;
    PORT
      LAYER M5 ;
        RECT 243.502 249.900 243.526 250.000 ;
    END
  END rq[423]
  PIN rq[422]
    DIRECTION INPUT ;
    USE SIGNAL ;
    PORT
      LAYER M5 ;
        RECT 243.406 249.900 243.430 250.000 ;
    END
  END rq[422]
  PIN rq[421]
    DIRECTION INPUT ;
    USE SIGNAL ;
    PORT
      LAYER M5 ;
        RECT 243.310 249.900 243.334 250.000 ;
    END
  END rq[421]
  PIN rq[420]
    DIRECTION INPUT ;
    USE SIGNAL ;
    PORT
      LAYER M5 ;
        RECT 243.214 249.900 243.238 250.000 ;
    END
  END rq[420]
  PIN rq[419]
    DIRECTION INPUT ;
    USE SIGNAL ;
    PORT
      LAYER M5 ;
        RECT 243.118 249.900 243.142 250.000 ;
    END
  END rq[419]
  PIN rq[418]
    DIRECTION INPUT ;
    USE SIGNAL ;
    PORT
      LAYER M5 ;
        RECT 243.022 249.900 243.046 250.000 ;
    END
  END rq[418]
  PIN rq[417]
    DIRECTION INPUT ;
    USE SIGNAL ;
    PORT
      LAYER M5 ;
        RECT 242.926 249.900 242.950 250.000 ;
    END
  END rq[417]
  PIN rq[416]
    DIRECTION INPUT ;
    USE SIGNAL ;
    PORT
      LAYER M5 ;
        RECT 242.830 249.900 242.854 250.000 ;
    END
  END rq[416]
  PIN rq[415]
    DIRECTION INPUT ;
    USE SIGNAL ;
    PORT
      LAYER M5 ;
        RECT 242.734 249.900 242.758 250.000 ;
    END
  END rq[415]
  PIN rq[414]
    DIRECTION INPUT ;
    USE SIGNAL ;
    PORT
      LAYER M5 ;
        RECT 242.638 249.900 242.662 250.000 ;
    END
  END rq[414]
  PIN rq[413]
    DIRECTION INPUT ;
    USE SIGNAL ;
    PORT
      LAYER M5 ;
        RECT 242.542 249.900 242.566 250.000 ;
    END
  END rq[413]
  PIN rq[412]
    DIRECTION INPUT ;
    USE SIGNAL ;
    PORT
      LAYER M5 ;
        RECT 242.446 249.900 242.470 250.000 ;
    END
  END rq[412]
  PIN rq[411]
    DIRECTION INPUT ;
    USE SIGNAL ;
    PORT
      LAYER M5 ;
        RECT 242.350 249.900 242.374 250.000 ;
    END
  END rq[411]
  PIN rq[410]
    DIRECTION INPUT ;
    USE SIGNAL ;
    PORT
      LAYER M5 ;
        RECT 242.254 249.900 242.278 250.000 ;
    END
  END rq[410]
  PIN rq[409]
    DIRECTION INPUT ;
    USE SIGNAL ;
    PORT
      LAYER M5 ;
        RECT 242.158 249.900 242.182 250.000 ;
    END
  END rq[409]
  PIN rq[408]
    DIRECTION INPUT ;
    USE SIGNAL ;
    PORT
      LAYER M5 ;
        RECT 242.062 249.900 242.086 250.000 ;
    END
  END rq[408]
  PIN rq[407]
    DIRECTION INPUT ;
    USE SIGNAL ;
    PORT
      LAYER M5 ;
        RECT 241.966 249.900 241.990 250.000 ;
    END
  END rq[407]
  PIN rq[406]
    DIRECTION INPUT ;
    USE SIGNAL ;
    PORT
      LAYER M5 ;
        RECT 241.870 249.900 241.894 250.000 ;
    END
  END rq[406]
  PIN rq[405]
    DIRECTION INPUT ;
    USE SIGNAL ;
    PORT
      LAYER M5 ;
        RECT 241.774 249.900 241.798 250.000 ;
    END
  END rq[405]
  PIN rq[404]
    DIRECTION INPUT ;
    USE SIGNAL ;
    PORT
      LAYER M5 ;
        RECT 241.678 249.900 241.702 250.000 ;
    END
  END rq[404]
  PIN rq[403]
    DIRECTION INPUT ;
    USE SIGNAL ;
    PORT
      LAYER M5 ;
        RECT 241.582 249.900 241.606 250.000 ;
    END
  END rq[403]
  PIN rq[402]
    DIRECTION INPUT ;
    USE SIGNAL ;
    PORT
      LAYER M5 ;
        RECT 241.486 249.900 241.510 250.000 ;
    END
  END rq[402]
  PIN rq[401]
    DIRECTION INPUT ;
    USE SIGNAL ;
    PORT
      LAYER M5 ;
        RECT 241.390 249.900 241.414 250.000 ;
    END
  END rq[401]
  PIN rq[400]
    DIRECTION INPUT ;
    USE SIGNAL ;
    PORT
      LAYER M5 ;
        RECT 241.294 249.900 241.318 250.000 ;
    END
  END rq[400]
  PIN rq[399]
    DIRECTION INPUT ;
    USE SIGNAL ;
    PORT
      LAYER M5 ;
        RECT 241.198 249.900 241.222 250.000 ;
    END
  END rq[399]
  PIN rq[398]
    DIRECTION INPUT ;
    USE SIGNAL ;
    PORT
      LAYER M5 ;
        RECT 241.102 249.900 241.126 250.000 ;
    END
  END rq[398]
  PIN rq[397]
    DIRECTION INPUT ;
    USE SIGNAL ;
    PORT
      LAYER M5 ;
        RECT 241.006 249.900 241.030 250.000 ;
    END
  END rq[397]
  PIN rq[396]
    DIRECTION INPUT ;
    USE SIGNAL ;
    PORT
      LAYER M5 ;
        RECT 240.910 249.900 240.934 250.000 ;
    END
  END rq[396]
  PIN rq[395]
    DIRECTION INPUT ;
    USE SIGNAL ;
    PORT
      LAYER M5 ;
        RECT 240.814 249.900 240.838 250.000 ;
    END
  END rq[395]
  PIN rq[394]
    DIRECTION INPUT ;
    USE SIGNAL ;
    PORT
      LAYER M5 ;
        RECT 240.718 249.900 240.742 250.000 ;
    END
  END rq[394]
  PIN rq[393]
    DIRECTION INPUT ;
    USE SIGNAL ;
    PORT
      LAYER M5 ;
        RECT 240.622 249.900 240.646 250.000 ;
    END
  END rq[393]
  PIN rq[392]
    DIRECTION INPUT ;
    USE SIGNAL ;
    PORT
      LAYER M5 ;
        RECT 240.526 249.900 240.550 250.000 ;
    END
  END rq[392]
  PIN rq[391]
    DIRECTION INPUT ;
    USE SIGNAL ;
    PORT
      LAYER M5 ;
        RECT 240.430 249.900 240.454 250.000 ;
    END
  END rq[391]
  PIN rq[390]
    DIRECTION INPUT ;
    USE SIGNAL ;
    PORT
      LAYER M5 ;
        RECT 240.334 249.900 240.358 250.000 ;
    END
  END rq[390]
  PIN rq[389]
    DIRECTION INPUT ;
    USE SIGNAL ;
    PORT
      LAYER M5 ;
        RECT 240.238 249.900 240.262 250.000 ;
    END
  END rq[389]
  PIN rq[388]
    DIRECTION INPUT ;
    USE SIGNAL ;
    PORT
      LAYER M5 ;
        RECT 240.142 249.900 240.166 250.000 ;
    END
  END rq[388]
  PIN rq[387]
    DIRECTION INPUT ;
    USE SIGNAL ;
    PORT
      LAYER M5 ;
        RECT 240.046 249.900 240.070 250.000 ;
    END
  END rq[387]
  PIN rq[386]
    DIRECTION INPUT ;
    USE SIGNAL ;
    PORT
      LAYER M5 ;
        RECT 239.950 249.900 239.974 250.000 ;
    END
  END rq[386]
  PIN rq[385]
    DIRECTION INPUT ;
    USE SIGNAL ;
    PORT
      LAYER M5 ;
        RECT 239.854 249.900 239.878 250.000 ;
    END
  END rq[385]
  PIN rq[384]
    DIRECTION INPUT ;
    USE SIGNAL ;
    PORT
      LAYER M5 ;
        RECT 239.758 249.900 239.782 250.000 ;
    END
  END rq[384]
  PIN rq[383]
    DIRECTION INPUT ;
    USE SIGNAL ;
    PORT
      LAYER M5 ;
        RECT 239.662 249.900 239.686 250.000 ;
    END
  END rq[383]
  PIN rq[382]
    DIRECTION INPUT ;
    USE SIGNAL ;
    PORT
      LAYER M5 ;
        RECT 239.566 249.900 239.590 250.000 ;
    END
  END rq[382]
  PIN rq[381]
    DIRECTION INPUT ;
    USE SIGNAL ;
    PORT
      LAYER M5 ;
        RECT 239.470 249.900 239.494 250.000 ;
    END
  END rq[381]
  PIN rq[380]
    DIRECTION INPUT ;
    USE SIGNAL ;
    PORT
      LAYER M5 ;
        RECT 239.374 249.900 239.398 250.000 ;
    END
  END rq[380]
  PIN rq[379]
    DIRECTION INPUT ;
    USE SIGNAL ;
    PORT
      LAYER M5 ;
        RECT 239.278 249.900 239.302 250.000 ;
    END
  END rq[379]
  PIN rq[378]
    DIRECTION INPUT ;
    USE SIGNAL ;
    PORT
      LAYER M5 ;
        RECT 239.182 249.900 239.206 250.000 ;
    END
  END rq[378]
  PIN rq[377]
    DIRECTION INPUT ;
    USE SIGNAL ;
    PORT
      LAYER M5 ;
        RECT 239.086 249.900 239.110 250.000 ;
    END
  END rq[377]
  PIN rq[376]
    DIRECTION INPUT ;
    USE SIGNAL ;
    PORT
      LAYER M5 ;
        RECT 238.990 249.900 239.014 250.000 ;
    END
  END rq[376]
  PIN rq[375]
    DIRECTION INPUT ;
    USE SIGNAL ;
    PORT
      LAYER M5 ;
        RECT 238.894 249.900 238.918 250.000 ;
    END
  END rq[375]
  PIN rq[374]
    DIRECTION INPUT ;
    USE SIGNAL ;
    PORT
      LAYER M5 ;
        RECT 238.798 249.900 238.822 250.000 ;
    END
  END rq[374]
  PIN rq[373]
    DIRECTION INPUT ;
    USE SIGNAL ;
    PORT
      LAYER M5 ;
        RECT 238.702 249.900 238.726 250.000 ;
    END
  END rq[373]
  PIN rq[372]
    DIRECTION INPUT ;
    USE SIGNAL ;
    PORT
      LAYER M5 ;
        RECT 238.606 249.900 238.630 250.000 ;
    END
  END rq[372]
  PIN rq[371]
    DIRECTION INPUT ;
    USE SIGNAL ;
    PORT
      LAYER M5 ;
        RECT 238.510 249.900 238.534 250.000 ;
    END
  END rq[371]
  PIN rq[370]
    DIRECTION INPUT ;
    USE SIGNAL ;
    PORT
      LAYER M5 ;
        RECT 238.414 249.900 238.438 250.000 ;
    END
  END rq[370]
  PIN rq[369]
    DIRECTION INPUT ;
    USE SIGNAL ;
    PORT
      LAYER M5 ;
        RECT 238.318 249.900 238.342 250.000 ;
    END
  END rq[369]
  PIN rq[368]
    DIRECTION INPUT ;
    USE SIGNAL ;
    PORT
      LAYER M5 ;
        RECT 238.222 249.900 238.246 250.000 ;
    END
  END rq[368]
  PIN rq[367]
    DIRECTION INPUT ;
    USE SIGNAL ;
    PORT
      LAYER M5 ;
        RECT 238.126 249.900 238.150 250.000 ;
    END
  END rq[367]
  PIN rq[366]
    DIRECTION INPUT ;
    USE SIGNAL ;
    PORT
      LAYER M5 ;
        RECT 238.030 249.900 238.054 250.000 ;
    END
  END rq[366]
  PIN rq[365]
    DIRECTION INPUT ;
    USE SIGNAL ;
    PORT
      LAYER M5 ;
        RECT 237.934 249.900 237.958 250.000 ;
    END
  END rq[365]
  PIN rq[364]
    DIRECTION INPUT ;
    USE SIGNAL ;
    PORT
      LAYER M5 ;
        RECT 237.838 249.900 237.862 250.000 ;
    END
  END rq[364]
  PIN rq[363]
    DIRECTION INPUT ;
    USE SIGNAL ;
    PORT
      LAYER M5 ;
        RECT 237.742 249.900 237.766 250.000 ;
    END
  END rq[363]
  PIN rq[362]
    DIRECTION INPUT ;
    USE SIGNAL ;
    PORT
      LAYER M5 ;
        RECT 237.646 249.900 237.670 250.000 ;
    END
  END rq[362]
  PIN rq[361]
    DIRECTION INPUT ;
    USE SIGNAL ;
    PORT
      LAYER M5 ;
        RECT 237.550 249.900 237.574 250.000 ;
    END
  END rq[361]
  PIN rq[360]
    DIRECTION INPUT ;
    USE SIGNAL ;
    PORT
      LAYER M5 ;
        RECT 237.454 249.900 237.478 250.000 ;
    END
  END rq[360]
  PIN rq[359]
    DIRECTION INPUT ;
    USE SIGNAL ;
    PORT
      LAYER M5 ;
        RECT 237.358 249.900 237.382 250.000 ;
    END
  END rq[359]
  PIN rq[358]
    DIRECTION INPUT ;
    USE SIGNAL ;
    PORT
      LAYER M5 ;
        RECT 237.262 249.900 237.286 250.000 ;
    END
  END rq[358]
  PIN rq[357]
    DIRECTION INPUT ;
    USE SIGNAL ;
    PORT
      LAYER M5 ;
        RECT 237.166 249.900 237.190 250.000 ;
    END
  END rq[357]
  PIN rq[356]
    DIRECTION INPUT ;
    USE SIGNAL ;
    PORT
      LAYER M5 ;
        RECT 237.070 249.900 237.094 250.000 ;
    END
  END rq[356]
  PIN rq[355]
    DIRECTION INPUT ;
    USE SIGNAL ;
    PORT
      LAYER M5 ;
        RECT 236.974 249.900 236.998 250.000 ;
    END
  END rq[355]
  PIN rq[354]
    DIRECTION INPUT ;
    USE SIGNAL ;
    PORT
      LAYER M5 ;
        RECT 236.878 249.900 236.902 250.000 ;
    END
  END rq[354]
  PIN rq[353]
    DIRECTION INPUT ;
    USE SIGNAL ;
    PORT
      LAYER M5 ;
        RECT 236.782 249.900 236.806 250.000 ;
    END
  END rq[353]
  PIN rq[352]
    DIRECTION INPUT ;
    USE SIGNAL ;
    PORT
      LAYER M5 ;
        RECT 236.686 249.900 236.710 250.000 ;
    END
  END rq[352]
  PIN rq[351]
    DIRECTION INPUT ;
    USE SIGNAL ;
    PORT
      LAYER M5 ;
        RECT 236.590 249.900 236.614 250.000 ;
    END
  END rq[351]
  PIN rq[350]
    DIRECTION INPUT ;
    USE SIGNAL ;
    PORT
      LAYER M5 ;
        RECT 236.494 249.900 236.518 250.000 ;
    END
  END rq[350]
  PIN rq[349]
    DIRECTION INPUT ;
    USE SIGNAL ;
    PORT
      LAYER M5 ;
        RECT 236.398 249.900 236.422 250.000 ;
    END
  END rq[349]
  PIN rq[348]
    DIRECTION INPUT ;
    USE SIGNAL ;
    PORT
      LAYER M5 ;
        RECT 236.302 249.900 236.326 250.000 ;
    END
  END rq[348]
  PIN rq[347]
    DIRECTION INPUT ;
    USE SIGNAL ;
    PORT
      LAYER M5 ;
        RECT 236.206 249.900 236.230 250.000 ;
    END
  END rq[347]
  PIN rq[346]
    DIRECTION INPUT ;
    USE SIGNAL ;
    PORT
      LAYER M5 ;
        RECT 236.110 249.900 236.134 250.000 ;
    END
  END rq[346]
  PIN rq[345]
    DIRECTION INPUT ;
    USE SIGNAL ;
    PORT
      LAYER M5 ;
        RECT 236.014 249.900 236.038 250.000 ;
    END
  END rq[345]
  PIN rq[344]
    DIRECTION INPUT ;
    USE SIGNAL ;
    PORT
      LAYER M5 ;
        RECT 235.918 249.900 235.942 250.000 ;
    END
  END rq[344]
  PIN rq[343]
    DIRECTION INPUT ;
    USE SIGNAL ;
    PORT
      LAYER M5 ;
        RECT 235.822 249.900 235.846 250.000 ;
    END
  END rq[343]
  PIN rq[342]
    DIRECTION INPUT ;
    USE SIGNAL ;
    PORT
      LAYER M5 ;
        RECT 235.726 249.900 235.750 250.000 ;
    END
  END rq[342]
  PIN rq[341]
    DIRECTION INPUT ;
    USE SIGNAL ;
    PORT
      LAYER M5 ;
        RECT 235.630 249.900 235.654 250.000 ;
    END
  END rq[341]
  PIN rq[340]
    DIRECTION INPUT ;
    USE SIGNAL ;
    PORT
      LAYER M5 ;
        RECT 235.534 249.900 235.558 250.000 ;
    END
  END rq[340]
  PIN rq[339]
    DIRECTION INPUT ;
    USE SIGNAL ;
    PORT
      LAYER M5 ;
        RECT 235.438 249.900 235.462 250.000 ;
    END
  END rq[339]
  PIN rq[338]
    DIRECTION INPUT ;
    USE SIGNAL ;
    PORT
      LAYER M5 ;
        RECT 235.342 249.900 235.366 250.000 ;
    END
  END rq[338]
  PIN rq[337]
    DIRECTION INPUT ;
    USE SIGNAL ;
    PORT
      LAYER M5 ;
        RECT 235.246 249.900 235.270 250.000 ;
    END
  END rq[337]
  PIN rq[336]
    DIRECTION INPUT ;
    USE SIGNAL ;
    PORT
      LAYER M5 ;
        RECT 235.150 249.900 235.174 250.000 ;
    END
  END rq[336]
  PIN rq[335]
    DIRECTION INPUT ;
    USE SIGNAL ;
    PORT
      LAYER M5 ;
        RECT 235.054 249.900 235.078 250.000 ;
    END
  END rq[335]
  PIN rq[334]
    DIRECTION INPUT ;
    USE SIGNAL ;
    PORT
      LAYER M5 ;
        RECT 234.958 249.900 234.982 250.000 ;
    END
  END rq[334]
  PIN rq[333]
    DIRECTION INPUT ;
    USE SIGNAL ;
    PORT
      LAYER M5 ;
        RECT 234.862 249.900 234.886 250.000 ;
    END
  END rq[333]
  PIN rq[332]
    DIRECTION INPUT ;
    USE SIGNAL ;
    PORT
      LAYER M5 ;
        RECT 234.766 249.900 234.790 250.000 ;
    END
  END rq[332]
  PIN rq[331]
    DIRECTION INPUT ;
    USE SIGNAL ;
    PORT
      LAYER M5 ;
        RECT 234.670 249.900 234.694 250.000 ;
    END
  END rq[331]
  PIN rq[330]
    DIRECTION INPUT ;
    USE SIGNAL ;
    PORT
      LAYER M5 ;
        RECT 234.574 249.900 234.598 250.000 ;
    END
  END rq[330]
  PIN rq[329]
    DIRECTION INPUT ;
    USE SIGNAL ;
    PORT
      LAYER M5 ;
        RECT 234.478 249.900 234.502 250.000 ;
    END
  END rq[329]
  PIN rq[328]
    DIRECTION INPUT ;
    USE SIGNAL ;
    PORT
      LAYER M5 ;
        RECT 234.382 249.900 234.406 250.000 ;
    END
  END rq[328]
  PIN rq[327]
    DIRECTION INPUT ;
    USE SIGNAL ;
    PORT
      LAYER M5 ;
        RECT 234.286 249.900 234.310 250.000 ;
    END
  END rq[327]
  PIN rq[326]
    DIRECTION INPUT ;
    USE SIGNAL ;
    PORT
      LAYER M5 ;
        RECT 234.190 249.900 234.214 250.000 ;
    END
  END rq[326]
  PIN rq[325]
    DIRECTION INPUT ;
    USE SIGNAL ;
    PORT
      LAYER M5 ;
        RECT 234.094 249.900 234.118 250.000 ;
    END
  END rq[325]
  PIN rq[324]
    DIRECTION INPUT ;
    USE SIGNAL ;
    PORT
      LAYER M5 ;
        RECT 233.998 249.900 234.022 250.000 ;
    END
  END rq[324]
  PIN rq[323]
    DIRECTION INPUT ;
    USE SIGNAL ;
    PORT
      LAYER M5 ;
        RECT 233.902 249.900 233.926 250.000 ;
    END
  END rq[323]
  PIN rq[322]
    DIRECTION INPUT ;
    USE SIGNAL ;
    PORT
      LAYER M5 ;
        RECT 233.806 249.900 233.830 250.000 ;
    END
  END rq[322]
  PIN rq[321]
    DIRECTION INPUT ;
    USE SIGNAL ;
    PORT
      LAYER M5 ;
        RECT 233.710 249.900 233.734 250.000 ;
    END
  END rq[321]
  PIN rq[320]
    DIRECTION INPUT ;
    USE SIGNAL ;
    PORT
      LAYER M5 ;
        RECT 233.614 249.900 233.638 250.000 ;
    END
  END rq[320]
  PIN rq[319]
    DIRECTION INPUT ;
    USE SIGNAL ;
    PORT
      LAYER M5 ;
        RECT 233.518 249.900 233.542 250.000 ;
    END
  END rq[319]
  PIN rq[318]
    DIRECTION INPUT ;
    USE SIGNAL ;
    PORT
      LAYER M5 ;
        RECT 233.422 249.900 233.446 250.000 ;
    END
  END rq[318]
  PIN rq[317]
    DIRECTION INPUT ;
    USE SIGNAL ;
    PORT
      LAYER M5 ;
        RECT 233.326 249.900 233.350 250.000 ;
    END
  END rq[317]
  PIN rq[316]
    DIRECTION INPUT ;
    USE SIGNAL ;
    PORT
      LAYER M5 ;
        RECT 233.230 249.900 233.254 250.000 ;
    END
  END rq[316]
  PIN rq[315]
    DIRECTION INPUT ;
    USE SIGNAL ;
    PORT
      LAYER M5 ;
        RECT 233.134 249.900 233.158 250.000 ;
    END
  END rq[315]
  PIN rq[314]
    DIRECTION INPUT ;
    USE SIGNAL ;
    PORT
      LAYER M5 ;
        RECT 233.038 249.900 233.062 250.000 ;
    END
  END rq[314]
  PIN rq[313]
    DIRECTION INPUT ;
    USE SIGNAL ;
    PORT
      LAYER M5 ;
        RECT 232.942 249.900 232.966 250.000 ;
    END
  END rq[313]
  PIN rq[312]
    DIRECTION INPUT ;
    USE SIGNAL ;
    PORT
      LAYER M5 ;
        RECT 232.846 249.900 232.870 250.000 ;
    END
  END rq[312]
  PIN rq[311]
    DIRECTION INPUT ;
    USE SIGNAL ;
    PORT
      LAYER M5 ;
        RECT 232.750 249.900 232.774 250.000 ;
    END
  END rq[311]
  PIN rq[310]
    DIRECTION INPUT ;
    USE SIGNAL ;
    PORT
      LAYER M5 ;
        RECT 232.654 249.900 232.678 250.000 ;
    END
  END rq[310]
  PIN rq[309]
    DIRECTION INPUT ;
    USE SIGNAL ;
    PORT
      LAYER M5 ;
        RECT 232.558 249.900 232.582 250.000 ;
    END
  END rq[309]
  PIN rq[308]
    DIRECTION INPUT ;
    USE SIGNAL ;
    PORT
      LAYER M5 ;
        RECT 232.462 249.900 232.486 250.000 ;
    END
  END rq[308]
  PIN rq[307]
    DIRECTION INPUT ;
    USE SIGNAL ;
    PORT
      LAYER M5 ;
        RECT 232.366 249.900 232.390 250.000 ;
    END
  END rq[307]
  PIN rq[306]
    DIRECTION INPUT ;
    USE SIGNAL ;
    PORT
      LAYER M5 ;
        RECT 232.270 249.900 232.294 250.000 ;
    END
  END rq[306]
  PIN rq[305]
    DIRECTION INPUT ;
    USE SIGNAL ;
    PORT
      LAYER M5 ;
        RECT 232.174 249.900 232.198 250.000 ;
    END
  END rq[305]
  PIN rq[304]
    DIRECTION INPUT ;
    USE SIGNAL ;
    PORT
      LAYER M5 ;
        RECT 232.078 249.900 232.102 250.000 ;
    END
  END rq[304]
  PIN rq[303]
    DIRECTION INPUT ;
    USE SIGNAL ;
    PORT
      LAYER M5 ;
        RECT 231.982 249.900 232.006 250.000 ;
    END
  END rq[303]
  PIN rq[302]
    DIRECTION INPUT ;
    USE SIGNAL ;
    PORT
      LAYER M5 ;
        RECT 231.886 249.900 231.910 250.000 ;
    END
  END rq[302]
  PIN rq[301]
    DIRECTION INPUT ;
    USE SIGNAL ;
    PORT
      LAYER M5 ;
        RECT 231.790 249.900 231.814 250.000 ;
    END
  END rq[301]
  PIN rq[300]
    DIRECTION INPUT ;
    USE SIGNAL ;
    PORT
      LAYER M5 ;
        RECT 231.694 249.900 231.718 250.000 ;
    END
  END rq[300]
  PIN rq[299]
    DIRECTION INPUT ;
    USE SIGNAL ;
    PORT
      LAYER M5 ;
        RECT 231.598 249.900 231.622 250.000 ;
    END
  END rq[299]
  PIN rq[298]
    DIRECTION INPUT ;
    USE SIGNAL ;
    PORT
      LAYER M5 ;
        RECT 231.502 249.900 231.526 250.000 ;
    END
  END rq[298]
  PIN rq[297]
    DIRECTION INPUT ;
    USE SIGNAL ;
    PORT
      LAYER M5 ;
        RECT 231.406 249.900 231.430 250.000 ;
    END
  END rq[297]
  PIN rq[296]
    DIRECTION INPUT ;
    USE SIGNAL ;
    PORT
      LAYER M5 ;
        RECT 231.310 249.900 231.334 250.000 ;
    END
  END rq[296]
  PIN rq[295]
    DIRECTION INPUT ;
    USE SIGNAL ;
    PORT
      LAYER M5 ;
        RECT 231.214 249.900 231.238 250.000 ;
    END
  END rq[295]
  PIN rq[294]
    DIRECTION INPUT ;
    USE SIGNAL ;
    PORT
      LAYER M5 ;
        RECT 231.118 249.900 231.142 250.000 ;
    END
  END rq[294]
  PIN rq[293]
    DIRECTION INPUT ;
    USE SIGNAL ;
    PORT
      LAYER M5 ;
        RECT 231.022 249.900 231.046 250.000 ;
    END
  END rq[293]
  PIN rq[292]
    DIRECTION INPUT ;
    USE SIGNAL ;
    PORT
      LAYER M5 ;
        RECT 230.926 249.900 230.950 250.000 ;
    END
  END rq[292]
  PIN rq[291]
    DIRECTION INPUT ;
    USE SIGNAL ;
    PORT
      LAYER M5 ;
        RECT 230.830 249.900 230.854 250.000 ;
    END
  END rq[291]
  PIN rq[290]
    DIRECTION INPUT ;
    USE SIGNAL ;
    PORT
      LAYER M5 ;
        RECT 230.734 249.900 230.758 250.000 ;
    END
  END rq[290]
  PIN rq[289]
    DIRECTION INPUT ;
    USE SIGNAL ;
    PORT
      LAYER M5 ;
        RECT 230.638 249.900 230.662 250.000 ;
    END
  END rq[289]
  PIN rq[288]
    DIRECTION INPUT ;
    USE SIGNAL ;
    PORT
      LAYER M5 ;
        RECT 230.542 249.900 230.566 250.000 ;
    END
  END rq[288]
  PIN rq[287]
    DIRECTION INPUT ;
    USE SIGNAL ;
    PORT
      LAYER M5 ;
        RECT 230.446 249.900 230.470 250.000 ;
    END
  END rq[287]
  PIN rq[286]
    DIRECTION INPUT ;
    USE SIGNAL ;
    PORT
      LAYER M5 ;
        RECT 230.350 249.900 230.374 250.000 ;
    END
  END rq[286]
  PIN rq[285]
    DIRECTION INPUT ;
    USE SIGNAL ;
    PORT
      LAYER M5 ;
        RECT 230.254 249.900 230.278 250.000 ;
    END
  END rq[285]
  PIN rq[284]
    DIRECTION INPUT ;
    USE SIGNAL ;
    PORT
      LAYER M5 ;
        RECT 230.158 249.900 230.182 250.000 ;
    END
  END rq[284]
  PIN rq[283]
    DIRECTION INPUT ;
    USE SIGNAL ;
    PORT
      LAYER M5 ;
        RECT 230.062 249.900 230.086 250.000 ;
    END
  END rq[283]
  PIN rq[282]
    DIRECTION INPUT ;
    USE SIGNAL ;
    PORT
      LAYER M5 ;
        RECT 229.966 249.900 229.990 250.000 ;
    END
  END rq[282]
  PIN rq[281]
    DIRECTION INPUT ;
    USE SIGNAL ;
    PORT
      LAYER M5 ;
        RECT 229.870 249.900 229.894 250.000 ;
    END
  END rq[281]
  PIN rq[280]
    DIRECTION INPUT ;
    USE SIGNAL ;
    PORT
      LAYER M5 ;
        RECT 229.774 249.900 229.798 250.000 ;
    END
  END rq[280]
  PIN rq[279]
    DIRECTION INPUT ;
    USE SIGNAL ;
    PORT
      LAYER M5 ;
        RECT 229.678 249.900 229.702 250.000 ;
    END
  END rq[279]
  PIN rq[278]
    DIRECTION INPUT ;
    USE SIGNAL ;
    PORT
      LAYER M5 ;
        RECT 229.582 249.900 229.606 250.000 ;
    END
  END rq[278]
  PIN rq[277]
    DIRECTION INPUT ;
    USE SIGNAL ;
    PORT
      LAYER M5 ;
        RECT 229.486 249.900 229.510 250.000 ;
    END
  END rq[277]
  PIN rq[276]
    DIRECTION INPUT ;
    USE SIGNAL ;
    PORT
      LAYER M5 ;
        RECT 229.390 249.900 229.414 250.000 ;
    END
  END rq[276]
  PIN rq[275]
    DIRECTION INPUT ;
    USE SIGNAL ;
    PORT
      LAYER M5 ;
        RECT 229.294 249.900 229.318 250.000 ;
    END
  END rq[275]
  PIN rq[274]
    DIRECTION INPUT ;
    USE SIGNAL ;
    PORT
      LAYER M5 ;
        RECT 229.198 249.900 229.222 250.000 ;
    END
  END rq[274]
  PIN rq[273]
    DIRECTION INPUT ;
    USE SIGNAL ;
    PORT
      LAYER M5 ;
        RECT 229.102 249.900 229.126 250.000 ;
    END
  END rq[273]
  PIN rq[272]
    DIRECTION INPUT ;
    USE SIGNAL ;
    PORT
      LAYER M5 ;
        RECT 229.006 249.900 229.030 250.000 ;
    END
  END rq[272]
  PIN rq[271]
    DIRECTION INPUT ;
    USE SIGNAL ;
    PORT
      LAYER M5 ;
        RECT 228.910 249.900 228.934 250.000 ;
    END
  END rq[271]
  PIN rq[270]
    DIRECTION INPUT ;
    USE SIGNAL ;
    PORT
      LAYER M5 ;
        RECT 228.814 249.900 228.838 250.000 ;
    END
  END rq[270]
  PIN rq[269]
    DIRECTION INPUT ;
    USE SIGNAL ;
    PORT
      LAYER M5 ;
        RECT 228.718 249.900 228.742 250.000 ;
    END
  END rq[269]
  PIN rq[268]
    DIRECTION INPUT ;
    USE SIGNAL ;
    PORT
      LAYER M5 ;
        RECT 228.622 249.900 228.646 250.000 ;
    END
  END rq[268]
  PIN rq[267]
    DIRECTION INPUT ;
    USE SIGNAL ;
    PORT
      LAYER M5 ;
        RECT 228.526 249.900 228.550 250.000 ;
    END
  END rq[267]
  PIN rq[266]
    DIRECTION INPUT ;
    USE SIGNAL ;
    PORT
      LAYER M5 ;
        RECT 228.430 249.900 228.454 250.000 ;
    END
  END rq[266]
  PIN rq[265]
    DIRECTION INPUT ;
    USE SIGNAL ;
    PORT
      LAYER M5 ;
        RECT 228.334 249.900 228.358 250.000 ;
    END
  END rq[265]
  PIN rq[264]
    DIRECTION INPUT ;
    USE SIGNAL ;
    PORT
      LAYER M5 ;
        RECT 228.238 249.900 228.262 250.000 ;
    END
  END rq[264]
  PIN rq[263]
    DIRECTION INPUT ;
    USE SIGNAL ;
    PORT
      LAYER M5 ;
        RECT 228.142 249.900 228.166 250.000 ;
    END
  END rq[263]
  PIN rq[262]
    DIRECTION INPUT ;
    USE SIGNAL ;
    PORT
      LAYER M5 ;
        RECT 228.046 249.900 228.070 250.000 ;
    END
  END rq[262]
  PIN rq[261]
    DIRECTION INPUT ;
    USE SIGNAL ;
    PORT
      LAYER M5 ;
        RECT 227.950 249.900 227.974 250.000 ;
    END
  END rq[261]
  PIN rq[260]
    DIRECTION INPUT ;
    USE SIGNAL ;
    PORT
      LAYER M5 ;
        RECT 227.854 249.900 227.878 250.000 ;
    END
  END rq[260]
  PIN rq[259]
    DIRECTION INPUT ;
    USE SIGNAL ;
    PORT
      LAYER M5 ;
        RECT 227.758 249.900 227.782 250.000 ;
    END
  END rq[259]
  PIN rq[258]
    DIRECTION INPUT ;
    USE SIGNAL ;
    PORT
      LAYER M5 ;
        RECT 227.662 249.900 227.686 250.000 ;
    END
  END rq[258]
  PIN rq[257]
    DIRECTION INPUT ;
    USE SIGNAL ;
    PORT
      LAYER M5 ;
        RECT 227.566 249.900 227.590 250.000 ;
    END
  END rq[257]
  PIN rq[256]
    DIRECTION INPUT ;
    USE SIGNAL ;
    PORT
      LAYER M5 ;
        RECT 227.470 249.900 227.494 250.000 ;
    END
  END rq[256]
  PIN rq[255]
    DIRECTION INPUT ;
    USE SIGNAL ;
    PORT
      LAYER M5 ;
        RECT 227.374 249.900 227.398 250.000 ;
    END
  END rq[255]
  PIN rq[254]
    DIRECTION INPUT ;
    USE SIGNAL ;
    PORT
      LAYER M5 ;
        RECT 227.278 249.900 227.302 250.000 ;
    END
  END rq[254]
  PIN rq[253]
    DIRECTION INPUT ;
    USE SIGNAL ;
    PORT
      LAYER M5 ;
        RECT 227.182 249.900 227.206 250.000 ;
    END
  END rq[253]
  PIN rq[252]
    DIRECTION INPUT ;
    USE SIGNAL ;
    PORT
      LAYER M5 ;
        RECT 227.086 249.900 227.110 250.000 ;
    END
  END rq[252]
  PIN rq[251]
    DIRECTION INPUT ;
    USE SIGNAL ;
    PORT
      LAYER M5 ;
        RECT 226.990 249.900 227.014 250.000 ;
    END
  END rq[251]
  PIN rq[250]
    DIRECTION INPUT ;
    USE SIGNAL ;
    PORT
      LAYER M5 ;
        RECT 226.894 249.900 226.918 250.000 ;
    END
  END rq[250]
  PIN rq[249]
    DIRECTION INPUT ;
    USE SIGNAL ;
    PORT
      LAYER M5 ;
        RECT 226.798 249.900 226.822 250.000 ;
    END
  END rq[249]
  PIN rq[248]
    DIRECTION INPUT ;
    USE SIGNAL ;
    PORT
      LAYER M5 ;
        RECT 226.702 249.900 226.726 250.000 ;
    END
  END rq[248]
  PIN rq[247]
    DIRECTION INPUT ;
    USE SIGNAL ;
    PORT
      LAYER M5 ;
        RECT 226.606 249.900 226.630 250.000 ;
    END
  END rq[247]
  PIN rq[246]
    DIRECTION INPUT ;
    USE SIGNAL ;
    PORT
      LAYER M5 ;
        RECT 226.510 249.900 226.534 250.000 ;
    END
  END rq[246]
  PIN rq[245]
    DIRECTION INPUT ;
    USE SIGNAL ;
    PORT
      LAYER M5 ;
        RECT 226.414 249.900 226.438 250.000 ;
    END
  END rq[245]
  PIN rq[244]
    DIRECTION INPUT ;
    USE SIGNAL ;
    PORT
      LAYER M5 ;
        RECT 226.318 249.900 226.342 250.000 ;
    END
  END rq[244]
  PIN rq[243]
    DIRECTION INPUT ;
    USE SIGNAL ;
    PORT
      LAYER M5 ;
        RECT 226.222 249.900 226.246 250.000 ;
    END
  END rq[243]
  PIN rq[242]
    DIRECTION INPUT ;
    USE SIGNAL ;
    PORT
      LAYER M5 ;
        RECT 226.126 249.900 226.150 250.000 ;
    END
  END rq[242]
  PIN rq[241]
    DIRECTION INPUT ;
    USE SIGNAL ;
    PORT
      LAYER M5 ;
        RECT 226.030 249.900 226.054 250.000 ;
    END
  END rq[241]
  PIN rq[240]
    DIRECTION INPUT ;
    USE SIGNAL ;
    PORT
      LAYER M5 ;
        RECT 225.934 249.900 225.958 250.000 ;
    END
  END rq[240]
  PIN rq[239]
    DIRECTION INPUT ;
    USE SIGNAL ;
    PORT
      LAYER M5 ;
        RECT 225.838 249.900 225.862 250.000 ;
    END
  END rq[239]
  PIN rq[238]
    DIRECTION INPUT ;
    USE SIGNAL ;
    PORT
      LAYER M5 ;
        RECT 225.742 249.900 225.766 250.000 ;
    END
  END rq[238]
  PIN rq[237]
    DIRECTION INPUT ;
    USE SIGNAL ;
    PORT
      LAYER M5 ;
        RECT 225.646 249.900 225.670 250.000 ;
    END
  END rq[237]
  PIN rq[236]
    DIRECTION INPUT ;
    USE SIGNAL ;
    PORT
      LAYER M5 ;
        RECT 225.550 249.900 225.574 250.000 ;
    END
  END rq[236]
  PIN rq[235]
    DIRECTION INPUT ;
    USE SIGNAL ;
    PORT
      LAYER M5 ;
        RECT 225.454 249.900 225.478 250.000 ;
    END
  END rq[235]
  PIN rq[234]
    DIRECTION INPUT ;
    USE SIGNAL ;
    PORT
      LAYER M5 ;
        RECT 225.358 249.900 225.382 250.000 ;
    END
  END rq[234]
  PIN rq[233]
    DIRECTION INPUT ;
    USE SIGNAL ;
    PORT
      LAYER M5 ;
        RECT 225.262 249.900 225.286 250.000 ;
    END
  END rq[233]
  PIN rq[232]
    DIRECTION INPUT ;
    USE SIGNAL ;
    PORT
      LAYER M5 ;
        RECT 225.166 249.900 225.190 250.000 ;
    END
  END rq[232]
  PIN rq[231]
    DIRECTION INPUT ;
    USE SIGNAL ;
    PORT
      LAYER M5 ;
        RECT 225.070 249.900 225.094 250.000 ;
    END
  END rq[231]
  PIN rq[230]
    DIRECTION INPUT ;
    USE SIGNAL ;
    PORT
      LAYER M5 ;
        RECT 224.974 249.900 224.998 250.000 ;
    END
  END rq[230]
  PIN rq[229]
    DIRECTION INPUT ;
    USE SIGNAL ;
    PORT
      LAYER M5 ;
        RECT 224.878 249.900 224.902 250.000 ;
    END
  END rq[229]
  PIN rq[228]
    DIRECTION INPUT ;
    USE SIGNAL ;
    PORT
      LAYER M5 ;
        RECT 224.782 249.900 224.806 250.000 ;
    END
  END rq[228]
  PIN rq[227]
    DIRECTION INPUT ;
    USE SIGNAL ;
    PORT
      LAYER M5 ;
        RECT 224.686 249.900 224.710 250.000 ;
    END
  END rq[227]
  PIN rq[226]
    DIRECTION INPUT ;
    USE SIGNAL ;
    PORT
      LAYER M5 ;
        RECT 224.590 249.900 224.614 250.000 ;
    END
  END rq[226]
  PIN rq[225]
    DIRECTION INPUT ;
    USE SIGNAL ;
    PORT
      LAYER M5 ;
        RECT 224.494 249.900 224.518 250.000 ;
    END
  END rq[225]
  PIN rq[224]
    DIRECTION INPUT ;
    USE SIGNAL ;
    PORT
      LAYER M5 ;
        RECT 224.398 249.900 224.422 250.000 ;
    END
  END rq[224]
  PIN rq[223]
    DIRECTION INPUT ;
    USE SIGNAL ;
    PORT
      LAYER M5 ;
        RECT 224.302 249.900 224.326 250.000 ;
    END
  END rq[223]
  PIN rq[222]
    DIRECTION INPUT ;
    USE SIGNAL ;
    PORT
      LAYER M5 ;
        RECT 224.206 249.900 224.230 250.000 ;
    END
  END rq[222]
  PIN rq[221]
    DIRECTION INPUT ;
    USE SIGNAL ;
    PORT
      LAYER M5 ;
        RECT 224.110 249.900 224.134 250.000 ;
    END
  END rq[221]
  PIN rq[220]
    DIRECTION INPUT ;
    USE SIGNAL ;
    PORT
      LAYER M5 ;
        RECT 224.014 249.900 224.038 250.000 ;
    END
  END rq[220]
  PIN rq[219]
    DIRECTION INPUT ;
    USE SIGNAL ;
    PORT
      LAYER M5 ;
        RECT 223.918 249.900 223.942 250.000 ;
    END
  END rq[219]
  PIN rq[218]
    DIRECTION INPUT ;
    USE SIGNAL ;
    PORT
      LAYER M5 ;
        RECT 223.822 249.900 223.846 250.000 ;
    END
  END rq[218]
  PIN rq[217]
    DIRECTION INPUT ;
    USE SIGNAL ;
    PORT
      LAYER M5 ;
        RECT 223.726 249.900 223.750 250.000 ;
    END
  END rq[217]
  PIN rq[216]
    DIRECTION INPUT ;
    USE SIGNAL ;
    PORT
      LAYER M5 ;
        RECT 223.630 249.900 223.654 250.000 ;
    END
  END rq[216]
  PIN rq[215]
    DIRECTION INPUT ;
    USE SIGNAL ;
    PORT
      LAYER M5 ;
        RECT 223.534 249.900 223.558 250.000 ;
    END
  END rq[215]
  PIN rq[214]
    DIRECTION INPUT ;
    USE SIGNAL ;
    PORT
      LAYER M5 ;
        RECT 223.438 249.900 223.462 250.000 ;
    END
  END rq[214]
  PIN rq[213]
    DIRECTION INPUT ;
    USE SIGNAL ;
    PORT
      LAYER M5 ;
        RECT 223.342 249.900 223.366 250.000 ;
    END
  END rq[213]
  PIN rq[212]
    DIRECTION INPUT ;
    USE SIGNAL ;
    PORT
      LAYER M5 ;
        RECT 223.246 249.900 223.270 250.000 ;
    END
  END rq[212]
  PIN rq[211]
    DIRECTION INPUT ;
    USE SIGNAL ;
    PORT
      LAYER M5 ;
        RECT 223.150 249.900 223.174 250.000 ;
    END
  END rq[211]
  PIN rq[210]
    DIRECTION INPUT ;
    USE SIGNAL ;
    PORT
      LAYER M5 ;
        RECT 223.054 249.900 223.078 250.000 ;
    END
  END rq[210]
  PIN rq[209]
    DIRECTION INPUT ;
    USE SIGNAL ;
    PORT
      LAYER M5 ;
        RECT 222.958 249.900 222.982 250.000 ;
    END
  END rq[209]
  PIN rq[208]
    DIRECTION INPUT ;
    USE SIGNAL ;
    PORT
      LAYER M5 ;
        RECT 222.862 249.900 222.886 250.000 ;
    END
  END rq[208]
  PIN rq[207]
    DIRECTION INPUT ;
    USE SIGNAL ;
    PORT
      LAYER M5 ;
        RECT 222.766 249.900 222.790 250.000 ;
    END
  END rq[207]
  PIN rq[206]
    DIRECTION INPUT ;
    USE SIGNAL ;
    PORT
      LAYER M5 ;
        RECT 222.670 249.900 222.694 250.000 ;
    END
  END rq[206]
  PIN rq[205]
    DIRECTION INPUT ;
    USE SIGNAL ;
    PORT
      LAYER M5 ;
        RECT 222.574 249.900 222.598 250.000 ;
    END
  END rq[205]
  PIN rq[204]
    DIRECTION INPUT ;
    USE SIGNAL ;
    PORT
      LAYER M5 ;
        RECT 222.478 249.900 222.502 250.000 ;
    END
  END rq[204]
  PIN rq[203]
    DIRECTION INPUT ;
    USE SIGNAL ;
    PORT
      LAYER M5 ;
        RECT 222.382 249.900 222.406 250.000 ;
    END
  END rq[203]
  PIN rq[202]
    DIRECTION INPUT ;
    USE SIGNAL ;
    PORT
      LAYER M5 ;
        RECT 222.286 249.900 222.310 250.000 ;
    END
  END rq[202]
  PIN rq[201]
    DIRECTION INPUT ;
    USE SIGNAL ;
    PORT
      LAYER M5 ;
        RECT 222.190 249.900 222.214 250.000 ;
    END
  END rq[201]
  PIN rq[200]
    DIRECTION INPUT ;
    USE SIGNAL ;
    PORT
      LAYER M5 ;
        RECT 222.094 249.900 222.118 250.000 ;
    END
  END rq[200]
  PIN rq[199]
    DIRECTION INPUT ;
    USE SIGNAL ;
    PORT
      LAYER M5 ;
        RECT 221.998 249.900 222.022 250.000 ;
    END
  END rq[199]
  PIN rq[198]
    DIRECTION INPUT ;
    USE SIGNAL ;
    PORT
      LAYER M5 ;
        RECT 221.902 249.900 221.926 250.000 ;
    END
  END rq[198]
  PIN rq[197]
    DIRECTION INPUT ;
    USE SIGNAL ;
    PORT
      LAYER M5 ;
        RECT 221.806 249.900 221.830 250.000 ;
    END
  END rq[197]
  PIN rq[196]
    DIRECTION INPUT ;
    USE SIGNAL ;
    PORT
      LAYER M5 ;
        RECT 221.710 249.900 221.734 250.000 ;
    END
  END rq[196]
  PIN rq[195]
    DIRECTION INPUT ;
    USE SIGNAL ;
    PORT
      LAYER M5 ;
        RECT 221.614 249.900 221.638 250.000 ;
    END
  END rq[195]
  PIN rq[194]
    DIRECTION INPUT ;
    USE SIGNAL ;
    PORT
      LAYER M5 ;
        RECT 221.518 249.900 221.542 250.000 ;
    END
  END rq[194]
  PIN rq[193]
    DIRECTION INPUT ;
    USE SIGNAL ;
    PORT
      LAYER M5 ;
        RECT 221.422 249.900 221.446 250.000 ;
    END
  END rq[193]
  PIN rq[192]
    DIRECTION INPUT ;
    USE SIGNAL ;
    PORT
      LAYER M5 ;
        RECT 221.326 249.900 221.350 250.000 ;
    END
  END rq[192]
  PIN rq[191]
    DIRECTION INPUT ;
    USE SIGNAL ;
    PORT
      LAYER M5 ;
        RECT 221.230 249.900 221.254 250.000 ;
    END
  END rq[191]
  PIN rq[190]
    DIRECTION INPUT ;
    USE SIGNAL ;
    PORT
      LAYER M5 ;
        RECT 221.134 249.900 221.158 250.000 ;
    END
  END rq[190]
  PIN rq[189]
    DIRECTION INPUT ;
    USE SIGNAL ;
    PORT
      LAYER M5 ;
        RECT 221.038 249.900 221.062 250.000 ;
    END
  END rq[189]
  PIN rq[188]
    DIRECTION INPUT ;
    USE SIGNAL ;
    PORT
      LAYER M5 ;
        RECT 220.942 249.900 220.966 250.000 ;
    END
  END rq[188]
  PIN rq[187]
    DIRECTION INPUT ;
    USE SIGNAL ;
    PORT
      LAYER M5 ;
        RECT 220.846 249.900 220.870 250.000 ;
    END
  END rq[187]
  PIN rq[186]
    DIRECTION INPUT ;
    USE SIGNAL ;
    PORT
      LAYER M5 ;
        RECT 220.750 249.900 220.774 250.000 ;
    END
  END rq[186]
  PIN rq[185]
    DIRECTION INPUT ;
    USE SIGNAL ;
    PORT
      LAYER M5 ;
        RECT 220.654 249.900 220.678 250.000 ;
    END
  END rq[185]
  PIN rq[184]
    DIRECTION INPUT ;
    USE SIGNAL ;
    PORT
      LAYER M5 ;
        RECT 220.558 249.900 220.582 250.000 ;
    END
  END rq[184]
  PIN rq[183]
    DIRECTION INPUT ;
    USE SIGNAL ;
    PORT
      LAYER M5 ;
        RECT 220.462 249.900 220.486 250.000 ;
    END
  END rq[183]
  PIN rq[182]
    DIRECTION INPUT ;
    USE SIGNAL ;
    PORT
      LAYER M5 ;
        RECT 220.366 249.900 220.390 250.000 ;
    END
  END rq[182]
  PIN rq[181]
    DIRECTION INPUT ;
    USE SIGNAL ;
    PORT
      LAYER M5 ;
        RECT 220.270 249.900 220.294 250.000 ;
    END
  END rq[181]
  PIN rq[180]
    DIRECTION INPUT ;
    USE SIGNAL ;
    PORT
      LAYER M5 ;
        RECT 220.174 249.900 220.198 250.000 ;
    END
  END rq[180]
  PIN rq[179]
    DIRECTION INPUT ;
    USE SIGNAL ;
    PORT
      LAYER M5 ;
        RECT 220.078 249.900 220.102 250.000 ;
    END
  END rq[179]
  PIN rq[178]
    DIRECTION INPUT ;
    USE SIGNAL ;
    PORT
      LAYER M5 ;
        RECT 219.982 249.900 220.006 250.000 ;
    END
  END rq[178]
  PIN rq[177]
    DIRECTION INPUT ;
    USE SIGNAL ;
    PORT
      LAYER M5 ;
        RECT 219.886 249.900 219.910 250.000 ;
    END
  END rq[177]
  PIN rq[176]
    DIRECTION INPUT ;
    USE SIGNAL ;
    PORT
      LAYER M5 ;
        RECT 219.790 249.900 219.814 250.000 ;
    END
  END rq[176]
  PIN rq[175]
    DIRECTION INPUT ;
    USE SIGNAL ;
    PORT
      LAYER M5 ;
        RECT 219.694 249.900 219.718 250.000 ;
    END
  END rq[175]
  PIN rq[174]
    DIRECTION INPUT ;
    USE SIGNAL ;
    PORT
      LAYER M5 ;
        RECT 219.598 249.900 219.622 250.000 ;
    END
  END rq[174]
  PIN rq[173]
    DIRECTION INPUT ;
    USE SIGNAL ;
    PORT
      LAYER M5 ;
        RECT 219.502 249.900 219.526 250.000 ;
    END
  END rq[173]
  PIN rq[172]
    DIRECTION INPUT ;
    USE SIGNAL ;
    PORT
      LAYER M5 ;
        RECT 219.406 249.900 219.430 250.000 ;
    END
  END rq[172]
  PIN rq[171]
    DIRECTION INPUT ;
    USE SIGNAL ;
    PORT
      LAYER M5 ;
        RECT 219.310 249.900 219.334 250.000 ;
    END
  END rq[171]
  PIN rq[170]
    DIRECTION INPUT ;
    USE SIGNAL ;
    PORT
      LAYER M5 ;
        RECT 219.214 249.900 219.238 250.000 ;
    END
  END rq[170]
  PIN rq[169]
    DIRECTION INPUT ;
    USE SIGNAL ;
    PORT
      LAYER M5 ;
        RECT 219.118 249.900 219.142 250.000 ;
    END
  END rq[169]
  PIN rq[168]
    DIRECTION INPUT ;
    USE SIGNAL ;
    PORT
      LAYER M5 ;
        RECT 219.022 249.900 219.046 250.000 ;
    END
  END rq[168]
  PIN rq[167]
    DIRECTION INPUT ;
    USE SIGNAL ;
    PORT
      LAYER M5 ;
        RECT 218.926 249.900 218.950 250.000 ;
    END
  END rq[167]
  PIN rq[166]
    DIRECTION INPUT ;
    USE SIGNAL ;
    PORT
      LAYER M5 ;
        RECT 218.830 249.900 218.854 250.000 ;
    END
  END rq[166]
  PIN rq[165]
    DIRECTION INPUT ;
    USE SIGNAL ;
    PORT
      LAYER M5 ;
        RECT 218.734 249.900 218.758 250.000 ;
    END
  END rq[165]
  PIN rq[164]
    DIRECTION INPUT ;
    USE SIGNAL ;
    PORT
      LAYER M5 ;
        RECT 218.638 249.900 218.662 250.000 ;
    END
  END rq[164]
  PIN rq[163]
    DIRECTION INPUT ;
    USE SIGNAL ;
    PORT
      LAYER M5 ;
        RECT 218.542 249.900 218.566 250.000 ;
    END
  END rq[163]
  PIN rq[162]
    DIRECTION INPUT ;
    USE SIGNAL ;
    PORT
      LAYER M5 ;
        RECT 218.446 249.900 218.470 250.000 ;
    END
  END rq[162]
  PIN rq[161]
    DIRECTION INPUT ;
    USE SIGNAL ;
    PORT
      LAYER M5 ;
        RECT 218.350 249.900 218.374 250.000 ;
    END
  END rq[161]
  PIN rq[160]
    DIRECTION INPUT ;
    USE SIGNAL ;
    PORT
      LAYER M5 ;
        RECT 218.254 249.900 218.278 250.000 ;
    END
  END rq[160]
  PIN rq[159]
    DIRECTION INPUT ;
    USE SIGNAL ;
    PORT
      LAYER M5 ;
        RECT 218.158 249.900 218.182 250.000 ;
    END
  END rq[159]
  PIN rq[158]
    DIRECTION INPUT ;
    USE SIGNAL ;
    PORT
      LAYER M5 ;
        RECT 218.062 249.900 218.086 250.000 ;
    END
  END rq[158]
  PIN rq[157]
    DIRECTION INPUT ;
    USE SIGNAL ;
    PORT
      LAYER M5 ;
        RECT 217.966 249.900 217.990 250.000 ;
    END
  END rq[157]
  PIN rq[156]
    DIRECTION INPUT ;
    USE SIGNAL ;
    PORT
      LAYER M5 ;
        RECT 217.870 249.900 217.894 250.000 ;
    END
  END rq[156]
  PIN rq[155]
    DIRECTION INPUT ;
    USE SIGNAL ;
    PORT
      LAYER M5 ;
        RECT 217.774 249.900 217.798 250.000 ;
    END
  END rq[155]
  PIN rq[154]
    DIRECTION INPUT ;
    USE SIGNAL ;
    PORT
      LAYER M5 ;
        RECT 217.678 249.900 217.702 250.000 ;
    END
  END rq[154]
  PIN rq[153]
    DIRECTION INPUT ;
    USE SIGNAL ;
    PORT
      LAYER M5 ;
        RECT 217.582 249.900 217.606 250.000 ;
    END
  END rq[153]
  PIN rq[152]
    DIRECTION INPUT ;
    USE SIGNAL ;
    PORT
      LAYER M5 ;
        RECT 217.486 249.900 217.510 250.000 ;
    END
  END rq[152]
  PIN rq[151]
    DIRECTION INPUT ;
    USE SIGNAL ;
    PORT
      LAYER M5 ;
        RECT 217.390 249.900 217.414 250.000 ;
    END
  END rq[151]
  PIN rq[150]
    DIRECTION INPUT ;
    USE SIGNAL ;
    PORT
      LAYER M5 ;
        RECT 217.294 249.900 217.318 250.000 ;
    END
  END rq[150]
  PIN rq[149]
    DIRECTION INPUT ;
    USE SIGNAL ;
    PORT
      LAYER M5 ;
        RECT 217.198 249.900 217.222 250.000 ;
    END
  END rq[149]
  PIN rq[148]
    DIRECTION INPUT ;
    USE SIGNAL ;
    PORT
      LAYER M5 ;
        RECT 217.102 249.900 217.126 250.000 ;
    END
  END rq[148]
  PIN rq[147]
    DIRECTION INPUT ;
    USE SIGNAL ;
    PORT
      LAYER M5 ;
        RECT 217.006 249.900 217.030 250.000 ;
    END
  END rq[147]
  PIN rq[146]
    DIRECTION INPUT ;
    USE SIGNAL ;
    PORT
      LAYER M5 ;
        RECT 216.910 249.900 216.934 250.000 ;
    END
  END rq[146]
  PIN rq[145]
    DIRECTION INPUT ;
    USE SIGNAL ;
    PORT
      LAYER M5 ;
        RECT 216.814 249.900 216.838 250.000 ;
    END
  END rq[145]
  PIN rq[144]
    DIRECTION INPUT ;
    USE SIGNAL ;
    PORT
      LAYER M5 ;
        RECT 216.718 249.900 216.742 250.000 ;
    END
  END rq[144]
  PIN rq[143]
    DIRECTION INPUT ;
    USE SIGNAL ;
    PORT
      LAYER M5 ;
        RECT 216.622 249.900 216.646 250.000 ;
    END
  END rq[143]
  PIN rq[142]
    DIRECTION INPUT ;
    USE SIGNAL ;
    PORT
      LAYER M5 ;
        RECT 216.526 249.900 216.550 250.000 ;
    END
  END rq[142]
  PIN rq[141]
    DIRECTION INPUT ;
    USE SIGNAL ;
    PORT
      LAYER M5 ;
        RECT 216.430 249.900 216.454 250.000 ;
    END
  END rq[141]
  PIN rq[140]
    DIRECTION INPUT ;
    USE SIGNAL ;
    PORT
      LAYER M5 ;
        RECT 216.334 249.900 216.358 250.000 ;
    END
  END rq[140]
  PIN rq[139]
    DIRECTION INPUT ;
    USE SIGNAL ;
    PORT
      LAYER M5 ;
        RECT 216.238 249.900 216.262 250.000 ;
    END
  END rq[139]
  PIN rq[138]
    DIRECTION INPUT ;
    USE SIGNAL ;
    PORT
      LAYER M5 ;
        RECT 216.142 249.900 216.166 250.000 ;
    END
  END rq[138]
  PIN rq[137]
    DIRECTION INPUT ;
    USE SIGNAL ;
    PORT
      LAYER M5 ;
        RECT 216.046 249.900 216.070 250.000 ;
    END
  END rq[137]
  PIN rq[136]
    DIRECTION INPUT ;
    USE SIGNAL ;
    PORT
      LAYER M5 ;
        RECT 215.950 249.900 215.974 250.000 ;
    END
  END rq[136]
  PIN rq[135]
    DIRECTION INPUT ;
    USE SIGNAL ;
    PORT
      LAYER M5 ;
        RECT 215.854 249.900 215.878 250.000 ;
    END
  END rq[135]
  PIN rq[134]
    DIRECTION INPUT ;
    USE SIGNAL ;
    PORT
      LAYER M5 ;
        RECT 215.758 249.900 215.782 250.000 ;
    END
  END rq[134]
  PIN rq[133]
    DIRECTION INPUT ;
    USE SIGNAL ;
    PORT
      LAYER M5 ;
        RECT 215.662 249.900 215.686 250.000 ;
    END
  END rq[133]
  PIN rq[132]
    DIRECTION INPUT ;
    USE SIGNAL ;
    PORT
      LAYER M5 ;
        RECT 215.566 249.900 215.590 250.000 ;
    END
  END rq[132]
  PIN rq[131]
    DIRECTION INPUT ;
    USE SIGNAL ;
    PORT
      LAYER M5 ;
        RECT 215.470 249.900 215.494 250.000 ;
    END
  END rq[131]
  PIN rq[130]
    DIRECTION INPUT ;
    USE SIGNAL ;
    PORT
      LAYER M5 ;
        RECT 215.374 249.900 215.398 250.000 ;
    END
  END rq[130]
  PIN rq[129]
    DIRECTION INPUT ;
    USE SIGNAL ;
    PORT
      LAYER M5 ;
        RECT 215.278 249.900 215.302 250.000 ;
    END
  END rq[129]
  PIN rq[128]
    DIRECTION INPUT ;
    USE SIGNAL ;
    PORT
      LAYER M5 ;
        RECT 215.182 249.900 215.206 250.000 ;
    END
  END rq[128]
  PIN rq[127]
    DIRECTION INPUT ;
    USE SIGNAL ;
    PORT
      LAYER M5 ;
        RECT 215.086 249.900 215.110 250.000 ;
    END
  END rq[127]
  PIN rq[126]
    DIRECTION INPUT ;
    USE SIGNAL ;
    PORT
      LAYER M5 ;
        RECT 214.990 249.900 215.014 250.000 ;
    END
  END rq[126]
  PIN rq[125]
    DIRECTION INPUT ;
    USE SIGNAL ;
    PORT
      LAYER M5 ;
        RECT 214.894 249.900 214.918 250.000 ;
    END
  END rq[125]
  PIN rq[124]
    DIRECTION INPUT ;
    USE SIGNAL ;
    PORT
      LAYER M5 ;
        RECT 214.798 249.900 214.822 250.000 ;
    END
  END rq[124]
  PIN rq[123]
    DIRECTION INPUT ;
    USE SIGNAL ;
    PORT
      LAYER M5 ;
        RECT 214.702 249.900 214.726 250.000 ;
    END
  END rq[123]
  PIN rq[122]
    DIRECTION INPUT ;
    USE SIGNAL ;
    PORT
      LAYER M5 ;
        RECT 214.606 249.900 214.630 250.000 ;
    END
  END rq[122]
  PIN rq[121]
    DIRECTION INPUT ;
    USE SIGNAL ;
    PORT
      LAYER M5 ;
        RECT 214.510 249.900 214.534 250.000 ;
    END
  END rq[121]
  PIN rq[120]
    DIRECTION INPUT ;
    USE SIGNAL ;
    PORT
      LAYER M5 ;
        RECT 214.414 249.900 214.438 250.000 ;
    END
  END rq[120]
  PIN rq[119]
    DIRECTION INPUT ;
    USE SIGNAL ;
    PORT
      LAYER M5 ;
        RECT 214.318 249.900 214.342 250.000 ;
    END
  END rq[119]
  PIN rq[118]
    DIRECTION INPUT ;
    USE SIGNAL ;
    PORT
      LAYER M5 ;
        RECT 214.222 249.900 214.246 250.000 ;
    END
  END rq[118]
  PIN rq[117]
    DIRECTION INPUT ;
    USE SIGNAL ;
    PORT
      LAYER M5 ;
        RECT 214.126 249.900 214.150 250.000 ;
    END
  END rq[117]
  PIN rq[116]
    DIRECTION INPUT ;
    USE SIGNAL ;
    PORT
      LAYER M5 ;
        RECT 214.030 249.900 214.054 250.000 ;
    END
  END rq[116]
  PIN rq[115]
    DIRECTION INPUT ;
    USE SIGNAL ;
    PORT
      LAYER M5 ;
        RECT 213.934 249.900 213.958 250.000 ;
    END
  END rq[115]
  PIN rq[114]
    DIRECTION INPUT ;
    USE SIGNAL ;
    PORT
      LAYER M5 ;
        RECT 213.838 249.900 213.862 250.000 ;
    END
  END rq[114]
  PIN rq[113]
    DIRECTION INPUT ;
    USE SIGNAL ;
    PORT
      LAYER M5 ;
        RECT 213.742 249.900 213.766 250.000 ;
    END
  END rq[113]
  PIN rq[112]
    DIRECTION INPUT ;
    USE SIGNAL ;
    PORT
      LAYER M5 ;
        RECT 213.646 249.900 213.670 250.000 ;
    END
  END rq[112]
  PIN rq[111]
    DIRECTION INPUT ;
    USE SIGNAL ;
    PORT
      LAYER M5 ;
        RECT 213.550 249.900 213.574 250.000 ;
    END
  END rq[111]
  PIN rq[110]
    DIRECTION INPUT ;
    USE SIGNAL ;
    PORT
      LAYER M5 ;
        RECT 213.454 249.900 213.478 250.000 ;
    END
  END rq[110]
  PIN rq[109]
    DIRECTION INPUT ;
    USE SIGNAL ;
    PORT
      LAYER M5 ;
        RECT 213.358 249.900 213.382 250.000 ;
    END
  END rq[109]
  PIN rq[108]
    DIRECTION INPUT ;
    USE SIGNAL ;
    PORT
      LAYER M5 ;
        RECT 213.262 249.900 213.286 250.000 ;
    END
  END rq[108]
  PIN rq[107]
    DIRECTION INPUT ;
    USE SIGNAL ;
    PORT
      LAYER M5 ;
        RECT 213.166 249.900 213.190 250.000 ;
    END
  END rq[107]
  PIN rq[106]
    DIRECTION INPUT ;
    USE SIGNAL ;
    PORT
      LAYER M5 ;
        RECT 213.070 249.900 213.094 250.000 ;
    END
  END rq[106]
  PIN rq[105]
    DIRECTION INPUT ;
    USE SIGNAL ;
    PORT
      LAYER M5 ;
        RECT 212.974 249.900 212.998 250.000 ;
    END
  END rq[105]
  PIN rq[104]
    DIRECTION INPUT ;
    USE SIGNAL ;
    PORT
      LAYER M5 ;
        RECT 212.878 249.900 212.902 250.000 ;
    END
  END rq[104]
  PIN rq[103]
    DIRECTION INPUT ;
    USE SIGNAL ;
    PORT
      LAYER M5 ;
        RECT 212.782 249.900 212.806 250.000 ;
    END
  END rq[103]
  PIN rq[102]
    DIRECTION INPUT ;
    USE SIGNAL ;
    PORT
      LAYER M5 ;
        RECT 212.686 249.900 212.710 250.000 ;
    END
  END rq[102]
  PIN rq[101]
    DIRECTION INPUT ;
    USE SIGNAL ;
    PORT
      LAYER M5 ;
        RECT 212.590 249.900 212.614 250.000 ;
    END
  END rq[101]
  PIN rq[100]
    DIRECTION INPUT ;
    USE SIGNAL ;
    PORT
      LAYER M5 ;
        RECT 212.494 249.900 212.518 250.000 ;
    END
  END rq[100]
  PIN rq[99]
    DIRECTION INPUT ;
    USE SIGNAL ;
    PORT
      LAYER M5 ;
        RECT 212.398 249.900 212.422 250.000 ;
    END
  END rq[99]
  PIN rq[98]
    DIRECTION INPUT ;
    USE SIGNAL ;
    PORT
      LAYER M5 ;
        RECT 212.302 249.900 212.326 250.000 ;
    END
  END rq[98]
  PIN rq[97]
    DIRECTION INPUT ;
    USE SIGNAL ;
    PORT
      LAYER M5 ;
        RECT 212.206 249.900 212.230 250.000 ;
    END
  END rq[97]
  PIN rq[96]
    DIRECTION INPUT ;
    USE SIGNAL ;
    PORT
      LAYER M5 ;
        RECT 212.110 249.900 212.134 250.000 ;
    END
  END rq[96]
  PIN rq[95]
    DIRECTION INPUT ;
    USE SIGNAL ;
    PORT
      LAYER M5 ;
        RECT 212.014 249.900 212.038 250.000 ;
    END
  END rq[95]
  PIN rq[94]
    DIRECTION INPUT ;
    USE SIGNAL ;
    PORT
      LAYER M5 ;
        RECT 211.918 249.900 211.942 250.000 ;
    END
  END rq[94]
  PIN rq[93]
    DIRECTION INPUT ;
    USE SIGNAL ;
    PORT
      LAYER M5 ;
        RECT 211.822 249.900 211.846 250.000 ;
    END
  END rq[93]
  PIN rq[92]
    DIRECTION INPUT ;
    USE SIGNAL ;
    PORT
      LAYER M5 ;
        RECT 211.726 249.900 211.750 250.000 ;
    END
  END rq[92]
  PIN rq[91]
    DIRECTION INPUT ;
    USE SIGNAL ;
    PORT
      LAYER M5 ;
        RECT 211.630 249.900 211.654 250.000 ;
    END
  END rq[91]
  PIN rq[90]
    DIRECTION INPUT ;
    USE SIGNAL ;
    PORT
      LAYER M5 ;
        RECT 211.534 249.900 211.558 250.000 ;
    END
  END rq[90]
  PIN rq[89]
    DIRECTION INPUT ;
    USE SIGNAL ;
    PORT
      LAYER M5 ;
        RECT 211.438 249.900 211.462 250.000 ;
    END
  END rq[89]
  PIN rq[88]
    DIRECTION INPUT ;
    USE SIGNAL ;
    PORT
      LAYER M5 ;
        RECT 211.342 249.900 211.366 250.000 ;
    END
  END rq[88]
  PIN rq[87]
    DIRECTION INPUT ;
    USE SIGNAL ;
    PORT
      LAYER M5 ;
        RECT 211.246 249.900 211.270 250.000 ;
    END
  END rq[87]
  PIN rq[86]
    DIRECTION INPUT ;
    USE SIGNAL ;
    PORT
      LAYER M5 ;
        RECT 211.150 249.900 211.174 250.000 ;
    END
  END rq[86]
  PIN rq[85]
    DIRECTION INPUT ;
    USE SIGNAL ;
    PORT
      LAYER M5 ;
        RECT 211.054 249.900 211.078 250.000 ;
    END
  END rq[85]
  PIN rq[84]
    DIRECTION INPUT ;
    USE SIGNAL ;
    PORT
      LAYER M5 ;
        RECT 210.958 249.900 210.982 250.000 ;
    END
  END rq[84]
  PIN rq[83]
    DIRECTION INPUT ;
    USE SIGNAL ;
    PORT
      LAYER M5 ;
        RECT 210.862 249.900 210.886 250.000 ;
    END
  END rq[83]
  PIN rq[82]
    DIRECTION INPUT ;
    USE SIGNAL ;
    PORT
      LAYER M5 ;
        RECT 210.766 249.900 210.790 250.000 ;
    END
  END rq[82]
  PIN rq[81]
    DIRECTION INPUT ;
    USE SIGNAL ;
    PORT
      LAYER M5 ;
        RECT 210.670 249.900 210.694 250.000 ;
    END
  END rq[81]
  PIN rq[80]
    DIRECTION INPUT ;
    USE SIGNAL ;
    PORT
      LAYER M5 ;
        RECT 210.574 249.900 210.598 250.000 ;
    END
  END rq[80]
  PIN rq[79]
    DIRECTION INPUT ;
    USE SIGNAL ;
    PORT
      LAYER M5 ;
        RECT 210.478 249.900 210.502 250.000 ;
    END
  END rq[79]
  PIN rq[78]
    DIRECTION INPUT ;
    USE SIGNAL ;
    PORT
      LAYER M5 ;
        RECT 210.382 249.900 210.406 250.000 ;
    END
  END rq[78]
  PIN rq[77]
    DIRECTION INPUT ;
    USE SIGNAL ;
    PORT
      LAYER M5 ;
        RECT 210.286 249.900 210.310 250.000 ;
    END
  END rq[77]
  PIN rq[76]
    DIRECTION INPUT ;
    USE SIGNAL ;
    PORT
      LAYER M5 ;
        RECT 210.190 249.900 210.214 250.000 ;
    END
  END rq[76]
  PIN rq[75]
    DIRECTION INPUT ;
    USE SIGNAL ;
    PORT
      LAYER M5 ;
        RECT 210.094 249.900 210.118 250.000 ;
    END
  END rq[75]
  PIN rq[74]
    DIRECTION INPUT ;
    USE SIGNAL ;
    PORT
      LAYER M5 ;
        RECT 209.998 249.900 210.022 250.000 ;
    END
  END rq[74]
  PIN rq[73]
    DIRECTION INPUT ;
    USE SIGNAL ;
    PORT
      LAYER M5 ;
        RECT 209.902 249.900 209.926 250.000 ;
    END
  END rq[73]
  PIN rq[72]
    DIRECTION INPUT ;
    USE SIGNAL ;
    PORT
      LAYER M5 ;
        RECT 209.806 249.900 209.830 250.000 ;
    END
  END rq[72]
  PIN rq[71]
    DIRECTION INPUT ;
    USE SIGNAL ;
    PORT
      LAYER M5 ;
        RECT 209.710 249.900 209.734 250.000 ;
    END
  END rq[71]
  PIN rq[70]
    DIRECTION INPUT ;
    USE SIGNAL ;
    PORT
      LAYER M5 ;
        RECT 209.614 249.900 209.638 250.000 ;
    END
  END rq[70]
  PIN rq[69]
    DIRECTION INPUT ;
    USE SIGNAL ;
    PORT
      LAYER M5 ;
        RECT 209.518 249.900 209.542 250.000 ;
    END
  END rq[69]
  PIN rq[68]
    DIRECTION INPUT ;
    USE SIGNAL ;
    PORT
      LAYER M5 ;
        RECT 209.422 249.900 209.446 250.000 ;
    END
  END rq[68]
  PIN rq[67]
    DIRECTION INPUT ;
    USE SIGNAL ;
    PORT
      LAYER M5 ;
        RECT 209.326 249.900 209.350 250.000 ;
    END
  END rq[67]
  PIN rq[66]
    DIRECTION INPUT ;
    USE SIGNAL ;
    PORT
      LAYER M5 ;
        RECT 209.230 249.900 209.254 250.000 ;
    END
  END rq[66]
  PIN rq[65]
    DIRECTION INPUT ;
    USE SIGNAL ;
    PORT
      LAYER M5 ;
        RECT 209.134 249.900 209.158 250.000 ;
    END
  END rq[65]
  PIN rq[64]
    DIRECTION INPUT ;
    USE SIGNAL ;
    PORT
      LAYER M5 ;
        RECT 209.038 249.900 209.062 250.000 ;
    END
  END rq[64]
  PIN rq[63]
    DIRECTION INPUT ;
    USE SIGNAL ;
    PORT
      LAYER M5 ;
        RECT 208.942 249.900 208.966 250.000 ;
    END
  END rq[63]
  PIN rq[62]
    DIRECTION INPUT ;
    USE SIGNAL ;
    PORT
      LAYER M5 ;
        RECT 208.846 249.900 208.870 250.000 ;
    END
  END rq[62]
  PIN rq[61]
    DIRECTION INPUT ;
    USE SIGNAL ;
    PORT
      LAYER M5 ;
        RECT 208.750 249.900 208.774 250.000 ;
    END
  END rq[61]
  PIN rq[60]
    DIRECTION INPUT ;
    USE SIGNAL ;
    PORT
      LAYER M5 ;
        RECT 208.654 249.900 208.678 250.000 ;
    END
  END rq[60]
  PIN rq[59]
    DIRECTION INPUT ;
    USE SIGNAL ;
    PORT
      LAYER M5 ;
        RECT 208.558 249.900 208.582 250.000 ;
    END
  END rq[59]
  PIN rq[58]
    DIRECTION INPUT ;
    USE SIGNAL ;
    PORT
      LAYER M5 ;
        RECT 208.462 249.900 208.486 250.000 ;
    END
  END rq[58]
  PIN rq[57]
    DIRECTION INPUT ;
    USE SIGNAL ;
    PORT
      LAYER M5 ;
        RECT 208.366 249.900 208.390 250.000 ;
    END
  END rq[57]
  PIN rq[56]
    DIRECTION INPUT ;
    USE SIGNAL ;
    PORT
      LAYER M5 ;
        RECT 208.270 249.900 208.294 250.000 ;
    END
  END rq[56]
  PIN rq[55]
    DIRECTION INPUT ;
    USE SIGNAL ;
    PORT
      LAYER M5 ;
        RECT 208.174 249.900 208.198 250.000 ;
    END
  END rq[55]
  PIN rq[54]
    DIRECTION INPUT ;
    USE SIGNAL ;
    PORT
      LAYER M5 ;
        RECT 208.078 249.900 208.102 250.000 ;
    END
  END rq[54]
  PIN rq[53]
    DIRECTION INPUT ;
    USE SIGNAL ;
    PORT
      LAYER M5 ;
        RECT 207.982 249.900 208.006 250.000 ;
    END
  END rq[53]
  PIN rq[52]
    DIRECTION INPUT ;
    USE SIGNAL ;
    PORT
      LAYER M5 ;
        RECT 207.886 249.900 207.910 250.000 ;
    END
  END rq[52]
  PIN rq[51]
    DIRECTION INPUT ;
    USE SIGNAL ;
    PORT
      LAYER M5 ;
        RECT 207.790 249.900 207.814 250.000 ;
    END
  END rq[51]
  PIN rq[50]
    DIRECTION INPUT ;
    USE SIGNAL ;
    PORT
      LAYER M5 ;
        RECT 207.694 249.900 207.718 250.000 ;
    END
  END rq[50]
  PIN rq[49]
    DIRECTION INPUT ;
    USE SIGNAL ;
    PORT
      LAYER M5 ;
        RECT 207.598 249.900 207.622 250.000 ;
    END
  END rq[49]
  PIN rq[48]
    DIRECTION INPUT ;
    USE SIGNAL ;
    PORT
      LAYER M5 ;
        RECT 207.502 249.900 207.526 250.000 ;
    END
  END rq[48]
  PIN rq[47]
    DIRECTION INPUT ;
    USE SIGNAL ;
    PORT
      LAYER M5 ;
        RECT 207.406 249.900 207.430 250.000 ;
    END
  END rq[47]
  PIN rq[46]
    DIRECTION INPUT ;
    USE SIGNAL ;
    PORT
      LAYER M5 ;
        RECT 207.310 249.900 207.334 250.000 ;
    END
  END rq[46]
  PIN rq[45]
    DIRECTION INPUT ;
    USE SIGNAL ;
    PORT
      LAYER M5 ;
        RECT 207.214 249.900 207.238 250.000 ;
    END
  END rq[45]
  PIN rq[44]
    DIRECTION INPUT ;
    USE SIGNAL ;
    PORT
      LAYER M5 ;
        RECT 207.118 249.900 207.142 250.000 ;
    END
  END rq[44]
  PIN rq[43]
    DIRECTION INPUT ;
    USE SIGNAL ;
    PORT
      LAYER M5 ;
        RECT 207.022 249.900 207.046 250.000 ;
    END
  END rq[43]
  PIN rq[42]
    DIRECTION INPUT ;
    USE SIGNAL ;
    PORT
      LAYER M5 ;
        RECT 206.926 249.900 206.950 250.000 ;
    END
  END rq[42]
  PIN rq[41]
    DIRECTION INPUT ;
    USE SIGNAL ;
    PORT
      LAYER M5 ;
        RECT 206.830 249.900 206.854 250.000 ;
    END
  END rq[41]
  PIN rq[40]
    DIRECTION INPUT ;
    USE SIGNAL ;
    PORT
      LAYER M5 ;
        RECT 206.734 249.900 206.758 250.000 ;
    END
  END rq[40]
  PIN rq[39]
    DIRECTION INPUT ;
    USE SIGNAL ;
    PORT
      LAYER M5 ;
        RECT 206.638 249.900 206.662 250.000 ;
    END
  END rq[39]
  PIN rq[38]
    DIRECTION INPUT ;
    USE SIGNAL ;
    PORT
      LAYER M5 ;
        RECT 206.542 249.900 206.566 250.000 ;
    END
  END rq[38]
  PIN rq[37]
    DIRECTION INPUT ;
    USE SIGNAL ;
    PORT
      LAYER M5 ;
        RECT 206.446 249.900 206.470 250.000 ;
    END
  END rq[37]
  PIN rq[36]
    DIRECTION INPUT ;
    USE SIGNAL ;
    PORT
      LAYER M5 ;
        RECT 206.350 249.900 206.374 250.000 ;
    END
  END rq[36]
  PIN rq[35]
    DIRECTION INPUT ;
    USE SIGNAL ;
    PORT
      LAYER M5 ;
        RECT 206.254 249.900 206.278 250.000 ;
    END
  END rq[35]
  PIN rq[34]
    DIRECTION INPUT ;
    USE SIGNAL ;
    PORT
      LAYER M5 ;
        RECT 206.158 249.900 206.182 250.000 ;
    END
  END rq[34]
  PIN rq[33]
    DIRECTION INPUT ;
    USE SIGNAL ;
    PORT
      LAYER M5 ;
        RECT 206.062 249.900 206.086 250.000 ;
    END
  END rq[33]
  PIN rq[32]
    DIRECTION INPUT ;
    USE SIGNAL ;
    PORT
      LAYER M5 ;
        RECT 205.966 249.900 205.990 250.000 ;
    END
  END rq[32]
  PIN rq[31]
    DIRECTION INPUT ;
    USE SIGNAL ;
    PORT
      LAYER M5 ;
        RECT 205.870 249.900 205.894 250.000 ;
    END
  END rq[31]
  PIN rq[30]
    DIRECTION INPUT ;
    USE SIGNAL ;
    PORT
      LAYER M5 ;
        RECT 205.774 249.900 205.798 250.000 ;
    END
  END rq[30]
  PIN rq[29]
    DIRECTION INPUT ;
    USE SIGNAL ;
    PORT
      LAYER M5 ;
        RECT 205.678 249.900 205.702 250.000 ;
    END
  END rq[29]
  PIN rq[28]
    DIRECTION INPUT ;
    USE SIGNAL ;
    PORT
      LAYER M5 ;
        RECT 205.582 249.900 205.606 250.000 ;
    END
  END rq[28]
  PIN rq[27]
    DIRECTION INPUT ;
    USE SIGNAL ;
    PORT
      LAYER M5 ;
        RECT 205.486 249.900 205.510 250.000 ;
    END
  END rq[27]
  PIN rq[26]
    DIRECTION INPUT ;
    USE SIGNAL ;
    PORT
      LAYER M5 ;
        RECT 205.390 249.900 205.414 250.000 ;
    END
  END rq[26]
  PIN rq[25]
    DIRECTION INPUT ;
    USE SIGNAL ;
    PORT
      LAYER M5 ;
        RECT 205.294 249.900 205.318 250.000 ;
    END
  END rq[25]
  PIN rq[24]
    DIRECTION INPUT ;
    USE SIGNAL ;
    PORT
      LAYER M5 ;
        RECT 205.198 249.900 205.222 250.000 ;
    END
  END rq[24]
  PIN rq[23]
    DIRECTION INPUT ;
    USE SIGNAL ;
    PORT
      LAYER M5 ;
        RECT 205.102 249.900 205.126 250.000 ;
    END
  END rq[23]
  PIN rq[22]
    DIRECTION INPUT ;
    USE SIGNAL ;
    PORT
      LAYER M5 ;
        RECT 205.006 249.900 205.030 250.000 ;
    END
  END rq[22]
  PIN rq[21]
    DIRECTION INPUT ;
    USE SIGNAL ;
    PORT
      LAYER M5 ;
        RECT 204.910 249.900 204.934 250.000 ;
    END
  END rq[21]
  PIN rq[20]
    DIRECTION INPUT ;
    USE SIGNAL ;
    PORT
      LAYER M5 ;
        RECT 204.814 249.900 204.838 250.000 ;
    END
  END rq[20]
  PIN rq[19]
    DIRECTION INPUT ;
    USE SIGNAL ;
    PORT
      LAYER M5 ;
        RECT 204.718 249.900 204.742 250.000 ;
    END
  END rq[19]
  PIN rq[18]
    DIRECTION INPUT ;
    USE SIGNAL ;
    PORT
      LAYER M5 ;
        RECT 204.622 249.900 204.646 250.000 ;
    END
  END rq[18]
  PIN rq[17]
    DIRECTION INPUT ;
    USE SIGNAL ;
    PORT
      LAYER M5 ;
        RECT 204.526 249.900 204.550 250.000 ;
    END
  END rq[17]
  PIN rq[16]
    DIRECTION INPUT ;
    USE SIGNAL ;
    PORT
      LAYER M5 ;
        RECT 204.430 249.900 204.454 250.000 ;
    END
  END rq[16]
  PIN rq[15]
    DIRECTION INPUT ;
    USE SIGNAL ;
    PORT
      LAYER M5 ;
        RECT 204.334 249.900 204.358 250.000 ;
    END
  END rq[15]
  PIN rq[14]
    DIRECTION INPUT ;
    USE SIGNAL ;
    PORT
      LAYER M5 ;
        RECT 204.238 249.900 204.262 250.000 ;
    END
  END rq[14]
  PIN rq[13]
    DIRECTION INPUT ;
    USE SIGNAL ;
    PORT
      LAYER M5 ;
        RECT 204.142 249.900 204.166 250.000 ;
    END
  END rq[13]
  PIN rq[12]
    DIRECTION INPUT ;
    USE SIGNAL ;
    PORT
      LAYER M5 ;
        RECT 204.046 249.900 204.070 250.000 ;
    END
  END rq[12]
  PIN rq[11]
    DIRECTION INPUT ;
    USE SIGNAL ;
    PORT
      LAYER M5 ;
        RECT 203.950 249.900 203.974 250.000 ;
    END
  END rq[11]
  PIN rq[10]
    DIRECTION INPUT ;
    USE SIGNAL ;
    PORT
      LAYER M5 ;
        RECT 203.854 249.900 203.878 250.000 ;
    END
  END rq[10]
  PIN rq[9]
    DIRECTION INPUT ;
    USE SIGNAL ;
    PORT
      LAYER M5 ;
        RECT 203.758 249.900 203.782 250.000 ;
    END
  END rq[9]
  PIN rq[8]
    DIRECTION INPUT ;
    USE SIGNAL ;
    PORT
      LAYER M5 ;
        RECT 203.662 249.900 203.686 250.000 ;
    END
  END rq[8]
  PIN rq[7]
    DIRECTION INPUT ;
    USE SIGNAL ;
    PORT
      LAYER M5 ;
        RECT 203.566 249.900 203.590 250.000 ;
    END
  END rq[7]
  PIN rq[6]
    DIRECTION INPUT ;
    USE SIGNAL ;
    PORT
      LAYER M5 ;
        RECT 203.470 249.900 203.494 250.000 ;
    END
  END rq[6]
  PIN rq[5]
    DIRECTION INPUT ;
    USE SIGNAL ;
    PORT
      LAYER M5 ;
        RECT 203.374 249.900 203.398 250.000 ;
    END
  END rq[5]
  PIN rq[4]
    DIRECTION INPUT ;
    USE SIGNAL ;
    PORT
      LAYER M5 ;
        RECT 203.278 249.900 203.302 250.000 ;
    END
  END rq[4]
  PIN rq[3]
    DIRECTION INPUT ;
    USE SIGNAL ;
    PORT
      LAYER M5 ;
        RECT 203.182 249.900 203.206 250.000 ;
    END
  END rq[3]
  PIN rq[2]
    DIRECTION INPUT ;
    USE SIGNAL ;
    PORT
      LAYER M5 ;
        RECT 203.086 249.900 203.110 250.000 ;
    END
  END rq[2]
  PIN rq[1]
    DIRECTION INPUT ;
    USE SIGNAL ;
    PORT
      LAYER M5 ;
        RECT 202.990 249.900 203.014 250.000 ;
    END
  END rq[1]
  PIN rq[0]
    DIRECTION INPUT ;
    USE SIGNAL ;
    PORT
      LAYER M5 ;
        RECT 202.894 249.900 202.918 250.000 ;
    END
  END rq[0]
  PIN rd[561]
    DIRECTION OUTPUT ;
    USE SIGNAL ;
    PORT
      LAYER M5 ;
        RECT 322.510 249.900 322.534 250.000 ;
    END
  END rd[561]
  PIN rd[560]
    DIRECTION OUTPUT ;
    USE SIGNAL ;
    PORT
      LAYER M5 ;
        RECT 322.414 249.900 322.438 250.000 ;
    END
  END rd[560]
  PIN rd[559]
    DIRECTION OUTPUT ;
    USE SIGNAL ;
    PORT
      LAYER M5 ;
        RECT 322.318 249.900 322.342 250.000 ;
    END
  END rd[559]
  PIN rd[558]
    DIRECTION OUTPUT ;
    USE SIGNAL ;
    PORT
      LAYER M5 ;
        RECT 322.222 249.900 322.246 250.000 ;
    END
  END rd[558]
  PIN rd[557]
    DIRECTION OUTPUT ;
    USE SIGNAL ;
    PORT
      LAYER M5 ;
        RECT 322.126 249.900 322.150 250.000 ;
    END
  END rd[557]
  PIN rd[556]
    DIRECTION OUTPUT ;
    USE SIGNAL ;
    PORT
      LAYER M5 ;
        RECT 322.030 249.900 322.054 250.000 ;
    END
  END rd[556]
  PIN rd[555]
    DIRECTION OUTPUT ;
    USE SIGNAL ;
    PORT
      LAYER M5 ;
        RECT 321.934 249.900 321.958 250.000 ;
    END
  END rd[555]
  PIN rd[554]
    DIRECTION OUTPUT ;
    USE SIGNAL ;
    PORT
      LAYER M5 ;
        RECT 321.838 249.900 321.862 250.000 ;
    END
  END rd[554]
  PIN rd[553]
    DIRECTION OUTPUT ;
    USE SIGNAL ;
    PORT
      LAYER M5 ;
        RECT 321.742 249.900 321.766 250.000 ;
    END
  END rd[553]
  PIN rd[552]
    DIRECTION OUTPUT ;
    USE SIGNAL ;
    PORT
      LAYER M5 ;
        RECT 321.646 249.900 321.670 250.000 ;
    END
  END rd[552]
  PIN rd[551]
    DIRECTION OUTPUT ;
    USE SIGNAL ;
    PORT
      LAYER M5 ;
        RECT 321.550 249.900 321.574 250.000 ;
    END
  END rd[551]
  PIN rd[550]
    DIRECTION OUTPUT ;
    USE SIGNAL ;
    PORT
      LAYER M5 ;
        RECT 321.454 249.900 321.478 250.000 ;
    END
  END rd[550]
  PIN rd[549]
    DIRECTION OUTPUT ;
    USE SIGNAL ;
    PORT
      LAYER M5 ;
        RECT 321.358 249.900 321.382 250.000 ;
    END
  END rd[549]
  PIN rd[548]
    DIRECTION OUTPUT ;
    USE SIGNAL ;
    PORT
      LAYER M5 ;
        RECT 321.262 249.900 321.286 250.000 ;
    END
  END rd[548]
  PIN rd[547]
    DIRECTION OUTPUT ;
    USE SIGNAL ;
    PORT
      LAYER M5 ;
        RECT 321.166 249.900 321.190 250.000 ;
    END
  END rd[547]
  PIN rd[546]
    DIRECTION OUTPUT ;
    USE SIGNAL ;
    PORT
      LAYER M5 ;
        RECT 321.070 249.900 321.094 250.000 ;
    END
  END rd[546]
  PIN rd[545]
    DIRECTION OUTPUT ;
    USE SIGNAL ;
    PORT
      LAYER M5 ;
        RECT 320.974 249.900 320.998 250.000 ;
    END
  END rd[545]
  PIN rd[544]
    DIRECTION OUTPUT ;
    USE SIGNAL ;
    PORT
      LAYER M5 ;
        RECT 320.878 249.900 320.902 250.000 ;
    END
  END rd[544]
  PIN rd[543]
    DIRECTION OUTPUT ;
    USE SIGNAL ;
    PORT
      LAYER M5 ;
        RECT 320.782 249.900 320.806 250.000 ;
    END
  END rd[543]
  PIN rd[542]
    DIRECTION OUTPUT ;
    USE SIGNAL ;
    PORT
      LAYER M5 ;
        RECT 320.686 249.900 320.710 250.000 ;
    END
  END rd[542]
  PIN rd[541]
    DIRECTION OUTPUT ;
    USE SIGNAL ;
    PORT
      LAYER M5 ;
        RECT 320.590 249.900 320.614 250.000 ;
    END
  END rd[541]
  PIN rd[540]
    DIRECTION OUTPUT ;
    USE SIGNAL ;
    PORT
      LAYER M5 ;
        RECT 320.494 249.900 320.518 250.000 ;
    END
  END rd[540]
  PIN rd[539]
    DIRECTION OUTPUT ;
    USE SIGNAL ;
    PORT
      LAYER M5 ;
        RECT 320.398 249.900 320.422 250.000 ;
    END
  END rd[539]
  PIN rd[538]
    DIRECTION OUTPUT ;
    USE SIGNAL ;
    PORT
      LAYER M5 ;
        RECT 320.302 249.900 320.326 250.000 ;
    END
  END rd[538]
  PIN rd[537]
    DIRECTION OUTPUT ;
    USE SIGNAL ;
    PORT
      LAYER M5 ;
        RECT 320.206 249.900 320.230 250.000 ;
    END
  END rd[537]
  PIN rd[536]
    DIRECTION OUTPUT ;
    USE SIGNAL ;
    PORT
      LAYER M5 ;
        RECT 320.110 249.900 320.134 250.000 ;
    END
  END rd[536]
  PIN rd[535]
    DIRECTION OUTPUT ;
    USE SIGNAL ;
    PORT
      LAYER M5 ;
        RECT 320.014 249.900 320.038 250.000 ;
    END
  END rd[535]
  PIN rd[534]
    DIRECTION OUTPUT ;
    USE SIGNAL ;
    PORT
      LAYER M5 ;
        RECT 319.918 249.900 319.942 250.000 ;
    END
  END rd[534]
  PIN rd[533]
    DIRECTION OUTPUT ;
    USE SIGNAL ;
    PORT
      LAYER M5 ;
        RECT 319.822 249.900 319.846 250.000 ;
    END
  END rd[533]
  PIN rd[532]
    DIRECTION OUTPUT ;
    USE SIGNAL ;
    PORT
      LAYER M5 ;
        RECT 319.726 249.900 319.750 250.000 ;
    END
  END rd[532]
  PIN rd[531]
    DIRECTION OUTPUT ;
    USE SIGNAL ;
    PORT
      LAYER M5 ;
        RECT 319.630 249.900 319.654 250.000 ;
    END
  END rd[531]
  PIN rd[530]
    DIRECTION OUTPUT ;
    USE SIGNAL ;
    PORT
      LAYER M5 ;
        RECT 319.534 249.900 319.558 250.000 ;
    END
  END rd[530]
  PIN rd[529]
    DIRECTION OUTPUT ;
    USE SIGNAL ;
    PORT
      LAYER M5 ;
        RECT 319.438 249.900 319.462 250.000 ;
    END
  END rd[529]
  PIN rd[528]
    DIRECTION OUTPUT ;
    USE SIGNAL ;
    PORT
      LAYER M5 ;
        RECT 319.342 249.900 319.366 250.000 ;
    END
  END rd[528]
  PIN rd[527]
    DIRECTION OUTPUT ;
    USE SIGNAL ;
    PORT
      LAYER M5 ;
        RECT 319.246 249.900 319.270 250.000 ;
    END
  END rd[527]
  PIN rd[526]
    DIRECTION OUTPUT ;
    USE SIGNAL ;
    PORT
      LAYER M5 ;
        RECT 319.150 249.900 319.174 250.000 ;
    END
  END rd[526]
  PIN rd[525]
    DIRECTION OUTPUT ;
    USE SIGNAL ;
    PORT
      LAYER M5 ;
        RECT 319.054 249.900 319.078 250.000 ;
    END
  END rd[525]
  PIN rd[524]
    DIRECTION OUTPUT ;
    USE SIGNAL ;
    PORT
      LAYER M5 ;
        RECT 318.958 249.900 318.982 250.000 ;
    END
  END rd[524]
  PIN rd[523]
    DIRECTION OUTPUT ;
    USE SIGNAL ;
    PORT
      LAYER M5 ;
        RECT 318.862 249.900 318.886 250.000 ;
    END
  END rd[523]
  PIN rd[522]
    DIRECTION OUTPUT ;
    USE SIGNAL ;
    PORT
      LAYER M5 ;
        RECT 318.766 249.900 318.790 250.000 ;
    END
  END rd[522]
  PIN rd[521]
    DIRECTION OUTPUT ;
    USE SIGNAL ;
    PORT
      LAYER M5 ;
        RECT 318.670 249.900 318.694 250.000 ;
    END
  END rd[521]
  PIN rd[520]
    DIRECTION OUTPUT ;
    USE SIGNAL ;
    PORT
      LAYER M5 ;
        RECT 318.574 249.900 318.598 250.000 ;
    END
  END rd[520]
  PIN rd[519]
    DIRECTION OUTPUT ;
    USE SIGNAL ;
    PORT
      LAYER M5 ;
        RECT 318.478 249.900 318.502 250.000 ;
    END
  END rd[519]
  PIN rd[518]
    DIRECTION OUTPUT ;
    USE SIGNAL ;
    PORT
      LAYER M5 ;
        RECT 318.382 249.900 318.406 250.000 ;
    END
  END rd[518]
  PIN rd[517]
    DIRECTION OUTPUT ;
    USE SIGNAL ;
    PORT
      LAYER M5 ;
        RECT 318.286 249.900 318.310 250.000 ;
    END
  END rd[517]
  PIN rd[516]
    DIRECTION OUTPUT ;
    USE SIGNAL ;
    PORT
      LAYER M5 ;
        RECT 318.190 249.900 318.214 250.000 ;
    END
  END rd[516]
  PIN rd[515]
    DIRECTION OUTPUT ;
    USE SIGNAL ;
    PORT
      LAYER M5 ;
        RECT 318.094 249.900 318.118 250.000 ;
    END
  END rd[515]
  PIN rd[514]
    DIRECTION OUTPUT ;
    USE SIGNAL ;
    PORT
      LAYER M5 ;
        RECT 317.998 249.900 318.022 250.000 ;
    END
  END rd[514]
  PIN rd[513]
    DIRECTION OUTPUT ;
    USE SIGNAL ;
    PORT
      LAYER M5 ;
        RECT 317.902 249.900 317.926 250.000 ;
    END
  END rd[513]
  PIN rd[512]
    DIRECTION OUTPUT ;
    USE SIGNAL ;
    PORT
      LAYER M5 ;
        RECT 317.806 249.900 317.830 250.000 ;
    END
  END rd[512]
  PIN rd[511]
    DIRECTION OUTPUT ;
    USE SIGNAL ;
    PORT
      LAYER M5 ;
        RECT 317.710 249.900 317.734 250.000 ;
    END
  END rd[511]
  PIN rd[510]
    DIRECTION OUTPUT ;
    USE SIGNAL ;
    PORT
      LAYER M5 ;
        RECT 317.614 249.900 317.638 250.000 ;
    END
  END rd[510]
  PIN rd[509]
    DIRECTION OUTPUT ;
    USE SIGNAL ;
    PORT
      LAYER M5 ;
        RECT 317.518 249.900 317.542 250.000 ;
    END
  END rd[509]
  PIN rd[508]
    DIRECTION OUTPUT ;
    USE SIGNAL ;
    PORT
      LAYER M5 ;
        RECT 317.422 249.900 317.446 250.000 ;
    END
  END rd[508]
  PIN rd[507]
    DIRECTION OUTPUT ;
    USE SIGNAL ;
    PORT
      LAYER M5 ;
        RECT 317.326 249.900 317.350 250.000 ;
    END
  END rd[507]
  PIN rd[506]
    DIRECTION OUTPUT ;
    USE SIGNAL ;
    PORT
      LAYER M5 ;
        RECT 317.230 249.900 317.254 250.000 ;
    END
  END rd[506]
  PIN rd[505]
    DIRECTION OUTPUT ;
    USE SIGNAL ;
    PORT
      LAYER M5 ;
        RECT 317.134 249.900 317.158 250.000 ;
    END
  END rd[505]
  PIN rd[504]
    DIRECTION OUTPUT ;
    USE SIGNAL ;
    PORT
      LAYER M5 ;
        RECT 317.038 249.900 317.062 250.000 ;
    END
  END rd[504]
  PIN rd[503]
    DIRECTION OUTPUT ;
    USE SIGNAL ;
    PORT
      LAYER M5 ;
        RECT 316.942 249.900 316.966 250.000 ;
    END
  END rd[503]
  PIN rd[502]
    DIRECTION OUTPUT ;
    USE SIGNAL ;
    PORT
      LAYER M5 ;
        RECT 316.846 249.900 316.870 250.000 ;
    END
  END rd[502]
  PIN rd[501]
    DIRECTION OUTPUT ;
    USE SIGNAL ;
    PORT
      LAYER M5 ;
        RECT 316.750 249.900 316.774 250.000 ;
    END
  END rd[501]
  PIN rd[500]
    DIRECTION OUTPUT ;
    USE SIGNAL ;
    PORT
      LAYER M5 ;
        RECT 316.654 249.900 316.678 250.000 ;
    END
  END rd[500]
  PIN rd[499]
    DIRECTION OUTPUT ;
    USE SIGNAL ;
    PORT
      LAYER M5 ;
        RECT 316.558 249.900 316.582 250.000 ;
    END
  END rd[499]
  PIN rd[498]
    DIRECTION OUTPUT ;
    USE SIGNAL ;
    PORT
      LAYER M5 ;
        RECT 316.462 249.900 316.486 250.000 ;
    END
  END rd[498]
  PIN rd[497]
    DIRECTION OUTPUT ;
    USE SIGNAL ;
    PORT
      LAYER M5 ;
        RECT 316.366 249.900 316.390 250.000 ;
    END
  END rd[497]
  PIN rd[496]
    DIRECTION OUTPUT ;
    USE SIGNAL ;
    PORT
      LAYER M5 ;
        RECT 316.270 249.900 316.294 250.000 ;
    END
  END rd[496]
  PIN rd[495]
    DIRECTION OUTPUT ;
    USE SIGNAL ;
    PORT
      LAYER M5 ;
        RECT 316.174 249.900 316.198 250.000 ;
    END
  END rd[495]
  PIN rd[494]
    DIRECTION OUTPUT ;
    USE SIGNAL ;
    PORT
      LAYER M5 ;
        RECT 316.078 249.900 316.102 250.000 ;
    END
  END rd[494]
  PIN rd[493]
    DIRECTION OUTPUT ;
    USE SIGNAL ;
    PORT
      LAYER M5 ;
        RECT 315.982 249.900 316.006 250.000 ;
    END
  END rd[493]
  PIN rd[492]
    DIRECTION OUTPUT ;
    USE SIGNAL ;
    PORT
      LAYER M5 ;
        RECT 315.886 249.900 315.910 250.000 ;
    END
  END rd[492]
  PIN rd[491]
    DIRECTION OUTPUT ;
    USE SIGNAL ;
    PORT
      LAYER M5 ;
        RECT 315.790 249.900 315.814 250.000 ;
    END
  END rd[491]
  PIN rd[490]
    DIRECTION OUTPUT ;
    USE SIGNAL ;
    PORT
      LAYER M5 ;
        RECT 315.694 249.900 315.718 250.000 ;
    END
  END rd[490]
  PIN rd[489]
    DIRECTION OUTPUT ;
    USE SIGNAL ;
    PORT
      LAYER M5 ;
        RECT 315.598 249.900 315.622 250.000 ;
    END
  END rd[489]
  PIN rd[488]
    DIRECTION OUTPUT ;
    USE SIGNAL ;
    PORT
      LAYER M5 ;
        RECT 315.502 249.900 315.526 250.000 ;
    END
  END rd[488]
  PIN rd[487]
    DIRECTION OUTPUT ;
    USE SIGNAL ;
    PORT
      LAYER M5 ;
        RECT 315.406 249.900 315.430 250.000 ;
    END
  END rd[487]
  PIN rd[486]
    DIRECTION OUTPUT ;
    USE SIGNAL ;
    PORT
      LAYER M5 ;
        RECT 315.310 249.900 315.334 250.000 ;
    END
  END rd[486]
  PIN rd[485]
    DIRECTION OUTPUT ;
    USE SIGNAL ;
    PORT
      LAYER M5 ;
        RECT 315.214 249.900 315.238 250.000 ;
    END
  END rd[485]
  PIN rd[484]
    DIRECTION OUTPUT ;
    USE SIGNAL ;
    PORT
      LAYER M5 ;
        RECT 315.118 249.900 315.142 250.000 ;
    END
  END rd[484]
  PIN rd[483]
    DIRECTION OUTPUT ;
    USE SIGNAL ;
    PORT
      LAYER M5 ;
        RECT 315.022 249.900 315.046 250.000 ;
    END
  END rd[483]
  PIN rd[482]
    DIRECTION OUTPUT ;
    USE SIGNAL ;
    PORT
      LAYER M5 ;
        RECT 314.926 249.900 314.950 250.000 ;
    END
  END rd[482]
  PIN rd[481]
    DIRECTION OUTPUT ;
    USE SIGNAL ;
    PORT
      LAYER M5 ;
        RECT 314.830 249.900 314.854 250.000 ;
    END
  END rd[481]
  PIN rd[480]
    DIRECTION OUTPUT ;
    USE SIGNAL ;
    PORT
      LAYER M5 ;
        RECT 314.734 249.900 314.758 250.000 ;
    END
  END rd[480]
  PIN rd[479]
    DIRECTION OUTPUT ;
    USE SIGNAL ;
    PORT
      LAYER M5 ;
        RECT 314.638 249.900 314.662 250.000 ;
    END
  END rd[479]
  PIN rd[478]
    DIRECTION OUTPUT ;
    USE SIGNAL ;
    PORT
      LAYER M5 ;
        RECT 314.542 249.900 314.566 250.000 ;
    END
  END rd[478]
  PIN rd[477]
    DIRECTION OUTPUT ;
    USE SIGNAL ;
    PORT
      LAYER M5 ;
        RECT 314.446 249.900 314.470 250.000 ;
    END
  END rd[477]
  PIN rd[476]
    DIRECTION OUTPUT ;
    USE SIGNAL ;
    PORT
      LAYER M5 ;
        RECT 314.350 249.900 314.374 250.000 ;
    END
  END rd[476]
  PIN rd[475]
    DIRECTION OUTPUT ;
    USE SIGNAL ;
    PORT
      LAYER M5 ;
        RECT 314.254 249.900 314.278 250.000 ;
    END
  END rd[475]
  PIN rd[474]
    DIRECTION OUTPUT ;
    USE SIGNAL ;
    PORT
      LAYER M5 ;
        RECT 314.158 249.900 314.182 250.000 ;
    END
  END rd[474]
  PIN rd[473]
    DIRECTION OUTPUT ;
    USE SIGNAL ;
    PORT
      LAYER M5 ;
        RECT 314.062 249.900 314.086 250.000 ;
    END
  END rd[473]
  PIN rd[472]
    DIRECTION OUTPUT ;
    USE SIGNAL ;
    PORT
      LAYER M5 ;
        RECT 313.966 249.900 313.990 250.000 ;
    END
  END rd[472]
  PIN rd[471]
    DIRECTION OUTPUT ;
    USE SIGNAL ;
    PORT
      LAYER M5 ;
        RECT 313.870 249.900 313.894 250.000 ;
    END
  END rd[471]
  PIN rd[470]
    DIRECTION OUTPUT ;
    USE SIGNAL ;
    PORT
      LAYER M5 ;
        RECT 313.774 249.900 313.798 250.000 ;
    END
  END rd[470]
  PIN rd[469]
    DIRECTION OUTPUT ;
    USE SIGNAL ;
    PORT
      LAYER M5 ;
        RECT 313.678 249.900 313.702 250.000 ;
    END
  END rd[469]
  PIN rd[468]
    DIRECTION OUTPUT ;
    USE SIGNAL ;
    PORT
      LAYER M5 ;
        RECT 313.582 249.900 313.606 250.000 ;
    END
  END rd[468]
  PIN rd[467]
    DIRECTION OUTPUT ;
    USE SIGNAL ;
    PORT
      LAYER M5 ;
        RECT 313.486 249.900 313.510 250.000 ;
    END
  END rd[467]
  PIN rd[466]
    DIRECTION OUTPUT ;
    USE SIGNAL ;
    PORT
      LAYER M5 ;
        RECT 313.390 249.900 313.414 250.000 ;
    END
  END rd[466]
  PIN rd[465]
    DIRECTION OUTPUT ;
    USE SIGNAL ;
    PORT
      LAYER M5 ;
        RECT 313.294 249.900 313.318 250.000 ;
    END
  END rd[465]
  PIN rd[464]
    DIRECTION OUTPUT ;
    USE SIGNAL ;
    PORT
      LAYER M5 ;
        RECT 313.198 249.900 313.222 250.000 ;
    END
  END rd[464]
  PIN rd[463]
    DIRECTION OUTPUT ;
    USE SIGNAL ;
    PORT
      LAYER M5 ;
        RECT 313.102 249.900 313.126 250.000 ;
    END
  END rd[463]
  PIN rd[462]
    DIRECTION OUTPUT ;
    USE SIGNAL ;
    PORT
      LAYER M5 ;
        RECT 313.006 249.900 313.030 250.000 ;
    END
  END rd[462]
  PIN rd[461]
    DIRECTION OUTPUT ;
    USE SIGNAL ;
    PORT
      LAYER M5 ;
        RECT 312.910 249.900 312.934 250.000 ;
    END
  END rd[461]
  PIN rd[460]
    DIRECTION OUTPUT ;
    USE SIGNAL ;
    PORT
      LAYER M5 ;
        RECT 312.814 249.900 312.838 250.000 ;
    END
  END rd[460]
  PIN rd[459]
    DIRECTION OUTPUT ;
    USE SIGNAL ;
    PORT
      LAYER M5 ;
        RECT 312.718 249.900 312.742 250.000 ;
    END
  END rd[459]
  PIN rd[458]
    DIRECTION OUTPUT ;
    USE SIGNAL ;
    PORT
      LAYER M5 ;
        RECT 312.622 249.900 312.646 250.000 ;
    END
  END rd[458]
  PIN rd[457]
    DIRECTION OUTPUT ;
    USE SIGNAL ;
    PORT
      LAYER M5 ;
        RECT 312.526 249.900 312.550 250.000 ;
    END
  END rd[457]
  PIN rd[456]
    DIRECTION OUTPUT ;
    USE SIGNAL ;
    PORT
      LAYER M5 ;
        RECT 312.430 249.900 312.454 250.000 ;
    END
  END rd[456]
  PIN rd[455]
    DIRECTION OUTPUT ;
    USE SIGNAL ;
    PORT
      LAYER M5 ;
        RECT 312.334 249.900 312.358 250.000 ;
    END
  END rd[455]
  PIN rd[454]
    DIRECTION OUTPUT ;
    USE SIGNAL ;
    PORT
      LAYER M5 ;
        RECT 312.238 249.900 312.262 250.000 ;
    END
  END rd[454]
  PIN rd[453]
    DIRECTION OUTPUT ;
    USE SIGNAL ;
    PORT
      LAYER M5 ;
        RECT 312.142 249.900 312.166 250.000 ;
    END
  END rd[453]
  PIN rd[452]
    DIRECTION OUTPUT ;
    USE SIGNAL ;
    PORT
      LAYER M5 ;
        RECT 312.046 249.900 312.070 250.000 ;
    END
  END rd[452]
  PIN rd[451]
    DIRECTION OUTPUT ;
    USE SIGNAL ;
    PORT
      LAYER M5 ;
        RECT 311.950 249.900 311.974 250.000 ;
    END
  END rd[451]
  PIN rd[450]
    DIRECTION OUTPUT ;
    USE SIGNAL ;
    PORT
      LAYER M5 ;
        RECT 311.854 249.900 311.878 250.000 ;
    END
  END rd[450]
  PIN rd[449]
    DIRECTION OUTPUT ;
    USE SIGNAL ;
    PORT
      LAYER M5 ;
        RECT 311.758 249.900 311.782 250.000 ;
    END
  END rd[449]
  PIN rd[448]
    DIRECTION OUTPUT ;
    USE SIGNAL ;
    PORT
      LAYER M5 ;
        RECT 311.662 249.900 311.686 250.000 ;
    END
  END rd[448]
  PIN rd[447]
    DIRECTION OUTPUT ;
    USE SIGNAL ;
    PORT
      LAYER M5 ;
        RECT 311.566 249.900 311.590 250.000 ;
    END
  END rd[447]
  PIN rd[446]
    DIRECTION OUTPUT ;
    USE SIGNAL ;
    PORT
      LAYER M5 ;
        RECT 311.470 249.900 311.494 250.000 ;
    END
  END rd[446]
  PIN rd[445]
    DIRECTION OUTPUT ;
    USE SIGNAL ;
    PORT
      LAYER M5 ;
        RECT 311.374 249.900 311.398 250.000 ;
    END
  END rd[445]
  PIN rd[444]
    DIRECTION OUTPUT ;
    USE SIGNAL ;
    PORT
      LAYER M5 ;
        RECT 311.278 249.900 311.302 250.000 ;
    END
  END rd[444]
  PIN rd[443]
    DIRECTION OUTPUT ;
    USE SIGNAL ;
    PORT
      LAYER M5 ;
        RECT 311.182 249.900 311.206 250.000 ;
    END
  END rd[443]
  PIN rd[442]
    DIRECTION OUTPUT ;
    USE SIGNAL ;
    PORT
      LAYER M5 ;
        RECT 311.086 249.900 311.110 250.000 ;
    END
  END rd[442]
  PIN rd[441]
    DIRECTION OUTPUT ;
    USE SIGNAL ;
    PORT
      LAYER M5 ;
        RECT 310.990 249.900 311.014 250.000 ;
    END
  END rd[441]
  PIN rd[440]
    DIRECTION OUTPUT ;
    USE SIGNAL ;
    PORT
      LAYER M5 ;
        RECT 310.894 249.900 310.918 250.000 ;
    END
  END rd[440]
  PIN rd[439]
    DIRECTION OUTPUT ;
    USE SIGNAL ;
    PORT
      LAYER M5 ;
        RECT 310.798 249.900 310.822 250.000 ;
    END
  END rd[439]
  PIN rd[438]
    DIRECTION OUTPUT ;
    USE SIGNAL ;
    PORT
      LAYER M5 ;
        RECT 310.702 249.900 310.726 250.000 ;
    END
  END rd[438]
  PIN rd[437]
    DIRECTION OUTPUT ;
    USE SIGNAL ;
    PORT
      LAYER M5 ;
        RECT 310.606 249.900 310.630 250.000 ;
    END
  END rd[437]
  PIN rd[436]
    DIRECTION OUTPUT ;
    USE SIGNAL ;
    PORT
      LAYER M5 ;
        RECT 310.510 249.900 310.534 250.000 ;
    END
  END rd[436]
  PIN rd[435]
    DIRECTION OUTPUT ;
    USE SIGNAL ;
    PORT
      LAYER M5 ;
        RECT 310.414 249.900 310.438 250.000 ;
    END
  END rd[435]
  PIN rd[434]
    DIRECTION OUTPUT ;
    USE SIGNAL ;
    PORT
      LAYER M5 ;
        RECT 310.318 249.900 310.342 250.000 ;
    END
  END rd[434]
  PIN rd[433]
    DIRECTION OUTPUT ;
    USE SIGNAL ;
    PORT
      LAYER M5 ;
        RECT 310.222 249.900 310.246 250.000 ;
    END
  END rd[433]
  PIN rd[432]
    DIRECTION OUTPUT ;
    USE SIGNAL ;
    PORT
      LAYER M5 ;
        RECT 310.126 249.900 310.150 250.000 ;
    END
  END rd[432]
  PIN rd[431]
    DIRECTION OUTPUT ;
    USE SIGNAL ;
    PORT
      LAYER M5 ;
        RECT 310.030 249.900 310.054 250.000 ;
    END
  END rd[431]
  PIN rd[430]
    DIRECTION OUTPUT ;
    USE SIGNAL ;
    PORT
      LAYER M5 ;
        RECT 309.934 249.900 309.958 250.000 ;
    END
  END rd[430]
  PIN rd[429]
    DIRECTION OUTPUT ;
    USE SIGNAL ;
    PORT
      LAYER M5 ;
        RECT 309.838 249.900 309.862 250.000 ;
    END
  END rd[429]
  PIN rd[428]
    DIRECTION OUTPUT ;
    USE SIGNAL ;
    PORT
      LAYER M5 ;
        RECT 309.742 249.900 309.766 250.000 ;
    END
  END rd[428]
  PIN rd[427]
    DIRECTION OUTPUT ;
    USE SIGNAL ;
    PORT
      LAYER M5 ;
        RECT 309.646 249.900 309.670 250.000 ;
    END
  END rd[427]
  PIN rd[426]
    DIRECTION OUTPUT ;
    USE SIGNAL ;
    PORT
      LAYER M5 ;
        RECT 309.550 249.900 309.574 250.000 ;
    END
  END rd[426]
  PIN rd[425]
    DIRECTION OUTPUT ;
    USE SIGNAL ;
    PORT
      LAYER M5 ;
        RECT 309.454 249.900 309.478 250.000 ;
    END
  END rd[425]
  PIN rd[424]
    DIRECTION OUTPUT ;
    USE SIGNAL ;
    PORT
      LAYER M5 ;
        RECT 309.358 249.900 309.382 250.000 ;
    END
  END rd[424]
  PIN rd[423]
    DIRECTION OUTPUT ;
    USE SIGNAL ;
    PORT
      LAYER M5 ;
        RECT 309.262 249.900 309.286 250.000 ;
    END
  END rd[423]
  PIN rd[422]
    DIRECTION OUTPUT ;
    USE SIGNAL ;
    PORT
      LAYER M5 ;
        RECT 309.166 249.900 309.190 250.000 ;
    END
  END rd[422]
  PIN rd[421]
    DIRECTION OUTPUT ;
    USE SIGNAL ;
    PORT
      LAYER M5 ;
        RECT 309.070 249.900 309.094 250.000 ;
    END
  END rd[421]
  PIN rd[420]
    DIRECTION OUTPUT ;
    USE SIGNAL ;
    PORT
      LAYER M5 ;
        RECT 308.974 249.900 308.998 250.000 ;
    END
  END rd[420]
  PIN rd[419]
    DIRECTION OUTPUT ;
    USE SIGNAL ;
    PORT
      LAYER M5 ;
        RECT 308.878 249.900 308.902 250.000 ;
    END
  END rd[419]
  PIN rd[418]
    DIRECTION OUTPUT ;
    USE SIGNAL ;
    PORT
      LAYER M5 ;
        RECT 308.782 249.900 308.806 250.000 ;
    END
  END rd[418]
  PIN rd[417]
    DIRECTION OUTPUT ;
    USE SIGNAL ;
    PORT
      LAYER M5 ;
        RECT 308.686 249.900 308.710 250.000 ;
    END
  END rd[417]
  PIN rd[416]
    DIRECTION OUTPUT ;
    USE SIGNAL ;
    PORT
      LAYER M5 ;
        RECT 308.590 249.900 308.614 250.000 ;
    END
  END rd[416]
  PIN rd[415]
    DIRECTION OUTPUT ;
    USE SIGNAL ;
    PORT
      LAYER M5 ;
        RECT 308.494 249.900 308.518 250.000 ;
    END
  END rd[415]
  PIN rd[414]
    DIRECTION OUTPUT ;
    USE SIGNAL ;
    PORT
      LAYER M5 ;
        RECT 308.398 249.900 308.422 250.000 ;
    END
  END rd[414]
  PIN rd[413]
    DIRECTION OUTPUT ;
    USE SIGNAL ;
    PORT
      LAYER M5 ;
        RECT 308.302 249.900 308.326 250.000 ;
    END
  END rd[413]
  PIN rd[412]
    DIRECTION OUTPUT ;
    USE SIGNAL ;
    PORT
      LAYER M5 ;
        RECT 308.206 249.900 308.230 250.000 ;
    END
  END rd[412]
  PIN rd[411]
    DIRECTION OUTPUT ;
    USE SIGNAL ;
    PORT
      LAYER M5 ;
        RECT 308.110 249.900 308.134 250.000 ;
    END
  END rd[411]
  PIN rd[410]
    DIRECTION OUTPUT ;
    USE SIGNAL ;
    PORT
      LAYER M5 ;
        RECT 308.014 249.900 308.038 250.000 ;
    END
  END rd[410]
  PIN rd[409]
    DIRECTION OUTPUT ;
    USE SIGNAL ;
    PORT
      LAYER M5 ;
        RECT 307.918 249.900 307.942 250.000 ;
    END
  END rd[409]
  PIN rd[408]
    DIRECTION OUTPUT ;
    USE SIGNAL ;
    PORT
      LAYER M5 ;
        RECT 307.822 249.900 307.846 250.000 ;
    END
  END rd[408]
  PIN rd[407]
    DIRECTION OUTPUT ;
    USE SIGNAL ;
    PORT
      LAYER M5 ;
        RECT 307.726 249.900 307.750 250.000 ;
    END
  END rd[407]
  PIN rd[406]
    DIRECTION OUTPUT ;
    USE SIGNAL ;
    PORT
      LAYER M5 ;
        RECT 307.630 249.900 307.654 250.000 ;
    END
  END rd[406]
  PIN rd[405]
    DIRECTION OUTPUT ;
    USE SIGNAL ;
    PORT
      LAYER M5 ;
        RECT 307.534 249.900 307.558 250.000 ;
    END
  END rd[405]
  PIN rd[404]
    DIRECTION OUTPUT ;
    USE SIGNAL ;
    PORT
      LAYER M5 ;
        RECT 307.438 249.900 307.462 250.000 ;
    END
  END rd[404]
  PIN rd[403]
    DIRECTION OUTPUT ;
    USE SIGNAL ;
    PORT
      LAYER M5 ;
        RECT 307.342 249.900 307.366 250.000 ;
    END
  END rd[403]
  PIN rd[402]
    DIRECTION OUTPUT ;
    USE SIGNAL ;
    PORT
      LAYER M5 ;
        RECT 307.246 249.900 307.270 250.000 ;
    END
  END rd[402]
  PIN rd[401]
    DIRECTION OUTPUT ;
    USE SIGNAL ;
    PORT
      LAYER M5 ;
        RECT 307.150 249.900 307.174 250.000 ;
    END
  END rd[401]
  PIN rd[400]
    DIRECTION OUTPUT ;
    USE SIGNAL ;
    PORT
      LAYER M5 ;
        RECT 307.054 249.900 307.078 250.000 ;
    END
  END rd[400]
  PIN rd[399]
    DIRECTION OUTPUT ;
    USE SIGNAL ;
    PORT
      LAYER M5 ;
        RECT 306.958 249.900 306.982 250.000 ;
    END
  END rd[399]
  PIN rd[398]
    DIRECTION OUTPUT ;
    USE SIGNAL ;
    PORT
      LAYER M5 ;
        RECT 306.862 249.900 306.886 250.000 ;
    END
  END rd[398]
  PIN rd[397]
    DIRECTION OUTPUT ;
    USE SIGNAL ;
    PORT
      LAYER M5 ;
        RECT 306.766 249.900 306.790 250.000 ;
    END
  END rd[397]
  PIN rd[396]
    DIRECTION OUTPUT ;
    USE SIGNAL ;
    PORT
      LAYER M5 ;
        RECT 306.670 249.900 306.694 250.000 ;
    END
  END rd[396]
  PIN rd[395]
    DIRECTION OUTPUT ;
    USE SIGNAL ;
    PORT
      LAYER M5 ;
        RECT 306.574 249.900 306.598 250.000 ;
    END
  END rd[395]
  PIN rd[394]
    DIRECTION OUTPUT ;
    USE SIGNAL ;
    PORT
      LAYER M5 ;
        RECT 306.478 249.900 306.502 250.000 ;
    END
  END rd[394]
  PIN rd[393]
    DIRECTION OUTPUT ;
    USE SIGNAL ;
    PORT
      LAYER M5 ;
        RECT 306.382 249.900 306.406 250.000 ;
    END
  END rd[393]
  PIN rd[392]
    DIRECTION OUTPUT ;
    USE SIGNAL ;
    PORT
      LAYER M5 ;
        RECT 306.286 249.900 306.310 250.000 ;
    END
  END rd[392]
  PIN rd[391]
    DIRECTION OUTPUT ;
    USE SIGNAL ;
    PORT
      LAYER M5 ;
        RECT 306.190 249.900 306.214 250.000 ;
    END
  END rd[391]
  PIN rd[390]
    DIRECTION OUTPUT ;
    USE SIGNAL ;
    PORT
      LAYER M5 ;
        RECT 306.094 249.900 306.118 250.000 ;
    END
  END rd[390]
  PIN rd[389]
    DIRECTION OUTPUT ;
    USE SIGNAL ;
    PORT
      LAYER M5 ;
        RECT 305.998 249.900 306.022 250.000 ;
    END
  END rd[389]
  PIN rd[388]
    DIRECTION OUTPUT ;
    USE SIGNAL ;
    PORT
      LAYER M5 ;
        RECT 305.902 249.900 305.926 250.000 ;
    END
  END rd[388]
  PIN rd[387]
    DIRECTION OUTPUT ;
    USE SIGNAL ;
    PORT
      LAYER M5 ;
        RECT 305.806 249.900 305.830 250.000 ;
    END
  END rd[387]
  PIN rd[386]
    DIRECTION OUTPUT ;
    USE SIGNAL ;
    PORT
      LAYER M5 ;
        RECT 305.710 249.900 305.734 250.000 ;
    END
  END rd[386]
  PIN rd[385]
    DIRECTION OUTPUT ;
    USE SIGNAL ;
    PORT
      LAYER M5 ;
        RECT 305.614 249.900 305.638 250.000 ;
    END
  END rd[385]
  PIN rd[384]
    DIRECTION OUTPUT ;
    USE SIGNAL ;
    PORT
      LAYER M5 ;
        RECT 305.518 249.900 305.542 250.000 ;
    END
  END rd[384]
  PIN rd[383]
    DIRECTION OUTPUT ;
    USE SIGNAL ;
    PORT
      LAYER M5 ;
        RECT 305.422 249.900 305.446 250.000 ;
    END
  END rd[383]
  PIN rd[382]
    DIRECTION OUTPUT ;
    USE SIGNAL ;
    PORT
      LAYER M5 ;
        RECT 305.326 249.900 305.350 250.000 ;
    END
  END rd[382]
  PIN rd[381]
    DIRECTION OUTPUT ;
    USE SIGNAL ;
    PORT
      LAYER M5 ;
        RECT 305.230 249.900 305.254 250.000 ;
    END
  END rd[381]
  PIN rd[380]
    DIRECTION OUTPUT ;
    USE SIGNAL ;
    PORT
      LAYER M5 ;
        RECT 305.134 249.900 305.158 250.000 ;
    END
  END rd[380]
  PIN rd[379]
    DIRECTION OUTPUT ;
    USE SIGNAL ;
    PORT
      LAYER M5 ;
        RECT 305.038 249.900 305.062 250.000 ;
    END
  END rd[379]
  PIN rd[378]
    DIRECTION OUTPUT ;
    USE SIGNAL ;
    PORT
      LAYER M5 ;
        RECT 304.942 249.900 304.966 250.000 ;
    END
  END rd[378]
  PIN rd[377]
    DIRECTION OUTPUT ;
    USE SIGNAL ;
    PORT
      LAYER M5 ;
        RECT 304.846 249.900 304.870 250.000 ;
    END
  END rd[377]
  PIN rd[376]
    DIRECTION OUTPUT ;
    USE SIGNAL ;
    PORT
      LAYER M5 ;
        RECT 304.750 249.900 304.774 250.000 ;
    END
  END rd[376]
  PIN rd[375]
    DIRECTION OUTPUT ;
    USE SIGNAL ;
    PORT
      LAYER M5 ;
        RECT 304.654 249.900 304.678 250.000 ;
    END
  END rd[375]
  PIN rd[374]
    DIRECTION OUTPUT ;
    USE SIGNAL ;
    PORT
      LAYER M5 ;
        RECT 304.558 249.900 304.582 250.000 ;
    END
  END rd[374]
  PIN rd[373]
    DIRECTION OUTPUT ;
    USE SIGNAL ;
    PORT
      LAYER M5 ;
        RECT 304.462 249.900 304.486 250.000 ;
    END
  END rd[373]
  PIN rd[372]
    DIRECTION OUTPUT ;
    USE SIGNAL ;
    PORT
      LAYER M5 ;
        RECT 304.366 249.900 304.390 250.000 ;
    END
  END rd[372]
  PIN rd[371]
    DIRECTION OUTPUT ;
    USE SIGNAL ;
    PORT
      LAYER M5 ;
        RECT 304.270 249.900 304.294 250.000 ;
    END
  END rd[371]
  PIN rd[370]
    DIRECTION OUTPUT ;
    USE SIGNAL ;
    PORT
      LAYER M5 ;
        RECT 304.174 249.900 304.198 250.000 ;
    END
  END rd[370]
  PIN rd[369]
    DIRECTION OUTPUT ;
    USE SIGNAL ;
    PORT
      LAYER M5 ;
        RECT 304.078 249.900 304.102 250.000 ;
    END
  END rd[369]
  PIN rd[368]
    DIRECTION OUTPUT ;
    USE SIGNAL ;
    PORT
      LAYER M5 ;
        RECT 303.982 249.900 304.006 250.000 ;
    END
  END rd[368]
  PIN rd[367]
    DIRECTION OUTPUT ;
    USE SIGNAL ;
    PORT
      LAYER M5 ;
        RECT 303.886 249.900 303.910 250.000 ;
    END
  END rd[367]
  PIN rd[366]
    DIRECTION OUTPUT ;
    USE SIGNAL ;
    PORT
      LAYER M5 ;
        RECT 303.790 249.900 303.814 250.000 ;
    END
  END rd[366]
  PIN rd[365]
    DIRECTION OUTPUT ;
    USE SIGNAL ;
    PORT
      LAYER M5 ;
        RECT 303.694 249.900 303.718 250.000 ;
    END
  END rd[365]
  PIN rd[364]
    DIRECTION OUTPUT ;
    USE SIGNAL ;
    PORT
      LAYER M5 ;
        RECT 303.598 249.900 303.622 250.000 ;
    END
  END rd[364]
  PIN rd[363]
    DIRECTION OUTPUT ;
    USE SIGNAL ;
    PORT
      LAYER M5 ;
        RECT 303.502 249.900 303.526 250.000 ;
    END
  END rd[363]
  PIN rd[362]
    DIRECTION OUTPUT ;
    USE SIGNAL ;
    PORT
      LAYER M5 ;
        RECT 303.406 249.900 303.430 250.000 ;
    END
  END rd[362]
  PIN rd[361]
    DIRECTION OUTPUT ;
    USE SIGNAL ;
    PORT
      LAYER M5 ;
        RECT 303.310 249.900 303.334 250.000 ;
    END
  END rd[361]
  PIN rd[360]
    DIRECTION OUTPUT ;
    USE SIGNAL ;
    PORT
      LAYER M5 ;
        RECT 303.214 249.900 303.238 250.000 ;
    END
  END rd[360]
  PIN rd[359]
    DIRECTION OUTPUT ;
    USE SIGNAL ;
    PORT
      LAYER M5 ;
        RECT 303.118 249.900 303.142 250.000 ;
    END
  END rd[359]
  PIN rd[358]
    DIRECTION OUTPUT ;
    USE SIGNAL ;
    PORT
      LAYER M5 ;
        RECT 303.022 249.900 303.046 250.000 ;
    END
  END rd[358]
  PIN rd[357]
    DIRECTION OUTPUT ;
    USE SIGNAL ;
    PORT
      LAYER M5 ;
        RECT 302.926 249.900 302.950 250.000 ;
    END
  END rd[357]
  PIN rd[356]
    DIRECTION OUTPUT ;
    USE SIGNAL ;
    PORT
      LAYER M5 ;
        RECT 302.830 249.900 302.854 250.000 ;
    END
  END rd[356]
  PIN rd[355]
    DIRECTION OUTPUT ;
    USE SIGNAL ;
    PORT
      LAYER M5 ;
        RECT 302.734 249.900 302.758 250.000 ;
    END
  END rd[355]
  PIN rd[354]
    DIRECTION OUTPUT ;
    USE SIGNAL ;
    PORT
      LAYER M5 ;
        RECT 302.638 249.900 302.662 250.000 ;
    END
  END rd[354]
  PIN rd[353]
    DIRECTION OUTPUT ;
    USE SIGNAL ;
    PORT
      LAYER M5 ;
        RECT 302.542 249.900 302.566 250.000 ;
    END
  END rd[353]
  PIN rd[352]
    DIRECTION OUTPUT ;
    USE SIGNAL ;
    PORT
      LAYER M5 ;
        RECT 302.446 249.900 302.470 250.000 ;
    END
  END rd[352]
  PIN rd[351]
    DIRECTION OUTPUT ;
    USE SIGNAL ;
    PORT
      LAYER M5 ;
        RECT 302.350 249.900 302.374 250.000 ;
    END
  END rd[351]
  PIN rd[350]
    DIRECTION OUTPUT ;
    USE SIGNAL ;
    PORT
      LAYER M5 ;
        RECT 302.254 249.900 302.278 250.000 ;
    END
  END rd[350]
  PIN rd[349]
    DIRECTION OUTPUT ;
    USE SIGNAL ;
    PORT
      LAYER M5 ;
        RECT 302.158 249.900 302.182 250.000 ;
    END
  END rd[349]
  PIN rd[348]
    DIRECTION OUTPUT ;
    USE SIGNAL ;
    PORT
      LAYER M5 ;
        RECT 302.062 249.900 302.086 250.000 ;
    END
  END rd[348]
  PIN rd[347]
    DIRECTION OUTPUT ;
    USE SIGNAL ;
    PORT
      LAYER M5 ;
        RECT 301.966 249.900 301.990 250.000 ;
    END
  END rd[347]
  PIN rd[346]
    DIRECTION OUTPUT ;
    USE SIGNAL ;
    PORT
      LAYER M5 ;
        RECT 301.870 249.900 301.894 250.000 ;
    END
  END rd[346]
  PIN rd[345]
    DIRECTION OUTPUT ;
    USE SIGNAL ;
    PORT
      LAYER M5 ;
        RECT 301.774 249.900 301.798 250.000 ;
    END
  END rd[345]
  PIN rd[344]
    DIRECTION OUTPUT ;
    USE SIGNAL ;
    PORT
      LAYER M5 ;
        RECT 301.678 249.900 301.702 250.000 ;
    END
  END rd[344]
  PIN rd[343]
    DIRECTION OUTPUT ;
    USE SIGNAL ;
    PORT
      LAYER M5 ;
        RECT 301.582 249.900 301.606 250.000 ;
    END
  END rd[343]
  PIN rd[342]
    DIRECTION OUTPUT ;
    USE SIGNAL ;
    PORT
      LAYER M5 ;
        RECT 301.486 249.900 301.510 250.000 ;
    END
  END rd[342]
  PIN rd[341]
    DIRECTION OUTPUT ;
    USE SIGNAL ;
    PORT
      LAYER M5 ;
        RECT 301.390 249.900 301.414 250.000 ;
    END
  END rd[341]
  PIN rd[340]
    DIRECTION OUTPUT ;
    USE SIGNAL ;
    PORT
      LAYER M5 ;
        RECT 301.294 249.900 301.318 250.000 ;
    END
  END rd[340]
  PIN rd[339]
    DIRECTION OUTPUT ;
    USE SIGNAL ;
    PORT
      LAYER M5 ;
        RECT 301.198 249.900 301.222 250.000 ;
    END
  END rd[339]
  PIN rd[338]
    DIRECTION OUTPUT ;
    USE SIGNAL ;
    PORT
      LAYER M5 ;
        RECT 301.102 249.900 301.126 250.000 ;
    END
  END rd[338]
  PIN rd[337]
    DIRECTION OUTPUT ;
    USE SIGNAL ;
    PORT
      LAYER M5 ;
        RECT 301.006 249.900 301.030 250.000 ;
    END
  END rd[337]
  PIN rd[336]
    DIRECTION OUTPUT ;
    USE SIGNAL ;
    PORT
      LAYER M5 ;
        RECT 300.910 249.900 300.934 250.000 ;
    END
  END rd[336]
  PIN rd[335]
    DIRECTION OUTPUT ;
    USE SIGNAL ;
    PORT
      LAYER M5 ;
        RECT 300.814 249.900 300.838 250.000 ;
    END
  END rd[335]
  PIN rd[334]
    DIRECTION OUTPUT ;
    USE SIGNAL ;
    PORT
      LAYER M5 ;
        RECT 300.718 249.900 300.742 250.000 ;
    END
  END rd[334]
  PIN rd[333]
    DIRECTION OUTPUT ;
    USE SIGNAL ;
    PORT
      LAYER M5 ;
        RECT 300.622 249.900 300.646 250.000 ;
    END
  END rd[333]
  PIN rd[332]
    DIRECTION OUTPUT ;
    USE SIGNAL ;
    PORT
      LAYER M5 ;
        RECT 300.526 249.900 300.550 250.000 ;
    END
  END rd[332]
  PIN rd[331]
    DIRECTION OUTPUT ;
    USE SIGNAL ;
    PORT
      LAYER M5 ;
        RECT 300.430 249.900 300.454 250.000 ;
    END
  END rd[331]
  PIN rd[330]
    DIRECTION OUTPUT ;
    USE SIGNAL ;
    PORT
      LAYER M5 ;
        RECT 300.334 249.900 300.358 250.000 ;
    END
  END rd[330]
  PIN rd[329]
    DIRECTION OUTPUT ;
    USE SIGNAL ;
    PORT
      LAYER M5 ;
        RECT 300.238 249.900 300.262 250.000 ;
    END
  END rd[329]
  PIN rd[328]
    DIRECTION OUTPUT ;
    USE SIGNAL ;
    PORT
      LAYER M5 ;
        RECT 300.142 249.900 300.166 250.000 ;
    END
  END rd[328]
  PIN rd[327]
    DIRECTION OUTPUT ;
    USE SIGNAL ;
    PORT
      LAYER M5 ;
        RECT 300.046 249.900 300.070 250.000 ;
    END
  END rd[327]
  PIN rd[326]
    DIRECTION OUTPUT ;
    USE SIGNAL ;
    PORT
      LAYER M5 ;
        RECT 299.950 249.900 299.974 250.000 ;
    END
  END rd[326]
  PIN rd[325]
    DIRECTION OUTPUT ;
    USE SIGNAL ;
    PORT
      LAYER M5 ;
        RECT 299.854 249.900 299.878 250.000 ;
    END
  END rd[325]
  PIN rd[324]
    DIRECTION OUTPUT ;
    USE SIGNAL ;
    PORT
      LAYER M5 ;
        RECT 299.758 249.900 299.782 250.000 ;
    END
  END rd[324]
  PIN rd[323]
    DIRECTION OUTPUT ;
    USE SIGNAL ;
    PORT
      LAYER M5 ;
        RECT 299.662 249.900 299.686 250.000 ;
    END
  END rd[323]
  PIN rd[322]
    DIRECTION OUTPUT ;
    USE SIGNAL ;
    PORT
      LAYER M5 ;
        RECT 299.566 249.900 299.590 250.000 ;
    END
  END rd[322]
  PIN rd[321]
    DIRECTION OUTPUT ;
    USE SIGNAL ;
    PORT
      LAYER M5 ;
        RECT 299.470 249.900 299.494 250.000 ;
    END
  END rd[321]
  PIN rd[320]
    DIRECTION OUTPUT ;
    USE SIGNAL ;
    PORT
      LAYER M5 ;
        RECT 299.374 249.900 299.398 250.000 ;
    END
  END rd[320]
  PIN rd[319]
    DIRECTION OUTPUT ;
    USE SIGNAL ;
    PORT
      LAYER M5 ;
        RECT 299.278 249.900 299.302 250.000 ;
    END
  END rd[319]
  PIN rd[318]
    DIRECTION OUTPUT ;
    USE SIGNAL ;
    PORT
      LAYER M5 ;
        RECT 299.182 249.900 299.206 250.000 ;
    END
  END rd[318]
  PIN rd[317]
    DIRECTION OUTPUT ;
    USE SIGNAL ;
    PORT
      LAYER M5 ;
        RECT 299.086 249.900 299.110 250.000 ;
    END
  END rd[317]
  PIN rd[316]
    DIRECTION OUTPUT ;
    USE SIGNAL ;
    PORT
      LAYER M5 ;
        RECT 298.990 249.900 299.014 250.000 ;
    END
  END rd[316]
  PIN rd[315]
    DIRECTION OUTPUT ;
    USE SIGNAL ;
    PORT
      LAYER M5 ;
        RECT 298.894 249.900 298.918 250.000 ;
    END
  END rd[315]
  PIN rd[314]
    DIRECTION OUTPUT ;
    USE SIGNAL ;
    PORT
      LAYER M5 ;
        RECT 298.798 249.900 298.822 250.000 ;
    END
  END rd[314]
  PIN rd[313]
    DIRECTION OUTPUT ;
    USE SIGNAL ;
    PORT
      LAYER M5 ;
        RECT 298.702 249.900 298.726 250.000 ;
    END
  END rd[313]
  PIN rd[312]
    DIRECTION OUTPUT ;
    USE SIGNAL ;
    PORT
      LAYER M5 ;
        RECT 298.606 249.900 298.630 250.000 ;
    END
  END rd[312]
  PIN rd[311]
    DIRECTION OUTPUT ;
    USE SIGNAL ;
    PORT
      LAYER M5 ;
        RECT 298.510 249.900 298.534 250.000 ;
    END
  END rd[311]
  PIN rd[310]
    DIRECTION OUTPUT ;
    USE SIGNAL ;
    PORT
      LAYER M5 ;
        RECT 298.414 249.900 298.438 250.000 ;
    END
  END rd[310]
  PIN rd[309]
    DIRECTION OUTPUT ;
    USE SIGNAL ;
    PORT
      LAYER M5 ;
        RECT 298.318 249.900 298.342 250.000 ;
    END
  END rd[309]
  PIN rd[308]
    DIRECTION OUTPUT ;
    USE SIGNAL ;
    PORT
      LAYER M5 ;
        RECT 298.222 249.900 298.246 250.000 ;
    END
  END rd[308]
  PIN rd[307]
    DIRECTION OUTPUT ;
    USE SIGNAL ;
    PORT
      LAYER M5 ;
        RECT 298.126 249.900 298.150 250.000 ;
    END
  END rd[307]
  PIN rd[306]
    DIRECTION OUTPUT ;
    USE SIGNAL ;
    PORT
      LAYER M5 ;
        RECT 298.030 249.900 298.054 250.000 ;
    END
  END rd[306]
  PIN rd[305]
    DIRECTION OUTPUT ;
    USE SIGNAL ;
    PORT
      LAYER M5 ;
        RECT 297.934 249.900 297.958 250.000 ;
    END
  END rd[305]
  PIN rd[304]
    DIRECTION OUTPUT ;
    USE SIGNAL ;
    PORT
      LAYER M5 ;
        RECT 297.838 249.900 297.862 250.000 ;
    END
  END rd[304]
  PIN rd[303]
    DIRECTION OUTPUT ;
    USE SIGNAL ;
    PORT
      LAYER M5 ;
        RECT 297.742 249.900 297.766 250.000 ;
    END
  END rd[303]
  PIN rd[302]
    DIRECTION OUTPUT ;
    USE SIGNAL ;
    PORT
      LAYER M5 ;
        RECT 297.646 249.900 297.670 250.000 ;
    END
  END rd[302]
  PIN rd[301]
    DIRECTION OUTPUT ;
    USE SIGNAL ;
    PORT
      LAYER M5 ;
        RECT 297.550 249.900 297.574 250.000 ;
    END
  END rd[301]
  PIN rd[300]
    DIRECTION OUTPUT ;
    USE SIGNAL ;
    PORT
      LAYER M5 ;
        RECT 297.454 249.900 297.478 250.000 ;
    END
  END rd[300]
  PIN rd[299]
    DIRECTION OUTPUT ;
    USE SIGNAL ;
    PORT
      LAYER M5 ;
        RECT 297.358 249.900 297.382 250.000 ;
    END
  END rd[299]
  PIN rd[298]
    DIRECTION OUTPUT ;
    USE SIGNAL ;
    PORT
      LAYER M5 ;
        RECT 297.262 249.900 297.286 250.000 ;
    END
  END rd[298]
  PIN rd[297]
    DIRECTION OUTPUT ;
    USE SIGNAL ;
    PORT
      LAYER M5 ;
        RECT 297.166 249.900 297.190 250.000 ;
    END
  END rd[297]
  PIN rd[296]
    DIRECTION OUTPUT ;
    USE SIGNAL ;
    PORT
      LAYER M5 ;
        RECT 297.070 249.900 297.094 250.000 ;
    END
  END rd[296]
  PIN rd[295]
    DIRECTION OUTPUT ;
    USE SIGNAL ;
    PORT
      LAYER M5 ;
        RECT 296.974 249.900 296.998 250.000 ;
    END
  END rd[295]
  PIN rd[294]
    DIRECTION OUTPUT ;
    USE SIGNAL ;
    PORT
      LAYER M5 ;
        RECT 296.878 249.900 296.902 250.000 ;
    END
  END rd[294]
  PIN rd[293]
    DIRECTION OUTPUT ;
    USE SIGNAL ;
    PORT
      LAYER M5 ;
        RECT 296.782 249.900 296.806 250.000 ;
    END
  END rd[293]
  PIN rd[292]
    DIRECTION OUTPUT ;
    USE SIGNAL ;
    PORT
      LAYER M5 ;
        RECT 296.686 249.900 296.710 250.000 ;
    END
  END rd[292]
  PIN rd[291]
    DIRECTION OUTPUT ;
    USE SIGNAL ;
    PORT
      LAYER M5 ;
        RECT 296.590 249.900 296.614 250.000 ;
    END
  END rd[291]
  PIN rd[290]
    DIRECTION OUTPUT ;
    USE SIGNAL ;
    PORT
      LAYER M5 ;
        RECT 296.494 249.900 296.518 250.000 ;
    END
  END rd[290]
  PIN rd[289]
    DIRECTION OUTPUT ;
    USE SIGNAL ;
    PORT
      LAYER M5 ;
        RECT 296.398 249.900 296.422 250.000 ;
    END
  END rd[289]
  PIN rd[288]
    DIRECTION OUTPUT ;
    USE SIGNAL ;
    PORT
      LAYER M5 ;
        RECT 296.302 249.900 296.326 250.000 ;
    END
  END rd[288]
  PIN rd[287]
    DIRECTION OUTPUT ;
    USE SIGNAL ;
    PORT
      LAYER M5 ;
        RECT 296.206 249.900 296.230 250.000 ;
    END
  END rd[287]
  PIN rd[286]
    DIRECTION OUTPUT ;
    USE SIGNAL ;
    PORT
      LAYER M5 ;
        RECT 296.110 249.900 296.134 250.000 ;
    END
  END rd[286]
  PIN rd[285]
    DIRECTION OUTPUT ;
    USE SIGNAL ;
    PORT
      LAYER M5 ;
        RECT 296.014 249.900 296.038 250.000 ;
    END
  END rd[285]
  PIN rd[284]
    DIRECTION OUTPUT ;
    USE SIGNAL ;
    PORT
      LAYER M5 ;
        RECT 295.918 249.900 295.942 250.000 ;
    END
  END rd[284]
  PIN rd[283]
    DIRECTION OUTPUT ;
    USE SIGNAL ;
    PORT
      LAYER M5 ;
        RECT 295.822 249.900 295.846 250.000 ;
    END
  END rd[283]
  PIN rd[282]
    DIRECTION OUTPUT ;
    USE SIGNAL ;
    PORT
      LAYER M5 ;
        RECT 295.726 249.900 295.750 250.000 ;
    END
  END rd[282]
  PIN rd[281]
    DIRECTION OUTPUT ;
    USE SIGNAL ;
    PORT
      LAYER M5 ;
        RECT 295.630 249.900 295.654 250.000 ;
    END
  END rd[281]
  PIN rd[280]
    DIRECTION OUTPUT ;
    USE SIGNAL ;
    PORT
      LAYER M5 ;
        RECT 295.534 249.900 295.558 250.000 ;
    END
  END rd[280]
  PIN rd[279]
    DIRECTION OUTPUT ;
    USE SIGNAL ;
    PORT
      LAYER M5 ;
        RECT 295.438 249.900 295.462 250.000 ;
    END
  END rd[279]
  PIN rd[278]
    DIRECTION OUTPUT ;
    USE SIGNAL ;
    PORT
      LAYER M5 ;
        RECT 295.342 249.900 295.366 250.000 ;
    END
  END rd[278]
  PIN rd[277]
    DIRECTION OUTPUT ;
    USE SIGNAL ;
    PORT
      LAYER M5 ;
        RECT 295.246 249.900 295.270 250.000 ;
    END
  END rd[277]
  PIN rd[276]
    DIRECTION OUTPUT ;
    USE SIGNAL ;
    PORT
      LAYER M5 ;
        RECT 295.150 249.900 295.174 250.000 ;
    END
  END rd[276]
  PIN rd[275]
    DIRECTION OUTPUT ;
    USE SIGNAL ;
    PORT
      LAYER M5 ;
        RECT 295.054 249.900 295.078 250.000 ;
    END
  END rd[275]
  PIN rd[274]
    DIRECTION OUTPUT ;
    USE SIGNAL ;
    PORT
      LAYER M5 ;
        RECT 294.958 249.900 294.982 250.000 ;
    END
  END rd[274]
  PIN rd[273]
    DIRECTION OUTPUT ;
    USE SIGNAL ;
    PORT
      LAYER M5 ;
        RECT 294.862 249.900 294.886 250.000 ;
    END
  END rd[273]
  PIN rd[272]
    DIRECTION OUTPUT ;
    USE SIGNAL ;
    PORT
      LAYER M5 ;
        RECT 294.766 249.900 294.790 250.000 ;
    END
  END rd[272]
  PIN rd[271]
    DIRECTION OUTPUT ;
    USE SIGNAL ;
    PORT
      LAYER M5 ;
        RECT 294.670 249.900 294.694 250.000 ;
    END
  END rd[271]
  PIN rd[270]
    DIRECTION OUTPUT ;
    USE SIGNAL ;
    PORT
      LAYER M5 ;
        RECT 294.574 249.900 294.598 250.000 ;
    END
  END rd[270]
  PIN rd[269]
    DIRECTION OUTPUT ;
    USE SIGNAL ;
    PORT
      LAYER M5 ;
        RECT 294.478 249.900 294.502 250.000 ;
    END
  END rd[269]
  PIN rd[268]
    DIRECTION OUTPUT ;
    USE SIGNAL ;
    PORT
      LAYER M5 ;
        RECT 294.382 249.900 294.406 250.000 ;
    END
  END rd[268]
  PIN rd[267]
    DIRECTION OUTPUT ;
    USE SIGNAL ;
    PORT
      LAYER M5 ;
        RECT 294.286 249.900 294.310 250.000 ;
    END
  END rd[267]
  PIN rd[266]
    DIRECTION OUTPUT ;
    USE SIGNAL ;
    PORT
      LAYER M5 ;
        RECT 294.190 249.900 294.214 250.000 ;
    END
  END rd[266]
  PIN rd[265]
    DIRECTION OUTPUT ;
    USE SIGNAL ;
    PORT
      LAYER M5 ;
        RECT 294.094 249.900 294.118 250.000 ;
    END
  END rd[265]
  PIN rd[264]
    DIRECTION OUTPUT ;
    USE SIGNAL ;
    PORT
      LAYER M5 ;
        RECT 293.998 249.900 294.022 250.000 ;
    END
  END rd[264]
  PIN rd[263]
    DIRECTION OUTPUT ;
    USE SIGNAL ;
    PORT
      LAYER M5 ;
        RECT 293.902 249.900 293.926 250.000 ;
    END
  END rd[263]
  PIN rd[262]
    DIRECTION OUTPUT ;
    USE SIGNAL ;
    PORT
      LAYER M5 ;
        RECT 293.806 249.900 293.830 250.000 ;
    END
  END rd[262]
  PIN rd[261]
    DIRECTION OUTPUT ;
    USE SIGNAL ;
    PORT
      LAYER M5 ;
        RECT 293.710 249.900 293.734 250.000 ;
    END
  END rd[261]
  PIN rd[260]
    DIRECTION OUTPUT ;
    USE SIGNAL ;
    PORT
      LAYER M5 ;
        RECT 293.614 249.900 293.638 250.000 ;
    END
  END rd[260]
  PIN rd[259]
    DIRECTION OUTPUT ;
    USE SIGNAL ;
    PORT
      LAYER M5 ;
        RECT 293.518 249.900 293.542 250.000 ;
    END
  END rd[259]
  PIN rd[258]
    DIRECTION OUTPUT ;
    USE SIGNAL ;
    PORT
      LAYER M5 ;
        RECT 293.422 249.900 293.446 250.000 ;
    END
  END rd[258]
  PIN rd[257]
    DIRECTION OUTPUT ;
    USE SIGNAL ;
    PORT
      LAYER M5 ;
        RECT 293.326 249.900 293.350 250.000 ;
    END
  END rd[257]
  PIN rd[256]
    DIRECTION OUTPUT ;
    USE SIGNAL ;
    PORT
      LAYER M5 ;
        RECT 293.230 249.900 293.254 250.000 ;
    END
  END rd[256]
  PIN rd[255]
    DIRECTION OUTPUT ;
    USE SIGNAL ;
    PORT
      LAYER M5 ;
        RECT 293.134 249.900 293.158 250.000 ;
    END
  END rd[255]
  PIN rd[254]
    DIRECTION OUTPUT ;
    USE SIGNAL ;
    PORT
      LAYER M5 ;
        RECT 293.038 249.900 293.062 250.000 ;
    END
  END rd[254]
  PIN rd[253]
    DIRECTION OUTPUT ;
    USE SIGNAL ;
    PORT
      LAYER M5 ;
        RECT 292.942 249.900 292.966 250.000 ;
    END
  END rd[253]
  PIN rd[252]
    DIRECTION OUTPUT ;
    USE SIGNAL ;
    PORT
      LAYER M5 ;
        RECT 292.846 249.900 292.870 250.000 ;
    END
  END rd[252]
  PIN rd[251]
    DIRECTION OUTPUT ;
    USE SIGNAL ;
    PORT
      LAYER M5 ;
        RECT 292.750 249.900 292.774 250.000 ;
    END
  END rd[251]
  PIN rd[250]
    DIRECTION OUTPUT ;
    USE SIGNAL ;
    PORT
      LAYER M5 ;
        RECT 292.654 249.900 292.678 250.000 ;
    END
  END rd[250]
  PIN rd[249]
    DIRECTION OUTPUT ;
    USE SIGNAL ;
    PORT
      LAYER M5 ;
        RECT 292.558 249.900 292.582 250.000 ;
    END
  END rd[249]
  PIN rd[248]
    DIRECTION OUTPUT ;
    USE SIGNAL ;
    PORT
      LAYER M5 ;
        RECT 292.462 249.900 292.486 250.000 ;
    END
  END rd[248]
  PIN rd[247]
    DIRECTION OUTPUT ;
    USE SIGNAL ;
    PORT
      LAYER M5 ;
        RECT 292.366 249.900 292.390 250.000 ;
    END
  END rd[247]
  PIN rd[246]
    DIRECTION OUTPUT ;
    USE SIGNAL ;
    PORT
      LAYER M5 ;
        RECT 292.270 249.900 292.294 250.000 ;
    END
  END rd[246]
  PIN rd[245]
    DIRECTION OUTPUT ;
    USE SIGNAL ;
    PORT
      LAYER M5 ;
        RECT 292.174 249.900 292.198 250.000 ;
    END
  END rd[245]
  PIN rd[244]
    DIRECTION OUTPUT ;
    USE SIGNAL ;
    PORT
      LAYER M5 ;
        RECT 292.078 249.900 292.102 250.000 ;
    END
  END rd[244]
  PIN rd[243]
    DIRECTION OUTPUT ;
    USE SIGNAL ;
    PORT
      LAYER M5 ;
        RECT 291.982 249.900 292.006 250.000 ;
    END
  END rd[243]
  PIN rd[242]
    DIRECTION OUTPUT ;
    USE SIGNAL ;
    PORT
      LAYER M5 ;
        RECT 291.886 249.900 291.910 250.000 ;
    END
  END rd[242]
  PIN rd[241]
    DIRECTION OUTPUT ;
    USE SIGNAL ;
    PORT
      LAYER M5 ;
        RECT 291.790 249.900 291.814 250.000 ;
    END
  END rd[241]
  PIN rd[240]
    DIRECTION OUTPUT ;
    USE SIGNAL ;
    PORT
      LAYER M5 ;
        RECT 291.694 249.900 291.718 250.000 ;
    END
  END rd[240]
  PIN rd[239]
    DIRECTION OUTPUT ;
    USE SIGNAL ;
    PORT
      LAYER M5 ;
        RECT 291.598 249.900 291.622 250.000 ;
    END
  END rd[239]
  PIN rd[238]
    DIRECTION OUTPUT ;
    USE SIGNAL ;
    PORT
      LAYER M5 ;
        RECT 291.502 249.900 291.526 250.000 ;
    END
  END rd[238]
  PIN rd[237]
    DIRECTION OUTPUT ;
    USE SIGNAL ;
    PORT
      LAYER M5 ;
        RECT 291.406 249.900 291.430 250.000 ;
    END
  END rd[237]
  PIN rd[236]
    DIRECTION OUTPUT ;
    USE SIGNAL ;
    PORT
      LAYER M5 ;
        RECT 291.310 249.900 291.334 250.000 ;
    END
  END rd[236]
  PIN rd[235]
    DIRECTION OUTPUT ;
    USE SIGNAL ;
    PORT
      LAYER M5 ;
        RECT 291.214 249.900 291.238 250.000 ;
    END
  END rd[235]
  PIN rd[234]
    DIRECTION OUTPUT ;
    USE SIGNAL ;
    PORT
      LAYER M5 ;
        RECT 291.118 249.900 291.142 250.000 ;
    END
  END rd[234]
  PIN rd[233]
    DIRECTION OUTPUT ;
    USE SIGNAL ;
    PORT
      LAYER M5 ;
        RECT 291.022 249.900 291.046 250.000 ;
    END
  END rd[233]
  PIN rd[232]
    DIRECTION OUTPUT ;
    USE SIGNAL ;
    PORT
      LAYER M5 ;
        RECT 290.926 249.900 290.950 250.000 ;
    END
  END rd[232]
  PIN rd[231]
    DIRECTION OUTPUT ;
    USE SIGNAL ;
    PORT
      LAYER M5 ;
        RECT 290.830 249.900 290.854 250.000 ;
    END
  END rd[231]
  PIN rd[230]
    DIRECTION OUTPUT ;
    USE SIGNAL ;
    PORT
      LAYER M5 ;
        RECT 290.734 249.900 290.758 250.000 ;
    END
  END rd[230]
  PIN rd[229]
    DIRECTION OUTPUT ;
    USE SIGNAL ;
    PORT
      LAYER M5 ;
        RECT 290.638 249.900 290.662 250.000 ;
    END
  END rd[229]
  PIN rd[228]
    DIRECTION OUTPUT ;
    USE SIGNAL ;
    PORT
      LAYER M5 ;
        RECT 290.542 249.900 290.566 250.000 ;
    END
  END rd[228]
  PIN rd[227]
    DIRECTION OUTPUT ;
    USE SIGNAL ;
    PORT
      LAYER M5 ;
        RECT 290.446 249.900 290.470 250.000 ;
    END
  END rd[227]
  PIN rd[226]
    DIRECTION OUTPUT ;
    USE SIGNAL ;
    PORT
      LAYER M5 ;
        RECT 290.350 249.900 290.374 250.000 ;
    END
  END rd[226]
  PIN rd[225]
    DIRECTION OUTPUT ;
    USE SIGNAL ;
    PORT
      LAYER M5 ;
        RECT 290.254 249.900 290.278 250.000 ;
    END
  END rd[225]
  PIN rd[224]
    DIRECTION OUTPUT ;
    USE SIGNAL ;
    PORT
      LAYER M5 ;
        RECT 290.158 249.900 290.182 250.000 ;
    END
  END rd[224]
  PIN rd[223]
    DIRECTION OUTPUT ;
    USE SIGNAL ;
    PORT
      LAYER M5 ;
        RECT 290.062 249.900 290.086 250.000 ;
    END
  END rd[223]
  PIN rd[222]
    DIRECTION OUTPUT ;
    USE SIGNAL ;
    PORT
      LAYER M5 ;
        RECT 289.966 249.900 289.990 250.000 ;
    END
  END rd[222]
  PIN rd[221]
    DIRECTION OUTPUT ;
    USE SIGNAL ;
    PORT
      LAYER M5 ;
        RECT 289.870 249.900 289.894 250.000 ;
    END
  END rd[221]
  PIN rd[220]
    DIRECTION OUTPUT ;
    USE SIGNAL ;
    PORT
      LAYER M5 ;
        RECT 289.774 249.900 289.798 250.000 ;
    END
  END rd[220]
  PIN rd[219]
    DIRECTION OUTPUT ;
    USE SIGNAL ;
    PORT
      LAYER M5 ;
        RECT 289.678 249.900 289.702 250.000 ;
    END
  END rd[219]
  PIN rd[218]
    DIRECTION OUTPUT ;
    USE SIGNAL ;
    PORT
      LAYER M5 ;
        RECT 289.582 249.900 289.606 250.000 ;
    END
  END rd[218]
  PIN rd[217]
    DIRECTION OUTPUT ;
    USE SIGNAL ;
    PORT
      LAYER M5 ;
        RECT 289.486 249.900 289.510 250.000 ;
    END
  END rd[217]
  PIN rd[216]
    DIRECTION OUTPUT ;
    USE SIGNAL ;
    PORT
      LAYER M5 ;
        RECT 289.390 249.900 289.414 250.000 ;
    END
  END rd[216]
  PIN rd[215]
    DIRECTION OUTPUT ;
    USE SIGNAL ;
    PORT
      LAYER M5 ;
        RECT 289.294 249.900 289.318 250.000 ;
    END
  END rd[215]
  PIN rd[214]
    DIRECTION OUTPUT ;
    USE SIGNAL ;
    PORT
      LAYER M5 ;
        RECT 289.198 249.900 289.222 250.000 ;
    END
  END rd[214]
  PIN rd[213]
    DIRECTION OUTPUT ;
    USE SIGNAL ;
    PORT
      LAYER M5 ;
        RECT 289.102 249.900 289.126 250.000 ;
    END
  END rd[213]
  PIN rd[212]
    DIRECTION OUTPUT ;
    USE SIGNAL ;
    PORT
      LAYER M5 ;
        RECT 289.006 249.900 289.030 250.000 ;
    END
  END rd[212]
  PIN rd[211]
    DIRECTION OUTPUT ;
    USE SIGNAL ;
    PORT
      LAYER M5 ;
        RECT 288.910 249.900 288.934 250.000 ;
    END
  END rd[211]
  PIN rd[210]
    DIRECTION OUTPUT ;
    USE SIGNAL ;
    PORT
      LAYER M5 ;
        RECT 288.814 249.900 288.838 250.000 ;
    END
  END rd[210]
  PIN rd[209]
    DIRECTION OUTPUT ;
    USE SIGNAL ;
    PORT
      LAYER M5 ;
        RECT 288.718 249.900 288.742 250.000 ;
    END
  END rd[209]
  PIN rd[208]
    DIRECTION OUTPUT ;
    USE SIGNAL ;
    PORT
      LAYER M5 ;
        RECT 288.622 249.900 288.646 250.000 ;
    END
  END rd[208]
  PIN rd[207]
    DIRECTION OUTPUT ;
    USE SIGNAL ;
    PORT
      LAYER M5 ;
        RECT 288.526 249.900 288.550 250.000 ;
    END
  END rd[207]
  PIN rd[206]
    DIRECTION OUTPUT ;
    USE SIGNAL ;
    PORT
      LAYER M5 ;
        RECT 288.430 249.900 288.454 250.000 ;
    END
  END rd[206]
  PIN rd[205]
    DIRECTION OUTPUT ;
    USE SIGNAL ;
    PORT
      LAYER M5 ;
        RECT 288.334 249.900 288.358 250.000 ;
    END
  END rd[205]
  PIN rd[204]
    DIRECTION OUTPUT ;
    USE SIGNAL ;
    PORT
      LAYER M5 ;
        RECT 288.238 249.900 288.262 250.000 ;
    END
  END rd[204]
  PIN rd[203]
    DIRECTION OUTPUT ;
    USE SIGNAL ;
    PORT
      LAYER M5 ;
        RECT 288.142 249.900 288.166 250.000 ;
    END
  END rd[203]
  PIN rd[202]
    DIRECTION OUTPUT ;
    USE SIGNAL ;
    PORT
      LAYER M5 ;
        RECT 288.046 249.900 288.070 250.000 ;
    END
  END rd[202]
  PIN rd[201]
    DIRECTION OUTPUT ;
    USE SIGNAL ;
    PORT
      LAYER M5 ;
        RECT 287.950 249.900 287.974 250.000 ;
    END
  END rd[201]
  PIN rd[200]
    DIRECTION OUTPUT ;
    USE SIGNAL ;
    PORT
      LAYER M5 ;
        RECT 287.854 249.900 287.878 250.000 ;
    END
  END rd[200]
  PIN rd[199]
    DIRECTION OUTPUT ;
    USE SIGNAL ;
    PORT
      LAYER M5 ;
        RECT 287.758 249.900 287.782 250.000 ;
    END
  END rd[199]
  PIN rd[198]
    DIRECTION OUTPUT ;
    USE SIGNAL ;
    PORT
      LAYER M5 ;
        RECT 287.662 249.900 287.686 250.000 ;
    END
  END rd[198]
  PIN rd[197]
    DIRECTION OUTPUT ;
    USE SIGNAL ;
    PORT
      LAYER M5 ;
        RECT 287.566 249.900 287.590 250.000 ;
    END
  END rd[197]
  PIN rd[196]
    DIRECTION OUTPUT ;
    USE SIGNAL ;
    PORT
      LAYER M5 ;
        RECT 287.470 249.900 287.494 250.000 ;
    END
  END rd[196]
  PIN rd[195]
    DIRECTION OUTPUT ;
    USE SIGNAL ;
    PORT
      LAYER M5 ;
        RECT 287.374 249.900 287.398 250.000 ;
    END
  END rd[195]
  PIN rd[194]
    DIRECTION OUTPUT ;
    USE SIGNAL ;
    PORT
      LAYER M5 ;
        RECT 287.278 249.900 287.302 250.000 ;
    END
  END rd[194]
  PIN rd[193]
    DIRECTION OUTPUT ;
    USE SIGNAL ;
    PORT
      LAYER M5 ;
        RECT 287.182 249.900 287.206 250.000 ;
    END
  END rd[193]
  PIN rd[192]
    DIRECTION OUTPUT ;
    USE SIGNAL ;
    PORT
      LAYER M5 ;
        RECT 287.086 249.900 287.110 250.000 ;
    END
  END rd[192]
  PIN rd[191]
    DIRECTION OUTPUT ;
    USE SIGNAL ;
    PORT
      LAYER M5 ;
        RECT 286.990 249.900 287.014 250.000 ;
    END
  END rd[191]
  PIN rd[190]
    DIRECTION OUTPUT ;
    USE SIGNAL ;
    PORT
      LAYER M5 ;
        RECT 286.894 249.900 286.918 250.000 ;
    END
  END rd[190]
  PIN rd[189]
    DIRECTION OUTPUT ;
    USE SIGNAL ;
    PORT
      LAYER M5 ;
        RECT 286.798 249.900 286.822 250.000 ;
    END
  END rd[189]
  PIN rd[188]
    DIRECTION OUTPUT ;
    USE SIGNAL ;
    PORT
      LAYER M5 ;
        RECT 286.702 249.900 286.726 250.000 ;
    END
  END rd[188]
  PIN rd[187]
    DIRECTION OUTPUT ;
    USE SIGNAL ;
    PORT
      LAYER M5 ;
        RECT 286.606 249.900 286.630 250.000 ;
    END
  END rd[187]
  PIN rd[186]
    DIRECTION OUTPUT ;
    USE SIGNAL ;
    PORT
      LAYER M5 ;
        RECT 286.510 249.900 286.534 250.000 ;
    END
  END rd[186]
  PIN rd[185]
    DIRECTION OUTPUT ;
    USE SIGNAL ;
    PORT
      LAYER M5 ;
        RECT 286.414 249.900 286.438 250.000 ;
    END
  END rd[185]
  PIN rd[184]
    DIRECTION OUTPUT ;
    USE SIGNAL ;
    PORT
      LAYER M5 ;
        RECT 286.318 249.900 286.342 250.000 ;
    END
  END rd[184]
  PIN rd[183]
    DIRECTION OUTPUT ;
    USE SIGNAL ;
    PORT
      LAYER M5 ;
        RECT 286.222 249.900 286.246 250.000 ;
    END
  END rd[183]
  PIN rd[182]
    DIRECTION OUTPUT ;
    USE SIGNAL ;
    PORT
      LAYER M5 ;
        RECT 286.126 249.900 286.150 250.000 ;
    END
  END rd[182]
  PIN rd[181]
    DIRECTION OUTPUT ;
    USE SIGNAL ;
    PORT
      LAYER M5 ;
        RECT 286.030 249.900 286.054 250.000 ;
    END
  END rd[181]
  PIN rd[180]
    DIRECTION OUTPUT ;
    USE SIGNAL ;
    PORT
      LAYER M5 ;
        RECT 285.934 249.900 285.958 250.000 ;
    END
  END rd[180]
  PIN rd[179]
    DIRECTION OUTPUT ;
    USE SIGNAL ;
    PORT
      LAYER M5 ;
        RECT 285.838 249.900 285.862 250.000 ;
    END
  END rd[179]
  PIN rd[178]
    DIRECTION OUTPUT ;
    USE SIGNAL ;
    PORT
      LAYER M5 ;
        RECT 285.742 249.900 285.766 250.000 ;
    END
  END rd[178]
  PIN rd[177]
    DIRECTION OUTPUT ;
    USE SIGNAL ;
    PORT
      LAYER M5 ;
        RECT 285.646 249.900 285.670 250.000 ;
    END
  END rd[177]
  PIN rd[176]
    DIRECTION OUTPUT ;
    USE SIGNAL ;
    PORT
      LAYER M5 ;
        RECT 285.550 249.900 285.574 250.000 ;
    END
  END rd[176]
  PIN rd[175]
    DIRECTION OUTPUT ;
    USE SIGNAL ;
    PORT
      LAYER M5 ;
        RECT 285.454 249.900 285.478 250.000 ;
    END
  END rd[175]
  PIN rd[174]
    DIRECTION OUTPUT ;
    USE SIGNAL ;
    PORT
      LAYER M5 ;
        RECT 285.358 249.900 285.382 250.000 ;
    END
  END rd[174]
  PIN rd[173]
    DIRECTION OUTPUT ;
    USE SIGNAL ;
    PORT
      LAYER M5 ;
        RECT 285.262 249.900 285.286 250.000 ;
    END
  END rd[173]
  PIN rd[172]
    DIRECTION OUTPUT ;
    USE SIGNAL ;
    PORT
      LAYER M5 ;
        RECT 285.166 249.900 285.190 250.000 ;
    END
  END rd[172]
  PIN rd[171]
    DIRECTION OUTPUT ;
    USE SIGNAL ;
    PORT
      LAYER M5 ;
        RECT 285.070 249.900 285.094 250.000 ;
    END
  END rd[171]
  PIN rd[170]
    DIRECTION OUTPUT ;
    USE SIGNAL ;
    PORT
      LAYER M5 ;
        RECT 284.974 249.900 284.998 250.000 ;
    END
  END rd[170]
  PIN rd[169]
    DIRECTION OUTPUT ;
    USE SIGNAL ;
    PORT
      LAYER M5 ;
        RECT 284.878 249.900 284.902 250.000 ;
    END
  END rd[169]
  PIN rd[168]
    DIRECTION OUTPUT ;
    USE SIGNAL ;
    PORT
      LAYER M5 ;
        RECT 284.782 249.900 284.806 250.000 ;
    END
  END rd[168]
  PIN rd[167]
    DIRECTION OUTPUT ;
    USE SIGNAL ;
    PORT
      LAYER M5 ;
        RECT 284.686 249.900 284.710 250.000 ;
    END
  END rd[167]
  PIN rd[166]
    DIRECTION OUTPUT ;
    USE SIGNAL ;
    PORT
      LAYER M5 ;
        RECT 284.590 249.900 284.614 250.000 ;
    END
  END rd[166]
  PIN rd[165]
    DIRECTION OUTPUT ;
    USE SIGNAL ;
    PORT
      LAYER M5 ;
        RECT 284.494 249.900 284.518 250.000 ;
    END
  END rd[165]
  PIN rd[164]
    DIRECTION OUTPUT ;
    USE SIGNAL ;
    PORT
      LAYER M5 ;
        RECT 284.398 249.900 284.422 250.000 ;
    END
  END rd[164]
  PIN rd[163]
    DIRECTION OUTPUT ;
    USE SIGNAL ;
    PORT
      LAYER M5 ;
        RECT 284.302 249.900 284.326 250.000 ;
    END
  END rd[163]
  PIN rd[162]
    DIRECTION OUTPUT ;
    USE SIGNAL ;
    PORT
      LAYER M5 ;
        RECT 284.206 249.900 284.230 250.000 ;
    END
  END rd[162]
  PIN rd[161]
    DIRECTION OUTPUT ;
    USE SIGNAL ;
    PORT
      LAYER M5 ;
        RECT 284.110 249.900 284.134 250.000 ;
    END
  END rd[161]
  PIN rd[160]
    DIRECTION OUTPUT ;
    USE SIGNAL ;
    PORT
      LAYER M5 ;
        RECT 284.014 249.900 284.038 250.000 ;
    END
  END rd[160]
  PIN rd[159]
    DIRECTION OUTPUT ;
    USE SIGNAL ;
    PORT
      LAYER M5 ;
        RECT 283.918 249.900 283.942 250.000 ;
    END
  END rd[159]
  PIN rd[158]
    DIRECTION OUTPUT ;
    USE SIGNAL ;
    PORT
      LAYER M5 ;
        RECT 283.822 249.900 283.846 250.000 ;
    END
  END rd[158]
  PIN rd[157]
    DIRECTION OUTPUT ;
    USE SIGNAL ;
    PORT
      LAYER M5 ;
        RECT 283.726 249.900 283.750 250.000 ;
    END
  END rd[157]
  PIN rd[156]
    DIRECTION OUTPUT ;
    USE SIGNAL ;
    PORT
      LAYER M5 ;
        RECT 283.630 249.900 283.654 250.000 ;
    END
  END rd[156]
  PIN rd[155]
    DIRECTION OUTPUT ;
    USE SIGNAL ;
    PORT
      LAYER M5 ;
        RECT 283.534 249.900 283.558 250.000 ;
    END
  END rd[155]
  PIN rd[154]
    DIRECTION OUTPUT ;
    USE SIGNAL ;
    PORT
      LAYER M5 ;
        RECT 283.438 249.900 283.462 250.000 ;
    END
  END rd[154]
  PIN rd[153]
    DIRECTION OUTPUT ;
    USE SIGNAL ;
    PORT
      LAYER M5 ;
        RECT 283.342 249.900 283.366 250.000 ;
    END
  END rd[153]
  PIN rd[152]
    DIRECTION OUTPUT ;
    USE SIGNAL ;
    PORT
      LAYER M5 ;
        RECT 283.246 249.900 283.270 250.000 ;
    END
  END rd[152]
  PIN rd[151]
    DIRECTION OUTPUT ;
    USE SIGNAL ;
    PORT
      LAYER M5 ;
        RECT 283.150 249.900 283.174 250.000 ;
    END
  END rd[151]
  PIN rd[150]
    DIRECTION OUTPUT ;
    USE SIGNAL ;
    PORT
      LAYER M5 ;
        RECT 283.054 249.900 283.078 250.000 ;
    END
  END rd[150]
  PIN rd[149]
    DIRECTION OUTPUT ;
    USE SIGNAL ;
    PORT
      LAYER M5 ;
        RECT 282.958 249.900 282.982 250.000 ;
    END
  END rd[149]
  PIN rd[148]
    DIRECTION OUTPUT ;
    USE SIGNAL ;
    PORT
      LAYER M5 ;
        RECT 282.862 249.900 282.886 250.000 ;
    END
  END rd[148]
  PIN rd[147]
    DIRECTION OUTPUT ;
    USE SIGNAL ;
    PORT
      LAYER M5 ;
        RECT 282.766 249.900 282.790 250.000 ;
    END
  END rd[147]
  PIN rd[146]
    DIRECTION OUTPUT ;
    USE SIGNAL ;
    PORT
      LAYER M5 ;
        RECT 282.670 249.900 282.694 250.000 ;
    END
  END rd[146]
  PIN rd[145]
    DIRECTION OUTPUT ;
    USE SIGNAL ;
    PORT
      LAYER M5 ;
        RECT 282.574 249.900 282.598 250.000 ;
    END
  END rd[145]
  PIN rd[144]
    DIRECTION OUTPUT ;
    USE SIGNAL ;
    PORT
      LAYER M5 ;
        RECT 282.478 249.900 282.502 250.000 ;
    END
  END rd[144]
  PIN rd[143]
    DIRECTION OUTPUT ;
    USE SIGNAL ;
    PORT
      LAYER M5 ;
        RECT 282.382 249.900 282.406 250.000 ;
    END
  END rd[143]
  PIN rd[142]
    DIRECTION OUTPUT ;
    USE SIGNAL ;
    PORT
      LAYER M5 ;
        RECT 282.286 249.900 282.310 250.000 ;
    END
  END rd[142]
  PIN rd[141]
    DIRECTION OUTPUT ;
    USE SIGNAL ;
    PORT
      LAYER M5 ;
        RECT 282.190 249.900 282.214 250.000 ;
    END
  END rd[141]
  PIN rd[140]
    DIRECTION OUTPUT ;
    USE SIGNAL ;
    PORT
      LAYER M5 ;
        RECT 282.094 249.900 282.118 250.000 ;
    END
  END rd[140]
  PIN rd[139]
    DIRECTION OUTPUT ;
    USE SIGNAL ;
    PORT
      LAYER M5 ;
        RECT 281.998 249.900 282.022 250.000 ;
    END
  END rd[139]
  PIN rd[138]
    DIRECTION OUTPUT ;
    USE SIGNAL ;
    PORT
      LAYER M5 ;
        RECT 281.902 249.900 281.926 250.000 ;
    END
  END rd[138]
  PIN rd[137]
    DIRECTION OUTPUT ;
    USE SIGNAL ;
    PORT
      LAYER M5 ;
        RECT 281.806 249.900 281.830 250.000 ;
    END
  END rd[137]
  PIN rd[136]
    DIRECTION OUTPUT ;
    USE SIGNAL ;
    PORT
      LAYER M5 ;
        RECT 281.710 249.900 281.734 250.000 ;
    END
  END rd[136]
  PIN rd[135]
    DIRECTION OUTPUT ;
    USE SIGNAL ;
    PORT
      LAYER M5 ;
        RECT 281.614 249.900 281.638 250.000 ;
    END
  END rd[135]
  PIN rd[134]
    DIRECTION OUTPUT ;
    USE SIGNAL ;
    PORT
      LAYER M5 ;
        RECT 281.518 249.900 281.542 250.000 ;
    END
  END rd[134]
  PIN rd[133]
    DIRECTION OUTPUT ;
    USE SIGNAL ;
    PORT
      LAYER M5 ;
        RECT 281.422 249.900 281.446 250.000 ;
    END
  END rd[133]
  PIN rd[132]
    DIRECTION OUTPUT ;
    USE SIGNAL ;
    PORT
      LAYER M5 ;
        RECT 281.326 249.900 281.350 250.000 ;
    END
  END rd[132]
  PIN rd[131]
    DIRECTION OUTPUT ;
    USE SIGNAL ;
    PORT
      LAYER M5 ;
        RECT 281.230 249.900 281.254 250.000 ;
    END
  END rd[131]
  PIN rd[130]
    DIRECTION OUTPUT ;
    USE SIGNAL ;
    PORT
      LAYER M5 ;
        RECT 281.134 249.900 281.158 250.000 ;
    END
  END rd[130]
  PIN rd[129]
    DIRECTION OUTPUT ;
    USE SIGNAL ;
    PORT
      LAYER M5 ;
        RECT 281.038 249.900 281.062 250.000 ;
    END
  END rd[129]
  PIN rd[128]
    DIRECTION OUTPUT ;
    USE SIGNAL ;
    PORT
      LAYER M5 ;
        RECT 280.942 249.900 280.966 250.000 ;
    END
  END rd[128]
  PIN rd[127]
    DIRECTION OUTPUT ;
    USE SIGNAL ;
    PORT
      LAYER M5 ;
        RECT 280.846 249.900 280.870 250.000 ;
    END
  END rd[127]
  PIN rd[126]
    DIRECTION OUTPUT ;
    USE SIGNAL ;
    PORT
      LAYER M5 ;
        RECT 280.750 249.900 280.774 250.000 ;
    END
  END rd[126]
  PIN rd[125]
    DIRECTION OUTPUT ;
    USE SIGNAL ;
    PORT
      LAYER M5 ;
        RECT 280.654 249.900 280.678 250.000 ;
    END
  END rd[125]
  PIN rd[124]
    DIRECTION OUTPUT ;
    USE SIGNAL ;
    PORT
      LAYER M5 ;
        RECT 280.558 249.900 280.582 250.000 ;
    END
  END rd[124]
  PIN rd[123]
    DIRECTION OUTPUT ;
    USE SIGNAL ;
    PORT
      LAYER M5 ;
        RECT 280.462 249.900 280.486 250.000 ;
    END
  END rd[123]
  PIN rd[122]
    DIRECTION OUTPUT ;
    USE SIGNAL ;
    PORT
      LAYER M5 ;
        RECT 280.366 249.900 280.390 250.000 ;
    END
  END rd[122]
  PIN rd[121]
    DIRECTION OUTPUT ;
    USE SIGNAL ;
    PORT
      LAYER M5 ;
        RECT 280.270 249.900 280.294 250.000 ;
    END
  END rd[121]
  PIN rd[120]
    DIRECTION OUTPUT ;
    USE SIGNAL ;
    PORT
      LAYER M5 ;
        RECT 280.174 249.900 280.198 250.000 ;
    END
  END rd[120]
  PIN rd[119]
    DIRECTION OUTPUT ;
    USE SIGNAL ;
    PORT
      LAYER M5 ;
        RECT 280.078 249.900 280.102 250.000 ;
    END
  END rd[119]
  PIN rd[118]
    DIRECTION OUTPUT ;
    USE SIGNAL ;
    PORT
      LAYER M5 ;
        RECT 279.982 249.900 280.006 250.000 ;
    END
  END rd[118]
  PIN rd[117]
    DIRECTION OUTPUT ;
    USE SIGNAL ;
    PORT
      LAYER M5 ;
        RECT 279.886 249.900 279.910 250.000 ;
    END
  END rd[117]
  PIN rd[116]
    DIRECTION OUTPUT ;
    USE SIGNAL ;
    PORT
      LAYER M5 ;
        RECT 279.790 249.900 279.814 250.000 ;
    END
  END rd[116]
  PIN rd[115]
    DIRECTION OUTPUT ;
    USE SIGNAL ;
    PORT
      LAYER M5 ;
        RECT 279.694 249.900 279.718 250.000 ;
    END
  END rd[115]
  PIN rd[114]
    DIRECTION OUTPUT ;
    USE SIGNAL ;
    PORT
      LAYER M5 ;
        RECT 279.598 249.900 279.622 250.000 ;
    END
  END rd[114]
  PIN rd[113]
    DIRECTION OUTPUT ;
    USE SIGNAL ;
    PORT
      LAYER M5 ;
        RECT 279.502 249.900 279.526 250.000 ;
    END
  END rd[113]
  PIN rd[112]
    DIRECTION OUTPUT ;
    USE SIGNAL ;
    PORT
      LAYER M5 ;
        RECT 279.406 249.900 279.430 250.000 ;
    END
  END rd[112]
  PIN rd[111]
    DIRECTION OUTPUT ;
    USE SIGNAL ;
    PORT
      LAYER M5 ;
        RECT 279.310 249.900 279.334 250.000 ;
    END
  END rd[111]
  PIN rd[110]
    DIRECTION OUTPUT ;
    USE SIGNAL ;
    PORT
      LAYER M5 ;
        RECT 279.214 249.900 279.238 250.000 ;
    END
  END rd[110]
  PIN rd[109]
    DIRECTION OUTPUT ;
    USE SIGNAL ;
    PORT
      LAYER M5 ;
        RECT 279.118 249.900 279.142 250.000 ;
    END
  END rd[109]
  PIN rd[108]
    DIRECTION OUTPUT ;
    USE SIGNAL ;
    PORT
      LAYER M5 ;
        RECT 279.022 249.900 279.046 250.000 ;
    END
  END rd[108]
  PIN rd[107]
    DIRECTION OUTPUT ;
    USE SIGNAL ;
    PORT
      LAYER M5 ;
        RECT 278.926 249.900 278.950 250.000 ;
    END
  END rd[107]
  PIN rd[106]
    DIRECTION OUTPUT ;
    USE SIGNAL ;
    PORT
      LAYER M5 ;
        RECT 278.830 249.900 278.854 250.000 ;
    END
  END rd[106]
  PIN rd[105]
    DIRECTION OUTPUT ;
    USE SIGNAL ;
    PORT
      LAYER M5 ;
        RECT 278.734 249.900 278.758 250.000 ;
    END
  END rd[105]
  PIN rd[104]
    DIRECTION OUTPUT ;
    USE SIGNAL ;
    PORT
      LAYER M5 ;
        RECT 278.638 249.900 278.662 250.000 ;
    END
  END rd[104]
  PIN rd[103]
    DIRECTION OUTPUT ;
    USE SIGNAL ;
    PORT
      LAYER M5 ;
        RECT 278.542 249.900 278.566 250.000 ;
    END
  END rd[103]
  PIN rd[102]
    DIRECTION OUTPUT ;
    USE SIGNAL ;
    PORT
      LAYER M5 ;
        RECT 278.446 249.900 278.470 250.000 ;
    END
  END rd[102]
  PIN rd[101]
    DIRECTION OUTPUT ;
    USE SIGNAL ;
    PORT
      LAYER M5 ;
        RECT 278.350 249.900 278.374 250.000 ;
    END
  END rd[101]
  PIN rd[100]
    DIRECTION OUTPUT ;
    USE SIGNAL ;
    PORT
      LAYER M5 ;
        RECT 278.254 249.900 278.278 250.000 ;
    END
  END rd[100]
  PIN rd[99]
    DIRECTION OUTPUT ;
    USE SIGNAL ;
    PORT
      LAYER M5 ;
        RECT 278.158 249.900 278.182 250.000 ;
    END
  END rd[99]
  PIN rd[98]
    DIRECTION OUTPUT ;
    USE SIGNAL ;
    PORT
      LAYER M5 ;
        RECT 278.062 249.900 278.086 250.000 ;
    END
  END rd[98]
  PIN rd[97]
    DIRECTION OUTPUT ;
    USE SIGNAL ;
    PORT
      LAYER M5 ;
        RECT 277.966 249.900 277.990 250.000 ;
    END
  END rd[97]
  PIN rd[96]
    DIRECTION OUTPUT ;
    USE SIGNAL ;
    PORT
      LAYER M5 ;
        RECT 277.870 249.900 277.894 250.000 ;
    END
  END rd[96]
  PIN rd[95]
    DIRECTION OUTPUT ;
    USE SIGNAL ;
    PORT
      LAYER M5 ;
        RECT 277.774 249.900 277.798 250.000 ;
    END
  END rd[95]
  PIN rd[94]
    DIRECTION OUTPUT ;
    USE SIGNAL ;
    PORT
      LAYER M5 ;
        RECT 277.678 249.900 277.702 250.000 ;
    END
  END rd[94]
  PIN rd[93]
    DIRECTION OUTPUT ;
    USE SIGNAL ;
    PORT
      LAYER M5 ;
        RECT 277.582 249.900 277.606 250.000 ;
    END
  END rd[93]
  PIN rd[92]
    DIRECTION OUTPUT ;
    USE SIGNAL ;
    PORT
      LAYER M5 ;
        RECT 277.486 249.900 277.510 250.000 ;
    END
  END rd[92]
  PIN rd[91]
    DIRECTION OUTPUT ;
    USE SIGNAL ;
    PORT
      LAYER M5 ;
        RECT 277.390 249.900 277.414 250.000 ;
    END
  END rd[91]
  PIN rd[90]
    DIRECTION OUTPUT ;
    USE SIGNAL ;
    PORT
      LAYER M5 ;
        RECT 277.294 249.900 277.318 250.000 ;
    END
  END rd[90]
  PIN rd[89]
    DIRECTION OUTPUT ;
    USE SIGNAL ;
    PORT
      LAYER M5 ;
        RECT 277.198 249.900 277.222 250.000 ;
    END
  END rd[89]
  PIN rd[88]
    DIRECTION OUTPUT ;
    USE SIGNAL ;
    PORT
      LAYER M5 ;
        RECT 277.102 249.900 277.126 250.000 ;
    END
  END rd[88]
  PIN rd[87]
    DIRECTION OUTPUT ;
    USE SIGNAL ;
    PORT
      LAYER M5 ;
        RECT 277.006 249.900 277.030 250.000 ;
    END
  END rd[87]
  PIN rd[86]
    DIRECTION OUTPUT ;
    USE SIGNAL ;
    PORT
      LAYER M5 ;
        RECT 276.910 249.900 276.934 250.000 ;
    END
  END rd[86]
  PIN rd[85]
    DIRECTION OUTPUT ;
    USE SIGNAL ;
    PORT
      LAYER M5 ;
        RECT 276.814 249.900 276.838 250.000 ;
    END
  END rd[85]
  PIN rd[84]
    DIRECTION OUTPUT ;
    USE SIGNAL ;
    PORT
      LAYER M5 ;
        RECT 276.718 249.900 276.742 250.000 ;
    END
  END rd[84]
  PIN rd[83]
    DIRECTION OUTPUT ;
    USE SIGNAL ;
    PORT
      LAYER M5 ;
        RECT 276.622 249.900 276.646 250.000 ;
    END
  END rd[83]
  PIN rd[82]
    DIRECTION OUTPUT ;
    USE SIGNAL ;
    PORT
      LAYER M5 ;
        RECT 276.526 249.900 276.550 250.000 ;
    END
  END rd[82]
  PIN rd[81]
    DIRECTION OUTPUT ;
    USE SIGNAL ;
    PORT
      LAYER M5 ;
        RECT 276.430 249.900 276.454 250.000 ;
    END
  END rd[81]
  PIN rd[80]
    DIRECTION OUTPUT ;
    USE SIGNAL ;
    PORT
      LAYER M5 ;
        RECT 276.334 249.900 276.358 250.000 ;
    END
  END rd[80]
  PIN rd[79]
    DIRECTION OUTPUT ;
    USE SIGNAL ;
    PORT
      LAYER M5 ;
        RECT 276.238 249.900 276.262 250.000 ;
    END
  END rd[79]
  PIN rd[78]
    DIRECTION OUTPUT ;
    USE SIGNAL ;
    PORT
      LAYER M5 ;
        RECT 276.142 249.900 276.166 250.000 ;
    END
  END rd[78]
  PIN rd[77]
    DIRECTION OUTPUT ;
    USE SIGNAL ;
    PORT
      LAYER M5 ;
        RECT 276.046 249.900 276.070 250.000 ;
    END
  END rd[77]
  PIN rd[76]
    DIRECTION OUTPUT ;
    USE SIGNAL ;
    PORT
      LAYER M5 ;
        RECT 275.950 249.900 275.974 250.000 ;
    END
  END rd[76]
  PIN rd[75]
    DIRECTION OUTPUT ;
    USE SIGNAL ;
    PORT
      LAYER M5 ;
        RECT 275.854 249.900 275.878 250.000 ;
    END
  END rd[75]
  PIN rd[74]
    DIRECTION OUTPUT ;
    USE SIGNAL ;
    PORT
      LAYER M5 ;
        RECT 275.758 249.900 275.782 250.000 ;
    END
  END rd[74]
  PIN rd[73]
    DIRECTION OUTPUT ;
    USE SIGNAL ;
    PORT
      LAYER M5 ;
        RECT 275.662 249.900 275.686 250.000 ;
    END
  END rd[73]
  PIN rd[72]
    DIRECTION OUTPUT ;
    USE SIGNAL ;
    PORT
      LAYER M5 ;
        RECT 275.566 249.900 275.590 250.000 ;
    END
  END rd[72]
  PIN rd[71]
    DIRECTION OUTPUT ;
    USE SIGNAL ;
    PORT
      LAYER M5 ;
        RECT 275.470 249.900 275.494 250.000 ;
    END
  END rd[71]
  PIN rd[70]
    DIRECTION OUTPUT ;
    USE SIGNAL ;
    PORT
      LAYER M5 ;
        RECT 275.374 249.900 275.398 250.000 ;
    END
  END rd[70]
  PIN rd[69]
    DIRECTION OUTPUT ;
    USE SIGNAL ;
    PORT
      LAYER M5 ;
        RECT 275.278 249.900 275.302 250.000 ;
    END
  END rd[69]
  PIN rd[68]
    DIRECTION OUTPUT ;
    USE SIGNAL ;
    PORT
      LAYER M5 ;
        RECT 275.182 249.900 275.206 250.000 ;
    END
  END rd[68]
  PIN rd[67]
    DIRECTION OUTPUT ;
    USE SIGNAL ;
    PORT
      LAYER M5 ;
        RECT 275.086 249.900 275.110 250.000 ;
    END
  END rd[67]
  PIN rd[66]
    DIRECTION OUTPUT ;
    USE SIGNAL ;
    PORT
      LAYER M5 ;
        RECT 274.990 249.900 275.014 250.000 ;
    END
  END rd[66]
  PIN rd[65]
    DIRECTION OUTPUT ;
    USE SIGNAL ;
    PORT
      LAYER M5 ;
        RECT 274.894 249.900 274.918 250.000 ;
    END
  END rd[65]
  PIN rd[64]
    DIRECTION OUTPUT ;
    USE SIGNAL ;
    PORT
      LAYER M5 ;
        RECT 274.798 249.900 274.822 250.000 ;
    END
  END rd[64]
  PIN rd[63]
    DIRECTION OUTPUT ;
    USE SIGNAL ;
    PORT
      LAYER M5 ;
        RECT 274.702 249.900 274.726 250.000 ;
    END
  END rd[63]
  PIN rd[62]
    DIRECTION OUTPUT ;
    USE SIGNAL ;
    PORT
      LAYER M5 ;
        RECT 274.606 249.900 274.630 250.000 ;
    END
  END rd[62]
  PIN rd[61]
    DIRECTION OUTPUT ;
    USE SIGNAL ;
    PORT
      LAYER M5 ;
        RECT 274.510 249.900 274.534 250.000 ;
    END
  END rd[61]
  PIN rd[60]
    DIRECTION OUTPUT ;
    USE SIGNAL ;
    PORT
      LAYER M5 ;
        RECT 274.414 249.900 274.438 250.000 ;
    END
  END rd[60]
  PIN rd[59]
    DIRECTION OUTPUT ;
    USE SIGNAL ;
    PORT
      LAYER M5 ;
        RECT 274.318 249.900 274.342 250.000 ;
    END
  END rd[59]
  PIN rd[58]
    DIRECTION OUTPUT ;
    USE SIGNAL ;
    PORT
      LAYER M5 ;
        RECT 274.222 249.900 274.246 250.000 ;
    END
  END rd[58]
  PIN rd[57]
    DIRECTION OUTPUT ;
    USE SIGNAL ;
    PORT
      LAYER M5 ;
        RECT 274.126 249.900 274.150 250.000 ;
    END
  END rd[57]
  PIN rd[56]
    DIRECTION OUTPUT ;
    USE SIGNAL ;
    PORT
      LAYER M5 ;
        RECT 274.030 249.900 274.054 250.000 ;
    END
  END rd[56]
  PIN rd[55]
    DIRECTION OUTPUT ;
    USE SIGNAL ;
    PORT
      LAYER M5 ;
        RECT 273.934 249.900 273.958 250.000 ;
    END
  END rd[55]
  PIN rd[54]
    DIRECTION OUTPUT ;
    USE SIGNAL ;
    PORT
      LAYER M5 ;
        RECT 273.838 249.900 273.862 250.000 ;
    END
  END rd[54]
  PIN rd[53]
    DIRECTION OUTPUT ;
    USE SIGNAL ;
    PORT
      LAYER M5 ;
        RECT 273.742 249.900 273.766 250.000 ;
    END
  END rd[53]
  PIN rd[52]
    DIRECTION OUTPUT ;
    USE SIGNAL ;
    PORT
      LAYER M5 ;
        RECT 273.646 249.900 273.670 250.000 ;
    END
  END rd[52]
  PIN rd[51]
    DIRECTION OUTPUT ;
    USE SIGNAL ;
    PORT
      LAYER M5 ;
        RECT 273.550 249.900 273.574 250.000 ;
    END
  END rd[51]
  PIN rd[50]
    DIRECTION OUTPUT ;
    USE SIGNAL ;
    PORT
      LAYER M5 ;
        RECT 273.454 249.900 273.478 250.000 ;
    END
  END rd[50]
  PIN rd[49]
    DIRECTION OUTPUT ;
    USE SIGNAL ;
    PORT
      LAYER M5 ;
        RECT 273.358 249.900 273.382 250.000 ;
    END
  END rd[49]
  PIN rd[48]
    DIRECTION OUTPUT ;
    USE SIGNAL ;
    PORT
      LAYER M5 ;
        RECT 273.262 249.900 273.286 250.000 ;
    END
  END rd[48]
  PIN rd[47]
    DIRECTION OUTPUT ;
    USE SIGNAL ;
    PORT
      LAYER M5 ;
        RECT 273.166 249.900 273.190 250.000 ;
    END
  END rd[47]
  PIN rd[46]
    DIRECTION OUTPUT ;
    USE SIGNAL ;
    PORT
      LAYER M5 ;
        RECT 273.070 249.900 273.094 250.000 ;
    END
  END rd[46]
  PIN rd[45]
    DIRECTION OUTPUT ;
    USE SIGNAL ;
    PORT
      LAYER M5 ;
        RECT 272.974 249.900 272.998 250.000 ;
    END
  END rd[45]
  PIN rd[44]
    DIRECTION OUTPUT ;
    USE SIGNAL ;
    PORT
      LAYER M5 ;
        RECT 272.878 249.900 272.902 250.000 ;
    END
  END rd[44]
  PIN rd[43]
    DIRECTION OUTPUT ;
    USE SIGNAL ;
    PORT
      LAYER M5 ;
        RECT 272.782 249.900 272.806 250.000 ;
    END
  END rd[43]
  PIN rd[42]
    DIRECTION OUTPUT ;
    USE SIGNAL ;
    PORT
      LAYER M5 ;
        RECT 272.686 249.900 272.710 250.000 ;
    END
  END rd[42]
  PIN rd[41]
    DIRECTION OUTPUT ;
    USE SIGNAL ;
    PORT
      LAYER M5 ;
        RECT 272.590 249.900 272.614 250.000 ;
    END
  END rd[41]
  PIN rd[40]
    DIRECTION OUTPUT ;
    USE SIGNAL ;
    PORT
      LAYER M5 ;
        RECT 272.494 249.900 272.518 250.000 ;
    END
  END rd[40]
  PIN rd[39]
    DIRECTION OUTPUT ;
    USE SIGNAL ;
    PORT
      LAYER M5 ;
        RECT 272.398 249.900 272.422 250.000 ;
    END
  END rd[39]
  PIN rd[38]
    DIRECTION OUTPUT ;
    USE SIGNAL ;
    PORT
      LAYER M5 ;
        RECT 272.302 249.900 272.326 250.000 ;
    END
  END rd[38]
  PIN rd[37]
    DIRECTION OUTPUT ;
    USE SIGNAL ;
    PORT
      LAYER M5 ;
        RECT 272.206 249.900 272.230 250.000 ;
    END
  END rd[37]
  PIN rd[36]
    DIRECTION OUTPUT ;
    USE SIGNAL ;
    PORT
      LAYER M5 ;
        RECT 272.110 249.900 272.134 250.000 ;
    END
  END rd[36]
  PIN rd[35]
    DIRECTION OUTPUT ;
    USE SIGNAL ;
    PORT
      LAYER M5 ;
        RECT 272.014 249.900 272.038 250.000 ;
    END
  END rd[35]
  PIN rd[34]
    DIRECTION OUTPUT ;
    USE SIGNAL ;
    PORT
      LAYER M5 ;
        RECT 271.918 249.900 271.942 250.000 ;
    END
  END rd[34]
  PIN rd[33]
    DIRECTION OUTPUT ;
    USE SIGNAL ;
    PORT
      LAYER M5 ;
        RECT 271.822 249.900 271.846 250.000 ;
    END
  END rd[33]
  PIN rd[32]
    DIRECTION OUTPUT ;
    USE SIGNAL ;
    PORT
      LAYER M5 ;
        RECT 271.726 249.900 271.750 250.000 ;
    END
  END rd[32]
  PIN rd[31]
    DIRECTION OUTPUT ;
    USE SIGNAL ;
    PORT
      LAYER M5 ;
        RECT 271.630 249.900 271.654 250.000 ;
    END
  END rd[31]
  PIN rd[30]
    DIRECTION OUTPUT ;
    USE SIGNAL ;
    PORT
      LAYER M5 ;
        RECT 271.534 249.900 271.558 250.000 ;
    END
  END rd[30]
  PIN rd[29]
    DIRECTION OUTPUT ;
    USE SIGNAL ;
    PORT
      LAYER M5 ;
        RECT 271.438 249.900 271.462 250.000 ;
    END
  END rd[29]
  PIN rd[28]
    DIRECTION OUTPUT ;
    USE SIGNAL ;
    PORT
      LAYER M5 ;
        RECT 271.342 249.900 271.366 250.000 ;
    END
  END rd[28]
  PIN rd[27]
    DIRECTION OUTPUT ;
    USE SIGNAL ;
    PORT
      LAYER M5 ;
        RECT 271.246 249.900 271.270 250.000 ;
    END
  END rd[27]
  PIN rd[26]
    DIRECTION OUTPUT ;
    USE SIGNAL ;
    PORT
      LAYER M5 ;
        RECT 271.150 249.900 271.174 250.000 ;
    END
  END rd[26]
  PIN rd[25]
    DIRECTION OUTPUT ;
    USE SIGNAL ;
    PORT
      LAYER M5 ;
        RECT 271.054 249.900 271.078 250.000 ;
    END
  END rd[25]
  PIN rd[24]
    DIRECTION OUTPUT ;
    USE SIGNAL ;
    PORT
      LAYER M5 ;
        RECT 270.958 249.900 270.982 250.000 ;
    END
  END rd[24]
  PIN rd[23]
    DIRECTION OUTPUT ;
    USE SIGNAL ;
    PORT
      LAYER M5 ;
        RECT 270.862 249.900 270.886 250.000 ;
    END
  END rd[23]
  PIN rd[22]
    DIRECTION OUTPUT ;
    USE SIGNAL ;
    PORT
      LAYER M5 ;
        RECT 270.766 249.900 270.790 250.000 ;
    END
  END rd[22]
  PIN rd[21]
    DIRECTION OUTPUT ;
    USE SIGNAL ;
    PORT
      LAYER M5 ;
        RECT 270.670 249.900 270.694 250.000 ;
    END
  END rd[21]
  PIN rd[20]
    DIRECTION OUTPUT ;
    USE SIGNAL ;
    PORT
      LAYER M5 ;
        RECT 270.574 249.900 270.598 250.000 ;
    END
  END rd[20]
  PIN rd[19]
    DIRECTION OUTPUT ;
    USE SIGNAL ;
    PORT
      LAYER M5 ;
        RECT 270.478 249.900 270.502 250.000 ;
    END
  END rd[19]
  PIN rd[18]
    DIRECTION OUTPUT ;
    USE SIGNAL ;
    PORT
      LAYER M5 ;
        RECT 270.382 249.900 270.406 250.000 ;
    END
  END rd[18]
  PIN rd[17]
    DIRECTION OUTPUT ;
    USE SIGNAL ;
    PORT
      LAYER M5 ;
        RECT 270.286 249.900 270.310 250.000 ;
    END
  END rd[17]
  PIN rd[16]
    DIRECTION OUTPUT ;
    USE SIGNAL ;
    PORT
      LAYER M5 ;
        RECT 270.190 249.900 270.214 250.000 ;
    END
  END rd[16]
  PIN rd[15]
    DIRECTION OUTPUT ;
    USE SIGNAL ;
    PORT
      LAYER M5 ;
        RECT 270.094 249.900 270.118 250.000 ;
    END
  END rd[15]
  PIN rd[14]
    DIRECTION OUTPUT ;
    USE SIGNAL ;
    PORT
      LAYER M5 ;
        RECT 269.998 249.900 270.022 250.000 ;
    END
  END rd[14]
  PIN rd[13]
    DIRECTION OUTPUT ;
    USE SIGNAL ;
    PORT
      LAYER M5 ;
        RECT 269.902 249.900 269.926 250.000 ;
    END
  END rd[13]
  PIN rd[12]
    DIRECTION OUTPUT ;
    USE SIGNAL ;
    PORT
      LAYER M5 ;
        RECT 269.806 249.900 269.830 250.000 ;
    END
  END rd[12]
  PIN rd[11]
    DIRECTION OUTPUT ;
    USE SIGNAL ;
    PORT
      LAYER M5 ;
        RECT 269.710 249.900 269.734 250.000 ;
    END
  END rd[11]
  PIN rd[10]
    DIRECTION OUTPUT ;
    USE SIGNAL ;
    PORT
      LAYER M5 ;
        RECT 269.614 249.900 269.638 250.000 ;
    END
  END rd[10]
  PIN rd[9]
    DIRECTION OUTPUT ;
    USE SIGNAL ;
    PORT
      LAYER M5 ;
        RECT 269.518 249.900 269.542 250.000 ;
    END
  END rd[9]
  PIN rd[8]
    DIRECTION OUTPUT ;
    USE SIGNAL ;
    PORT
      LAYER M5 ;
        RECT 269.422 249.900 269.446 250.000 ;
    END
  END rd[8]
  PIN rd[7]
    DIRECTION OUTPUT ;
    USE SIGNAL ;
    PORT
      LAYER M5 ;
        RECT 269.326 249.900 269.350 250.000 ;
    END
  END rd[7]
  PIN rd[6]
    DIRECTION OUTPUT ;
    USE SIGNAL ;
    PORT
      LAYER M5 ;
        RECT 269.230 249.900 269.254 250.000 ;
    END
  END rd[6]
  PIN rd[5]
    DIRECTION OUTPUT ;
    USE SIGNAL ;
    PORT
      LAYER M5 ;
        RECT 269.134 249.900 269.158 250.000 ;
    END
  END rd[5]
  PIN rd[4]
    DIRECTION OUTPUT ;
    USE SIGNAL ;
    PORT
      LAYER M5 ;
        RECT 269.038 249.900 269.062 250.000 ;
    END
  END rd[4]
  PIN rd[3]
    DIRECTION OUTPUT ;
    USE SIGNAL ;
    PORT
      LAYER M5 ;
        RECT 268.942 249.900 268.966 250.000 ;
    END
  END rd[3]
  PIN rd[2]
    DIRECTION OUTPUT ;
    USE SIGNAL ;
    PORT
      LAYER M5 ;
        RECT 268.846 249.900 268.870 250.000 ;
    END
  END rd[2]
  PIN rd[1]
    DIRECTION OUTPUT ;
    USE SIGNAL ;
    PORT
      LAYER M5 ;
        RECT 268.750 249.900 268.774 250.000 ;
    END
  END rd[1]
  PIN rd[0]
    DIRECTION OUTPUT ;
    USE SIGNAL ;
    PORT
      LAYER M5 ;
        RECT 268.654 249.900 268.678 250.000 ;
    END
  END rd[0]
  PIN ck_o
    DIRECTION OUTPUT ;
    USE SIGNAL ;
    PORT
      LAYER M5 ;
        RECT 292.301 249.900 292.325 250.000 ;
    END
  END ck_o
  OBS
    LAYER M1 ;
      RECT 0.2 0.2 531.050 249.800 ;
    LAYER M2 ;
      RECT 0.2 0.2 531.050 249.800 ;
    LAYER M3 ;
      RECT 0.2 0.2 531.050 249.800 ;
    LAYER M4 ;
      RECT 0.200 0.200 199.894 249.800 ;
      RECT 199.894 0.200 262.613 247.000 ;
      RECT 262.613 3.000 269.021 247.000 ;
      RECT 269.021 0.200 325.534 247.000 ;
      RECT 325.534 0.200 528.250 249.800 ;
      RECT 528.250 0.200 531.050 55.265 ;
      RECT 528.250 110.345 531.050 249.800 ;
    LAYER M5 ;
      RECT 0.200 0.200 199.894 249.800 ;
      RECT 199.894 0.200 262.613 247.000 ;
      RECT 262.613 3.000 269.021 247.000 ;
      RECT 269.021 0.200 325.534 247.000 ;
      RECT 325.534 0.200 528.250 249.800 ;
      RECT 528.250 0.200 531.050 55.265 ;
      RECT 528.250 110.345 531.050 249.800 ;
    LAYER M6 ;
      RECT 0.200 0.200 199.894 249.800 ;
      RECT 199.894 0.200 262.613 247.000 ;
      RECT 262.613 3.000 269.021 247.000 ;
      RECT 269.021 0.200 325.534 247.000 ;
      RECT 325.534 0.200 528.250 249.800 ;
      RECT 528.250 0.200 531.050 55.265 ;
      RECT 528.250 110.345 531.050 249.800 ;
  END
END rv_ctrl_07
END LIBRARY
